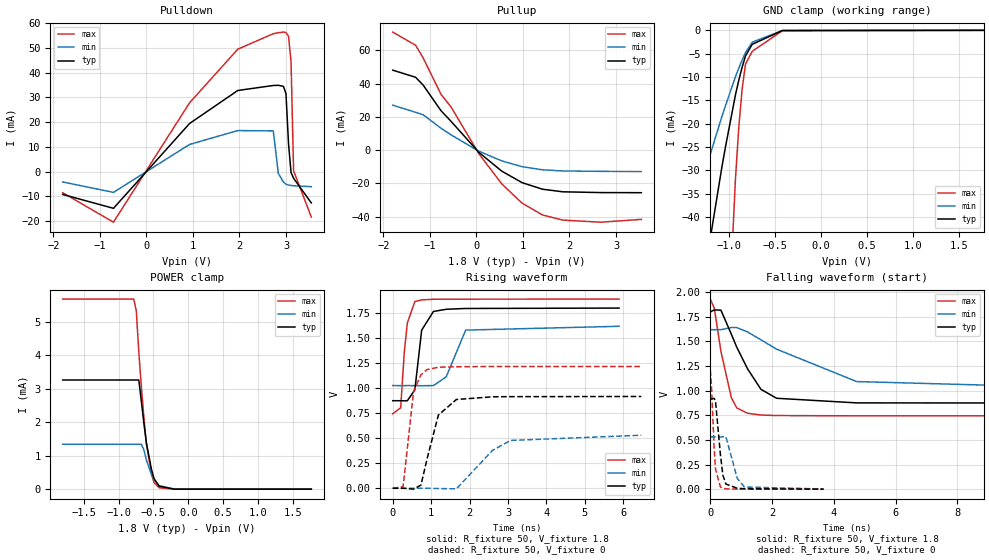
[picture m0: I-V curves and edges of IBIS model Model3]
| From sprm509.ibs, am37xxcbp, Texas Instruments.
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| Model based on original model for BQ18OMAPJTAGFBPBNOPM_SSBHV
|   Sub model FBPBNOPM_VJTAG_PUPD0_1P8
[model]   Model3
|[Input Load]   PI
|[Output Drive]
|Voltage   1.8V
|Mode   I/O
Model_type   I/O
Polarity   Non-Inverting
Enable   Active-Low
Vinl =  0.63
Vinh =  1.17
Cref =  15pF
Rref =  100.0000M
Vref =  0V
Vmeas =  0.9
C_comp   2.132351p   1.924211p   2.13513p
[Model Spec]
Vinl   0.63   0.567   0.6615
Vinh   1.17   1.053   1.2285
[Temperature Range]   25   125   -40
[Voltage Range]   1.8   1.62   1.89
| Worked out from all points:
|   slope of the pulldown table from 0 to 0.27 V, typ, clamps not added: 43.9 ohm
|   slope of the pullup table from 0 to 0.27 V, typ, clamps not added: 39.4 ohm
|   GND clamp passes 1 mA (typ) near -0.61 V on its own axis
|   POWER clamp passes 1 mA (typ) near -0.57 V on its own axis
|   rising waveform, R_fixture 50, V_fixture 1.8: 20-80 % time 174ps typ, 299ps min, 138ps max; typ from 0.875 V to 1.8 V
|   rising waveform, R_fixture 50, V_fixture 0: 20-80 % time 356ps typ, 727ps min, 202ps max; typ from 0 V to 0.917 V
|   falling waveform, R_fixture 50, V_fixture 1.8: 20-80 % time 893ps typ, 2.32ns min, 433ps max; typ from 1.8 V to 0.875 V
|   falling waveform, R_fixture 50, V_fixture 0: 20-80 % time 161ps typ, 254ps min, 107ps max; typ from 0.917 V to 0 V
[POWER_clamp]
-1.8V     3.257mA    1.34mA     5.672mA
-781.8mV  3.257mA    1.34mA     5.672mA
-745.5mV  3.257mA    1.34mA     5.328mA
-709.1mV  3.257mA    1.34mA     4.098mA
-672.7mV  2.624mA    1.34mA     3.055mA
-636.4mV  1.968mA    1.173mA    2.137mA
-600mV    1.377mA    868.1uA    1.344mA
-527.3mV  587.4uA    437.6uA    451.7uA
-490.9mV  316.3uA    276.5uA    197.1uA
-418.2mV  88.64uA    105.8uA    41.54uA
-200mV    475.8nA    2.17uA     80.97nA
1.764V    -1.497nA   -91.49nA   -1.523nA
[Pulldown]
-1.8V     -9.247mA   -4.208mA   -8.543mA
-709.1mV  -14.86mA   -8.413mA   -20.46mA
927.3mV   19.42mA    10.96mA    27.78mA
1.964V    32.76mA    16.57mA    49.44mA
2.727V    34.78mA    16.43mA    55.71mA
2.836V    34.85mA    -737.7uA   56.1mA
2.945V    34.44mA    -4.234mA   56.36mA
3V        31.5mA     -5.084mA   56.19mA
3.055V    11.24mA    -5.451mA   54.62mA
3.109V    -400.5uA   -5.627mA   44.41mA
3.164V    -2.725mA   -5.739mA   273.1uA
3.545V    -12.68mA   -6.104mA   -18.39mA
[Pullup]
-1.8V     48.03mA    26.96mA    70.92mA
-1.309V   43.76mA    22.71mA    63.01mA
-1.145V   39.05mA    21.21mA    55.39mA
-763.6mV  23.71mA    13.12mA    33.57mA
-545.5mV  17.24mA    9.103mA    25.87mA
54.55mV   -1.471mA   -757.8uA   -2.314mA
545.5mV   -12.73mA   -6.543mA   -20.39mA
981.8mV   -19.62mA   -10.01mA   -31.96mA
1.418V    -23.55mA   -11.89mA   -39.01mA
1.855V    -25.13mA   -12.59mA   -42.14mA
2.673V    -25.59mA   -12.83mA   -43.4mA
3.545V    -25.66mA   -12.97mA   -41.71mA
[GND_clamp]
-1.8V     -118.7mA   -65.68mA   -455.2mA
-1.509V   -82.25mA   -46.43mA   -309.2mA
-1.473V   -77.71mA   -44.04mA   -290.9mA
-1.073V   -29.16mA   -18.4mA    -94.41mA
-1.036V   -25.06mA   -16.19mA   -77.58mA
-927.3mV  -13.84mA   -9.958mA   -31.91mA
-890.9mV  -10.68mA   -8.097mA   -20.77mA
-854.5mV  -7.893mA   -6.365mA   -12.54mA
-818.2mV  -5.469mA   -4.76mA    -7.233mA
-745.5mV  -2.997mA   -2.543mA   -4.5mA
-418.2mV  -40.5uA    -36.87uA   -79.1uA
1.764V    1.429nA    674nA      9.916nA
[Ramp]
dV/dt_f  0.5758418/0.911812n   0.3703667/2.385807n   0.7118245/0.4335098n
dV/dt_r  0.5566153/0.3582418n  0.3226938/0.7356682n   0.737307/0.2022277n
R_load = 50
[Rising Waveform]
R_fixture = 50
V_fixture = 1.8
V_fixture_min = 1.62
V_fixture_max = 1.89
0s        874.6mV    1.026V     744.8mV
207ps     874.3mV    1.025V     803.4mV
303ps     873.3mV    1.025V     1.368V
381ps     874.5mV    1.026V     1.651V
576ps     982mV      1.025V     1.865V
753ps     1.579V     1.024V     1.882V
1.059ns   1.766V     1.026V     1.888V
1.392ns   1.788V     1.113V     1.889V
1.899ns   1.796V     1.58V      1.889V
5.889ns   1.8V       1.618V     1.89V
[Rising Waveform]
R_fixture = 50
V_fixture = 0
V_fixture_min = 0
V_fixture_max = 0
0s        -415.5uV   95.76uV    100.9uV
270ps     -15.58uV   -462.6uV   14.97mV
543ps     -9.198mV   102.6uV    967.3mV
735ps     31.95mV    84.12uV    1.133V
897ps     298.2mV    -138.1uV   1.186V
1.188ns   730.9mV    -2.996mV   1.209V
1.656ns   886.5mV    -6.236mV   1.214V
2.595ns   913.4mV    377.6mV    1.216V
3.06ns    915mV      477.4mV    1.216V
6.468ns   916.8mV    529.5mV    1.216V
[Falling Waveform]
R_fixture = 50
V_fixture = 1.8
V_fixture_min = 1.62
V_fixture_max = 1.89
0s        1.8V       1.62V      1.931V
132ps     1.821V     1.62V      1.837V
345ps     1.818V     1.62V      1.399V
681ps     1.575V     1.642V     930.9mV
855ps     1.444V     1.642V     825.8mV
1.206ns   1.223V     1.597V     771.1mV
1.641ns   1.014V     1.517V     753.1mV
2.148ns   923.3mV    1.422V     747.6mV
4.74ns    876.4mV    1.093V     745.1mV
12.37ns   875mV      1.027V     745.1mV
[Falling Waveform]
R_fixture = 50
V_fixture = 0
V_fixture_min = 0
V_fixture_max = 0
0s        917.4mV    531mV      1.208V
39ps      916.7mV    530.9mV    1.053V
123ps     922.1mV    531.4mV    430.4mV
168ps     899.4mV    531.5mV    206.8mV
327ps     354.6mV    530.6mV    23.66mV
408ps     141.6mV    531.2mV    8.146mV
507ps     51.78mV    533.1mV    3.467mV
873ps     9.006mV    109.3mV    866.7uV
1.107ns   4.717mV    22.08mV    439.3uV
3.669ns   273.6uV    1.624mV    2.674uV
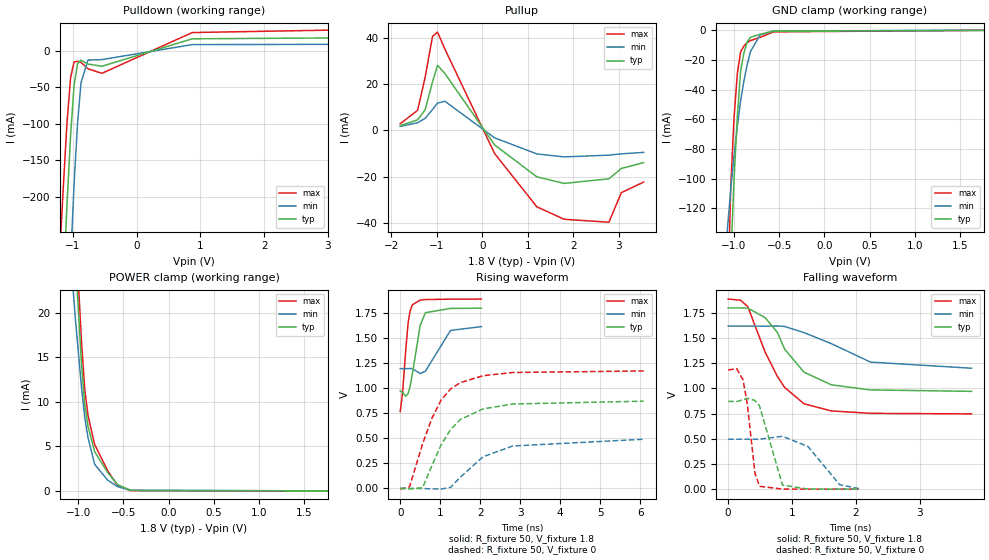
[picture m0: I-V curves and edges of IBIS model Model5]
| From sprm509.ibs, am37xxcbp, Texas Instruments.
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| Model based on original model for BQ1850OMAPSMART2HYFBPB_SSBHH
|   Sub model HYFBPB_H50_0_PUPD0_1P8
[model]   Model5
|[Input Load]   PI
|[Output Drive] LB0
|Voltage   1.8V
|Mode   I/O
Model_type   I/O
Polarity   Non-Inverting
Enable   Active-Low
Vinl =  0.63
Vinh =  1.17
Cref =  15pF
Rref =  100.0000M
Vref =  0V
Vmeas =  0.9
C_comp   1.383404p   1.221591p   1.559603p
[Model Spec]
Vinl   0.63   0.567   0.6615
Vinh   1.17   1.053   1.2285
[Temperature Range]   25   125   -40
[Voltage Range]   1.8   1.62   1.89
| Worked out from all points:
|   slope of the pulldown table from 0 to 0.27 V, typ, clamps not added: 35.5 ohm
|   slope of the pullup table from 0 to 0.27 V, typ, clamps not added: 42.9 ohm
|   GND clamp passes 1 mA (typ) near -0.61 V on its own axis
|   POWER clamp passes 1 mA (typ) near -0.60 V on its own axis
|   rising waveform, R_fixture 50, V_fixture 1.8: 20-80 % time 201ps typ, 347ps min, 136ps max; typ from 0.971 V to 1.8 V
|   rising waveform, R_fixture 50, V_fixture 0: 20-80 % time 792ps typ, 1.03ns min, 728ps max; typ from 0.001 V to 0.87 V
|   falling waveform, R_fixture 50, V_fixture 1.8: 20-80 % time 555ps typ, 808ps min, 522ps max; typ from 1.8 V to 0.971 V
|   falling waveform, R_fixture 50, V_fixture 0: 20-80 % time 186ps typ, 353ps min, 124ps max; typ from 0.872 V to 0 V
[POWER_clamp]
-1.8V     290.9mA    160.5mA    340.8mA
-1.109V   45.77mA    30.42mA    51.16mA
-1.073V   35.98mA    25mA       40.42mA
-1.036V   26.91mA    19.86mA    30.73mA
-963.6mV  14.2mA     11.6mA     16.73mA
-927.3mV  9.664mA    8.209mA    11.37mA
-890.9mV  7.224mA    5.944mA    8.437mA
-818.2mV  4.412mA    2.986mA    5.219mA
-672.7mV  2.045mA    1.194mA    2.238mA
-563.6mV  702.5uA    479.8uA    586.6uA
-418.2mV  58.7uA     73.5uA     24.66uA
1.764V    -856.1pA   -69.76nA   -985.3pA
[Pulldown]
-1.8V     -1.423A    -2.058A    -1.157A
-1.2V     -415.4mA   -653.2mA   -267mA
-1.145V   -309.6mA   -525.9mA   -177.9mA
-1.091V   -207.6mA   -402.8mA   -96.73mA
-1.036V   -115.8mA   -286.9mA   -37.04mA
-981.8mV  -48.02mA   -183.2mA   -15.64mA
-927.3mV  -18.04mA   -99.43mA   -14.72mA
-872.7mV  -13.22mA   -44mA      -16.16mA
-763.6mV  -18.5mA    -13.02mA   -24.96mA
-545.5mV  -21.5mA    -12.44mA   -31.16mA
872.7mV   16.04mA    8.112mA    24.59mA
3.545V    17.47mA    8.568mA    28.69mA
[Pullup]
-1.8V     2.003mA    1.674mA    2.831mA
-1.418V   4.544mA    3.255mA    8.658mA
-1.255V   8.731mA    5.125mA    22.8mA
-1.091V   20.98mA    8.984mA    40.62mA
-981.8mV  28.13mA    11.78mA    42.49mA
-818.2mV  24.52mA    12.54mA    35.08mA
272.7mV   -6.354mA   -3.271mA   -10.08mA
1.2V      -20.15mA   -10.23mA   -33.12mA
1.8V      -22.99mA   -11.52mA   -38.52mA
2.782V    -21mA      -10.76mA   -39.77mA
3.055V    -16.52mA   -10.21mA   -26.99mA
3.545V    -13.98mA   -9.552mA   -22.39mA
[GND_clamp]
-1.8V     -2.709A    -1.157A    -3.075A
-1.073V   -228.7mA   -133.6mA   -187.2mA
-1.036V   -154.6mA   -106.9mA   -104.7mA
-1V       -100.4mA   -84.69mA   -59.09mA
-963.6mV  -57.98mA   -64.82mA   -29.02mA
-927.3mV  -27.21mA   -47.25mA   -14.49mA
-890.9mV  -15.32mA   -34.13mA   -10.63mA
-854.5mV  -7.819mA   -23.14mA   -8.114mA
-818.2mV  -4.712mA   -14.27mA   -6.938mA
-709.1mV  -2.652mA   -2.932mA   -4.656mA
-563.6mV  -543.1uA   -385.8uA   -1.041mA
1.764V    64.75pA    408.4nA    3.013nA
[Ramp]
dV/dt_f  0.4979139/0.5554967n  0.2555007/0.8315997n  0.6868076/0.5222809n
dV/dt_r  0.5299615/0.7945006n  0.3005771/1.056231n   0.713833/0.7303357n
R_load = 50
[Rising Waveform]
R_fixture = 50
V_fixture = 1.8
V_fixture_min = 1.62
V_fixture_max = 1.89
0s        970.8mV    1.195V     767.2mV
58.4ps    958.6mV    1.195V     955.3mV
140.8ps   918.2mV    1.195V     1.396V
198.4ps   947.6mV    1.195V     1.655V
244ps     1.013V     1.196V     1.767V
304ps     1.144V     1.194V     1.832V
500ps     1.629V     1.146V     1.879V
629.6ps   1.753V     1.169V     1.884V
1.257ns   1.796V     1.576V     1.888V
2.031ns   1.798V     1.614V     1.889V
[Rising Waveform]
R_fixture = 50
V_fixture = 0
V_fixture_min = 0
V_fixture_max = 0
0s        1.189mV    179.9uV    -7.937mV
232.8ps   -5.717mV   -523.5uV   15.19mV
558.4ps   5.892mV    -1.39mV    443.4mV
791.2ps   226.1mV    -5.048mV   698.1mV
1.024ns   435.1mV    -6.39mV    882.6mV
1.259ns   586.7mV    10.04mV    991.5mV
1.503ns   687mV      111.1mV    1.055V
2.069ns   792.4mV    315.1mV    1.124V
2.813ns   841.8mV    422.9mV    1.156V
6.089ns   870.1mV    490.3mV    1.172V
[Falling Waveform]
R_fixture = 50
V_fixture = 1.8
V_fixture_min = 1.62
V_fixture_max = 1.89
0s        1.8V       1.62V      1.888V
192ps     1.8V       1.62V      1.877V
307.2ps   1.798V     1.62V      1.813V
576ps     1.705V     1.619V     1.364V
768ps     1.559V     1.621V     1.122V
883.2ps   1.391V     1.616V     1.011V
1.186ns   1.162V     1.555V     848.2mV
1.615ns   1.036V     1.445V     776.9mV
2.227ns   985.6mV    1.262V     753.1mV
3.808ns   971.5mV    1.201V     747.4mV
[Falling Waveform]
R_fixture = 50
V_fixture = 0
V_fixture_min = 0
V_fixture_max = 0
0s        871.7mV    495.8mV    1.184V
133.6ps   870.4mV    496.1mV    1.196V
233.6ps   888.2mV    496.5mV    1.085V
300.8ps   903.1mV    496.5mV    840.1mV
418.4ps   880.8mV    496.2mV    160.2mV
490.4ps   827.7mV    495.9mV    28.5mV
849.6ps   40.34mV    525mV      1.053mV
1.247ns   1.433mV    424.4mV    329.7uV
1.746ns   394.4uV    44.01mV    85.13uV
2.046ns   244.6uV    5.687mV    44.99uV
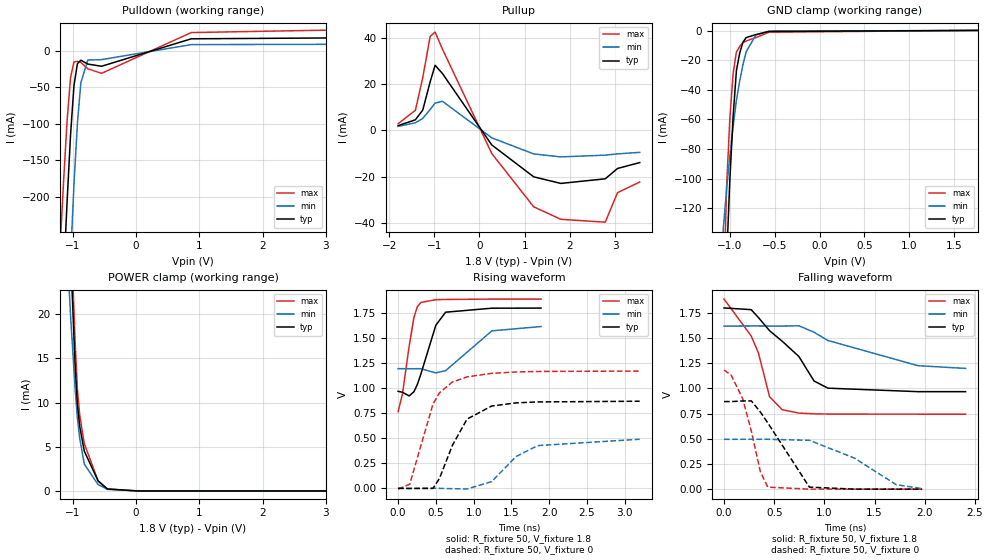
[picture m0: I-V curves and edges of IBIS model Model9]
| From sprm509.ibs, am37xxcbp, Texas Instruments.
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| Model based on original model for BQ1850OMAPSMART2HYFBPB_SSBHH
|   Sub model T2HYFBPB_H50_1_PD1_1P8
[model]   Model9
|[Input Load]   PD
|[Output Drive] LB1
|Voltage   1.8V
|Mode   I/O
Model_type   I/O
Polarity   Non-Inverting
Enable   Active-Low
Vinl =  0.63
Vinh =  1.17
Cref =  15pF
Rref =  100.0000M
Vref =  0V
Vmeas =  0.9
C_comp   1.383404p   1.221591p   1.559603p
[Model Spec]
Vinl   0.63   0.567   0.6615
Vinh   1.17   1.053   1.2285
[Temperature Range]   25   125   -40
[Voltage Range]   1.8   1.62   1.89
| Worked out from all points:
|   slope of the pulldown table from 0 to 0.27 V, typ, clamps not added: 35.5 ohm
|   slope of the pullup table from 0 to 0.27 V, typ, clamps not added: 42.9 ohm
|   GND clamp passes 1 mA (typ) near -0.60 V on its own axis
|   POWER clamp passes 1 mA (typ) near -0.59 V on its own axis
|   rising waveform, R_fixture 50, V_fixture 1.8: 20-80 % time 204ps typ, 356ps min, 131ps max; typ from 0.967 V to 1.8 V
|   rising waveform, R_fixture 50, V_fixture 0: 20-80 % time 331ps typ, 446ps min, 307ps max; typ from 0 V to 0.868 V
|   falling waveform, R_fixture 50, V_fixture 1.8: 20-80 % time 455ps typ, 839ps min, 249ps max; typ from 1.8 V to 0.967 V
|   falling waveform, R_fixture 50, V_fixture 0: 20-80 % time 311ps typ, 590ps min, 178ps max; typ from 0.869 V to 0 V
[POWER_clamp]
-1.8V     290.9mA    160.5mA    340.9mA
-1.109V   45.82mA    30.44mA    51.27mA
-1.073V   36.03mA    25.02mA    40.54mA
-1.036V   26.98mA    19.88mA    30.85mA
-963.6mV  14.28mA    11.63mA    16.86mA
-927.3mV  9.744mA    8.243mA    11.5mA
-890.9mV  7.306mA    5.982mA    8.573mA
-818.2mV  4.497mA    3.03mA     5.358mA
-600mV    1.141mA    717.7uA    1.118mA
-454.5mV  222.1uA    181.4uA    220.5uA
18.18mV   0A         0A         0A
3.6V      0A         0A         0A
[Pulldown]
-1.8V     -1.423A    -2.058A    -1.157A
-1.2V     -415.4mA   -653.2mA   -267mA
-1.145V   -309.6mA   -525.9mA   -177.9mA
-1.091V   -207.6mA   -402.8mA   -96.73mA
-1.036V   -115.8mA   -286.9mA   -37.04mA
-981.8mV  -48.02mA   -183.2mA   -15.64mA
-927.3mV  -18.04mA   -99.43mA   -14.72mA
-872.7mV  -13.22mA   -44mA      -16.16mA
-763.6mV  -18.5mA    -13.02mA   -24.96mA
-545.5mV  -21.5mA    -12.44mA   -31.16mA
872.7mV   16.04mA    8.112mA    24.59mA
3.545V    17.47mA    8.568mA    28.69mA
[Pullup]
-1.8V     2.003mA    1.674mA    2.831mA
-1.418V   4.544mA    3.255mA    8.658mA
-1.255V   8.732mA    5.125mA    22.8mA
-1.091V   20.98mA    8.984mA    40.62mA
-981.8mV  28.13mA    11.78mA    42.49mA
-818.2mV  24.52mA    12.54mA    35.08mA
272.7mV   -6.354mA   -3.271mA   -10.08mA
1.2V      -20.15mA   -10.23mA   -33.12mA
1.8V      -22.99mA   -11.52mA   -38.52mA
2.782V    -21mA      -10.76mA   -39.77mA
3.055V    -16.52mA   -10.21mA   -26.99mA
3.545V    -13.98mA   -9.552mA   -22.39mA
[GND_clamp]
-1.8V     -2.709A    -1.157A    -3.075A
-1.073V   -228.8mA   -133.6mA   -187.2mA
-1.036V   -154.6mA   -106.9mA   -104.7mA
-1V       -100.5mA   -84.7mA    -59.13mA
-963.6mV  -58.02mA   -64.83mA   -29.07mA
-927.3mV  -27.25mA   -47.26mA   -14.55mA
-890.9mV  -15.37mA   -34.15mA   -10.71mA
-854.5mV  -7.875mA   -23.16mA   -8.201mA
-818.2mV  -4.773mA   -14.29mA   -7.034mA
-709.1mV  -2.717mA   -2.962mA   -4.752mA
-563.6mV  -605.1uA   -417.8uA   -1.132mA
1.764V    97.78uA    54.84uA    156.4uA
[Ramp]
dV/dt_f  0.5001686/0.4553889n  0.2575128/0.8512445n  0.6868262/0.249453n
dV/dt_r  0.5276225/0.3319691n  0.3009445/0.4597019n  0.7092906/0.3073289n
R_load = 50
[Rising Waveform]
R_fixture = 50
V_fixture = 1.8
V_fixture_min = 1.62
V_fixture_max = 1.89
0s        967.1mV    1.193V     763.6mV
56.8ps    957.6mV    1.193V     940.2mV
145.6ps   921.2mV    1.192V     1.414V
209.6ps   963mV      1.192V     1.706V
255.2ps   1.037V     1.193V     1.811V
300.8ps   1.138V     1.192V     1.853V
499.2ps   1.626V     1.151V     1.881V
628.8ps   1.756V     1.173V     1.883V
1.241ns   1.796V     1.57V      1.887V
1.892ns   1.797V     1.613V     1.887V
[Rising Waveform]
R_fixture = 50
V_fixture = 0
V_fixture_min = 0
V_fixture_max = 0
0s        -353.2uV   195.7uV    -8.796mV
153.6ps   -2.176mV   -469.3uV   41mV
460.8ps   -1.188mV   920.1uV    838.5mV
545.6ps   95.64mV    -693.4uV   950.8mV
719.2ps   429.7mV    -4.108mV   1.06V
912.8ps   690.3mV    -6.914mV   1.111V
1.238ns   820.2mV    66.63mV    1.146V
1.562ns   851.7mV    317mV      1.16V
1.847ns   861.2mV    425.7mV    1.165V
3.198ns   868.2mV    489mV      1.169V
[Falling Waveform]
R_fixture = 50
V_fixture = 1.8
V_fixture_min = 1.62
V_fixture_max = 1.89
0s        1.798V     1.618V     1.886V
270.4ps   1.781V     1.619V     1.52V
342.4ps   1.703V     1.619V     1.352V
453.6ps   1.572V     1.618V     917.3mV
579.2ps   1.468V     1.618V     788.5mV
745.6ps   1.316V     1.621V     754.9mV
896.8ps   1.073V     1.557V     747.5mV
1.035ns   1.002V     1.475V     745.3mV
1.932ns   967.4mV    1.225V     744mV
2.406ns   967.3mV    1.198V     744mV
[Falling Waveform]
R_fixture = 50
V_fixture = 0
V_fixture_min = 0
V_fixture_max = 0
0s        869.2mV    494.6mV    1.182V
71.2ps    868.7mV    494.3mV    1.131V
185.6ps   875.3mV    495.1mV    898.6mV
272ps     875.6mV    495.2mV    576.5mV
361.6ps   766.2mV    495.1mV    173.7mV
436ps     657.2mV    494.9mV    20.33mV
850.4ps   20.14mV    484.9mV    68.71uV
1.298ns   353.1uV    308.4mV    3.302uV
1.716ns   142.3uV    44.04mV    927.7nV
1.974ns   110.2uV    5.708mV    756.2nV
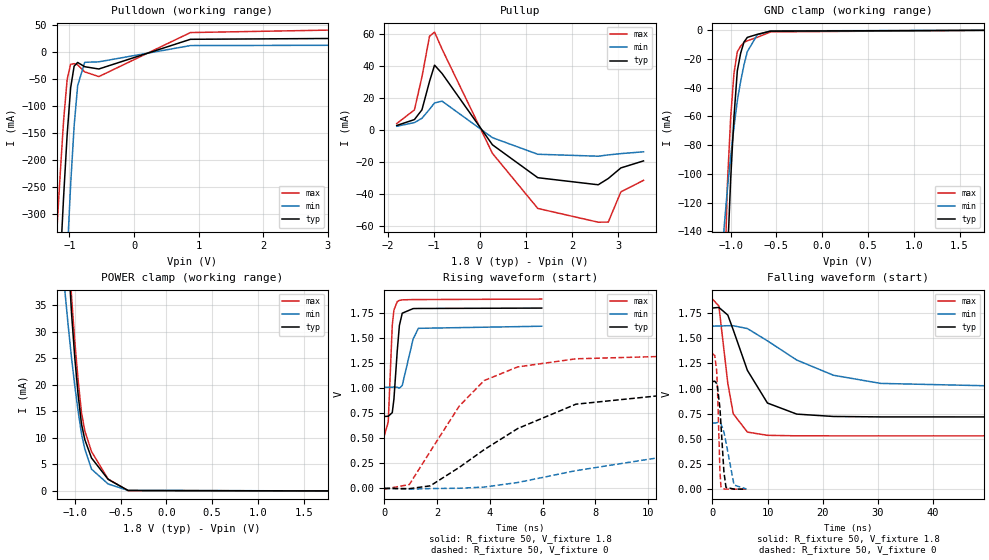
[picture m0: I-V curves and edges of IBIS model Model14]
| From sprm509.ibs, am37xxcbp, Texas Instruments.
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| Model based on original model for BQ18OMAPSMART1HYFBPBNOPM_SSBHH
|   Sub model PM_HS00L00_PUPD0_1P8
[model]   Model14
|[Input Load]   PI
|[Output Drive] SC00LB00
|Voltage   1.8V
|Mode   I/O
Model_type   I/O
Polarity   Non-Inverting
Enable   Active-Low
Vinl =  0.63
Vinh =  1.17
Cref =  15pF
Rref =  100.0000M
Vref =  0V
Vmeas =  0.9
C_comp   1.410688p   1.256095p   1.577871p
[Model Spec]
Vinl   0.63   0.567   0.6615
Vinh   1.17   1.053   1.2285
[Temperature Range]   25   125   -40
[Voltage Range]   1.8   1.62   1.89
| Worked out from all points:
|   slope of the pulldown table from 0 to 0.27 V, typ, clamps not added: 24.3 ohm
|   slope of the pullup table from 0 to 0.27 V, typ, clamps not added: 29.7 ohm
|   GND clamp passes 1 mA (typ) near -0.60 V on its own axis
|   POWER clamp passes 1 mA (typ) near -0.56 V on its own axis
|   rising waveform, R_fixture 50, V_fixture 1.8: 20-80 % time 177ps typ, 306ps min, 123ps max; typ from 0.718 V to 1.8 V
|   rising waveform, R_fixture 50, V_fixture 0: 20-80 % time 4.61ns typ, 10.6ns min, 2.29ns max; typ from 0.001 V to 1.07 V
|   falling waveform, R_fixture 50, V_fixture 1.8: 20-80 % time 4.9ns typ, 12.6ns min, 1.98ns max; typ from 1.8 V to 0.718 V
|   falling waveform, R_fixture 50, V_fixture 0: 20-80 % time 732ps typ, 1.23ns min, 444ps max; typ from 1.07 V to 0 V
[POWER_clamp]
-1.8V     362.5mA    191.4mA    412.8mA
-1.109V   56.69mA    37.71mA    60.38mA
-1.073V   44.6mA     31.22mA    47.8mA
-1.036V   33.44mA    25.04mA    36.59mA
-1V       24.98mA    19.72mA    28.06mA
-963.6mV  18.03mA    14.96mA    20.78mA
-927.3mV  12.59mA    10.77mA    14.74mA
-890.9mV  9.653mA    7.899mA    11.31mA
-818.2mV  6.214mA    4.114mA    7.414mA
-636.4mV  2.183mA    1.307mA    2.238mA
-418.2mV  83.85uA    105.2uA    35.14uA
1.764V    -1.228nA   -79.12nA   -1.453nA
[Pulldown]
-1.8V     -1.718A    -2.61A     -1.406A
-1.2V     -527.4mA   -844.5mA   -339.9mA
-1.145V   -396mA     -683.1mA   -229.1mA
-1.091V   -269mA     -526.7mA   -127.5mA
-1.036V   -153.6mA   -378.9mA   -51.17mA
-981.8mV  -66.34mA   -245.6mA   -22.67mA
-927.3mV  -26mA      -136.2mA   -21.54mA
-872.7mV  -19.34mA   -61.98mA   -23.69mA
-763.6mV  -27.2mA    -19.05mA   -36.72mA
-545.5mV  -31.39mA   -18.17mA   -45.46mA
872.7mV   23.46mA    11.88mA    35.92mA
3.545V    25.34mA    12.51mA    41.58mA
[Pullup]
-1.8V     2.903mA    2.423mA    4.112mA
-1.418V   6.595mA    4.711mA    12.64mA
-1.255V   12.69mA    7.42mA     33.23mA
-1.091V   30.4mA     13mA       58.69mA
-981.8mV  40.63mA    17.02mA    61.3mA
-818.2mV  35.38mA    18.12mA    50.59mA
272.7mV   -9.18mA    -4.728mA   -14.55mA
1.255V    -29.75mA   -15.09mA   -48.97mA
2.564V    -34.17mA   -16.31mA   -57.57mA
2.782V    -30.25mA   -15.5mA    -57.48mA
3.055V    -23.63mA   -14.68mA   -38.61mA
3.545V    -19.25mA   -13.56mA   -31.41mA
[GND_clamp]
-1.8V     -2.82A     -1.192A    -3.165A
-1.073V   -235.7mA   -138.4mA   -192.1mA
-1.036V   -159.5mA   -110.8mA   -107.5mA
-1V       -103.8mA   -87.85mA   -60.67mA
-963.6mV  -60mA      -67.28mA   -29.8mA
-927.3mV  -28.21mA   -49.08mA   -14.9mA
-890.9mV  -15.9mA    -35.48mA   -10.99mA
-854.5mV  -8.138mA   -24.07mA   -8.449mA
-818.2mV  -4.924mA   -14.85mA   -7.266mA
-709.1mV  -2.784mA   -3.064mA   -4.883mA
-563.6mV  -570.2uA   -404.5uA   -1.092mA
1.764V    -11.02pA   583.5nA    3.035nA
[Ramp]
dV/dt_f  0.6529254/4.909012n   0.369178/12.66382n   0.8193473/1.982531n
dV/dt_r  0.6500695/4.62838n   0.3999016/10.70502n   0.8221439/2.293936n
R_load = 50
[Rising Waveform]
R_fixture = 50
V_fixture = 1.8
V_fixture_min = 1.62
V_fixture_max = 1.89
0s        717.7mV    1.009V     531.6mV
144ps     719.8mV    1.009V     662.3mV
297ps     755.8mV    1.01V      1.626V
360ps     891.1mV    1.011V     1.78V
486ps     1.373V     1.009V     1.864V
567ps     1.625V     1V         1.876V
675ps     1.748V     1.027V     1.881V
1.089ns   1.794V     1.491V     1.884V
1.287ns   1.795V     1.597V     1.884V
5.967ns   1.799V     1.618V     1.889V
[Rising Waveform]
R_fixture = 50
V_fixture = 0
V_fixture_min = 0
V_fixture_max = 0
0s        606.6uV    68.88uV    -7.786mV
945ps     -2.577mV   -7.735mV   38.64mV
1.737ns   25.25mV    -1.769mV   368.8mV
2.835ns   208.8mV    1.328mV    819.8mV
3.78ns    386mV      13.14mV    1.076V
5.058ns   597.5mV    58.59mV    1.212V
7.263ns   840mV      176.9mV    1.293V
14.18ns   1.025V     462.1mV    1.343V
23.36ns   1.06V      595.3mV    1.348V
67.52ns   1.067V     655.8mV    1.349V
[Falling Waveform]
R_fixture = 50
V_fixture = 1.8
V_fixture_min = 1.62
V_fixture_max = 1.89
0s        1.8V       1.62V      1.889V
1.179ns   1.806V     1.621V     1.821V
2.799ns   1.73V      1.624V     1.052V
3.789ns   1.582V     1.624V     748.8mV
6.345ns   1.181V     1.596V     567.3mV
9.981ns   855.9mV    1.474V     535.1mV
15.29ns   745.9mV    1.283V     530.1mV
21.94ns   722.4mV    1.132V     529.8mV
30.49ns   718.1mV    1.051V     529.8mV
62.99ns   717.6mV    1.011V     529.8mV
[Falling Waveform]
R_fixture = 50
V_fixture = 0
V_fixture_min = 0
V_fixture_max = 0
0s        1.068V     657.3mV    1.348V
432ps     1.073V     657.1mV    1.328V
765ps     1.051V     659mV      1.186V
927ps     1.018V     662.6mV    999mV
1.377ns   802.6mV    661mV      173.7mV
1.557ns   642.4mV    649.1mV    24.2mV
2.097ns   170.7mV    567.1mV    1.354mV
2.466ns   18.57mV    467.6mV    544.8uV
3.933ns   752.5uV    40.91mV    171.8uV
6.147ns   247.4uV    1.631mV    64.87uV
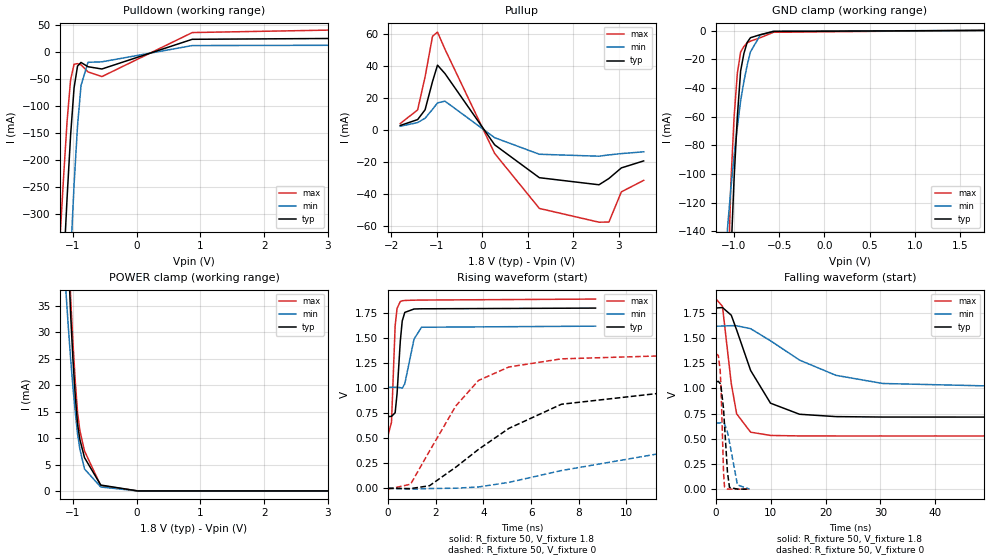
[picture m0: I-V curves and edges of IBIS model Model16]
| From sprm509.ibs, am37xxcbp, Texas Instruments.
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| Model based on original model for BQ18OMAPSMART1HYFBPBNOPM_SSBHH
|   Sub model NOPM_HS00L00_PD1_1P8
[model]   Model16
|[Input Load]   PD
|[Output Drive] SC00LB00
|Voltage   1.8V
|Mode   I/O
Model_type   I/O
Polarity   Non-Inverting
Enable   Active-Low
Vinl =  0.63
Vinh =  1.17
Cref =  15pF
Rref =  100.0000M
Vref =  0V
Vmeas =  0.9
C_comp   1.410688p   1.256095p   1.577871p
[Model Spec]
Vinl   0.63   0.567   0.6615
Vinh   1.17   1.053   1.2285
[Temperature Range]   25   125   -40
[Voltage Range]   1.8   1.62   1.89
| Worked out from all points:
|   slope of the pulldown table from 0 to 0.27 V, typ, clamps not added: 24.3 ohm
|   slope of the pullup table from 0 to 0.27 V, typ, clamps not added: 29.7 ohm
|   GND clamp passes 1 mA (typ) near -0.60 V on its own axis
|   POWER clamp passes 1 mA (typ) near -0.55 V on its own axis
|   rising waveform, R_fixture 50, V_fixture 1.8: 20-80 % time 178ps typ, 314ps min, 124ps max; typ from 0.715 V to 1.8 V
|   rising waveform, R_fixture 50, V_fixture 0: 20-80 % time 4.62ns typ, 10.6ns min, 2.3ns max; typ from 0.001 V to 1.06 V
|   falling waveform, R_fixture 50, V_fixture 1.8: 20-80 % time 4.89ns typ, 12.6ns min, 1.98ns max; typ from 1.8 V to 0.715 V
|   falling waveform, R_fixture 50, V_fixture 0: 20-80 % time 731ps typ, 1.23ns min, 444ps max; typ from 1.06 V to 0 V
[POWER_clamp]
-1.8V     362.5mA    191.4mA    412.8mA
-1.109V   56.75mA    37.73mA    60.5mA
-1.073V   44.66mA    31.25mA    47.93mA
-1.036V   33.51mA    25.07mA    36.73mA
-1V       25.06mA    19.75mA    28.2mA
-963.6mV  18.11mA    14.99mA    20.92mA
-927.3mV  12.68mA    10.81mA    14.88mA
-890.9mV  9.743mA    7.94mA     11.46mA
-818.2mV  6.308mA    4.161mA    7.567mA
-563.6mV  1.112mA    743.5uA    1.008mA
18.18mV   0A         0A         0A
3.6V      0A         0A         0A
[Pulldown]
-1.8V     -1.718A    -2.61A     -1.406A
-1.2V     -527.4mA   -844.5mA   -339.9mA
-1.145V   -396mA     -683.1mA   -229.1mA
-1.091V   -269mA     -526.7mA   -127.5mA
-1.036V   -153.6mA   -378.9mA   -51.17mA
-981.8mV  -66.33mA   -245.6mA   -22.67mA
-927.3mV  -26mA      -136.2mA   -21.54mA
-872.7mV  -19.34mA   -61.98mA   -23.69mA
-763.6mV  -27.2mA    -19.05mA   -36.72mA
-545.5mV  -31.39mA   -18.17mA   -45.46mA
872.7mV   23.46mA    11.88mA    35.92mA
3.545V    25.34mA    12.51mA    41.58mA
[Pullup]
-1.8V     2.903mA    2.423mA    4.112mA
-1.418V   6.595mA    4.711mA    12.64mA
-1.255V   12.69mA    7.42mA     33.24mA
-1.091V   30.4mA     13mA       58.69mA
-981.8mV  40.63mA    17.02mA    61.3mA
-818.2mV  35.38mA    18.12mA    50.59mA
272.7mV   -9.18mA    -4.728mA   -14.55mA
1.255V    -29.75mA   -15.09mA   -48.97mA
2.564V    -34.17mA   -16.31mA   -57.57mA
2.782V    -30.25mA   -15.5mA    -57.48mA
3.055V    -23.63mA   -14.68mA   -38.61mA
3.545V    -19.25mA   -13.56mA   -31.41mA
[GND_clamp]
-1.8V     -2.82A     -1.192A    -3.165A
-1.073V   -235.8mA   -138.4mA   -192.1mA
-1.036V   -159.6mA   -110.8mA   -107.6mA
-1V       -103.8mA   -87.86mA   -60.72mA
-963.6mV  -60.04mA   -67.29mA   -29.85mA
-927.3mV  -28.26mA   -49.1mA    -14.96mA
-890.9mV  -15.95mA   -35.5mA    -11.07mA
-854.5mV  -8.196mA   -24.09mA   -8.539mA
-818.2mV  -4.988mA   -14.87mA   -7.364mA
-709.1mV  -2.851mA   -3.095mA   -4.982mA
-563.6mV  -633.9uA   -437.8uA   -1.185mA
1.764V    107.4uA    58.81uA    171.2uA
[Ramp]
dV/dt_f  0.6528464/4.899765n   0.3694175/12.65921n   0.8188804/1.978997n
dV/dt_r  0.6486425/4.639533n   0.3990339/10.71497n   0.8205116/2.303422n
R_load = 50
[Rising Waveform]
R_fixture = 50
V_fixture = 1.8
V_fixture_min = 1.62
V_fixture_max = 1.89
0s        715.5mV    1.007V     529.9mV
144ps     717.6mV    1.007V     659.9mV
297ps     753.4mV    1.007V     1.621V
378ps     946.5mV    1.009V     1.795V
513ps     1.468V     1.004V     1.862V
594ps     1.669V     998.2mV    1.87V
702ps     1.754V     1.043V     1.873V
1.089ns   1.788V     1.488V     1.876V
1.404ns   1.79V      1.606V     1.877V
8.703ns   1.797V     1.617V     1.887V
[Rising Waveform]
R_fixture = 50
V_fixture = 0
V_fixture_min = 0
V_fixture_max = 0
0s        792uV      63.68uV    -8.213mV
945ps     -2.47mV    -7.902mV   41.09mV
1.737ns   26.06mV    -1.726mV   371.1mV
2.844ns   211.5mV    1.431mV    822.2mV
3.789ns   387.7mV    13.53mV    1.075V
5.067ns   597.8mV    59.32mV    1.21V
7.272ns   838.5mV    177.5mV    1.291V
14.18ns   1.022V     461.1mV    1.34V
23.36ns   1.058V     593.9mV    1.346V
67.51ns   1.065V     654.3mV    1.346V
[Falling Waveform]
R_fixture = 50
V_fixture = 1.8
V_fixture_min = 1.62
V_fixture_max = 1.89
0s        1.798V     1.618V     1.887V
1.179ns   1.803V     1.619V     1.816V
2.79ns    1.727V     1.623V     1.049V
3.771ns   1.58V      1.622V     747.8mV
6.327ns   1.178V     1.593V     565.6mV
9.954ns   853.5mV    1.473V     533.4mV
15.26ns   743.6mV    1.281V     528.5mV
21.91ns   720.2mV    1.13V      528.1mV
30.45ns   715.9mV    1.049V     528.1mV
62.92ns   715.4mV    1.008V     528.1mV
[Falling Waveform]
R_fixture = 50
V_fixture = 0
V_fixture_min = 0
V_fixture_max = 0
0s        1.065V     655.9mV    1.346V
432ps     1.07V      655.7mV    1.326V
765ps     1.048V     657.5mV    1.182V
927ps     1.015V     661.1mV    993.3mV
1.377ns   798.7mV    659.6mV    168.7mV
1.557ns   638.2mV    647.7mV    21.79mV
2.097ns   167.7mV    565.5mV    1.29mV
2.466ns   17.3mV     465.8mV    536.4uV
3.924ns   742.5uV    41.52mV    172.1uV
6.111ns   249.4uV    1.634mV    65.93uV
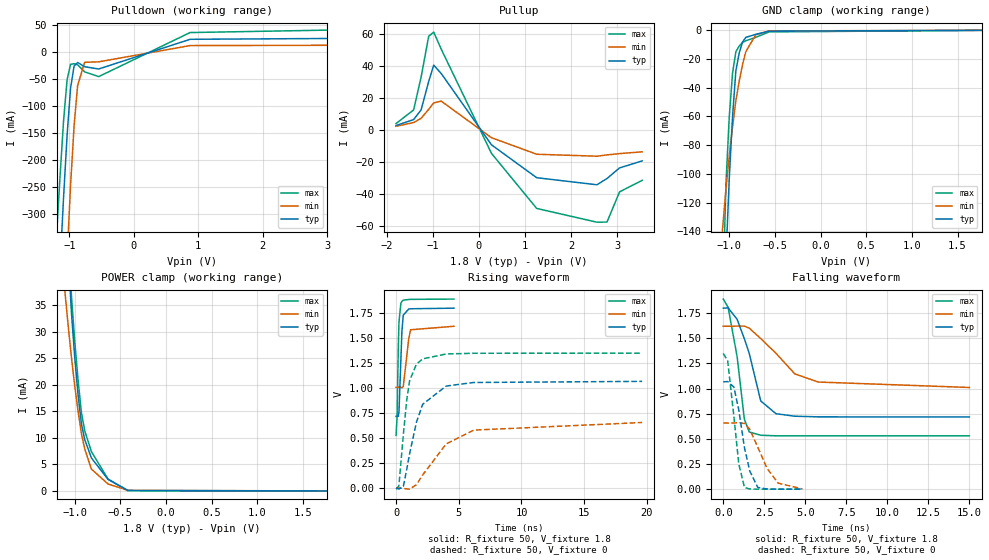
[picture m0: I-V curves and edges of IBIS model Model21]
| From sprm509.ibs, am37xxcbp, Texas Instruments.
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| Model based on original model for BQ18OMAPSMART1HYFBPBNOPM_SSBHH
|   Sub model PM_HS01L10_PUPD0_1P8
[model]   Model21
|[Input Load]   PI
|[Output Drive] SC01LB10
|Voltage   1.8V
|Mode   I/O
Model_type   I/O
Polarity   Non-Inverting
Enable   Active-Low
Vinl =  0.63
Vinh =  1.17
Cref =  15pF
Rref =  100.0000M
Vref =  0V
Vmeas =  0.9
C_comp   1.410688p   1.256095p   1.577871p
[Model Spec]
Vinl   0.63   0.567   0.6615
Vinh   1.17   1.053   1.2285
[Temperature Range]   25   125   -40
[Voltage Range]   1.8   1.62   1.89
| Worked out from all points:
|   slope of the pulldown table from 0 to 0.27 V, typ, clamps not added: 24.3 ohm
|   slope of the pullup table from 0 to 0.27 V, typ, clamps not added: 29.7 ohm
|   GND clamp passes 1 mA (typ) near -0.60 V on its own axis
|   POWER clamp passes 1 mA (typ) near -0.56 V on its own axis
|   rising waveform, R_fixture 50, V_fixture 1.8: 20-80 % time 175ps typ, 300ps min, 124ps max; typ from 0.718 V to 1.8 V
|   rising waveform, R_fixture 50, V_fixture 0: 20-80 % time 1.3ns typ, 2.86ns min, 688ps max; typ from 0 V to 1.07 V
|   falling waveform, R_fixture 50, V_fixture 1.8: 20-80 % time 1.1ns typ, 2.21ns min, 682ps max; typ from 1.8 V to 0.718 V
|   falling waveform, R_fixture 50, V_fixture 0: 20-80 % time 683ps typ, 1.12ns min, 501ps max; typ from 1.07 V to 0 V
[POWER_clamp]
-1.8V     362.5mA    191.4mA    412.8mA
-1.109V   56.69mA    37.71mA    60.38mA
-1.073V   44.6mA     31.22mA    47.8mA
-1.036V   33.44mA    25.04mA    36.59mA
-1V       24.98mA    19.72mA    28.06mA
-963.6mV  18.03mA    14.96mA    20.78mA
-927.3mV  12.59mA    10.77mA    14.74mA
-890.9mV  9.653mA    7.899mA    11.31mA
-818.2mV  6.214mA    4.114mA    7.414mA
-636.4mV  2.183mA    1.307mA    2.238mA
-418.2mV  83.85uA    105.2uA    35.14uA
1.764V    -1.228nA   -79.12nA   -1.453nA
[Pulldown]
-1.8V     -1.718A    -2.61A     -1.406A
-1.2V     -527.4mA   -844.5mA   -339.9mA
-1.145V   -396mA     -683.1mA   -229.1mA
-1.091V   -269mA     -526.7mA   -127.5mA
-1.036V   -153.6mA   -378.9mA   -51.17mA
-981.8mV  -66.34mA   -245.6mA   -22.67mA
-927.3mV  -26mA      -136.2mA   -21.54mA
-872.7mV  -19.34mA   -61.98mA   -23.69mA
-763.6mV  -27.2mA    -19.05mA   -36.72mA
-545.5mV  -31.39mA   -18.17mA   -45.46mA
872.7mV   23.46mA    11.88mA    35.92mA
3.545V    25.34mA    12.51mA    41.58mA
[Pullup]
-1.8V     2.903mA    2.423mA    4.112mA
-1.418V   6.595mA    4.711mA    12.64mA
-1.255V   12.69mA    7.42mA     33.23mA
-1.091V   30.4mA     13mA       58.69mA
-981.8mV  40.63mA    17.02mA    61.3mA
-818.2mV  35.38mA    18.12mA    50.59mA
272.7mV   -9.18mA    -4.728mA   -14.55mA
1.255V    -29.75mA   -15.09mA   -48.97mA
2.564V    -34.17mA   -16.31mA   -57.57mA
2.782V    -30.25mA   -15.5mA    -57.48mA
3.055V    -23.63mA   -14.68mA   -38.61mA
3.545V    -19.25mA   -13.56mA   -31.41mA
[GND_clamp]
-1.8V     -2.82A     -1.192A    -3.165A
-1.073V   -235.7mA   -138.4mA   -192.1mA
-1.036V   -159.5mA   -110.8mA   -107.5mA
-1V       -103.8mA   -87.85mA   -60.67mA
-963.6mV  -60mA      -67.28mA   -29.8mA
-927.3mV  -28.21mA   -49.08mA   -14.9mA
-890.9mV  -15.9mA    -35.48mA   -10.99mA
-854.5mV  -8.138mA   -24.07mA   -8.449mA
-818.2mV  -4.924mA   -14.85mA   -7.266mA
-709.1mV  -2.784mA   -3.064mA   -4.883mA
-563.6mV  -570.2uA   -404.5uA   -1.092mA
1.764V    -11.02pA   583.5nA    3.035nA
[Ramp]
dV/dt_f   0.651366/1.099169n   0.3677643/2.23078n   0.8183882/0.6842208n
dV/dt_r  0.6507417/1.305905n   0.4006479/2.885083n   0.8222208/0.689497n
R_load = 50
[Rising Waveform]
R_fixture = 50
V_fixture = 1.8
V_fixture_min = 1.62
V_fixture_max = 1.89
0s        717.6mV    1.009V     526.5mV
81ps      719.3mV    1.009V     708mV
180ps     716.5mV    1.009V     1.411V
234ps     766.6mV    1.01V      1.663V
387ps     1.286V     1.01V      1.848V
468ps     1.57V      1.003V     1.867V
576ps     1.729V     1.015V     1.879V
1.008ns   1.79V      1.49V      1.886V
1.161ns   1.793V     1.583V     1.887V
4.617ns   1.799V     1.618V     1.89V
[Rising Waveform]
R_fixture = 50
V_fixture = 0
V_fixture_min = 0
V_fixture_max = 0
0s        179.1uV    76.43uV    -10.76mV
225ps     -9.797mV   -58.7uV    21.02mV
585ps     19.18mV    -4.127mV   539.2mV
855ps     188.8mV    -8.257mV   884.1mV
1.08ns    343.5mV    -9.981mV   1.074V
1.629ns   659.9mV    34.51mV    1.24V
2.124ns   837.9mV    131.8mV    1.292V
3.996ns   1.02V      441.7mV    1.341V
6.192ns   1.056V     579.7mV    1.348V
19.62ns   1.067V     655.8mV    1.349V
[Falling Waveform]
R_fixture = 50
V_fixture = 1.8
V_fixture_min = 1.62
V_fixture_max = 1.89
0s        1.8V       1.62V      1.89V
297ps     1.802V     1.62V      1.808V
846ps     1.689V     1.621V     1.317V
1.287ns   1.495V     1.621V     695.3mV
1.584ns   1.35V      1.601V     568.8mV
2.286ns   876.9mV    1.497V     536.1mV
3.213ns   750.4mV    1.351V     530.5mV
4.365ns   725.4mV    1.146V     529.8mV
5.796ns   718.8mV    1.065V     529.8mV
15.01ns   717.6mV    1.011V     529.8mV
[Falling Waveform]
R_fixture = 50
V_fixture = 0
V_fixture_min = 0
V_fixture_max = 0
0s        1.067V     657.3mV    1.349V
270ps     1.07V      657.4mV    1.276V
648ps     1.015V     657.7mV    723.2mV
945ps     788.5mV    661.1mV    252.8mV
1.296ns   410.1mV    652.7mV    16.36mV
1.62ns    178.8mV    595.3mV    1.773mV
2.106ns   17.31mV    417.3mV    220.8uV
2.673ns   1.51mV     205.7mV    24.23uV
3.339ns   337.7uV    60.82mV    3.179uV
4.824ns   49.27uV    1.645mV    498.4nV
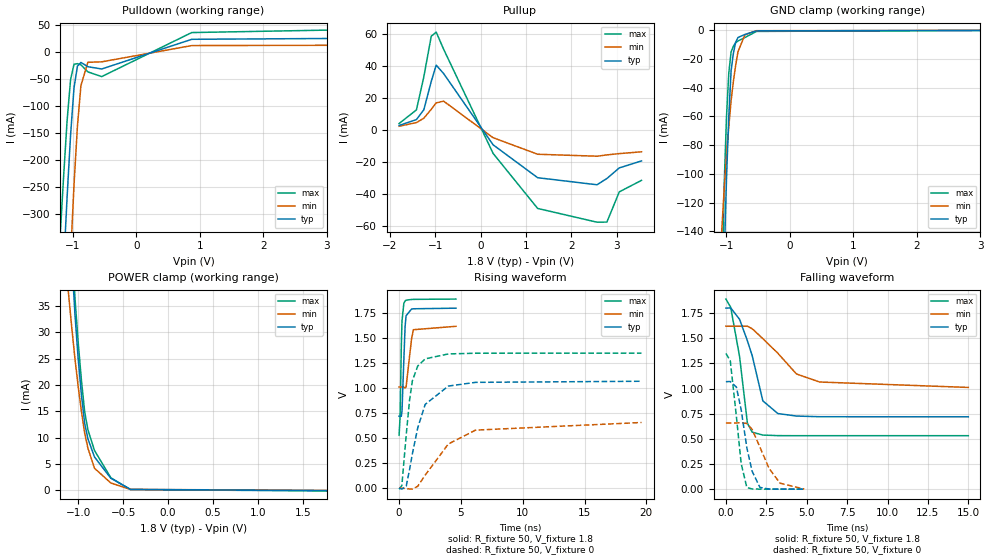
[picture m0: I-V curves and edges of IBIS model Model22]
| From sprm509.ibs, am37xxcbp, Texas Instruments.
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| Model based on original model for BQ18OMAPSMART1HYFBPBNOPM_SSBHH
|   Sub model NOPM_HS01L10_PU1_1P8
[model]   Model22
|[Input Load]   PU
|[Output Drive] SC01LB10
|Voltage   1.8V
|Mode   I/O
Model_type   I/O
Polarity   Non-Inverting
Enable   Active-Low
Vinl =  0.63
Vinh =  1.17
Cref =  15pF
Rref =  100.0000M
Vref =  0V
Vmeas =  0.9
C_comp   1.410688p   1.256095p   1.577871p
[Model Spec]
Vinl   0.63   0.567   0.6615
Vinh   1.17   1.053   1.2285
[Temperature Range]   25   125   -40
[Voltage Range]   1.8   1.62   1.89
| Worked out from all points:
|   slope of the pulldown table from 0 to 0.27 V, typ, clamps not added: 24.3 ohm
|   slope of the pullup table from 0 to 0.27 V, typ, clamps not added: 29.7 ohm
|   GND clamp passes 1 mA (typ) near -0.60 V on its own axis
|   POWER clamp passes 1 mA (typ) near -0.56 V on its own axis
|   rising waveform, R_fixture 50, V_fixture 1.8: 20-80 % time 175ps typ, 300ps min, 123ps max; typ from 0.72 V to 1.8 V
|   rising waveform, R_fixture 50, V_fixture 0: 20-80 % time 1.3ns typ, 2.86ns min, 687ps max; typ from 0.002 V to 1.07 V
|   falling waveform, R_fixture 50, V_fixture 1.8: 20-80 % time 1.1ns typ, 2.22ns min, 682ps max; typ from 1.8 V to 0.72 V
|   falling waveform, R_fixture 50, V_fixture 0: 20-80 % time 684ps typ, 1.12ns min, 502ps max; typ from 1.07 V to 0.001 V
[POWER_clamp]
-1.8V     362.5mA    191.4mA    412.8mA
-1.109V   56.76mA    37.74mA    60.51mA
-1.073V   44.67mA    31.25mA    47.93mA
-1.036V   33.52mA    25.07mA    36.72mA
-1V       25.06mA    19.75mA    28.2mA
-963.6mV  18.11mA    14.99mA    20.91mA
-927.3mV  12.67mA    10.8mA     14.87mA
-890.9mV  9.734mA    7.935mA    11.44mA
-818.2mV  6.293mA    4.153mA    7.536mA
-636.4mV  2.249mA    1.342mA    2.34mA
-418.2mV  128.7uA    129.3uA    104.4uA
1.764V    -96.73uA   -46.48uA   -163.5uA
[Pulldown]
-1.8V     -1.718A    -2.61A     -1.406A
-1.2V     -527.4mA   -844.5mA   -339.9mA
-1.145V   -396mA     -683.1mA   -229.1mA
-1.091V   -269mA     -526.7mA   -127.5mA
-1.036V   -153.6mA   -378.9mA   -51.17mA
-981.8mV  -66.33mA   -245.6mA   -22.67mA
-927.3mV  -26mA      -136.2mA   -21.54mA
-872.7mV  -19.34mA   -61.98mA   -23.69mA
-763.6mV  -27.2mA    -19.05mA   -36.72mA
-545.5mV  -31.39mA   -18.17mA   -45.46mA
872.7mV   23.46mA    11.88mA    35.92mA
3.545V    25.34mA    12.51mA    41.58mA
[Pullup]
-1.8V     2.903mA    2.423mA    4.112mA
-1.418V   6.595mA    4.711mA    12.64mA
-1.255V   12.69mA    7.42mA     33.24mA
-1.091V   30.4mA     13mA       58.69mA
-981.8mV  40.63mA    17.02mA    61.3mA
-818.2mV  35.38mA    18.12mA    50.59mA
272.7mV   -9.179mA   -4.728mA   -14.55mA
1.255V    -29.75mA   -15.09mA   -48.97mA
2.564V    -34.17mA   -16.31mA   -57.57mA
2.782V    -30.25mA   -15.5mA    -57.49mA
3.055V    -23.63mA   -14.68mA   -38.61mA
3.545V    -19.25mA   -13.56mA   -31.41mA
[GND_clamp]
-1.8V     -2.82A     -1.192A    -3.165A
-1.073V   -235.8mA   -138.4mA   -192.1mA
-1.036V   -159.6mA   -110.8mA   -107.6mA
-1V       -103.8mA   -87.86mA   -60.73mA
-963.6mV  -60.04mA   -67.29mA   -29.86mA
-927.3mV  -28.26mA   -49.09mA   -14.98mA
-890.9mV  -15.95mA   -35.49mA   -11.09mA
-854.5mV  -8.198mA   -24.09mA   -8.559mA
-818.2mV  -4.99mA    -14.87mA   -7.387mA
-709.1mV  -2.858mA   -3.093mA   -5.012mA
-527.3mV  -395.6uA   -260.4uA   -751.2uA
3.6V      0A         0A         0A
[Ramp]
dV/dt_f  0.6499471/1.099589n   0.3670067/2.231354n   0.8167022/0.6845432n
dV/dt_r  0.6495681/1.303407n   0.4003134/2.88201n   0.8199415/0.6878094n
R_load = 50
[Rising Waveform]
R_fixture = 50
V_fixture = 1.8
V_fixture_min = 1.62
V_fixture_max = 1.89
0s        720mV      1.011V     529.3mV
81ps      721.7mV    1.011V     712.3mV
180ps     718.9mV    1.011V     1.416V
234ps     769.3mV    1.011V     1.668V
387ps     1.289V     1.011V     1.849V
486ps     1.617V     1.003V     1.87V
567ps     1.724V     1.013V     1.879V
1.008ns   1.79V      1.491V     1.886V
1.161ns   1.793V     1.584V     1.887V
4.599ns   1.799V     1.618V     1.89V
[Rising Waveform]
R_fixture = 50
V_fixture = 0
V_fixture_min = 0
V_fixture_max = 0
0s        1.567mV    1.042mV    -8.839mV
225ps     -8.268mV   906.9uV    27.79mV
576ps     19.84mV    -2.854mV   532.8mV
846ps     186.7mV    -6.935mV   879.7mV
1.071ns   341.7mV    -8.095mV   1.072V
1.512ns   605.3mV    20.57mV    1.222V
2.115ns   838.6mV    132.1mV    1.293V
3.987ns   1.021V     442.6mV    1.342V
6.183ns   1.058V     580.9mV    1.349V
19.61ns   1.069V     657.1mV    1.35V
[Falling Waveform]
R_fixture = 50
V_fixture = 1.8
V_fixture_min = 1.62
V_fixture_max = 1.89
0s        1.8V       1.62V      1.89V
297ps     1.802V     1.62V      1.808V
846ps     1.689V     1.621V     1.319V
1.332ns   1.475V     1.62V      655.4mV
1.629ns   1.327V     1.595V     567.7mV
2.286ns   879mV      1.497V     538.9mV
3.213ns   752.8mV    1.352V     533.3mV
4.365ns   727.7mV    1.146V     532.6mV
5.796ns   721.2mV    1.066V     532.6mV
15ns      720mV      1.012V     532.6mV
[Falling Waveform]
R_fixture = 50
V_fixture = 0
V_fixture_min = 0
V_fixture_max = 0
0s        1.069V     658.6mV    1.35V
270ps     1.071V     658.7mV    1.278V
648ps     1.016V     659.1mV    726mV
945ps     790.6mV    662.4mV    255.3mV
1.296ns   412.6mV    654.1mV    18.24mV
1.62ns    180.8mV    596.7mV    3.59mV
2.106ns   18.87mV    419.1mV    2.005mV
2.673ns   2.941mV    207.1mV    1.799mV
3.348ns   1.734mV    60.76mV    1.776mV
4.851ns   1.437mV    2.599mV    1.773mV
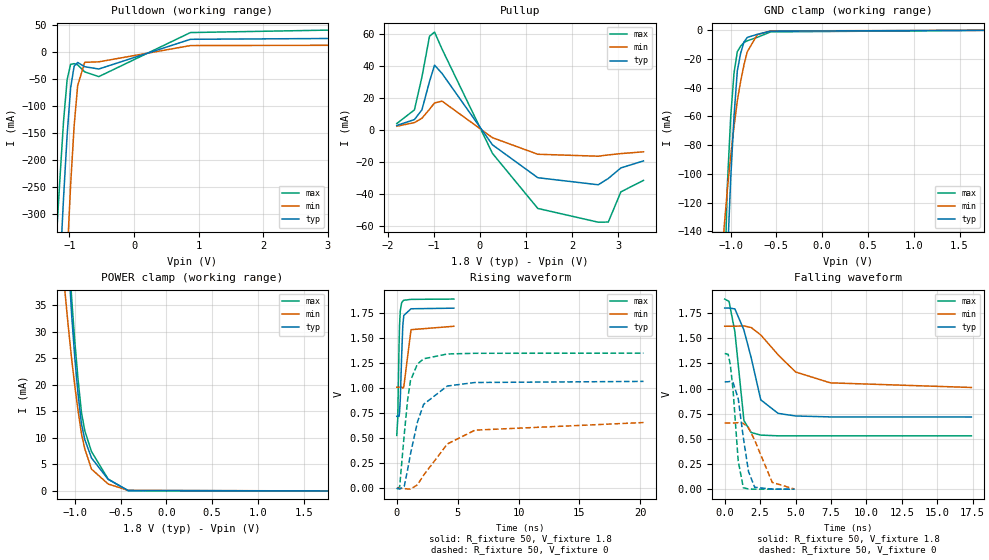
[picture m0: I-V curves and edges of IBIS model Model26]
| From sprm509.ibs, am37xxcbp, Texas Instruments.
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| Model based on original model for BQ18OMAPSMART1HYFBPBNOPM_SSBHH
|   Sub model PM_HS10L10_PUPD0_1P8
[model]   Model26
|[Input Load]   PI
|[Output Drive] SC10LB10
|Voltage   1.8V
|Mode   I/O
Model_type   I/O
Polarity   Non-Inverting
Enable   Active-Low
Vinl =  0.63
Vinh =  1.17
Cref =  15pF
Rref =  100.0000M
Vref =  0V
Vmeas =  0.9
C_comp   1.410688p   1.256095p   1.577871p
[Model Spec]
Vinl   0.63   0.567   0.6615
Vinh   1.17   1.053   1.2285
[Temperature Range]   25   125   -40
[Voltage Range]   1.8   1.62   1.89
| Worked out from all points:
|   slope of the pulldown table from 0 to 0.27 V, typ, clamps not added: 24.3 ohm
|   slope of the pullup table from 0 to 0.27 V, typ, clamps not added: 29.7 ohm
|   GND clamp passes 1 mA (typ) near -0.60 V on its own axis
|   POWER clamp passes 1 mA (typ) near -0.56 V on its own axis
|   rising waveform, R_fixture 50, V_fixture 1.8: 20-80 % time 177ps typ, 303ps min, 124ps max; typ from 0.718 V to 1.8 V
|   rising waveform, R_fixture 50, V_fixture 0: 20-80 % time 1.34ns typ, 2.96ns min, 708ps max; typ from 0 V to 1.07 V
|   falling waveform, R_fixture 50, V_fixture 1.8: 20-80 % time 1.05ns typ, 2.68ns min, 600ps max; typ from 1.8 V to 0.718 V
|   falling waveform, R_fixture 50, V_fixture 0: 20-80 % time 610ps typ, 1.04ns min, 434ps max; typ from 1.07 V to 0 V
[POWER_clamp]
-1.8V     362.5mA    191.4mA    412.8mA
-1.109V   56.69mA    37.71mA    60.38mA
-1.073V   44.6mA     31.22mA    47.8mA
-1.036V   33.44mA    25.04mA    36.59mA
-1V       24.98mA    19.72mA    28.06mA
-963.6mV  18.03mA    14.96mA    20.78mA
-927.3mV  12.59mA    10.77mA    14.74mA
-890.9mV  9.653mA    7.899mA    11.31mA
-818.2mV  6.214mA    4.114mA    7.414mA
-636.4mV  2.183mA    1.307mA    2.238mA
-418.2mV  83.85uA    105.2uA    35.14uA
1.764V    -1.228nA   -79.12nA   -1.453nA
[Pulldown]
-1.8V     -1.718A    -2.61A     -1.406A
-1.2V     -527.4mA   -844.5mA   -339.9mA
-1.145V   -396mA     -683.1mA   -229.1mA
-1.091V   -269mA     -526.7mA   -127.5mA
-1.036V   -153.6mA   -378.9mA   -51.17mA
-981.8mV  -66.34mA   -245.6mA   -22.67mA
-927.3mV  -26mA      -136.2mA   -21.54mA
-872.7mV  -19.34mA   -61.98mA   -23.69mA
-763.6mV  -27.2mA    -19.05mA   -36.72mA
-545.5mV  -31.39mA   -18.17mA   -45.46mA
872.7mV   23.46mA    11.88mA    35.92mA
3.545V    25.34mA    12.51mA    41.58mA
[Pullup]
-1.8V     2.903mA    2.423mA    4.112mA
-1.418V   6.595mA    4.711mA    12.64mA
-1.255V   12.69mA    7.42mA     33.23mA
-1.091V   30.4mA     13mA       58.69mA
-981.8mV  40.63mA    17.02mA    61.3mA
-818.2mV  35.38mA    18.12mA    50.59mA
272.7mV   -9.18mA    -4.728mA   -14.55mA
1.255V    -29.75mA   -15.09mA   -48.97mA
2.564V    -34.17mA   -16.31mA   -57.57mA
2.782V    -30.25mA   -15.5mA    -57.48mA
3.055V    -23.63mA   -14.68mA   -38.61mA
3.545V    -19.25mA   -13.56mA   -31.41mA
[GND_clamp]
-1.8V     -2.82A     -1.192A    -3.165A
-1.073V   -235.7mA   -138.4mA   -192.1mA
-1.036V   -159.5mA   -110.8mA   -107.5mA
-1V       -103.8mA   -87.85mA   -60.67mA
-963.6mV  -60mA      -67.28mA   -29.8mA
-927.3mV  -28.21mA   -49.08mA   -14.9mA
-890.9mV  -15.9mA    -35.48mA   -10.99mA
-854.5mV  -8.138mA   -24.07mA   -8.449mA
-818.2mV  -4.924mA   -14.85mA   -7.266mA
-709.1mV  -2.784mA   -3.064mA   -4.883mA
-563.6mV  -570.2uA   -404.5uA   -1.092mA
1.764V    -11.02pA   583.5nA    3.035nA
[Ramp]
dV/dt_f  0.6514786/1.05468n   0.3679896/2.701283n   0.8183944/0.6013967n
dV/dt_r  0.6510693/1.34661n   0.4007412/2.982092n   0.8228757/0.7095584n
R_load = 50
[Rising Waveform]
R_fixture = 50
V_fixture = 1.8
V_fixture_min = 1.62
V_fixture_max = 1.89
0s        717.6mV    1.009V     527mV
81ps      719.6mV    1.009V     698.9mV
180ps     716.1mV    1.009V     1.393V
225ps     752.2mV    1.01V      1.624V
288ps     888.9mV    1.011V     1.772V
396ps     1.306V     1.01V      1.85V
495ps     1.624V     1V         1.87V
576ps     1.726V     1.013V     1.878V
1.17ns    1.793V     1.584V     1.887V
4.689ns   1.799V     1.618V     1.89V
[Rising Waveform]
R_fixture = 50
V_fixture = 0
V_fixture_min = 0
V_fixture_max = 0
0s        160uV      77.42uV    -10.15mV
234ps     -9.537mV   -50.78uV   13.57mV
612ps     18.09mV    -4.465mV   535.2mV
891ps     184.9mV    -8.483mV   882.4mV
1.125ns   340.9mV    -9.513mV   1.074V
1.692ns   658.3mV    33.06mV    1.24V
2.205ns   837.9mV    129.4mV    1.293V
4.149ns   1.021V     441.3mV    1.341V
6.426ns   1.056V     579.9mV    1.348V
20.26ns   1.067V     655.8mV    1.349V
[Falling Waveform]
R_fixture = 50
V_fixture = 1.8
V_fixture_min = 1.62
V_fixture_max = 1.89
0s        1.8V       1.62V      1.89V
306ps     1.801V     1.62V      1.867V
720ps     1.792V     1.62V      1.564V
1.359ns   1.581V     1.623V     681mV
1.872ns   1.306V     1.607V     563.1mV
2.547ns   887.9mV    1.533V     537.4mV
3.771ns   753.6mV    1.336V     530.4mV
5.004ns   727.6mV    1.165V     529.9mV
7.461ns   718.4mV    1.057V     529.8mV
17.42ns   717.6mV    1.011V     529.8mV
[Falling Waveform]
R_fixture = 50
V_fixture = 0
V_fixture_min = 0
V_fixture_max = 0
0s        1.067V     657.3mV    1.349V
243ps     1.068V     657.4mV    1.341V
396ps     1.071V     657.3mV    1.239V
594ps     1.059V     657.5mV    979.8mV
954ps     900.3mV    660.9mV    279.9mV
1.314ns   514mV      654.1mV    14.52mV
1.683ns   174.6mV    610.8mV    1.512mV
2.115ns   19.17mV    487.3mV    262.1uV
3.357ns   399uV      67.02mV    7.201uV
4.923ns   62.17uV    1.632mV    757.7nV
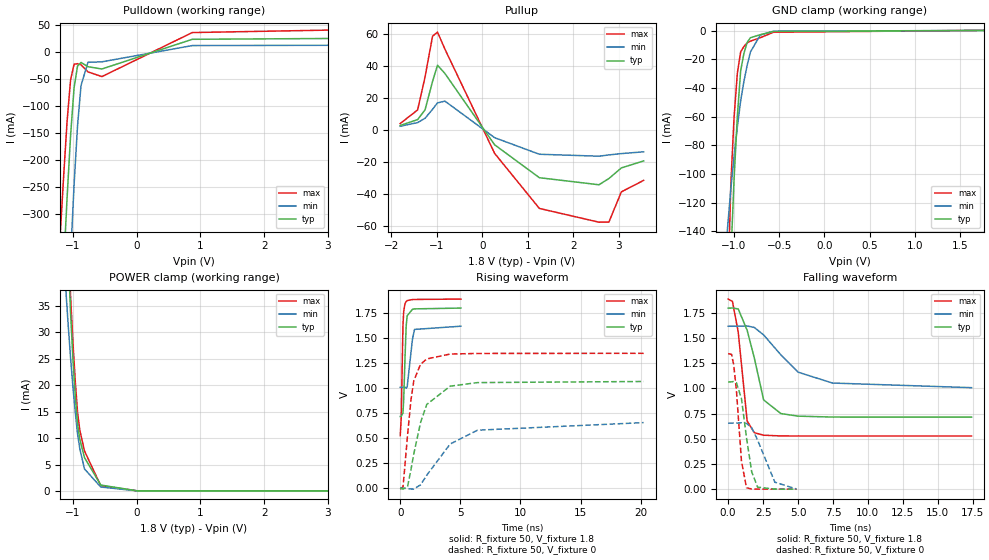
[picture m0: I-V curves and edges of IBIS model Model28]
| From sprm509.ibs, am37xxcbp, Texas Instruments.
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| Model based on original model for BQ18OMAPSMART1HYFBPBNOPM_SSBHH
|   Sub model NOPM_HS10L10_PD1_1P8
[model]   Model28
|[Input Load]   PD
|[Output Drive] SC10LB10
|Voltage   1.8V
|Mode   I/O
Model_type   I/O
Polarity   Non-Inverting
Enable   Active-Low
Vinl =  0.63
Vinh =  1.17
Cref =  15pF
Rref =  100.0000M
Vref =  0V
Vmeas =  0.9
C_comp   1.410688p   1.256095p   1.577871p
[Model Spec]
Vinl   0.63   0.567   0.6615
Vinh   1.17   1.053   1.2285
[Temperature Range]   25   125   -40
[Voltage Range]   1.8   1.62   1.89
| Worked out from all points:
|   slope of the pulldown table from 0 to 0.27 V, typ, clamps not added: 24.3 ohm
|   slope of the pullup table from 0 to 0.27 V, typ, clamps not added: 29.7 ohm
|   GND clamp passes 1 mA (typ) near -0.60 V on its own axis
|   POWER clamp passes 1 mA (typ) near -0.55 V on its own axis
|   rising waveform, R_fixture 50, V_fixture 1.8: 20-80 % time 178ps typ, 306ps min, 125ps max; typ from 0.715 V to 1.8 V
|   rising waveform, R_fixture 50, V_fixture 0: 20-80 % time 1.35ns typ, 2.96ns min, 710ps max; typ from 0 V to 1.06 V
|   falling waveform, R_fixture 50, V_fixture 1.8: 20-80 % time 1.05ns typ, 2.67ns min, 598ps max; typ from 1.8 V to 0.715 V
|   falling waveform, R_fixture 50, V_fixture 0: 20-80 % time 609ps typ, 1.04ns min, 433ps max; typ from 1.06 V to 0 V
[POWER_clamp]
-1.8V     362.5mA    191.4mA    412.8mA
-1.109V   56.75mA    37.73mA    60.5mA
-1.073V   44.66mA    31.25mA    47.93mA
-1.036V   33.51mA    25.07mA    36.73mA
-1V       25.06mA    19.75mA    28.2mA
-963.6mV  18.11mA    14.99mA    20.92mA
-927.3mV  12.68mA    10.81mA    14.88mA
-890.9mV  9.743mA    7.94mA     11.46mA
-818.2mV  6.308mA    4.161mA    7.567mA
-563.6mV  1.112mA    743.5uA    1.008mA
18.18mV   0A         0A         0A
3.6V      0A         0A         0A
[Pulldown]
-1.8V     -1.718A    -2.61A     -1.406A
-1.2V     -527.4mA   -844.5mA   -339.9mA
-1.145V   -396mA     -683.1mA   -229.1mA
-1.091V   -269mA     -526.7mA   -127.5mA
-1.036V   -153.6mA   -378.9mA   -51.17mA
-981.8mV  -66.33mA   -245.6mA   -22.67mA
-927.3mV  -26mA      -136.2mA   -21.54mA
-872.7mV  -19.34mA   -61.98mA   -23.69mA
-763.6mV  -27.2mA    -19.05mA   -36.72mA
-545.5mV  -31.39mA   -18.17mA   -45.46mA
872.7mV   23.46mA    11.88mA    35.92mA
3.545V    25.34mA    12.51mA    41.58mA
[Pullup]
-1.8V     2.903mA    2.423mA    4.112mA
-1.418V   6.595mA    4.711mA    12.64mA
-1.255V   12.69mA    7.42mA     33.24mA
-1.091V   30.4mA     13mA       58.69mA
-981.8mV  40.63mA    17.02mA    61.3mA
-818.2mV  35.38mA    18.12mA    50.59mA
272.7mV   -9.18mA    -4.728mA   -14.55mA
1.255V    -29.75mA   -15.09mA   -48.97mA
2.564V    -34.17mA   -16.31mA   -57.57mA
2.782V    -30.25mA   -15.5mA    -57.49mA
3.055V    -23.63mA   -14.68mA   -38.61mA
3.545V    -19.25mA   -13.56mA   -31.41mA
[GND_clamp]
-1.8V     -2.82A     -1.192A    -3.165A
-1.073V   -235.8mA   -138.4mA   -192.1mA
-1.036V   -159.6mA   -110.8mA   -107.6mA
-1V       -103.8mA   -87.86mA   -60.72mA
-963.6mV  -60.04mA   -67.29mA   -29.85mA
-927.3mV  -28.26mA   -49.1mA    -14.96mA
-890.9mV  -15.95mA   -35.5mA    -11.07mA
-854.5mV  -8.196mA   -24.09mA   -8.539mA
-818.2mV  -4.988mA   -14.87mA   -7.364mA
-709.1mV  -2.851mA   -3.095mA   -4.982mA
-563.6mV  -633.9uA   -437.8uA   -1.185mA
1.764V    107.4uA    58.81uA    171.2uA
[Ramp]
dV/dt_f   0.651658/1.050996n   0.3685472/2.695566n   0.8180584/0.6001022n
dV/dt_r  0.6496394/1.349366n   0.3998717/2.983634n   0.8212412/0.711847n
R_load = 50
[Rising Waveform]
R_fixture = 50
V_fixture = 1.8
V_fixture_min = 1.62
V_fixture_max = 1.89
0s        715.4mV    1.007V     525.3mV
81ps      717.4mV    1.007V     696.4mV
225ps     749.8mV    1.007V     1.618V
288ps     885.9mV    1.008V     1.765V
396ps     1.302V     1.008V     1.843V
495ps     1.619V     998mV      1.863V
576ps     1.721V     1.011V     1.873V
1.017ns   1.786V     1.488V     1.883V
1.188ns   1.79V      1.585V     1.884V
5.049ns   1.798V     1.617V     1.888V
[Rising Waveform]
R_fixture = 50
V_fixture = 0
V_fixture_min = 0
V_fixture_max = 0
0s        160uV      77.38uV    -10.15mV
234ps     -9.535mV   -50.81uV   13.66mV
612ps     18.14mV    -4.465mV   533.6mV
891ps     184.7mV    -8.477mV   879.3mV
1.125ns   340.1mV    -9.495mV   1.071V
1.692ns   656.3mV    33.06mV    1.237V
2.205ns   835.5mV    129.3mV    1.29V
4.149ns   1.018V     440.3mV    1.339V
6.426ns   1.054V     578.6mV    1.345V
20.25ns   1.065V     654.3mV    1.346V
[Falling Waveform]
R_fixture = 50
V_fixture = 1.8
V_fixture_min = 1.62
V_fixture_max = 1.89
0s        1.798V     1.618V     1.888V
306ps     1.799V     1.618V     1.865V
720ps     1.79V      1.619V     1.561V
1.359ns   1.578V     1.621V     676.9mV
1.872ns   1.303V     1.606V     560.9mV
2.538ns   886.4mV    1.532V     535.8mV
3.771ns   750.9mV    1.334V     528.7mV
5.004ns   725.2mV    1.162V     528.2mV
7.461ns   716.1mV    1.054V     528.1mV
17.42ns   715.4mV    1.008V     528.1mV
[Falling Waveform]
R_fixture = 50
V_fixture = 0
V_fixture_min = 0
V_fixture_max = 0
0s        1.065V     655.8mV    1.346V
243ps     1.066V     655.9mV    1.338V
396ps     1.069V     655.8mV    1.236V
594ps     1.056V     656.1mV    976mV
954ps     897.4mV    659.4mV    277.2mV
1.314ns   510.4mV    652.7mV    13.99mV
1.683ns   173mV      609.3mV    1.46mV
2.106ns   20.11mV    489mV      265.2uV
3.339ns   402.2uV    69.39mV    7.478uV
4.887ns   63.49uV    1.638mV    766.2nV
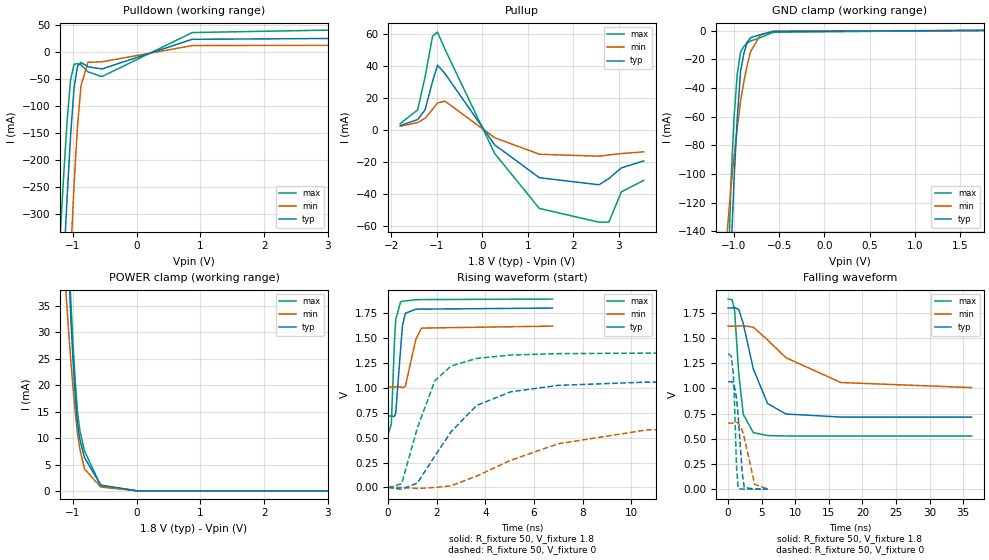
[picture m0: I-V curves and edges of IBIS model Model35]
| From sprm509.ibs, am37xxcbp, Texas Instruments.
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| Model based on original model for BQ18OMAPSMART1HYFBPB_SSBHH
|   Sub model FBPB_HS00L10_PD1_1P8
[model]   Model35
|[Input Load]   PD
|[Output Drive] SC00LB10
|Voltage   1.8V
|Mode   I/O
Model_type   I/O
Polarity   Non-Inverting
Enable   Active-Low
Vinl =  0.63
Vinh =  1.17
Cref =  15pF
Rref =  100.0000M
Vref =  0V
Vmeas =  0.9
C_comp   1.429432p   1.270657p   1.602015p
[Model Spec]
Vinl   0.63   0.567   0.6615
Vinh   1.17   1.053   1.2285
[Temperature Range]   25   125   -40
[Voltage Range]   1.8   1.62   1.89
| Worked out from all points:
|   slope of the pulldown table from 0 to 0.27 V, typ, clamps not added: 24.3 ohm
|   slope of the pullup table from 0 to 0.27 V, typ, clamps not added: 29.7 ohm
|   GND clamp passes 1 mA (typ) near -0.60 V on its own axis
|   POWER clamp passes 1 mA (typ) near -0.55 V on its own axis
|   rising waveform, R_fixture 50, V_fixture 1.8: 20-80 % time 178ps typ, 313ps min, 125ps max; typ from 0.716 V to 1.8 V
|   rising waveform, R_fixture 50, V_fixture 0: 20-80 % time 2.17ns typ, 4.92ns min, 1.1ns max; typ from 0 V to 1.06 V
|   falling waveform, R_fixture 50, V_fixture 1.8: 20-80 % time 2.7ns typ, 7.23ns min, 932ps max; typ from 1.8 V to 0.716 V
|   falling waveform, R_fixture 50, V_fixture 0: 20-80 % time 700ps typ, 1.22ns min, 396ps max; typ from 1.06 V to 0 V
[POWER_clamp]
-1.8V     362.5mA    191.4mA    412.8mA
-1.109V   56.74mA    37.73mA    60.49mA
-1.073V   44.66mA    31.25mA    47.92mA
-1.036V   33.51mA    25.07mA    36.71mA
-1V       25.05mA    19.75mA    28.19mA
-963.6mV  18.1mA     14.99mA    20.91mA
-927.3mV  12.67mA    10.8mA     14.87mA
-890.9mV  9.735mA    7.937mA    11.45mA
-818.2mV  6.3mA      4.158mA    7.553mA
-563.6mV  1.102mA    739.7uA    992.8uA
18.18mV   0A         0A         0A
3.6V      0A         0A         0A
[Pulldown]
-1.8V     -1.718A    -2.61A     -1.406A
-1.2V     -527.4mA   -844.5mA   -339.9mA
-1.145V   -396mA     -683.1mA   -229.1mA
-1.091V   -269mA     -526.7mA   -127.5mA
-1.036V   -153.6mA   -378.9mA   -51.17mA
-981.8mV  -66.33mA   -245.6mA   -22.67mA
-927.3mV  -26mA      -136.2mA   -21.54mA
-872.7mV  -19.34mA   -61.98mA   -23.69mA
-763.6mV  -27.2mA    -19.05mA   -36.72mA
-545.5mV  -31.39mA   -18.17mA   -45.46mA
872.7mV   23.46mA    11.88mA    35.92mA
3.545V    25.34mA    12.51mA    41.58mA
[Pullup]
-1.8V     2.903mA    2.423mA    4.112mA
-1.418V   6.595mA    4.711mA    12.64mA
-1.255V   12.69mA    7.42mA     33.24mA
-1.091V   30.4mA     13mA       58.69mA
-981.8mV  40.63mA    17.02mA    61.3mA
-818.2mV  35.38mA    18.12mA    50.59mA
272.7mV   -9.18mA    -4.728mA   -14.55mA
1.255V    -29.75mA   -15.09mA   -48.97mA
2.564V    -34.17mA   -16.31mA   -57.57mA
2.782V    -30.25mA   -15.5mA    -57.48mA
3.055V    -23.63mA   -14.68mA   -38.61mA
3.545V    -19.25mA   -13.56mA   -31.41mA
[GND_clamp]
-1.8V     -2.82A     -1.192A    -3.165A
-1.073V   -235.8mA   -138.4mA   -192.1mA
-1.036V   -159.6mA   -110.8mA   -107.6mA
-1V       -103.8mA   -87.86mA   -60.71mA
-963.6mV  -60.04mA   -67.29mA   -29.85mA
-927.3mV  -28.26mA   -49.1mA    -14.96mA
-890.9mV  -15.95mA   -35.5mA    -11.07mA
-854.5mV  -8.194mA   -24.09mA   -8.535mA
-818.2mV  -4.986mA   -14.87mA   -7.361mA
-709.1mV  -2.849mA   -3.094mA   -4.979mA
-563.6mV  -632.2uA   -437.1uA   -1.183mA
1.764V    97.78uA    55.01uA    156.3uA
[Ramp]
dV/dt_f  0.6524875/2.69764n   0.3692737/7.288452n   0.8186031/0.9275341n
dV/dt_r  0.6502221/2.182408n   0.3998246/4.965004n   0.8226605/1.108899n
R_load = 50
[Rising Waveform]
R_fixture = 50
V_fixture = 1.8
V_fixture_min = 1.62
V_fixture_max = 1.89
0s        715.6mV    1.007V     530mV
135ps     716.3mV    1.007V     635.3mV
261ps     711.2mV    1.007V     1.456V
315ps     745.1mV    1.007V     1.683V
513ps     1.38V      1.008V     1.858V
594ps     1.624V     1V         1.867V
711ps     1.746V     1.014V     1.869V
1.143ns   1.786V     1.485V     1.881V
1.377ns   1.787V     1.597V     1.883V
6.768ns   1.798V     1.617V     1.888V
[Rising Waveform]
R_fixture = 50
V_fixture = 0
V_fixture_min = 0
V_fixture_max = 0
0s        -214.9uV   58.59uV    -3.662mV
558ps     -17.05mV   301.1uV    37.46mV
1.206ns   44.07mV    -10.2mV    597.8mV
1.926ns   315.4mV    -415.9uV   1.071V
2.592ns   557.4mV    16.79mV    1.217V
3.636ns   821.3mV    113.4mV    1.293V
5.04ns    958.4mV    272mV      1.327V
6.993ns   1.023V     437.2mV    1.341V
10.65ns   1.056V     577.2mV    1.346V
32.04ns   1.065V     654.4mV    1.346V
[Falling Waveform]
R_fixture = 50
V_fixture = 1.8
V_fixture_min = 1.62
V_fixture_max = 1.89
0s        1.798V     1.619V     1.888V
612ps     1.801V     1.618V     1.881V
963ps     1.803V     1.618V     1.77V
1.575ns   1.785V     1.621V     1.148V
2.25ns    1.644V     1.622V     743.7mV
3.744ns   1.195V     1.609V     561.7mV
5.868ns   850.5mV    1.482V     532.4mV
8.595ns   746.5mV    1.306V     528.5mV
16.79ns   716.1mV    1.059V     528.2mV
36.24ns   715.5mV    1.009V     528.2mV
[Falling Waveform]
R_fixture = 50
V_fixture = 0
V_fixture_min = 0
V_fixture_max = 0
0s        1.065V     656mV      1.346V
450ps     1.069V     656mV      1.323V
756ps     1.056V     656.2mV    1.159V
900ps     1.031V     657.8mV    957.9mV
1.251ns   903.1mV    663.3mV    212.8mV
1.494ns   721.3mV    657.9mV    9.018mV
2.097ns   161mV      584.2mV    776.2uV
2.403ns   16.76mV    510.8mV    377uV
3.942ns   467.4uV    48.01mV    63.9uV
5.886ns   156.3uV    1.631mV    13.96uV
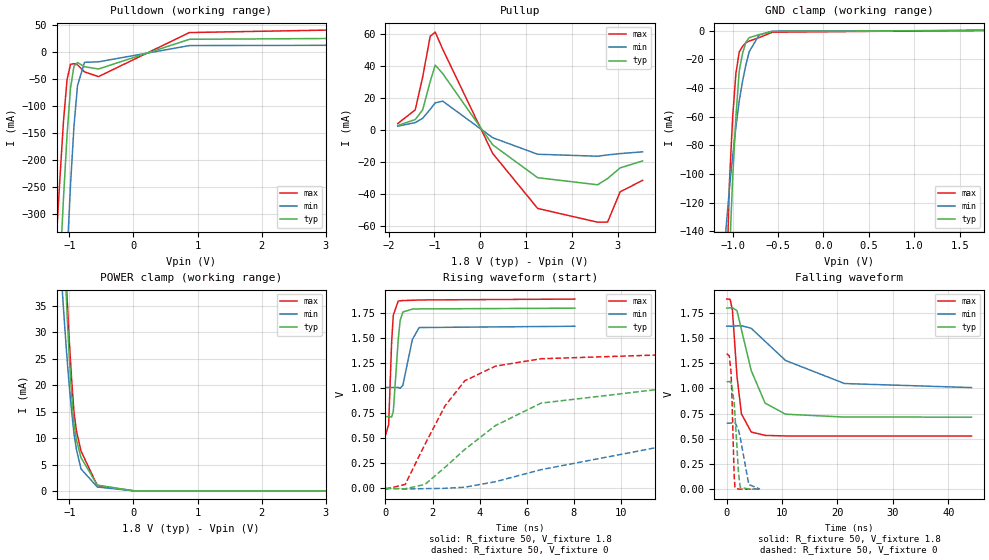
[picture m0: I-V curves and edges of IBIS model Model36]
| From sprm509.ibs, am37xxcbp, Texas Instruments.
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| Model based on original model for BQ18OMAPSMART1HYFBPB_SSBHH
|   Sub model FBPB_HS00L01_PD1_1P8
[model]   Model36
|[Input Load]   PD
|[Output Drive] SC00LB01
|Voltage   1.8V
|Mode   I/O
Model_type   I/O
Polarity   Non-Inverting
Enable   Active-Low
Vinl =  0.63
Vinh =  1.17
Cref =  15pF
Rref =  100.0000M
Vref =  0V
Vmeas =  0.9
C_comp   1.429432p   1.270657p   1.602015p
[Model Spec]
Vinl   0.63   0.567   0.6615
Vinh   1.17   1.053   1.2285
[Temperature Range]   25   125   -40
[Voltage Range]   1.8   1.62   1.89
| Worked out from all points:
|   slope of the pulldown table from 0 to 0.27 V, typ, clamps not added: 24.3 ohm
|   slope of the pullup table from 0 to 0.27 V, typ, clamps not added: 29.7 ohm
|   GND clamp passes 1 mA (typ) near -0.60 V on its own axis
|   POWER clamp passes 1 mA (typ) near -0.55 V on its own axis
|   rising waveform, R_fixture 50, V_fixture 1.8: 20-80 % time 177ps typ, 316ps min, 125ps max; typ from 0.716 V to 1.8 V
|   rising waveform, R_fixture 50, V_fixture 0: 20-80 % time 4.1ns typ, 9.4ns min, 2.06ns max; typ from 0 V to 1.06 V
|   falling waveform, R_fixture 50, V_fixture 1.8: 20-80 % time 3.37ns typ, 8.8ns min, 1.24ns max; typ from 1.8 V to 0.716 V
|   falling waveform, R_fixture 50, V_fixture 0: 20-80 % time 711ps typ, 1.2ns min, 410ps max; typ from 1.06 V to 0 V
[POWER_clamp]
-1.8V     362.5mA    191.4mA    412.8mA
-1.109V   56.74mA    37.73mA    60.49mA
-1.073V   44.66mA    31.25mA    47.92mA
-1.036V   33.51mA    25.07mA    36.71mA
-1V       25.05mA    19.75mA    28.19mA
-963.6mV  18.1mA     14.99mA    20.91mA
-927.3mV  12.67mA    10.8mA     14.87mA
-890.9mV  9.735mA    7.937mA    11.45mA
-818.2mV  6.3mA      4.158mA    7.553mA
-563.6mV  1.102mA    739.7uA    992.8uA
18.18mV   0A         0A         0A
3.6V      0A         0A         0A
[Pulldown]
-1.8V     -1.718A    -2.61A     -1.406A
-1.2V     -527.4mA   -844.5mA   -339.9mA
-1.145V   -396mA     -683.1mA   -229.1mA
-1.091V   -269mA     -526.7mA   -127.5mA
-1.036V   -153.6mA   -378.9mA   -51.17mA
-981.8mV  -66.33mA   -245.6mA   -22.67mA
-927.3mV  -26mA      -136.2mA   -21.54mA
-872.7mV  -19.34mA   -61.98mA   -23.69mA
-763.6mV  -27.2mA    -19.05mA   -36.72mA
-545.5mV  -31.39mA   -18.17mA   -45.46mA
872.7mV   23.46mA    11.88mA    35.92mA
3.545V    25.34mA    12.51mA    41.58mA
[Pullup]
-1.8V     2.903mA    2.423mA    4.112mA
-1.418V   6.595mA    4.711mA    12.64mA
-1.255V   12.69mA    7.42mA     33.24mA
-1.091V   30.4mA     13mA       58.69mA
-981.8mV  40.63mA    17.02mA    61.3mA
-818.2mV  35.38mA    18.12mA    50.59mA
272.7mV   -9.18mA    -4.728mA   -14.55mA
1.255V    -29.75mA   -15.09mA   -48.97mA
2.564V    -34.17mA   -16.31mA   -57.57mA
2.782V    -30.25mA   -15.5mA    -57.48mA
3.055V    -23.63mA   -14.68mA   -38.61mA
3.545V    -19.25mA   -13.56mA   -31.41mA
[GND_clamp]
-1.8V     -2.82A     -1.192A    -3.165A
-1.073V   -235.8mA   -138.4mA   -192.1mA
-1.036V   -159.6mA   -110.8mA   -107.6mA
-1V       -103.8mA   -87.86mA   -60.71mA
-963.6mV  -60.04mA   -67.29mA   -29.85mA
-927.3mV  -28.26mA   -49.1mA    -14.96mA
-890.9mV  -15.95mA   -35.5mA    -11.07mA
-854.5mV  -8.194mA   -24.09mA   -8.535mA
-818.2mV  -4.986mA   -14.87mA   -7.361mA
-709.1mV  -2.849mA   -3.094mA   -4.979mA
-563.6mV  -632.2uA   -437.1uA   -1.183mA
1.764V    97.78uA    55.01uA    156.3uA
[Ramp]
dV/dt_f  0.6526659/3.372473n   0.3693672/8.87002n   0.8186443/1.241168n
dV/dt_r  0.6490686/4.112775n   0.3992653/9.487834n   0.821131/2.063367n
R_load = 50
[Rising Waveform]
R_fixture = 50
V_fixture = 1.8
V_fixture_min = 1.62
V_fixture_max = 1.89
0s        715.6mV    1.007V     530mV
135ps     716.4mV    1.007V     635.9mV
261ps     711.2mV    1.007V     1.457V
333ps     769.6mV    1.007V     1.729V
540ps     1.477V     1.007V     1.867V
621ps     1.672V     997.6mV    1.871V
738ps     1.759V     1.028V     1.873V
1.143ns   1.788V     1.485V     1.876V
1.431ns   1.79V      1.604V     1.879V
8.046ns   1.797V     1.617V     1.888V
[Rising Waveform]
R_fixture = 50
V_fixture = 0
V_fixture_min = 0
V_fixture_max = 0
0s        -64.05uV   106.5uV    -7.603mV
837ps     -3.787mV   -5.306mV   39.76mV
1.683ns   40.29mV    -2.307mV   441.8mV
2.529ns   209.8mV    753uV      821.8mV
3.375ns   389.3mV    12.06mV    1.074V
4.671ns   626.1mV    66.65mV    1.219V
6.615ns   850.4mV    186.9mV    1.293V
13.01ns   1.026V     474mV      1.341V
20.79ns   1.058V     594.2mV    1.346V
60.34ns   1.065V     654.4mV    1.346V
[Falling Waveform]
R_fixture = 50
V_fixture = 1.8
V_fixture_min = 1.62
V_fixture_max = 1.89
0s        1.798V     1.619V     1.888V
621ps     1.801V     1.618V     1.886V
1.035ns   1.803V     1.618V     1.777V
1.863ns   1.772V     1.622V     1.119V
2.664ns   1.584V     1.623V     748.1mV
4.428ns   1.178V     1.598V     567.4mV
6.939ns   854.5mV    1.468V     534.1mV
10.63ns   744.6mV    1.278V     528.6mV
21.27ns   716.1mV    1.049V     528.2mV
44.19ns   715.5mV    1.009V     528.2mV
[Falling Waveform]
R_fixture = 50
V_fixture = 0
V_fixture_min = 0
V_fixture_max = 0
0s        1.065V     656mV      1.346V
468ps     1.07V      655.9mV    1.324V
783ps     1.056V     656.4mV    1.162V
945ps     1.028V     658.7mV    933.3mV
1.341ns   863mV      665.1mV    140.8mV
1.503ns   733.7mV    661.1mV    13.4mV
2.133ns   162.5mV    587.6mV    797.7uV
2.439ns   18.86mV    513.2mV    406.1uV
3.996ns   492.4uV    45.54mV    94.32uV
6.003ns   176.9uV    1.636mV    28.02uV
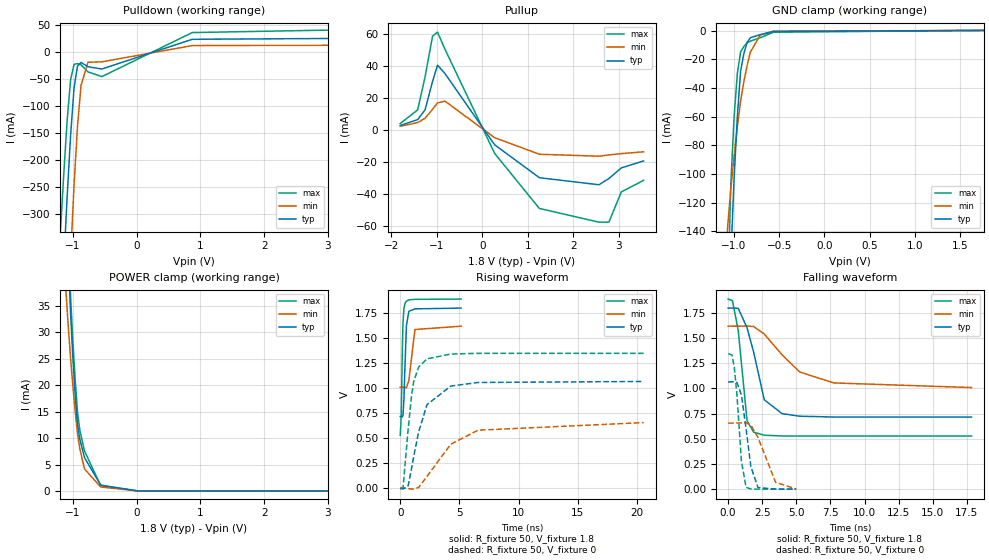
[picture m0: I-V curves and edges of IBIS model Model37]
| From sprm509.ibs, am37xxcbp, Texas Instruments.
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| Model based on original model for BQ18OMAPSMART1HYFBPB_SSBHH
|   Sub model FBPB_HS10L01_PD1_1P8
[model]   Model37
|[Input Load]   PD
|[Output Drive] SC10LB01
|Voltage   1.8V
|Mode   I/O
Model_type   I/O
Polarity   Non-Inverting
Enable   Active-Low
Vinl =  0.63
Vinh =  1.17
Cref =  15pF
Rref =  100.0000M
Vref =  0V
Vmeas =  0.9
C_comp   1.429432p   1.270657p   1.602015p
[Model Spec]
Vinl   0.63   0.567   0.6615
Vinh   1.17   1.053   1.2285
[Temperature Range]   25   125   -40
[Voltage Range]   1.8   1.62   1.89
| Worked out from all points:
|   slope of the pulldown table from 0 to 0.27 V, typ, clamps not added: 24.3 ohm
|   slope of the pullup table from 0 to 0.27 V, typ, clamps not added: 29.7 ohm
|   GND clamp passes 1 mA (typ) near -0.60 V on its own axis
|   POWER clamp passes 1 mA (typ) near -0.55 V on its own axis
|   rising waveform, R_fixture 50, V_fixture 1.8: 20-80 % time 178ps typ, 309ps min, 126ps max; typ from 0.715 V to 1.8 V
|   rising waveform, R_fixture 50, V_fixture 0: 20-80 % time 1.36ns typ, 2.99ns min, 719ps max; typ from 0 V to 1.06 V
|   falling waveform, R_fixture 50, V_fixture 1.8: 20-80 % time 1.06ns typ, 2.76ns min, 587ps max; typ from 1.8 V to 0.716 V
|   falling waveform, R_fixture 50, V_fixture 0: 20-80 % time 599ps typ, 1.03ns min, 422ps max; typ from 1.06 V to 0 V
[POWER_clamp]
-1.8V     362.5mA    191.4mA    412.8mA
-1.109V   56.74mA    37.73mA    60.49mA
-1.073V   44.66mA    31.25mA    47.92mA
-1.036V   33.51mA    25.07mA    36.71mA
-1V       25.05mA    19.75mA    28.19mA
-963.6mV  18.1mA     14.99mA    20.91mA
-927.3mV  12.67mA    10.8mA     14.87mA
-890.9mV  9.735mA    7.937mA    11.45mA
-818.2mV  6.3mA      4.158mA    7.553mA
-563.6mV  1.102mA    739.7uA    992.8uA
18.18mV   0A         0A         0A
3.6V      0A         0A         0A
[Pulldown]
-1.8V     -1.718A    -2.61A     -1.406A
-1.2V     -527.4mA   -844.5mA   -339.9mA
-1.145V   -396mA     -683.1mA   -229.1mA
-1.091V   -269mA     -526.7mA   -127.5mA
-1.036V   -153.6mA   -378.9mA   -51.17mA
-981.8mV  -66.33mA   -245.6mA   -22.67mA
-927.3mV  -26mA      -136.2mA   -21.54mA
-872.7mV  -19.34mA   -61.98mA   -23.69mA
-763.6mV  -27.2mA    -19.05mA   -36.72mA
-545.5mV  -31.39mA   -18.17mA   -45.46mA
872.7mV   23.46mA    11.88mA    35.92mA
3.545V    25.34mA    12.51mA    41.58mA
[Pullup]
-1.8V     2.903mA    2.423mA    4.112mA
-1.418V   6.595mA    4.711mA    12.64mA
-1.255V   12.69mA    7.42mA     33.24mA
-1.091V   30.4mA     13mA       58.69mA
-981.8mV  40.63mA    17.02mA    61.3mA
-818.2mV  35.38mA    18.12mA    50.59mA
272.7mV   -9.18mA    -4.728mA   -14.55mA
1.255V    -29.75mA   -15.09mA   -48.97mA
2.564V    -34.17mA   -16.31mA   -57.57mA
2.782V    -30.25mA   -15.5mA    -57.49mA
3.055V    -23.63mA   -14.68mA   -38.61mA
3.545V    -19.25mA   -13.56mA   -31.41mA
[GND_clamp]
-1.8V     -2.82A     -1.192A    -3.165A
-1.073V   -235.8mA   -138.4mA   -192.1mA
-1.036V   -159.6mA   -110.8mA   -107.6mA
-1V       -103.8mA   -87.86mA   -60.71mA
-963.6mV  -60.04mA   -67.29mA   -29.85mA
-927.3mV  -28.26mA   -49.1mA    -14.96mA
-890.9mV  -15.95mA   -35.5mA    -11.07mA
-854.5mV  -8.194mA   -24.09mA   -8.535mA
-818.2mV  -4.986mA   -14.87mA   -7.361mA
-709.1mV  -2.849mA   -3.094mA   -4.979mA
-563.6mV  -632.2uA   -437.1uA   -1.183mA
1.764V    97.78uA    55.01uA    156.3uA
[Ramp]
dV/dt_f  0.6515923/1.065032n   0.3684482/2.782582n   0.8180352/0.5890294n
dV/dt_r  0.6500947/1.363032n   0.4000917/3.017307n   0.8220579/0.720163n
R_load = 50
[Rising Waveform]
R_fixture = 50
V_fixture = 1.8
V_fixture_min = 1.62
V_fixture_max = 1.89
0s        715.2mV    1.007V     527.3mV
81ps      716.9mV    1.007V     708mV
180ps     709.8mV    1.007V     1.402V
234ps     733.8mV    1.007V     1.654V
315ps     894.7mV    1.008V     1.799V
396ps     1.203V     1.009V     1.843V
522ps     1.623V     1V         1.867V
729ps     1.766V     1.077V     1.88V
1.242ns   1.79V      1.584V     1.885V
5.139ns   1.798V     1.617V     1.888V
[Rising Waveform]
R_fixture = 50
V_fixture = 0
V_fixture_min = 0
V_fixture_max = 0
0s        -198.8uV   102.2uV    -10.05mV
243ps     -8.624mV   -229.4uV   12.07mV
666ps     21.83mV    -3.97mV    584.3mV
954ps     194.1mV    -8.718mV   923.4mV
1.143ns   319mV      -10.61mV   1.068V
1.557ns   561.9mV    6.73mV     1.209V
2.259ns   833.6mV    117.2mV    1.291V
4.266ns   1.019V     438.4mV    1.339V
6.579ns   1.055V     578.3mV    1.346V
20.56ns   1.065V     654.4mV    1.346V
[Falling Waveform]
R_fixture = 50
V_fixture = 1.8
V_fixture_min = 1.62
V_fixture_max = 1.89
0s        1.798V     1.619V     1.888V
315ps     1.799V     1.619V     1.872V
738ps     1.796V     1.618V     1.577V
1.386ns   1.603V     1.621V     678.2mV
1.872ns   1.359V     1.615V     565.9mV
2.646ns   888.3mV    1.541V     535.7mV
3.942ns   750.6mV    1.335V     528.8mV
5.238ns   724.6mV    1.164V     528.2mV
7.74ns    716.3mV    1.055V     528.2mV
17.84ns   715.5mV    1.009V     528.2mV
[Falling Waveform]
R_fixture = 50
V_fixture = 0
V_fixture_min = 0
V_fixture_max = 0
0s        1.065V     656mV      1.346V
288ps     1.066V     656.1mV    1.332V
450ps     1.069V     656mV      1.21V
648ps     1.058V     656.1mV    931.7mV
972ps     935.8mV    658.5mV    278.1mV
1.314ns   598.6mV    658.7mV    17.56mV
1.665ns   223.4mV    635.6mV    1.687mV
2.187ns   15.96mV    513.4mV    214.1uV
3.474ns   353uV      68.11mV    6.769uV
4.977ns   61.31uV    1.646mV    755.4nV
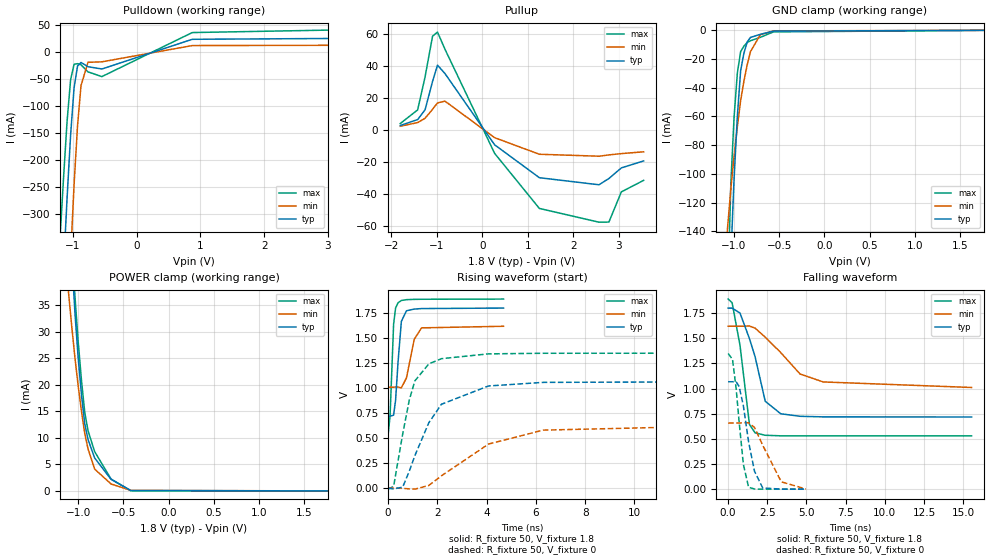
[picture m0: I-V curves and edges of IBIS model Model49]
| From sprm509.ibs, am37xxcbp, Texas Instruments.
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| Model based on original model for BQ18OMAPSMART1HYFBPB_SSBHH
|   Sub model PB_HS01L00_PUPD0_1P8
[model]   Model49
|[Input Load]   PI
|[Output Drive] SC01LB00
|Voltage   1.8V
|Mode   I/O
Model_type   I/O
Polarity   Non-Inverting
Enable   Active-Low
Vinl =  0.63
Vinh =  1.17
Cref =  15pF
Rref =  100.0000M
Vref =  0V
Vmeas =  0.9
C_comp   1.429432p   1.270657p   1.602015p
[Model Spec]
Vinl   0.63   0.567   0.6615
Vinh   1.17   1.053   1.2285
[Temperature Range]   25   125   -40
[Voltage Range]   1.8   1.62   1.89
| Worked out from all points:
|   slope of the pulldown table from 0 to 0.27 V, typ, clamps not added: 24.3 ohm
|   slope of the pullup table from 0 to 0.27 V, typ, clamps not added: 29.7 ohm
|   GND clamp passes 1 mA (typ) near -0.60 V on its own axis
|   POWER clamp passes 1 mA (typ) near -0.56 V on its own axis
|   rising waveform, R_fixture 50, V_fixture 1.8: 20-80 % time 177ps typ, 304ps min, 125ps max; typ from 0.717 V to 1.8 V
|   rising waveform, R_fixture 50, V_fixture 0: 20-80 % time 1.31ns typ, 2.88ns min, 693ps max; typ from 0 V to 1.07 V
|   falling waveform, R_fixture 50, V_fixture 1.8: 20-80 % time 1.09ns typ, 2.28ns min, 675ps max; typ from 1.8 V to 0.718 V
|   falling waveform, R_fixture 50, V_fixture 0: 20-80 % time 677ps typ, 1.11ns min, 495ps max; typ from 1.07 V to 0 V
[POWER_clamp]
-1.8V     362.5mA    191.4mA    412.8mA
-1.109V   56.69mA    37.71mA    60.38mA
-1.073V   44.6mA     31.22mA    47.8mA
-1.036V   33.44mA    25.04mA    36.59mA
-1V       24.98mA    19.72mA    28.06mA
-963.6mV  18.03mA    14.96mA    20.78mA
-927.3mV  12.59mA    10.77mA    14.74mA
-890.9mV  9.653mA    7.899mA    11.31mA
-818.2mV  6.214mA    4.114mA    7.414mA
-636.4mV  2.183mA    1.307mA    2.238mA
-418.2mV  83.85uA    105.2uA    35.14uA
1.764V    -1.228nA   -79.12nA   -1.453nA
[Pulldown]
-1.8V     -1.718A    -2.61A     -1.406A
-1.2V     -527.4mA   -844.5mA   -339.9mA
-1.145V   -396mA     -683.1mA   -229.1mA
-1.091V   -269mA     -526.7mA   -127.5mA
-1.036V   -153.6mA   -378.9mA   -51.17mA
-981.8mV  -66.34mA   -245.6mA   -22.67mA
-927.3mV  -26mA      -136.2mA   -21.54mA
-872.7mV  -19.34mA   -61.98mA   -23.69mA
-763.6mV  -27.2mA    -19.05mA   -36.72mA
-545.5mV  -31.39mA   -18.17mA   -45.46mA
872.7mV   23.46mA    11.88mA    35.92mA
3.545V    25.34mA    12.51mA    41.58mA
[Pullup]
-1.8V     2.903mA    2.423mA    4.112mA
-1.418V   6.595mA    4.711mA    12.64mA
-1.255V   12.69mA    7.42mA     33.23mA
-1.091V   30.4mA     13mA       58.69mA
-981.8mV  40.63mA    17.02mA    61.3mA
-818.2mV  35.38mA    18.12mA    50.59mA
272.7mV   -9.18mA    -4.728mA   -14.55mA
1.255V    -29.75mA   -15.09mA   -48.97mA
2.564V    -34.17mA   -16.31mA   -57.57mA
2.782V    -30.25mA   -15.5mA    -57.48mA
3.055V    -23.63mA   -14.68mA   -38.61mA
3.545V    -19.25mA   -13.56mA   -31.41mA
[GND_clamp]
-1.8V     -2.82A     -1.192A    -3.165A
-1.073V   -235.7mA   -138.4mA   -192.1mA
-1.036V   -159.5mA   -110.8mA   -107.5mA
-1V       -103.8mA   -87.85mA   -60.67mA
-963.6mV  -60mA      -67.28mA   -29.8mA
-927.3mV  -28.21mA   -49.08mA   -14.9mA
-890.9mV  -15.9mA    -35.48mA   -10.99mA
-854.5mV  -8.138mA   -24.07mA   -8.449mA
-818.2mV  -4.924mA   -14.85mA   -7.266mA
-709.1mV  -2.784mA   -3.064mA   -4.883mA
-563.6mV  -570.2uA   -404.5uA   -1.092mA
1.764V    -11.02pA   583.5nA    3.035nA
[Ramp]
dV/dt_f  0.6512866/1.093352n   0.3677056/2.294865n   0.8183203/0.677048n
dV/dt_r  0.6509084/1.312499n   0.4007424/2.902291n   0.8226274/0.6939892n
R_load = 50
[Rising Waveform]
R_fixture = 50
V_fixture = 1.8
V_fixture_min = 1.62
V_fixture_max = 1.89
0s        717.4mV    1.009V     528.4mV
81ps      718.8mV    1.009V     722.1mV
225ps     729.5mV    1.009V     1.639V
306ps     880.3mV    1.01V      1.801V
405ps     1.26V      1.011V     1.853V
540ps     1.667V     1.002V     1.876V
747ps     1.773V     1.102V     1.884V
1.062ns   1.79V      1.487V     1.887V
1.359ns   1.795V     1.602V     1.888V
4.689ns   1.8V       1.618V     1.89V
[Rising Waveform]
R_fixture = 50
V_fixture = 0
V_fixture_min = 0
V_fixture_max = 0
0s        -186.4uV   102.4uV    -10.8mV
225ps     -8.625mV   -219.2uV   16.75mV
594ps     9.694mV    -2.433mV   540.7mV
864ps     169.8mV    -7.985mV   883.5mV
1.089ns   324.8mV    -10.48mV   1.072V
1.656ns   653.7mV    26.55mV    1.242V
2.169ns   838.6mV    123.2mV    1.294V
4.077ns   1.021V     440mV      1.342V
6.3ns     1.057V     579.6mV    1.348V
19.8ns    1.067V     655.8mV    1.349V
[Falling Waveform]
R_fixture = 50
V_fixture = 1.8
V_fixture_min = 1.62
V_fixture_max = 1.89
0s        1.8V       1.62V      1.89V
252ps     1.8V       1.62V      1.854V
756ps     1.751V     1.62V      1.43V
1.359ns   1.497V     1.622V     643.6mV
1.719ns   1.317V     1.601V     560.1mV
2.367ns   873.6mV    1.511V     535.8mV
3.357ns   749.7mV    1.358V     530.4mV
4.59ns    724.5mV    1.145V     529.8mV
6.066ns   718.8mV    1.066V     529.8mV
15.54ns   717.6mV    1.011V     529.8mV
[Falling Waveform]
R_fixture = 50
V_fixture = 0
V_fixture_min = 0
V_fixture_max = 0
0s        1.068V     657.4mV    1.349V
279ps     1.068V     657.5mV    1.29V
504ps     1.07V      657.4mV    1.01V
702ps     1.02V      657.6mV    666.3mV
972ps     828mV      660.3mV    246.1mV
1.305ns   469.7mV    659.2mV    19.1mV
1.683ns   178mV      613.6mV    1.486mV
2.205ns   12.23mV    437mV      162.3uV
3.393ns   346.2uV    72.89mV    3.391uV
4.959ns   46.35uV    1.639mV    485.9nV
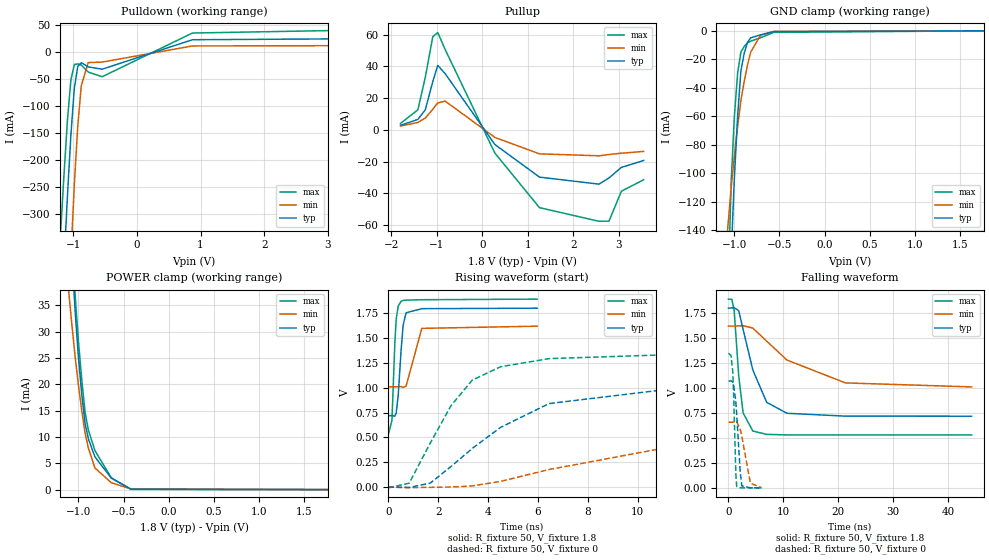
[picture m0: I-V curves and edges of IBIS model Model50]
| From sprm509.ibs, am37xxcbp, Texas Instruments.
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| Model based on original model for BQ18OMAPSMART1HYFBPB_SSBHH
|   Sub model PB_HS00L01_PUPD0_1P8
[model]   Model50
|[Input Load]   PI
|[Output Drive] SC00LB01
|Voltage   1.8V
|Mode   I/O
Model_type   I/O
Polarity   Non-Inverting
Enable   Active-Low
Vinl =  0.63
Vinh =  1.17
Cref =  15pF
Rref =  100.0000M
Vref =  0V
Vmeas =  0.9
C_comp   1.429432p   1.270657p   1.602015p
[Model Spec]
Vinl   0.63   0.567   0.6615
Vinh   1.17   1.053   1.2285
[Temperature Range]   25   125   -40
[Voltage Range]   1.8   1.62   1.89
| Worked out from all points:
|   slope of the pulldown table from 0 to 0.27 V, typ, clamps not added: 24.3 ohm
|   slope of the pullup table from 0 to 0.27 V, typ, clamps not added: 29.7 ohm
|   GND clamp passes 1 mA (typ) near -0.60 V on its own axis
|   POWER clamp passes 1 mA (typ) near -0.56 V on its own axis
|   rising waveform, R_fixture 50, V_fixture 1.8: 20-80 % time 177ps typ, 308ps min, 124ps max; typ from 0.718 V to 1.8 V
|   rising waveform, R_fixture 50, V_fixture 0: 20-80 % time 4.09ns typ, 9.4ns min, 2.05ns max; typ from 0 V to 1.07 V
|   falling waveform, R_fixture 50, V_fixture 1.8: 20-80 % time 3.37ns typ, 8.8ns min, 1.25ns max; typ from 1.8 V to 0.718 V
|   falling waveform, R_fixture 50, V_fixture 0: 20-80 % time 713ps typ, 1.21ns min, 411ps max; typ from 1.07 V to 0 V
[POWER_clamp]
-1.8V     362.5mA    191.4mA    412.8mA
-1.109V   56.69mA    37.71mA    60.38mA
-1.073V   44.6mA     31.22mA    47.8mA
-1.036V   33.44mA    25.04mA    36.59mA
-1V       24.98mA    19.72mA    28.06mA
-963.6mV  18.03mA    14.96mA    20.78mA
-927.3mV  12.59mA    10.77mA    14.74mA
-890.9mV  9.653mA    7.899mA    11.31mA
-818.2mV  6.214mA    4.114mA    7.414mA
-636.4mV  2.183mA    1.307mA    2.238mA
-418.2mV  83.85uA    105.2uA    35.14uA
1.764V    -1.228nA   -79.12nA   -1.453nA
[Pulldown]
-1.8V     -1.718A    -2.61A     -1.406A
-1.2V     -527.4mA   -844.5mA   -339.9mA
-1.145V   -396mA     -683.1mA   -229.1mA
-1.091V   -269mA     -526.7mA   -127.5mA
-1.036V   -153.6mA   -378.9mA   -51.17mA
-981.8mV  -66.34mA   -245.6mA   -22.67mA
-927.3mV  -26mA      -136.2mA   -21.54mA
-872.7mV  -19.34mA   -61.98mA   -23.69mA
-763.6mV  -27.2mA    -19.05mA   -36.72mA
-545.5mV  -31.39mA   -18.17mA   -45.46mA
872.7mV   23.46mA    11.88mA    35.92mA
3.545V    25.34mA    12.51mA    41.58mA
[Pullup]
-1.8V     2.903mA    2.423mA    4.112mA
-1.418V   6.595mA    4.711mA    12.64mA
-1.255V   12.69mA    7.42mA     33.23mA
-1.091V   30.4mA     13mA       58.69mA
-981.8mV  40.63mA    17.02mA    61.3mA
-818.2mV  35.38mA    18.12mA    50.59mA
272.7mV   -9.18mA    -4.728mA   -14.55mA
1.255V    -29.75mA   -15.09mA   -48.97mA
2.564V    -34.17mA   -16.31mA   -57.57mA
2.782V    -30.25mA   -15.5mA    -57.48mA
3.055V    -23.63mA   -14.68mA   -38.61mA
3.545V    -19.25mA   -13.56mA   -31.41mA
[GND_clamp]
-1.8V     -2.82A     -1.192A    -3.165A
-1.073V   -235.7mA   -138.4mA   -192.1mA
-1.036V   -159.5mA   -110.8mA   -107.5mA
-1V       -103.8mA   -87.85mA   -60.67mA
-963.6mV  -60mA      -67.28mA   -29.8mA
-927.3mV  -28.21mA   -49.08mA   -14.9mA
-890.9mV  -15.9mA    -35.48mA   -10.99mA
-854.5mV  -8.138mA   -24.07mA   -8.449mA
-818.2mV  -4.924mA   -14.85mA   -7.266mA
-709.1mV  -2.784mA   -3.064mA   -4.883mA
-563.6mV  -570.2uA   -404.5uA   -1.092mA
1.764V    -11.02pA   583.5nA    3.035nA
[Ramp]
dV/dt_f  0.6525411/3.379677n   0.3689267/8.872199n   0.8189435/1.247695n
dV/dt_r  0.6503958/4.103191n   0.4001003/9.478952n   0.8226372/2.055211n
R_load = 50
[Rising Waveform]
R_fixture = 50
V_fixture = 1.8
V_fixture_min = 1.62
V_fixture_max = 1.89
0s        717.7mV    1.009V     531.7mV
144ps     718.8mV    1.009V     671mV
261ps     713.3mV    1.009V     1.461V
315ps     747.2mV    1.009V     1.691V
396ps     926.8mV    1.01V      1.821V
513ps     1.383V     1.011V     1.869V
594ps     1.63V      1.002V     1.877V
711ps     1.753V     1.016V     1.88V
1.341ns   1.794V     1.596V     1.884V
5.967ns   1.799V     1.618V     1.89V
[Rising Waveform]
R_fixture = 50
V_fixture = 0
V_fixture_min = 0
V_fixture_max = 0
0s        -64.08uV   106.5uV    -7.606mV
837ps     -3.838mV   -5.308mV   39.8mV
1.683ns   40.36mV    -2.325mV   443.8mV
2.52ns    208.6mV    700.3uV    821.9mV
3.366ns   388.9mV    11.86mV    1.076V
4.5ns     600.4mV    57.35mV    1.21V
6.444ns   839.9mV    176.7mV    1.292V
12.57ns   1.024V     462.7mV    1.342V
20.79ns   1.06V      595.5mV    1.348V
60.41ns   1.067V     655.8mV    1.349V
[Falling Waveform]
R_fixture = 50
V_fixture = 1.8
V_fixture_min = 1.62
V_fixture_max = 1.89
0s        1.8V       1.62V      1.89V
621ps     1.802V     1.62V      1.888V
1.035ns   1.805V     1.62V      1.781V
1.872ns   1.774V     1.623V     1.12V
2.673ns   1.586V     1.624V     749.9mV
4.446ns   1.179V     1.6V       568.8mV
6.957ns   856.8mV    1.469V     535.7mV
10.65ns   746.8mV    1.28V      530.2mV
21.3ns    718.2mV    1.051V     529.8mV
44.26ns   717.6mV    1.011V     529.8mV
[Falling Waveform]
R_fixture = 50
V_fixture = 0
V_fixture_min = 0
V_fixture_max = 0
0s        1.068V     657.4mV    1.349V
468ps     1.072V     657.3mV    1.326V
783ps     1.059V     657.8mV    1.165V
945ps     1.03V      660.1mV    938.5mV
1.341ns   866.3mV    666.4mV    144.6mV
1.503ns   737.5mV    662.4mV    14.68mV
2.133ns   165.4mV    589.1mV    822.6uV
2.439ns   19.94mV    514.9mV    411.4uV
3.996ns   501.4uV    46.32mV    94.67uV
6.03ns    175.8uV    1.641mV    27.54uV
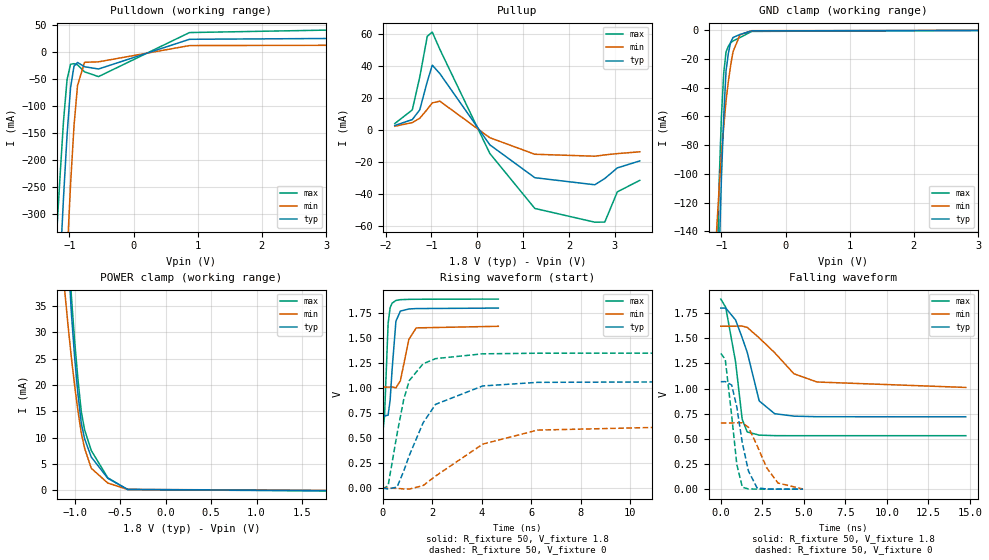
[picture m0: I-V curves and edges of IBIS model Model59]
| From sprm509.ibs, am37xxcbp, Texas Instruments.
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| Model based on original model for BQ18OMAPSMART1HYFBPB_SSBHH
|   Sub model FBPB_HS01L11_PU1_1P8
[model]   Model59
|[Input Load]   PU
|[Output Drive] SC01LB11
|Voltage   1.8V
|Mode   I/O
Model_type   I/O
Polarity   Non-Inverting
Enable   Active-Low
Vinl =  0.63
Vinh =  1.17
Cref =  15pF
Rref =  100.0000M
Vref =  0V
Vmeas =  0.9
C_comp   1.429432p   1.270657p   1.602015p
[Model Spec]
Vinl   0.63   0.567   0.6615
Vinh   1.17   1.053   1.2285
[Temperature Range]   25   125   -40
[Voltage Range]   1.8   1.62   1.89
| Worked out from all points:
|   slope of the pulldown table from 0 to 0.27 V, typ, clamps not added: 24.3 ohm
|   slope of the pullup table from 0 to 0.27 V, typ, clamps not added: 29.7 ohm
|   GND clamp passes 1 mA (typ) near -0.60 V on its own axis
|   POWER clamp passes 1 mA (typ) near -0.56 V on its own axis
|   rising waveform, R_fixture 50, V_fixture 1.8: 20-80 % time 175ps typ, 301ps min, 124ps max; typ from 0.72 V to 1.8 V
|   rising waveform, R_fixture 50, V_fixture 0: 20-80 % time 1.3ns typ, 2.85ns min, 686ps max; typ from 0.001 V to 1.07 V
|   falling waveform, R_fixture 50, V_fixture 1.8: 20-80 % time 1.1ns typ, 2.18ns min, 683ps max; typ from 1.8 V to 0.72 V
|   falling waveform, R_fixture 50, V_fixture 0: 20-80 % time 685ps typ, 1.12ns min, 501ps max; typ from 1.07 V to 0.001 V
[POWER_clamp]
-1.8V     362.5mA    191.4mA    412.8mA
-1.109V   56.76mA    37.74mA    60.51mA
-1.073V   44.67mA    31.25mA    47.93mA
-1.036V   33.52mA    25.07mA    36.72mA
-1V       25.06mA    19.75mA    28.2mA
-963.6mV  18.11mA    14.99mA    20.91mA
-927.3mV  12.67mA    10.8mA     14.87mA
-890.9mV  9.734mA    7.935mA    11.44mA
-818.2mV  6.293mA    4.153mA    7.536mA
-636.4mV  2.249mA    1.342mA    2.34mA
-418.2mV  128.7uA    129.3uA    104.4uA
1.764V    -96.73uA   -46.48uA   -163.5uA
[Pulldown]
-1.8V     -1.718A    -2.61A     -1.406A
-1.2V     -527.4mA   -844.5mA   -339.9mA
-1.145V   -396mA     -683.1mA   -229.1mA
-1.091V   -269mA     -526.7mA   -127.5mA
-1.036V   -153.6mA   -378.9mA   -51.17mA
-981.8mV  -66.33mA   -245.6mA   -22.67mA
-927.3mV  -26mA      -136.2mA   -21.54mA
-872.7mV  -19.34mA   -61.98mA   -23.69mA
-763.6mV  -27.2mA    -19.05mA   -36.72mA
-545.5mV  -31.39mA   -18.17mA   -45.46mA
872.7mV   23.46mA    11.88mA    35.92mA
3.545V    25.34mA    12.51mA    41.58mA
[Pullup]
-1.8V     2.903mA    2.423mA    4.112mA
-1.418V   6.595mA    4.711mA    12.64mA
-1.255V   12.69mA    7.42mA     33.24mA
-1.091V   30.4mA     13mA       58.69mA
-981.8mV  40.63mA    17.02mA    61.3mA
-818.2mV  35.38mA    18.12mA    50.59mA
272.7mV   -9.179mA   -4.728mA   -14.55mA
1.255V    -29.75mA   -15.09mA   -48.97mA
2.564V    -34.17mA   -16.31mA   -57.57mA
2.782V    -30.25mA   -15.5mA    -57.49mA
3.055V    -23.63mA   -14.68mA   -38.61mA
3.545V    -19.25mA   -13.56mA   -31.41mA
[GND_clamp]
-1.8V     -2.82A     -1.192A    -3.165A
-1.073V   -235.8mA   -138.4mA   -192.1mA
-1.036V   -159.6mA   -110.8mA   -107.6mA
-1V       -103.8mA   -87.86mA   -60.73mA
-963.6mV  -60.04mA   -67.29mA   -29.86mA
-927.3mV  -28.26mA   -49.09mA   -14.98mA
-890.9mV  -15.95mA   -35.49mA   -11.09mA
-854.5mV  -8.198mA   -24.09mA   -8.559mA
-818.2mV  -4.99mA    -14.87mA   -7.387mA
-709.1mV  -2.858mA   -3.093mA   -5.012mA
-527.3mV  -395.6uA   -260.4uA   -751.2uA
3.6V      0A         0A         0A
[Ramp]
dV/dt_f  0.6498805/1.10181n   0.3669482/2.198485n   0.8166674/0.6855857n
dV/dt_r  0.6498137/1.299885n   0.4004647/2.874548n   0.8204053/0.6872132n
R_load = 50
[Rising Waveform]
R_fixture = 50
V_fixture = 1.8
V_fixture_min = 1.62
V_fixture_max = 1.89
0s        719.7mV    1.011V     531mV
81ps      721.1mV    1.011V     724.3mV
225ps     730.9mV    1.01V      1.646V
306ps     879.3mV    1.011V     1.804V
387ps     1.189V     1.012V     1.849V
540ps     1.669V     1.003V     1.876V
720ps     1.77V      1.074V     1.884V
1.062ns   1.791V     1.487V     1.887V
1.359ns   1.795V     1.602V     1.888V
4.671ns   1.8V       1.618V     1.89V
[Rising Waveform]
R_fixture = 50
V_fixture = 0
V_fixture_min = 0
V_fixture_max = 0
0s        1.207mV    1.067mV    -8.987mV
225ps     -7.132mV   749.9uV    25.29mV
585ps     11.74mV    -1.021mV   541.9mV
855ps     171.6mV    -6.86mV    887.1mV
1.08ns    328mV      -8.68mV    1.076V
1.638ns   654.7mV    27.16mV    1.244V
2.142ns   838.7mV    122.2mV    1.295V
4.041ns   1.022V     441mV      1.343V
6.246ns   1.058V     580.9mV    1.349V
19.66ns   1.069V     657.1mV    1.35V
[Falling Waveform]
R_fixture = 50
V_fixture = 1.8
V_fixture_min = 1.62
V_fixture_max = 1.89
0s        1.8V       1.62V      1.89V
297ps     1.801V     1.62V      1.808V
891ps     1.682V     1.621V     1.265V
1.287ns   1.506V     1.622V     696.5mV
1.593ns   1.36V      1.608V     569.8mV
2.313ns   878mV      1.504V     538.3mV
3.24ns    751.4mV    1.358V     533.2mV
4.401ns   726.8mV    1.148V     532.6mV
5.796ns   721.2mV    1.066V     532.6mV
14.75ns   720mV      1.012V     532.6mV
[Falling Waveform]
R_fixture = 50
V_fixture = 0
V_fixture_min = 0
V_fixture_max = 0
0s        1.069V     658.7mV    1.35V
270ps     1.07V      658.9mV    1.29V
657ps     1.036V     658.8mV    730.2mV
963ps     818.1mV    661.4mV    247.9mV
1.296ns   460.2mV    661mV      21.11mV
1.665ns   181.9mV    615.6mV    3.34mV
2.178ns   15.49mV    437.1mV    1.949mV
2.763ns   2.807mV    213.9mV    1.792mV
3.447ns   1.692mV    62.45mV    1.775mV
4.95ns    1.432mV    2.607mV    1.773mV
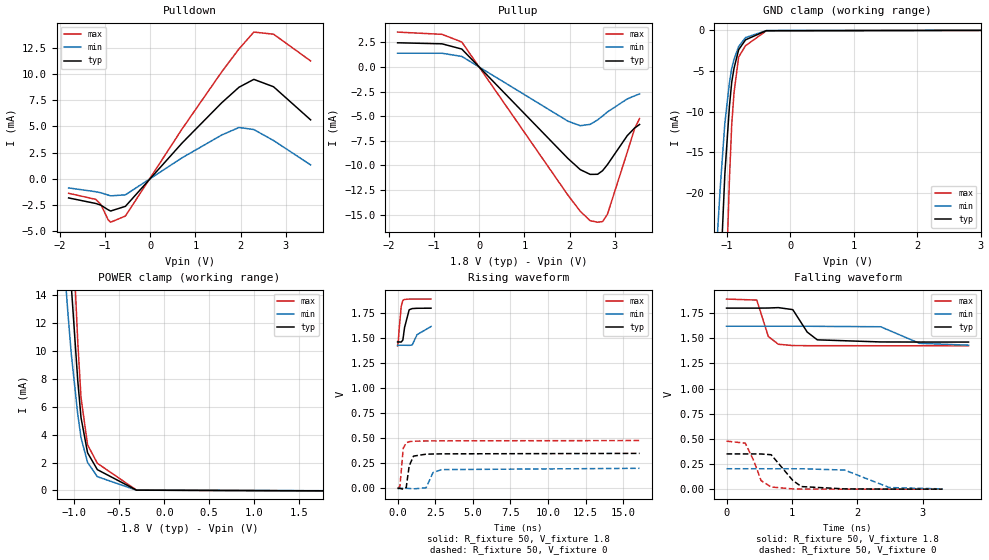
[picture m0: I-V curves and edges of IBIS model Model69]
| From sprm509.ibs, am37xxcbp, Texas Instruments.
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| Model based on original model for BQUSIM1833DVHYPBFZLP18NOPM_SSCHH
|   Sub model 18NOPM_SSCHH_PU1_1P8
[model]   Model69
|[Input Load]   PU
|[Output Drive]
|Voltage   1.8V
|Mode   I/O
Model_type   I/O
Polarity   Non-Inverting
Enable   Active-Low
Vinl =  0.54
Vinh =  1.26
Cref =  15pF
Rref =  100.0000M
Vref =  0V
Vmeas =  0.9
C_comp   1.861602p   1.830694p   1.903969p
[Model Spec]
Vinl   0.54   0.486   0.567
Vinh   1.26   1.134   1.323
[Temperature Range]   25   125   -40
[Voltage Range]   1.8   1.62   1.89
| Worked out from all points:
|   slope of the pulldown table from 0 to 0.27 V, typ, clamps not added: 203 ohm
|   slope of the pullup table from 0 to 0.27 V, typ, clamps not added: 200 ohm
|   GND clamp passes 1 mA (typ) near -0.68 V on its own axis
|   POWER clamp passes 1 mA (typ) near -0.64 V on its own axis
|   rising waveform, R_fixture 50, V_fixture 1.8: 20-80 % time 262ps typ, 623ps min, 160ps max; typ from 1.46 V to 1.8 V
|   rising waveform, R_fixture 50, V_fixture 0: 20-80 % time 209ps typ, 404ps min, 153ps max; typ from 0.001 V to 0.35 V
|   falling waveform, R_fixture 50, V_fixture 1.8: 20-80 % time 196ps typ, 345ps min, 120ps max; typ from 1.8 V to 1.46 V
|   falling waveform, R_fixture 50, V_fixture 0: 20-80 % time 257ps typ, 410ps min, 175ps max; typ from 0.352 V to 0.002 V
[POWER_clamp]
-1.8V     131.5mA    94.49mA    182.1mA
-1.182V   33.74mA    22.71mA    48.21mA
-1.145V   28.59mA    19.11mA    40.96mA
-1.109V   23.74mA    15.81mA    34.03mA
-1.073V   19.11mA    12.71mA    27.35mA
-1.036V   14.72mA    9.81mA     20.94mA
-963.6mV  7.873mA    5.456mA    10.66mA
-927.3mV  5.231mA    3.787mA    6.668mA
-854.5mV  2.706mA    2.016mA    3.279mA
-745.5mV  1.494mA    989.9uA    1.95mA
-309.1mV  22.26uA    18.86uA    24.06uA
1.764V    -25.13uA   -15.15uA   -34.06uA
[Pulldown]
-1.8V     -1.828mA   -873.3uA   -1.385mA
-1.2V     -2.358mA   -1.237mA   -1.965mA
-1.091V   -2.51mA    -1.332mA   -2.432mA
-927.3mV  -2.959mA   -1.552mA   -3.908mA
-872.7mV  -3.077mA   -1.631mA   -4.142mA
-545.5mV  -2.629mA   -1.532mA   -3.555mA
709.1mV   3.423mA    2.009mA    4.77mA
1.582V    7.249mA    4.174mA    10.2mA
1.964V    8.732mA    4.891mA    12.39mA
2.291V    9.481mA    4.693mA    13.99mA
2.727V    8.774mA    3.647mA    13.79mA
3.545V    5.619mA    1.322mA    11.24mA
[Pullup]
-1.8V     2.468mA    1.407mA    3.554mA
-818.2mV  2.361mA    1.402mA    3.325mA
-381.8mV  1.828mA    1.082mA    2.546mA
1.964V    -9.297mA   -5.505mA   -13.03mA
2.236V    -10.43mA   -5.962mA   -14.67mA
2.455V    -10.91mA   -5.824mA   -15.62mA
2.618V    -10.9mA    -5.37mA    -15.77mA
2.727V    -10.54mA   -4.977mA   -15.71mA
2.836V    -9.913mA   -4.562mA   -14.96mA
3.273V    -6.975mA   -3.239mA   -8.659mA
3.436V    -6.195mA   -2.926mA   -6.256mA
3.545V    -5.839mA   -2.725mA   -5.231mA
[GND_clamp]
-1.8V     -212.9mA   -139.2mA   -381.7mA
-1.218V   -55.61mA   -34.83mA   -107mA
-1.145V   -38.5mA    -24.06mA   -75.74mA
-1.109V   -30.91mA   -19.42mA   -61.46mA
-1.036V   -17.71mA   -11.45mA   -36.01mA
-963.6mV  -9.345mA   -6.451mA   -18.33mA
-927.3mV  -6.377mA   -4.667mA   -11.57mA
-890.9mV  -4.67mA    -3.57mA    -7.663mA
-818.2mV  -2.391mA   -1.988mA   -3.281mA
-709.1mV  -1.167mA   -888.8uA   -1.888mA
-381.8mV  -41.12uA   -30.52uA   -62.94uA
3.6V      0A         0A         0A
[Ramp]
dV/dt_f  0.2058747/0.1864568n  0.1163976/0.35641n   0.2827315/0.1205703n
dV/dt_r  0.2155523/0.2092291n  0.1251918/0.3879291n  0.2934527/0.1552119n
R_load = 50
[Rising Waveform]
R_fixture = 50
V_fixture = 1.8
V_fixture_min = 1.62
V_fixture_max = 1.89
0s        1.462V     1.428V     1.422V
44ps      1.462V     1.429V     1.461V
110ps     1.462V     1.429V     1.602V
242ps     1.461V     1.429V     1.818V
352ps     1.482V     1.429V     1.876V
462ps     1.605V     1.429V     1.886V
770ps     1.783V     1.428V     1.89V
968ps     1.795V     1.432V     1.89V
1.298ns   1.798V     1.535V     1.89V
2.222ns   1.799V     1.616V     1.89V
[Rising Waveform]
R_fixture = 50
V_fixture = 0
V_fixture_min = 0
V_fixture_max = 0
0s        1.01mV     494.6uV    -2.589mV
154ps     1.671mV    660.3uV    20.79mV
374ps     -7.179mV   584.4uV    399.9mV
572ps     8.643mV    884.5uV    455.2mV
770ps     224.2mV    178uV      467mV
1.056ns   322.5mV    -4.343mV   471.5mV
1.892ns   341.9mV    6.659mV    474mV
2.354ns   343.8mV    158.1mV    474.6mV
2.926ns   345.2mV    188mV      475.2mV
16.08ns   349.8mV    201mV      477.8mV
[Falling Waveform]
R_fixture = 50
V_fixture = 1.8
V_fixture_min = 1.62
V_fixture_max = 1.89
0s        1.8V       1.62V      1.89V
462ps     1.8V       1.62V      1.88V
638ps     1.801V     1.62V      1.518V
792ps     1.805V     1.62V      1.441V
1.012ns   1.785V     1.62V      1.428V
1.232ns   1.562V     1.62V      1.427V
1.386ns   1.485V     1.619V     1.427V
2.354ns   1.464V     1.615V     1.426V
2.948ns   1.463V     1.45V      1.426V
3.696ns   1.463V     1.432V     1.426V
[Falling Waveform]
R_fixture = 50
V_fixture = 0
V_fixture_min = 0
V_fixture_max = 0
0s        351.6mV    204.2mV    478.5mV
286ps     351.5mV    204.3mV    458.4mV
418ps     351.3mV    204.3mV    281.1mV
528ps     350.9mV    204.2mV    86.31mV
682ps     343.5mV    204.2mV    22.81mV
1.012ns   87.9mV     204.1mV    3.81mV
1.144ns   27.11mV    204.1mV    2.522mV
1.804ns   4.082mV    191.2mV    1.517mV
2.486ns   2.277mV    17.63mV    1.437mV
3.3ns     1.723mV    3.913mV    1.409mV
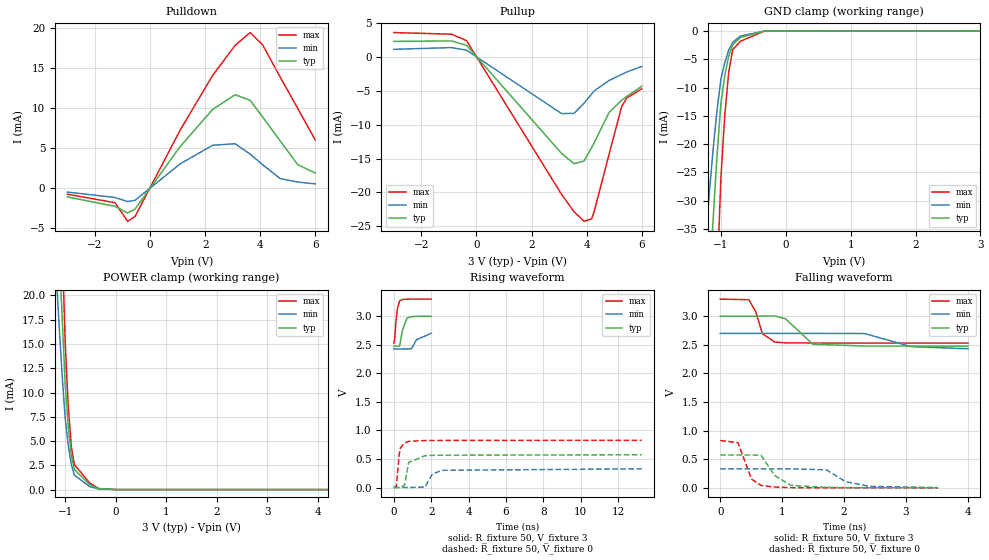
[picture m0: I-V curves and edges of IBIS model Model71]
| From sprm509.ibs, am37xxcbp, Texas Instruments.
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| Model based on original model for BQUSIM1833DVHYPBFZLP18NOPM_SSCHH
|   Sub model LP18NOPM_SSCHH_PD1_3
[model]   Model71
|[Input Load]   PD
|[Output Drive]
|Voltage   3V
|Mode   I/O
Model_type   I/O
Polarity   Non-Inverting
Enable   Active-Low
Vinl =  0.9
Vinh =  2.1
Cref =  15pF
Rref =  100.0000M
Vref =  0V
Vmeas =  1.5
C_comp   1.710183p   1.606508p   1.731375p
[Model Spec]
Vinl   0.9   0.81   0.99
Vinh   2.1   1.89   2.31
[Temperature Range]   25   125   -40
[Voltage Range]   3   2.7   3.3
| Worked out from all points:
|   slope of the pulldown table from 0 to 0.45 V, typ, clamps not added: 205 ohm
|   slope of the pullup table from 0 to 0.45 V, typ, clamps not added: 200 ohm
|   GND clamp passes 1 mA (typ) near -0.68 V on its own axis
|   POWER clamp passes 1 mA (typ) near -0.64 V on its own axis
|   rising waveform, R_fixture 50, V_fixture 3: 20-80 % time 226ps typ, 531ps min, 139ps max; typ from 2.48 V to 3 V
|   rising waveform, R_fixture 50, V_fixture 0: 20-80 % time 195ps typ, 352ps min, 138ps max; typ from 0 V to 0.573 V
|   falling waveform, R_fixture 50, V_fixture 3: 20-80 % time 237ps typ, 451ps min, 141ps max; typ from 3 V to 2.48 V
|   falling waveform, R_fixture 50, V_fixture 0: 20-80 % time 240ps typ, 350ps min, 165ps max; typ from 0.575 V to 0.001 V
[POWER_clamp]
-3V       333.5mA    280.6mA    454.3mA
-1.182V   33.69mA    22.66mA    48.16mA
-1.121V   25.44mA    16.99mA    36.43mA
-1.061V   17.84mA    11.89mA    25.45mA
-1V       10.89mA    7.36mA     15.23mA
-939.4mV  6.517mA    4.58mA     8.652mA
-878.8mV  3.577mA    2.626mA    4.436mA
-818.2mV  2.074mA    1.496mA    2.581mA
-515.2mV  519.6uA    314.1uA    689.4uA
-333.3mV  82.5uA     53.66uA    108.6uA
30.3mV    0A         0A         0A
6V        0A         0A         0A
[Pulldown]
-3V       -1.107mA   -507.6uA   -770.6uA
-1.273V   -2.288mA   -1.185mA   -1.831mA
-818.2mV  -3.117mA   -1.689mA   -4.154mA
-545.5mV  -2.629mA   -1.532mA   -3.555mA
1.091V    5.159mA    3.011mA    7.214mA
2.273V    9.809mA    5.337mA    14.05mA
3.091V    11.64mA    5.526mA    17.81mA
3.636V    10.95mA    4.227mA    19.4mA
4.091V    8.846mA    2.905mA    17.85mA
4.727V    5.879mA    1.177mA    13.84mA
5.364V    2.909mA    743.5uA    9.93mA
6V        1.868mA    517.6uA    6.001mA
[Pullup]
-3V       2.34mA     1.168mA    3.647mA
-909.1mV  2.41mA     1.426mA    3.408mA
-363.6mV  1.769mA    1.046mA    2.465mA
3.091V    -14.22mA   -8.331mA   -20.28mA
3.545V    -15.74mA   -8.296mA   -22.85mA
3.909V    -15.34mA   -6.8mA     -24.26mA
4.182V    -13.37mA   -5.445mA   -23.9mA
4.273V    -12.67mA   -4.985mA   -22.85mA
4.818V    -8.149mA   -3.439mA   -14.34mA
5.273V    -6.367mA   -2.536mA   -7.301mA
5.455V    -5.802mA   -2.193mA   -6.042mA
6V        -4.302mA   -1.361mA   -4.674mA
[GND_clamp]
-3V       -555.8mA   -408.9mA   -966.1mA
-1.242V   -61.72mA   -38.75mA   -117.9mA
-1.182V   -46.84mA   -29.26mA   -91.09mA
-1.121V   -33.7mA    -21.16mA   -66.62mA
-1.061V   -22.38mA   -14.25mA   -44.97mA
-1V       -12.87mA   -8.546mA   -26.12mA
-939.4mV  -7.879mA   -5.541mA   -14.87mA
-878.8mV  -4.395mA   -3.36mA    -7.262mA
-818.2mV  -2.418mA   -2.002mA   -3.304mA
-697mV    -1.118mA   -863.5uA   -1.784mA
-333.3mV  -9.981uA   -12.12uA   -15.46uA
3V        36.96uA    33.14uA    51.69uA
[Ramp]
dV/dt_f  0.3167341/0.231645n   0.1656139/0.464672n   0.4657876/0.1418459n
dV/dt_r  0.3511422/0.1929184n  0.2028061/0.3520992n  0.5044498/0.1385829n
R_load = 50
[Rising Waveform]
R_fixture = 50
V_fixture = 3
V_fixture_min = 2.7
V_fixture_max = 3.3
0s        2.477V     2.426V     2.526V
44ps      2.476V     2.426V     2.607V
110ps     2.477V     2.426V     2.903V
198ps     2.477V     2.426V     3.144V
308ps     2.475V     2.426V     3.266V
462ps     2.758V     2.426V     3.292V
704ps     2.966V     2.427V     3.297V
946ps     2.992V     2.43V      3.298V
1.21ns    2.996V     2.587V     3.298V
2.002ns   2.997V     2.7V       3.298V
[Rising Waveform]
R_fixture = 50
V_fixture = 0
V_fixture_min = 0
V_fixture_max = 0
0s        -16.55uV   -107.9uV   -3.86mV
132ps     404.3uV    69.47uV    20.88mV
286ps     -2.226mV   -12.79uV   578.2mV
352ps     -6.189mV   -19.26uV   691.7mV
572ps     41.42mV    282.5uV    780.2mV
792ps     438.4mV    -611.1uV   808.6mV
1.672ns   556.7mV    8.246mV    822.2mV
2.068ns   562.2mV    240.2mV    823mV
2.596ns   565.6mV    300.6mV    823.7mV
13.27ns   572.9mV    327.4mV    826.7mV
[Falling Waveform]
R_fixture = 50
V_fixture = 3
V_fixture_min = 2.7
V_fixture_max = 3.3
0s        2.999V     2.699V     3.298V
462ps     2.999V     2.699V     3.288V
572ps     2.998V     2.699V     3.081V
682ps     3.002V     2.699V     2.694V
880ps     3.004V     2.699V     2.548V
1.056ns   2.954V     2.699V     2.534V
1.496ns   2.509V     2.699V     2.531V
2.332ns   2.479V     2.697V     2.53V
3.08ns    2.478V     2.469V     2.53V
4.004ns   2.477V     2.43V      2.53V
[Falling Waveform]
R_fixture = 50
V_fixture = 0
V_fixture_min = 0
V_fixture_max = 0
0s        575.4mV    332.8mV    827.3mV
286ps     575.3mV    332.9mV    790.4mV
506ps     575.2mV    332.8mV    152.4mV
660ps     568.6mV    332.8mV    41.92mV
880ps     215.2mV    332.7mV    13.96mV
1.144ns   42.7mV     332.7mV    4.032mV
1.716ns   8.95mV     314.5mV    469.5uV
2.024ns   4.682mV    108.7mV    247.4uV
2.42ns    2.452mV    25.4mV     157uV
3.52ns    996.2uV    5.552mV    85.09uV
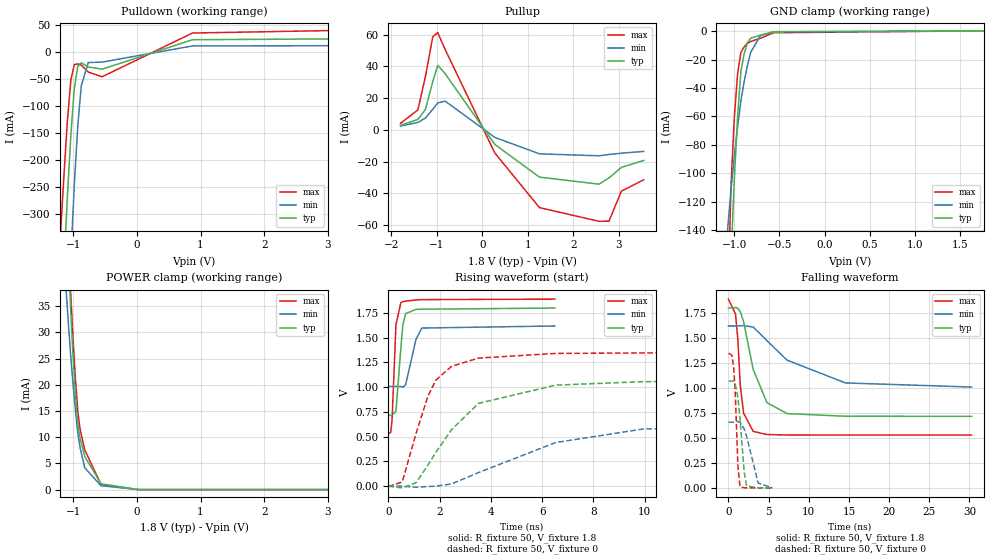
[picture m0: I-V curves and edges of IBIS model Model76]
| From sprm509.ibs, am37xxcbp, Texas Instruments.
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| Model based on original model for BQ18OMAPSMART1HYFBPBNOPM_SSBHV
|   Sub model NOPM_VS00L11_PD1_1P8
[model]   Model76
|[Input Load]   PD
|[Output Drive] SC00LB11
|Voltage   1.8V
|Mode   I/O
Model_type   I/O
Polarity   Non-Inverting
Enable   Active-Low
Vinl =  0.63
Vinh =  1.17
Cref =  15pF
Rref =  100.0000M
Vref =  0V
Vmeas =  0.9
C_comp   1.410688p   1.256095p   1.577871p
[Model Spec]
Vinl   0.63   0.567   0.6615
Vinh   1.17   1.053   1.2285
[Temperature Range]   25   125   -40
[Voltage Range]   1.8   1.62   1.89
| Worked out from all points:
|   slope of the pulldown table from 0 to 0.27 V, typ, clamps not added: 24.3 ohm
|   slope of the pullup table from 0 to 0.27 V, typ, clamps not added: 29.7 ohm
|   GND clamp passes 1 mA (typ) near -0.60 V on its own axis
|   POWER clamp passes 1 mA (typ) near -0.55 V on its own axis
|   rising waveform, R_fixture 50, V_fixture 1.8: 20-80 % time 176ps typ, 311ps min, 124ps max; typ from 0.715 V to 1.8 V
|   rising waveform, R_fixture 50, V_fixture 0: 20-80 % time 2.08ns typ, 4.63ns min, 1.07ns max; typ from 0 V to 1.06 V
|   falling waveform, R_fixture 50, V_fixture 1.8: 20-80 % time 2.09ns typ, 5.91ns min, 725ps max; typ from 1.8 V to 0.715 V
|   falling waveform, R_fixture 50, V_fixture 0: 20-80 % time 636ps typ, 1.14ns min, 381ps max; typ from 1.06 V to 0 V
[POWER_clamp]
-1.8V     362.5mA    191.4mA    412.8mA
-1.109V   56.75mA    37.73mA    60.5mA
-1.073V   44.66mA    31.25mA    47.93mA
-1.036V   33.51mA    25.07mA    36.73mA
-1V       25.06mA    19.75mA    28.2mA
-963.6mV  18.11mA    14.99mA    20.92mA
-927.3mV  12.68mA    10.81mA    14.88mA
-890.9mV  9.743mA    7.94mA     11.46mA
-818.2mV  6.308mA    4.161mA    7.567mA
-563.6mV  1.112mA    743.5uA    1.008mA
18.18mV   0A         0A         0A
3.6V      0A         0A         0A
[Pulldown]
-1.8V     -1.718A    -2.61A     -1.406A
-1.2V     -527.4mA   -844.5mA   -339.9mA
-1.145V   -396mA     -683.1mA   -229.1mA
-1.091V   -269mA     -526.7mA   -127.5mA
-1.036V   -153.6mA   -378.9mA   -51.17mA
-981.8mV  -66.33mA   -245.6mA   -22.67mA
-927.3mV  -26mA      -136.2mA   -21.54mA
-872.7mV  -19.34mA   -61.98mA   -23.69mA
-763.6mV  -27.2mA    -19.05mA   -36.72mA
-545.5mV  -31.39mA   -18.17mA   -45.46mA
872.7mV   23.46mA    11.88mA    35.92mA
3.545V    25.34mA    12.51mA    41.58mA
[Pullup]
-1.8V     2.903mA    2.423mA    4.112mA
-1.418V   6.595mA    4.711mA    12.64mA
-1.255V   12.69mA    7.42mA     33.24mA
-1.091V   30.4mA     13mA       58.69mA
-981.8mV  40.63mA    17.02mA    61.3mA
-818.2mV  35.38mA    18.12mA    50.59mA
272.7mV   -9.18mA    -4.728mA   -14.55mA
1.255V    -29.75mA   -15.09mA   -48.97mA
2.564V    -34.17mA   -16.31mA   -57.57mA
2.782V    -30.25mA   -15.5mA    -57.49mA
3.055V    -23.63mA   -14.68mA   -38.61mA
3.545V    -19.25mA   -13.56mA   -31.41mA
[GND_clamp]
-1.8V     -2.82A     -1.192A    -3.165A
-1.073V   -235.8mA   -138.4mA   -192.1mA
-1.036V   -159.6mA   -110.8mA   -107.6mA
-1V       -103.8mA   -87.86mA   -60.72mA
-963.6mV  -60.04mA   -67.29mA   -29.85mA
-927.3mV  -28.26mA   -49.1mA    -14.96mA
-890.9mV  -15.95mA   -35.5mA    -11.07mA
-854.5mV  -8.196mA   -24.09mA   -8.539mA
-818.2mV  -4.988mA   -14.87mA   -7.364mA
-709.1mV  -2.851mA   -3.095mA   -4.982mA
-563.6mV  -633.9uA   -437.8uA   -1.185mA
1.764V    107.4uA    58.81uA    171.2uA
[Ramp]
dV/dt_f  0.6523211/2.090411n   0.3692389/5.95123n   0.8182371/0.7235562n
dV/dt_r  0.6504498/2.087337n   0.4000054/4.672076n   0.8229039/1.076424n
R_load = 50
[Rising Waveform]
R_fixture = 50
V_fixture = 1.8
V_fixture_min = 1.62
V_fixture_max = 1.89
0s        715.4mV    1.007V     530.1mV
90ps      715.5mV    1.007V     542.7mV
144ps     717.6mV    1.007V     666.3mV
297ps     756.8mV    1.007V     1.631V
486ps     1.388V     1.007V     1.851V
567ps     1.63V      997.9mV    1.863V
675ps     1.742V     1.026V     1.868V
1.08ns    1.785V     1.484V     1.88V
1.305ns   1.786V     1.596V     1.883V
6.498ns   1.798V     1.617V     1.888V
[Rising Waveform]
R_fixture = 50
V_fixture = 0
V_fixture_min = 0
V_fixture_max = 0
0s        -327.4uV   112.5uV    -3.551mV
540ps     -16.73mV   -593.6uV   42.44mV
1.08ns    35.02mV    -10.47mV   531.7mV
1.548ns   213.6mV    -2.971mV   910.6mV
1.854ns   341mV      376.3uV    1.071V
2.466ns   570.7mV    23.01mV    1.21V
3.519ns   836.2mV    137.6mV    1.293V
6.525ns   1.02V      440.4mV    1.34V
9.945ns   1.055V     577.3mV    1.345V
30.33ns   1.065V     654.3mV    1.346V
[Falling Waveform]
R_fixture = 50
V_fixture = 1.8
V_fixture_min = 1.62
V_fixture_max = 1.89
0s        1.798V     1.618V     1.887V
882ps     1.803V     1.618V     1.737V
1.179ns   1.795V     1.619V     1.477V
1.467ns   1.762V     1.621V     1.031V
1.881ns   1.662V     1.622V     748.2mV
3.078ns   1.185V     1.608V     565mV
4.788ns   852mV      1.472V     533.2mV
7.299ns   742.9mV    1.277V     528.5mV
14.57ns   715.8mV    1.049V     528.1mV
30.27ns   715.4mV    1.008V     528.1mV
[Falling Waveform]
R_fixture = 50
V_fixture = 0
V_fixture_min = 0
V_fixture_max = 0
0s        1.065V     655.9mV    1.346V
432ps     1.069V     655.8mV    1.326V
666ps     1.062V     656.2mV    1.196V
855ps     1.032V     658.7mV    932.4mV
1.179ns   907.9mV    663.5mV    220.6mV
1.44ns    692mV      655.7mV    10.61mV
1.962ns   157.7mV    588.7mV    943.7uV
2.259ns   18.86mV    514.7mV    393.4uV
3.708ns   448.1uV    47.96mV    48.08uV
5.472ns   135.4uV    1.627mV    9.49uV
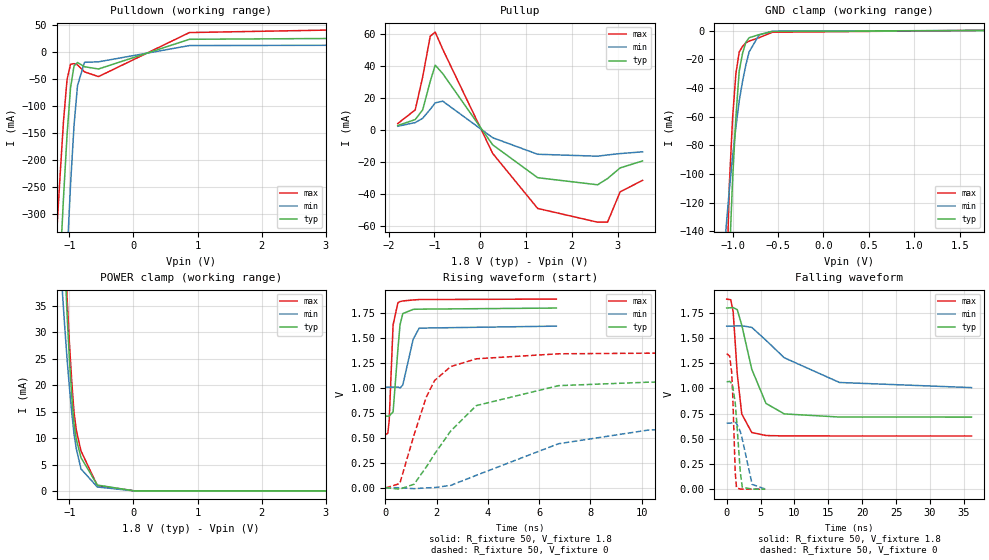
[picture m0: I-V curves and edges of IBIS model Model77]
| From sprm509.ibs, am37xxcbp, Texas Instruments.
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| Model based on original model for BQ18OMAPSMART1HYFBPBNOPM_SSBHV
|   Sub model NOPM_VS00L10_PD1_1P8
[model]   Model77
|[Input Load]   PD
|[Output Drive] SC00LB10
|Voltage   1.8V
|Mode   I/O
Model_type   I/O
Polarity   Non-Inverting
Enable   Active-Low
Vinl =  0.63
Vinh =  1.17
Cref =  15pF
Rref =  100.0000M
Vref =  0V
Vmeas =  0.9
C_comp   1.410688p   1.256095p   1.577871p
[Model Spec]
Vinl   0.63   0.567   0.6615
Vinh   1.17   1.053   1.2285
[Temperature Range]   25   125   -40
[Voltage Range]   1.8   1.62   1.89
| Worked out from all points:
|   slope of the pulldown table from 0 to 0.27 V, typ, clamps not added: 24.3 ohm
|   slope of the pullup table from 0 to 0.27 V, typ, clamps not added: 29.7 ohm
|   GND clamp passes 1 mA (typ) near -0.60 V on its own axis
|   POWER clamp passes 1 mA (typ) near -0.55 V on its own axis
|   rising waveform, R_fixture 50, V_fixture 1.8: 20-80 % time 177ps typ, 312ps min, 124ps max; typ from 0.715 V to 1.8 V
|   rising waveform, R_fixture 50, V_fixture 0: 20-80 % time 2.14ns typ, 4.77ns min, 1.1ns max; typ from 0 V to 1.06 V
|   falling waveform, R_fixture 50, V_fixture 1.8: 20-80 % time 2.7ns typ, 7.22ns min, 932ps max; typ from 1.8 V to 0.715 V
|   falling waveform, R_fixture 50, V_fixture 0: 20-80 % time 691ps typ, 1.18ns min, 393ps max; typ from 1.06 V to 0 V
[POWER_clamp]
-1.8V     362.5mA    191.4mA    412.8mA
-1.109V   56.75mA    37.73mA    60.5mA
-1.073V   44.66mA    31.25mA    47.93mA
-1.036V   33.51mA    25.07mA    36.73mA
-1V       25.06mA    19.75mA    28.2mA
-963.6mV  18.11mA    14.99mA    20.92mA
-927.3mV  12.68mA    10.81mA    14.88mA
-890.9mV  9.743mA    7.94mA     11.46mA
-818.2mV  6.308mA    4.161mA    7.567mA
-563.6mV  1.112mA    743.5uA    1.008mA
18.18mV   0A         0A         0A
3.6V      0A         0A         0A
[Pulldown]
-1.8V     -1.718A    -2.61A     -1.406A
-1.2V     -527.4mA   -844.5mA   -339.9mA
-1.145V   -396mA     -683.1mA   -229.1mA
-1.091V   -269mA     -526.7mA   -127.5mA
-1.036V   -153.6mA   -378.9mA   -51.17mA
-981.8mV  -66.33mA   -245.6mA   -22.67mA
-927.3mV  -26mA      -136.2mA   -21.54mA
-872.7mV  -19.34mA   -61.98mA   -23.69mA
-763.6mV  -27.2mA    -19.05mA   -36.72mA
-545.5mV  -31.39mA   -18.17mA   -45.46mA
872.7mV   23.46mA    11.88mA    35.92mA
3.545V    25.34mA    12.51mA    41.58mA
[Pullup]
-1.8V     2.903mA    2.423mA    4.112mA
-1.418V   6.595mA    4.711mA    12.64mA
-1.255V   12.69mA    7.42mA     33.24mA
-1.091V   30.4mA     13mA       58.69mA
-981.8mV  40.63mA    17.02mA    61.3mA
-818.2mV  35.38mA    18.12mA    50.59mA
272.7mV   -9.18mA    -4.728mA   -14.55mA
1.255V    -29.75mA   -15.09mA   -48.97mA
2.564V    -34.17mA   -16.31mA   -57.57mA
2.782V    -30.25mA   -15.5mA    -57.49mA
3.055V    -23.63mA   -14.68mA   -38.61mA
3.545V    -19.25mA   -13.56mA   -31.41mA
[GND_clamp]
-1.8V     -2.82A     -1.192A    -3.165A
-1.073V   -235.8mA   -138.4mA   -192.1mA
-1.036V   -159.6mA   -110.8mA   -107.6mA
-1V       -103.8mA   -87.86mA   -60.72mA
-963.6mV  -60.04mA   -67.29mA   -29.85mA
-927.3mV  -28.26mA   -49.1mA    -14.96mA
-890.9mV  -15.95mA   -35.5mA    -11.07mA
-854.5mV  -8.196mA   -24.09mA   -8.539mA
-818.2mV  -4.988mA   -14.87mA   -7.364mA
-709.1mV  -2.851mA   -3.095mA   -4.982mA
-563.6mV  -633.9uA   -437.8uA   -1.185mA
1.764V    107.4uA    58.81uA    171.2uA
[Ramp]
dV/dt_f  0.6524989/2.701306n   0.3693483/7.280815n   0.8185255/0.9282894n
dV/dt_r  0.6502591/2.147465n   0.3998879/4.819341n   0.8226611/1.10275n
R_load = 50
[Rising Waveform]
R_fixture = 50
V_fixture = 1.8
V_fixture_min = 1.62
V_fixture_max = 1.89
0s        715.4mV    1.007V     530.2mV
90ps      715.5mV    1.007V     543.4mV
144ps     717.7mV    1.007V     667.7mV
297ps     758.2mV    1.007V     1.63V
486ps     1.388V     1.007V     1.852V
567ps     1.63V      998mV      1.863V
675ps     1.742V     1.027V     1.869V
1.08ns    1.785V     1.485V     1.879V
1.314ns   1.787V     1.597V     1.883V
6.669ns   1.798V     1.617V     1.888V
[Rising Waveform]
R_fixture = 50
V_fixture = 0
V_fixture_min = 0
V_fixture_max = 0
0s        -329.9uV   112.8uV    -3.664mV
558ps     -15.37mV   -1.108mV   41.18mV
1.116ns   34.49mV    -10.52mV   528.9mV
1.593ns   207.1mV    -2.533mV   907.2mV
1.917ns   337.4mV    649.4uV    1.073V
2.547ns   567.5mV    22.36mV    1.212V
3.546ns   821.5mV    123.3mV    1.29V
6.75ns    1.021V     439.2mV    1.34V
10.28ns   1.056V     577.3mV    1.346V
31.13ns   1.065V     654.3mV    1.346V
[Falling Waveform]
R_fixture = 50
V_fixture = 1.8
V_fixture_min = 1.62
V_fixture_max = 1.89
0s        1.798V     1.618V     1.887V
603ps     1.801V     1.618V     1.88V
954ps     1.803V     1.618V     1.765V
1.557ns   1.782V     1.621V     1.147V
2.223ns   1.629V     1.622V     746.5mV
3.699ns   1.191V     1.606V     562.6mV
5.796ns   851.3mV    1.478V     532.5mV
8.505ns   747mV      1.304V     528.5mV
16.65ns   716mV      1.059V     528.1mV
36.13ns   715.4mV    1.008V     528.1mV
[Falling Waveform]
R_fixture = 50
V_fixture = 0
V_fixture_min = 0
V_fixture_max = 0
0s        1.065V     655.9mV    1.346V
441ps     1.07V      655.8mV    1.321V
738ps     1.049V     657mV      1.159V
891ps     1.018V     659.8mV    938.3mV
1.26ns    856.4mV    661.8mV    165.7mV
1.449ns   698.1mV    652.8mV    12.95mV
2.016ns   164mV      571.5mV    917uV
2.304ns   19.95mV    496.2mV    435.3uV
3.762ns   512.4uV    46.83mV    75.01uV
5.688ns   168.4uV    1.639mV    16.61uV
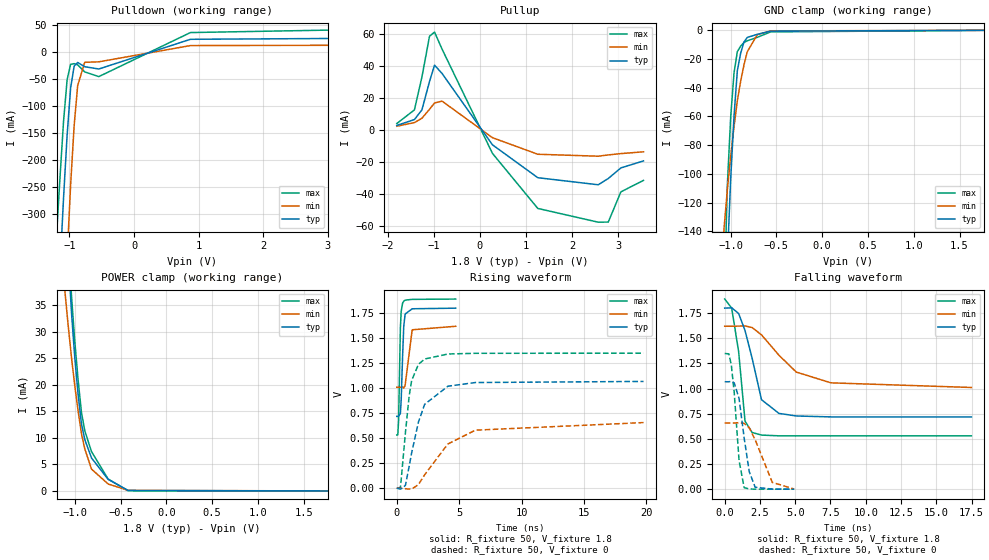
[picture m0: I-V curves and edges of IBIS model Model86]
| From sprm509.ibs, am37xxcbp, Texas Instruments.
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| Model based on original model for BQ18OMAPSMART1HYFBPBNOPM_SSBHV
|   Sub model PM_VS10L10_PUPD0_1P8
[model]   Model86
|[Input Load]   PI
|[Output Drive] SC10LB10
|Voltage   1.8V
|Mode   I/O
Model_type   I/O
Polarity   Non-Inverting
Enable   Active-Low
Vinl =  0.63
Vinh =  1.17
Cref =  15pF
Rref =  100.0000M
Vref =  0V
Vmeas =  0.9
C_comp   1.410688p   1.256095p   1.577871p
[Model Spec]
Vinl   0.63   0.567   0.6615
Vinh   1.17   1.053   1.2285
[Temperature Range]   25   125   -40
[Voltage Range]   1.8   1.62   1.89
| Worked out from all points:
|   slope of the pulldown table from 0 to 0.27 V, typ, clamps not added: 24.3 ohm
|   slope of the pullup table from 0 to 0.27 V, typ, clamps not added: 29.7 ohm
|   GND clamp passes 1 mA (typ) near -0.60 V on its own axis
|   POWER clamp passes 1 mA (typ) near -0.56 V on its own axis
|   rising waveform, R_fixture 50, V_fixture 1.8: 20-80 % time 176ps typ, 305ps min, 124ps max; typ from 0.718 V to 1.8 V
|   rising waveform, R_fixture 50, V_fixture 0: 20-80 % time 1.32ns typ, 2.86ns min, 702ps max; typ from 0 V to 1.07 V
|   falling waveform, R_fixture 50, V_fixture 1.8: 20-80 % time 1.04ns typ, 2.67ns min, 597ps max; typ from 1.8 V to 0.718 V
|   falling waveform, R_fixture 50, V_fixture 0: 20-80 % time 601ps typ, 1.02ns min, 432ps max; typ from 1.07 V to 0 V
[POWER_clamp]
-1.8V     362.5mA    191.4mA    412.8mA
-1.109V   56.69mA    37.71mA    60.38mA
-1.073V   44.6mA     31.22mA    47.8mA
-1.036V   33.44mA    25.04mA    36.59mA
-1V       24.98mA    19.72mA    28.06mA
-963.6mV  18.03mA    14.96mA    20.78mA
-927.3mV  12.59mA    10.77mA    14.74mA
-890.9mV  9.653mA    7.899mA    11.31mA
-818.2mV  6.214mA    4.114mA    7.414mA
-636.4mV  2.183mA    1.307mA    2.238mA
-418.2mV  83.85uA    105.2uA    35.14uA
1.764V    -1.228nA   -79.11nA   -1.453nA
[Pulldown]
-1.8V     -1.718A    -2.61A     -1.406A
-1.2V     -527.4mA   -844.5mA   -339.9mA
-1.145V   -396mA     -683.1mA   -229.1mA
-1.091V   -269mA     -526.7mA   -127.5mA
-1.036V   -153.6mA   -378.9mA   -51.17mA
-981.8mV  -66.34mA   -245.6mA   -22.67mA
-927.3mV  -26mA      -136.2mA   -21.54mA
-872.7mV  -19.34mA   -61.98mA   -23.69mA
-763.6mV  -27.2mA    -19.05mA   -36.72mA
-545.5mV  -31.39mA   -18.17mA   -45.46mA
872.7mV   23.46mA    11.88mA    35.92mA
3.545V    25.34mA    12.51mA    41.58mA
[Pullup]
-1.8V     2.903mA    2.423mA    4.112mA
-1.418V   6.595mA    4.711mA    12.64mA
-1.255V   12.69mA    7.42mA     33.23mA
-1.091V   30.4mA     13mA       58.69mA
-981.8mV  40.63mA    17.02mA    61.3mA
-818.2mV  35.38mA    18.12mA    50.59mA
272.7mV   -9.18mA    -4.728mA   -14.55mA
1.255V    -29.75mA   -15.09mA   -48.97mA
2.564V    -34.17mA   -16.31mA   -57.57mA
2.782V    -30.25mA   -15.5mA    -57.48mA
3.055V    -23.63mA   -14.68mA   -38.61mA
3.545V    -19.25mA   -13.56mA   -31.41mA
[GND_clamp]
-1.8V     -2.82A     -1.192A    -3.165A
-1.073V   -235.7mA   -138.4mA   -192.1mA
-1.036V   -159.5mA   -110.8mA   -107.5mA
-1V       -103.8mA   -87.85mA   -60.67mA
-963.6mV  -60mA      -67.28mA   -29.8mA
-927.3mV  -28.21mA   -49.08mA   -14.9mA
-890.9mV  -15.9mA    -35.48mA   -10.99mA
-854.5mV  -8.138mA   -24.07mA   -8.449mA
-818.2mV  -4.924mA   -14.85mA   -7.266mA
-709.1mV  -2.784mA   -3.064mA   -4.883mA
-563.6mV  -570.2uA   -404.5uA   -1.092mA
1.764V    -11.02pA   583.5nA    3.035nA
[Ramp]
dV/dt_f  0.6514567/1.046252n   0.3679937/2.69753n   0.8183404/0.5994797n
dV/dt_r  0.6510127/1.321738n   0.400717/2.883452n   0.8229324/0.7048318n
R_load = 50
[Rising Waveform]
R_fixture = 50
V_fixture = 1.8
V_fixture_min = 1.62
V_fixture_max = 1.89
0s        717.6mV    1.009V     531.7mV
81ps      717.5mV    1.009V     533.2mV
144ps     719.7mV    1.009V     669.7mV
288ps     746.8mV    1.009V     1.6V
351ps     875.5mV    1.01V      1.764V
468ps     1.325V     1.01V      1.85V
558ps     1.615V     1.001V     1.868V
666ps     1.74V      1.025V     1.879V
1.233ns   1.793V     1.583V     1.887V
4.716ns   1.799V     1.618V     1.89V
[Rising Waveform]
R_fixture = 50
V_fixture = 0
V_fixture_min = 0
V_fixture_max = 0
0s        -263.3uV   100.1uV    -1.17mV
297ps     -9.545mV   -211.1uV   9.147mV
693ps     28.13mV    -4.915mV   556.3mV
990ps     218mV      -8.897mV   919.1mV
1.188ns   351.3mV    -9.431mV   1.075V
1.737ns   662.3mV    36.57mV    1.238V
2.232ns   837.9mV    134.5mV    1.291V
4.095ns   1.019V     442.2mV    1.341V
6.291ns   1.056V     579.9mV    1.348V
19.76ns   1.067V     655.8mV    1.349V
[Falling Waveform]
R_fixture = 50
V_fixture = 1.8
V_fixture_min = 1.62
V_fixture_max = 1.89
0s        1.8V       1.62V      1.89V
495ps     1.803V     1.62V      1.801V
990ps     1.746V     1.621V     1.365V
1.44ns    1.578V     1.623V     676.5mV
1.944ns   1.302V     1.607V     563.5mV
2.61ns    889.4mV    1.534V     537.6mV
3.843ns   753.5mV    1.332V     530.4mV
5.076ns   727.6mV    1.164V     529.8mV
7.533ns   718.4mV    1.057V     529.8mV
17.49ns   717.6mV    1.011V     529.8mV
[Falling Waveform]
R_fixture = 50
V_fixture = 0
V_fixture_min = 0
V_fixture_max = 0
0s        1.068V     657.3mV    1.349V
297ps     1.068V     657.5mV    1.345V
468ps     1.071V     657.3mV    1.236V
675ps     1.057V     657.6mV    960.5mV
1.017ns   902.4mV    660.9mV    287mV
1.377ns   512.5mV    654.2mV    15.21mV
1.737ns   175.3mV    612mV      1.59mV
2.16ns    19.01mV    491.1mV    278.8uV
3.375ns   407.6uV    67.13mV    8.013uV
4.923ns   65.18uV    1.641mV    825.4nV
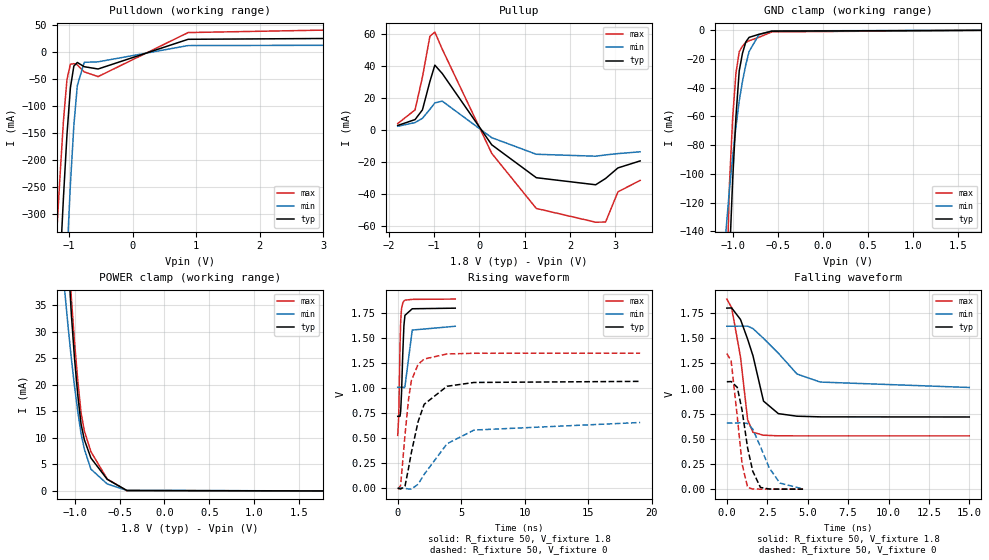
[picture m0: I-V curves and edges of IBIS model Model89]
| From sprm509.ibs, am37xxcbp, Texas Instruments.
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| Model based on original model for BQ18OMAPSMART1HYFBPBNOPM_SSBHV
|   Sub model PM_VS01L10_PUPD0_1P8
[model]   Model89
|[Input Load]   PI
|[Output Drive] SC01LB10
|Voltage   1.8V
|Mode   I/O
Model_type   I/O
Polarity   Non-Inverting
Enable   Active-Low
Vinl =  0.63
Vinh =  1.17
Cref =  15pF
Rref =  100.0000M
Vref =  0V
Vmeas =  0.9
C_comp   1.410688p   1.256095p   1.577871p
[Model Spec]
Vinl   0.63   0.567   0.6615
Vinh   1.17   1.053   1.2285
[Temperature Range]   25   125   -40
[Voltage Range]   1.8   1.62   1.89
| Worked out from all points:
|   slope of the pulldown table from 0 to 0.27 V, typ, clamps not added: 24.3 ohm
|   slope of the pullup table from 0 to 0.27 V, typ, clamps not added: 29.7 ohm
|   GND clamp passes 1 mA (typ) near -0.60 V on its own axis
|   POWER clamp passes 1 mA (typ) near -0.56 V on its own axis
|   rising waveform, R_fixture 50, V_fixture 1.8: 20-80 % time 175ps typ, 301ps min, 124ps max; typ from 0.717 V to 1.8 V
|   rising waveform, R_fixture 50, V_fixture 0: 20-80 % time 1.28ns typ, 2.77ns min, 683ps max; typ from 0 V to 1.07 V
|   falling waveform, R_fixture 50, V_fixture 1.8: 20-80 % time 1.08ns typ, 2.19ns min, 680ps max; typ from 1.8 V to 0.718 V
|   falling waveform, R_fixture 50, V_fixture 0: 20-80 % time 674ps typ, 1.09ns min, 500ps max; typ from 1.07 V to 0 V
[POWER_clamp]
-1.8V     362.5mA    191.4mA    412.8mA
-1.109V   56.69mA    37.71mA    60.38mA
-1.073V   44.6mA     31.22mA    47.8mA
-1.036V   33.44mA    25.04mA    36.59mA
-1V       24.98mA    19.72mA    28.06mA
-963.6mV  18.03mA    14.96mA    20.78mA
-927.3mV  12.59mA    10.77mA    14.74mA
-890.9mV  9.653mA    7.899mA    11.31mA
-818.2mV  6.214mA    4.114mA    7.414mA
-636.4mV  2.183mA    1.307mA    2.238mA
-418.2mV  83.85uA    105.2uA    35.14uA
1.764V    -1.228nA   -79.11nA   -1.453nA
[Pulldown]
-1.8V     -1.718A    -2.61A     -1.406A
-1.2V     -527.4mA   -844.5mA   -339.9mA
-1.145V   -396mA     -683.1mA   -229.1mA
-1.091V   -269mA     -526.7mA   -127.5mA
-1.036V   -153.6mA   -378.9mA   -51.17mA
-981.8mV  -66.34mA   -245.6mA   -22.67mA
-927.3mV  -26mA      -136.2mA   -21.54mA
-872.7mV  -19.34mA   -61.98mA   -23.69mA
-763.6mV  -27.2mA    -19.05mA   -36.72mA
-545.5mV  -31.39mA   -18.17mA   -45.46mA
872.7mV   23.46mA    11.88mA    35.92mA
3.545V    25.34mA    12.51mA    41.58mA
[Pullup]
-1.8V     2.903mA    2.423mA    4.112mA
-1.418V   6.595mA    4.711mA    12.64mA
-1.255V   12.69mA    7.42mA     33.23mA
-1.091V   30.4mA     13mA       58.69mA
-981.8mV  40.63mA    17.02mA    61.3mA
-818.2mV  35.38mA    18.12mA    50.59mA
272.7mV   -9.18mA    -4.728mA   -14.55mA
1.255V    -29.75mA   -15.09mA   -48.97mA
2.564V    -34.17mA   -16.31mA   -57.57mA
2.782V    -30.25mA   -15.5mA    -57.48mA
3.055V    -23.63mA   -14.68mA   -38.61mA
3.545V    -19.25mA   -13.56mA   -31.41mA
[GND_clamp]
-1.8V     -2.82A     -1.192A    -3.165A
-1.073V   -235.7mA   -138.4mA   -192.1mA
-1.036V   -159.5mA   -110.8mA   -107.5mA
-1V       -103.8mA   -87.85mA   -60.67mA
-963.6mV  -60mA      -67.28mA   -29.8mA
-927.3mV  -28.21mA   -49.08mA   -14.9mA
-890.9mV  -15.9mA    -35.48mA   -10.99mA
-854.5mV  -8.138mA   -24.07mA   -8.449mA
-818.2mV  -4.924mA   -14.85mA   -7.266mA
-709.1mV  -2.784mA   -3.064mA   -4.883mA
-563.6mV  -570.2uA   -404.5uA   -1.092mA
1.764V    -11.02pA   583.5nA    3.035nA
[Ramp]
dV/dt_f  0.6513326/1.084044n   0.3677491/2.209008n   0.8183247/0.6823868n
dV/dt_r  0.6506389/1.281571n   0.4005908/2.788851n   0.8222652/0.6848059n
R_load = 50
[Rising Waveform]
R_fixture = 50
V_fixture = 1.8
V_fixture_min = 1.62
V_fixture_max = 1.89
0s        717.3mV    1.009V     527.4mV
81ps      719.4mV    1.009V     721.2mV
180ps     718.5mV    1.009V     1.428V
234ps     774.1mV    1.009V     1.672V
297ps     943.6mV    1.01V      1.792V
396ps     1.341V     1.01V      1.851V
486ps     1.625V     1.002V     1.87V
567ps     1.727V     1.014V     1.879V
1.143ns   1.793V     1.58V      1.887V
4.527ns   1.799V     1.618V     1.89V
[Rising Waveform]
R_fixture = 50
V_fixture = 0
V_fixture_min = 0
V_fixture_max = 0
0s        162.8uV    101.9uV    -10.97mV
225ps     -10.1mV    -201.2uV   24.3mV
576ps     21.24mV    -4.057mV   535mV
846ps     196.6mV    -8.282mV   882.9mV
1.071ns   353.7mV    -9.87mV    1.074V
1.602ns   663.5mV    38mV       1.237V
2.079ns   837.6mV    136.6mV    1.29V
3.879ns   1.018V     443.1mV    1.341V
6.003ns   1.056V     580.1mV    1.348V
19.08ns   1.067V     655.8mV    1.349V
[Falling Waveform]
R_fixture = 50
V_fixture = 1.8
V_fixture_min = 1.62
V_fixture_max = 1.89
0s        1.8V       1.62V      1.89V
297ps     1.802V     1.62V      1.805V
846ps     1.687V     1.621V     1.314V
1.287ns   1.491V     1.621V     689.8mV
1.62ns    1.325V     1.596V     565.3mV
2.268ns   875.5mV    1.499V     536.3mV
3.186ns   751mV      1.352V     530.5mV
4.338ns   725.4mV    1.145V     529.8mV
5.769ns   718.9mV    1.065V     529.8mV
14.99ns   717.6mV    1.011V     529.8mV
[Falling Waveform]
R_fixture = 50
V_fixture = 0
V_fixture_min = 0
V_fixture_max = 0
0s        1.068V     657.2mV    1.349V
270ps     1.07V      657.5mV    1.274V
648ps     1.012V     657.8mV    718.8mV
945ps     782.9mV    661.1mV    249.3mV
1.287ns   408.6mV    652.9mV    17.04mV
1.602ns   179.1mV    597.6mV    1.869mV
2.079ns   17.06mV    422.2mV    235.9uV
2.628ns   1.574mV    209.8mV    26.86uV
3.285ns   343.3uV    60.51mV    3.578uV
4.716ns   51.36uV    1.639mV    523.1nV
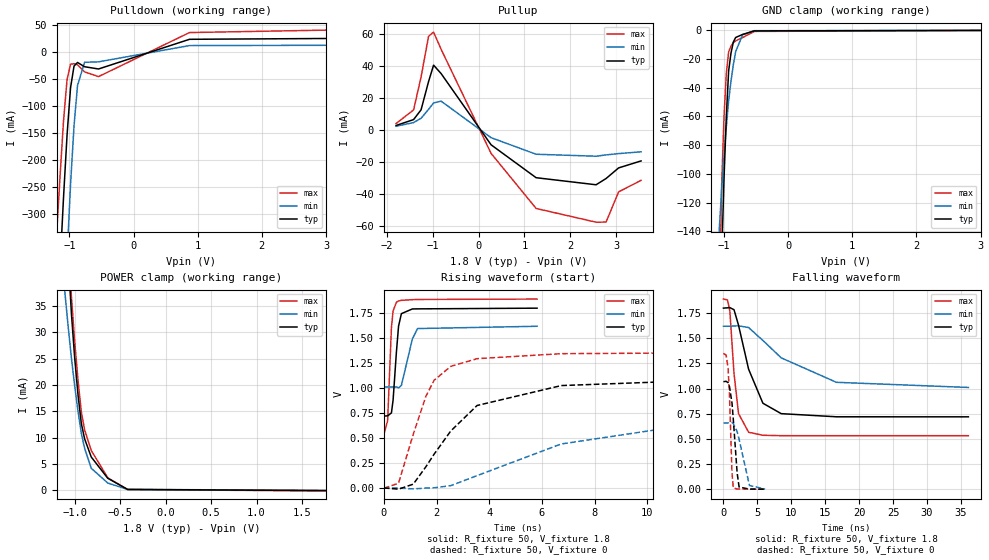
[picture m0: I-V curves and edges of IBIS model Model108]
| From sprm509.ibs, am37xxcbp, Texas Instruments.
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| Model based on original model for BQ18OMAPSMART1HYFBPBNOPM_SSBHV
|   Sub model NOPM_VS00L10_PU1_1P8
[model]   Model108
|[Input Load]   PU
|[Output Drive] SC00LB10
|Voltage   1.8V
|Mode   I/O
Model_type   I/O
Polarity   Non-Inverting
Enable   Active-Low
Vinl =  0.63
Vinh =  1.17
Cref =  15pF
Rref =  100.0000M
Vref =  0V
Vmeas =  0.9
C_comp   1.410688p   1.256095p   1.577871p
[Model Spec]
Vinl   0.63   0.567   0.6615
Vinh   1.17   1.053   1.2285
[Temperature Range]   25   125   -40
[Voltage Range]   1.8   1.62   1.89
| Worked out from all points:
|   slope of the pulldown table from 0 to 0.27 V, typ, clamps not added: 24.3 ohm
|   slope of the pullup table from 0 to 0.27 V, typ, clamps not added: 29.7 ohm
|   GND clamp passes 1 mA (typ) near -0.60 V on its own axis
|   POWER clamp passes 1 mA (typ) near -0.56 V on its own axis
|   rising waveform, R_fixture 50, V_fixture 1.8: 20-80 % time 176ps typ, 307ps min, 123ps max; typ from 0.72 V to 1.8 V
|   rising waveform, R_fixture 50, V_fixture 0: 20-80 % time 2.13ns typ, 4.77ns min, 1.09ns max; typ from 0.001 V to 1.07 V
|   falling waveform, R_fixture 50, V_fixture 1.8: 20-80 % time 2.71ns typ, 7.22ns min, 941ps max; typ from 1.8 V to 0.72 V
|   falling waveform, R_fixture 50, V_fixture 0: 20-80 % time 693ps typ, 1.19ns min, 394ps max; typ from 1.07 V to 0.002 V
[POWER_clamp]
-1.8V     362.5mA    191.4mA    412.8mA
-1.109V   56.76mA    37.74mA    60.51mA
-1.073V   44.67mA    31.25mA    47.93mA
-1.036V   33.52mA    25.07mA    36.72mA
-1V       25.06mA    19.75mA    28.2mA
-963.6mV  18.11mA    14.99mA    20.91mA
-927.3mV  12.67mA    10.8mA     14.87mA
-890.9mV  9.734mA    7.935mA    11.44mA
-818.2mV  6.293mA    4.153mA    7.536mA
-636.4mV  2.249mA    1.342mA    2.34mA
-418.2mV  128.7uA    129.3uA    104.4uA
1.764V    -96.73uA   -46.48uA   -163.5uA
[Pulldown]
-1.8V     -1.718A    -2.61A     -1.406A
-1.2V     -527.4mA   -844.5mA   -339.9mA
-1.145V   -396mA     -683.1mA   -229.1mA
-1.091V   -269mA     -526.7mA   -127.5mA
-1.036V   -153.6mA   -378.9mA   -51.17mA
-981.8mV  -66.33mA   -245.6mA   -22.67mA
-927.3mV  -26mA      -136.2mA   -21.54mA
-872.7mV  -19.34mA   -61.98mA   -23.69mA
-763.6mV  -27.2mA    -19.05mA   -36.72mA
-545.5mV  -31.39mA   -18.17mA   -45.46mA
872.7mV   23.46mA    11.88mA    35.92mA
3.545V    25.34mA    12.51mA    41.58mA
[Pullup]
-1.8V     2.903mA    2.423mA    4.112mA
-1.418V   6.595mA    4.711mA    12.64mA
-1.255V   12.69mA    7.42mA     33.24mA
-1.091V   30.4mA     13mA       58.69mA
-981.8mV  40.63mA    17.02mA    61.3mA
-818.2mV  35.38mA    18.12mA    50.59mA
272.7mV   -9.179mA   -4.728mA   -14.55mA
1.255V    -29.75mA   -15.09mA   -48.97mA
2.564V    -34.17mA   -16.31mA   -57.57mA
2.782V    -30.25mA   -15.5mA    -57.49mA
3.055V    -23.63mA   -14.68mA   -38.61mA
3.545V    -19.25mA   -13.56mA   -31.41mA
[GND_clamp]
-1.8V     -2.82A     -1.192A    -3.165A
-1.073V   -235.8mA   -138.4mA   -192.1mA
-1.036V   -159.6mA   -110.8mA   -107.6mA
-1V       -103.8mA   -87.86mA   -60.73mA
-963.6mV  -60.04mA   -67.29mA   -29.86mA
-927.3mV  -28.26mA   -49.09mA   -14.98mA
-890.9mV  -15.95mA   -35.49mA   -11.09mA
-854.5mV  -8.198mA   -24.09mA   -8.559mA
-818.2mV  -4.99mA    -14.87mA   -7.387mA
-709.1mV  -2.858mA   -3.093mA   -5.012mA
-527.3mV  -395.6uA   -260.4uA   -751.2uA
3.6V      0A         0A         0A
[Ramp]
dV/dt_f   0.650981/2.713798n   0.368125/7.284438n   0.8172125/0.9375642n
dV/dt_r   0.650312/2.138998n   0.400369/4.810984n   0.82149/1.096247n
R_load = 50
[Rising Waveform]
R_fixture = 50
V_fixture = 1.8
V_fixture_min = 1.62
V_fixture_max = 1.89
0s        720mV      1.011V     534.7mV
144ps     722.3mV    1.011V     674.1mV
288ps     751.5mV    1.01V      1.605V
351ps     879.2mV    1.012V     1.771V
477ps     1.36V      1.011V     1.858V
558ps     1.618V     1.002V     1.871V
666ps     1.744V     1.026V     1.877V
1.08ns    1.791V     1.488V     1.884V
1.278ns   1.792V     1.595V     1.886V
5.814ns   1.799V     1.618V     1.89V
[Rising Waveform]
R_fixture = 50
V_fixture = 0
V_fixture_min = 0
V_fixture_max = 0
0s        1.058mV    1.078mV    -1.875mV
558ps     -10.96mV   -139.4uV   48.58mV
1.116ns   39.07mV    -8.507mV   537.6mV
1.593ns   212mV      -258.6uV   916.3mV
1.908ns   339.1mV    2.817mV    1.078V
2.538ns   570.5mV    24.05mV    1.217V
3.537ns   825.6mV    124.6mV    1.294V
6.732ns   1.025V     441mV      1.344V
10.26ns   1.059V     579.9mV    1.349V
31.11ns   1.069V     657.1mV    1.35V
[Falling Waveform]
R_fixture = 50
V_fixture = 1.8
V_fixture_min = 1.62
V_fixture_max = 1.89
0s        1.8V       1.62V      1.89V
603ps     1.803V     1.62V      1.882V
954ps     1.805V     1.62V      1.769V
1.566ns   1.784V     1.623V     1.149V
2.232ns   1.63V      1.624V     752.1mV
3.717ns   1.193V     1.607V     567mV
5.823ns   855.3mV    1.479V     537mV
8.523ns   751.7mV    1.306V     532.9mV
16.66ns   720.6mV    1.063V     532.6mV
36.11ns   720mV      1.012V     532.6mV
[Falling Waveform]
R_fixture = 50
V_fixture = 0
V_fixture_min = 0
V_fixture_max = 0
0s        1.069V     658.6mV    1.35V
396ps     1.073V     658.6mV    1.334V
693ps     1.06V      659.3mV    1.205V
900ps     1.02V      662.7mV    929.3mV
1.269ns   856.3mV    664.3mV    160.3mV
1.458ns   696.7mV    655mV      14.92mV
2.025ns   163.9mV    572.8mV    3.052mV
2.313ns   22.56mV    497.1mV    2.445mV
3.843ns   2.172mV    37.83mV    1.883mV
6.147ns   1.613mV    2.593mV    1.79mV
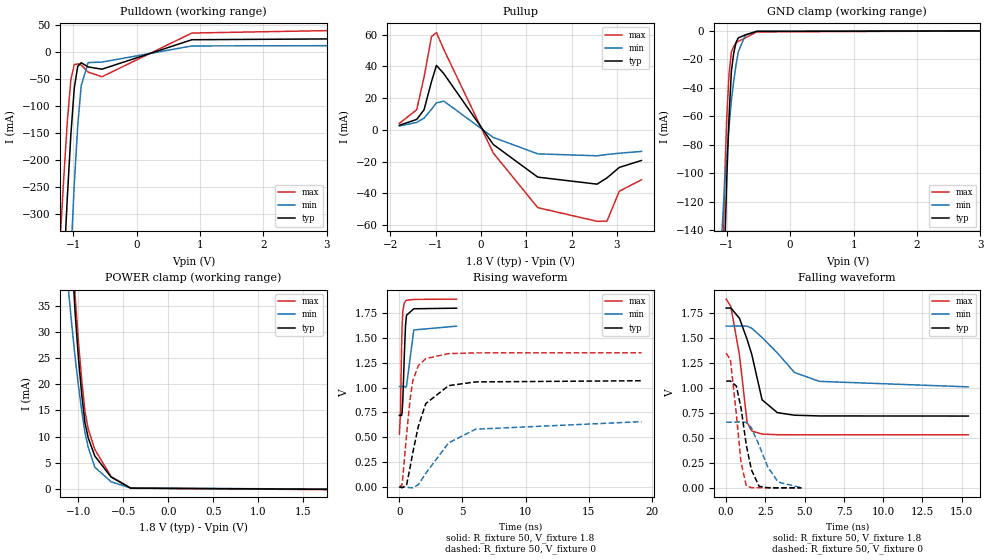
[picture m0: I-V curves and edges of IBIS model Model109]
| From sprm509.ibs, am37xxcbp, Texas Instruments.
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| Model based on original model for BQ18OMAPSMART1HYFBPBNOPM_SSBHV
|   Sub model NOPM_VS01L00_PU1_1P8
[model]   Model109
|[Input Load]   PU
|[Output Drive] SC01LB00
|Voltage   1.8V
|Mode   I/O
Model_type   I/O
Polarity   Non-Inverting
Enable   Active-Low
Vinl =  0.63
Vinh =  1.17
Cref =  15pF
Rref =  100.0000M
Vref =  0V
Vmeas =  0.9
C_comp   1.410688p   1.256095p   1.577871p
[Model Spec]
Vinl   0.63   0.567   0.6615
Vinh   1.17   1.053   1.2285
[Temperature Range]   25   125   -40
[Voltage Range]   1.8   1.62   1.89
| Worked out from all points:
|   slope of the pulldown table from 0 to 0.27 V, typ, clamps not added: 24.3 ohm
|   slope of the pullup table from 0 to 0.27 V, typ, clamps not added: 29.7 ohm
|   GND clamp passes 1 mA (typ) near -0.60 V on its own axis
|   POWER clamp passes 1 mA (typ) near -0.56 V on its own axis
|   rising waveform, R_fixture 50, V_fixture 1.8: 20-80 % time 175ps typ, 302ps min, 123ps max; typ from 0.72 V to 1.8 V
|   rising waveform, R_fixture 50, V_fixture 0: 20-80 % time 1.29ns typ, 2.78ns min, 687ps max; typ from 0.002 V to 1.07 V
|   falling waveform, R_fixture 50, V_fixture 1.8: 20-80 % time 1.07ns typ, 2.26ns min, 672ps max; typ from 1.8 V to 0.72 V
|   falling waveform, R_fixture 50, V_fixture 0: 20-80 % time 666ps typ, 1.08ns min, 493ps max; typ from 1.07 V to 0.001 V
[POWER_clamp]
-1.8V     362.5mA    191.4mA    412.8mA
-1.109V   56.76mA    37.74mA    60.51mA
-1.073V   44.67mA    31.25mA    47.93mA
-1.036V   33.52mA    25.07mA    36.72mA
-1V       25.06mA    19.75mA    28.2mA
-963.6mV  18.11mA    14.99mA    20.91mA
-927.3mV  12.67mA    10.8mA     14.87mA
-890.9mV  9.734mA    7.935mA    11.44mA
-818.2mV  6.293mA    4.153mA    7.536mA
-636.4mV  2.249mA    1.342mA    2.34mA
-418.2mV  128.7uA    129.3uA    104.4uA
1.764V    -96.73uA   -46.48uA   -163.5uA
[Pulldown]
-1.8V     -1.718A    -2.61A     -1.406A
-1.2V     -527.4mA   -844.5mA   -339.9mA
-1.145V   -396mA     -683.1mA   -229.1mA
-1.091V   -269mA     -526.7mA   -127.5mA
-1.036V   -153.6mA   -378.9mA   -51.17mA
-981.8mV  -66.33mA   -245.6mA   -22.67mA
-927.3mV  -26mA      -136.2mA   -21.54mA
-872.7mV  -19.34mA   -61.98mA   -23.69mA
-763.6mV  -27.2mA    -19.05mA   -36.72mA
-545.5mV  -31.39mA   -18.17mA   -45.46mA
872.7mV   23.46mA    11.88mA    35.92mA
3.545V    25.34mA    12.51mA    41.58mA
[Pullup]
-1.8V     2.903mA    2.423mA    4.112mA
-1.418V   6.595mA    4.711mA    12.64mA
-1.255V   12.69mA    7.42mA     33.24mA
-1.091V   30.4mA     13mA       58.69mA
-981.8mV  40.63mA    17.02mA    61.3mA
-818.2mV  35.38mA    18.12mA    50.59mA
272.7mV   -9.179mA   -4.728mA   -14.55mA
1.255V    -29.75mA   -15.09mA   -48.97mA
2.564V    -34.17mA   -16.31mA   -57.57mA
2.782V    -30.25mA   -15.5mA    -57.49mA
3.055V    -23.63mA   -14.68mA   -38.61mA
3.545V    -19.25mA   -13.56mA   -31.41mA
[GND_clamp]
-1.8V     -2.82A     -1.192A    -3.165A
-1.073V   -235.8mA   -138.4mA   -192.1mA
-1.036V   -159.6mA   -110.8mA   -107.6mA
-1V       -103.8mA   -87.86mA   -60.73mA
-963.6mV  -60.04mA   -67.29mA   -29.86mA
-927.3mV  -28.26mA   -49.09mA   -14.98mA
-890.9mV  -15.95mA   -35.49mA   -11.09mA
-854.5mV  -8.198mA   -24.09mA   -8.559mA
-818.2mV  -4.99mA    -14.87mA   -7.387mA
-709.1mV  -2.858mA   -3.093mA   -5.012mA
-527.3mV  -395.6uA   -260.4uA   -751.2uA
3.6V      0A         0A         0A
[Ramp]
dV/dt_f   0.649874/1.075864n   0.3669693/2.275981n   0.8165824/0.673543n
dV/dt_r  0.6495945/1.287607n   0.4003075/2.804648n   0.8201561/0.6875854n
R_load = 50
[Rising Waveform]
R_fixture = 50
V_fixture = 1.8
V_fixture_min = 1.62
V_fixture_max = 1.89
0s        719.7mV    1.011V     530.6mV
81ps      721.9mV    1.011V     725.9mV
171ps     717.7mV    1.01V      1.372V
216ps     751.3mV    1.011V     1.615V
279ps     887.8mV    1.011V     1.771V
387ps     1.308V     1.011V     1.849V
486ps     1.626V     1.003V     1.87V
567ps     1.728V     1.015V     1.879V
1.143ns   1.793V     1.58V      1.887V
4.536ns   1.799V     1.618V     1.89V
[Rising Waveform]
R_fixture = 50
V_fixture = 0
V_fixture_min = 0
V_fixture_max = 0
0s        1.548mV    1.067mV    -8.925mV
225ps     -8.441mV   761.6uV    26.79mV
576ps     22.46mV    -2.99mV    531.2mV
846ps     193.8mV    -7.038mV   878.6mV
1.071ns   350.2mV    -7.956mV   1.072V
1.503ns   610.1mV    22.83mV    1.22V
2.088ns   838.2mV    136mV      1.291V
3.906ns   1.02V      444.3mV    1.342V
6.048ns   1.057V     581.4mV    1.349V
19.19ns   1.069V     657.1mV    1.35V
[Falling Waveform]
R_fixture = 50
V_fixture = 1.8
V_fixture_min = 1.62
V_fixture_max = 1.89
0s        1.8V       1.62V      1.89V
297ps     1.802V     1.62V      1.815V
846ps     1.698V     1.621V     1.331V
1.332ns   1.487V     1.62V      657.8mV
1.629ns   1.337V     1.599V     570.4mV
2.286ns   882.5mV    1.506V     539.7mV
3.258ns   754mV      1.352V     533.3mV
4.347ns   728.5mV    1.156V     532.7mV
5.94ns    721.2mV    1.067V     532.6mV
15.42ns   720mV      1.012V     532.6mV
[Falling Waveform]
R_fixture = 50
V_fixture = 0
V_fixture_min = 0
V_fixture_max = 0
0s        1.069V     658.5mV    1.35V
270ps     1.071V     658.8mV    1.283V
648ps     1.02V      659.1mV    739.5mV
945ps     801.2mV    662.5mV    256mV
1.287ns   423.6mV    654.9mV    19.45mV
1.611ns   180mV      601.7mV    3.648mV
2.097ns   16.58mV    427mV      2.011mV
2.646ns   2.982mV    211mV      1.803mV
3.312ns   1.738mV    58.93mV    1.777mV
4.797ns   1.441mV    2.601mV    1.773mV
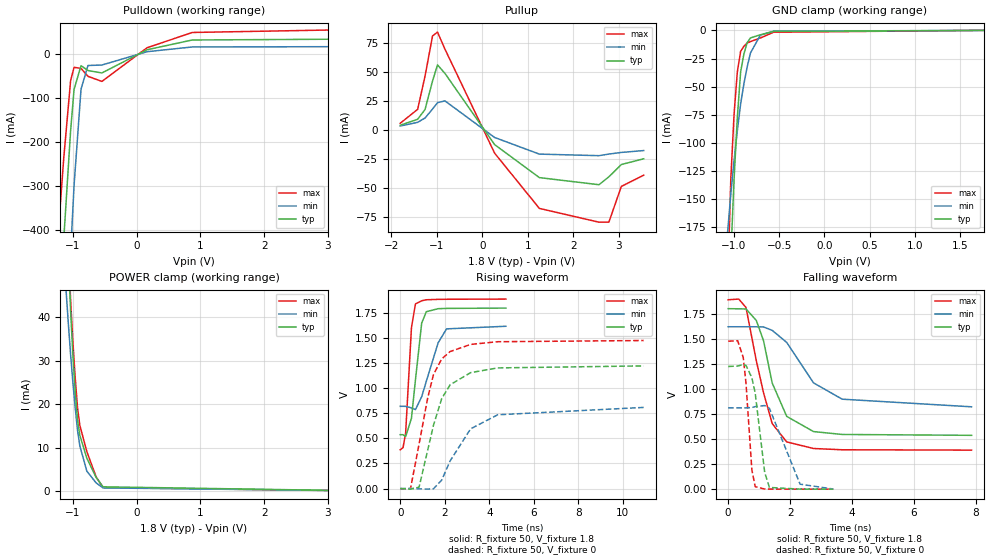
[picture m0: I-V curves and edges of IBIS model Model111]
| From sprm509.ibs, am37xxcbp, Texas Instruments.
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| Model based on original model for BQ18OMAPSMART2HYFBPB_SSBHH
|   Sub model T2HYFBPB_H_0_PD1_1P8
[model]   Model111
|[Input Load]   PD
|[Output Drive] LB0
|Voltage   1.8V
|Mode   I/O
Model_type   I/O
Polarity   Non-Inverting
Enable   Active-Low
Vinl =  0.63
Vinh =  1.17
Cref =  15pF
Rref =  100.0000M
Vref =  0V
Vmeas =  0.9
C_comp   1.528652p   1.368776p   1.69933p
[Model Spec]
Vinl   0.63   0.567   0.6615
Vinh   1.17   1.053   1.2285
[Temperature Range]   25   125   -40
[Voltage Range]   1.8   1.62   1.89
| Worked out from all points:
|   slope of the pulldown table from 0 to 0.27 V, typ, clamps not added: 17.8 ohm
|   slope of the pullup table from 0 to 0.27 V, typ, clamps not added: 21.5 ohm
|   GND clamp passes 1 mA (typ) near -0.58 V on its own axis
|   POWER clamp passes 1 mA (typ) near -0.53 V on its own axis
|   rising waveform, R_fixture 50, V_fixture 1.8: 20-80 % time 342ps typ, 659ps min, 212ps max; typ from 0.537 V to 1.8 V
|   rising waveform, R_fixture 50, V_fixture 0: 20-80 % time 945ps typ, 1.43ns min, 832ps max; typ from 0 V to 1.22 V
|   falling waveform, R_fixture 50, V_fixture 1.8: 20-80 % time 678ps typ, 1.19ns min, 662ps max; typ from 1.8 V to 0.537 V
|   falling waveform, R_fixture 50, V_fixture 0: 20-80 % time 281ps typ, 490ps min, 196ps max; typ from 1.22 V to 0 V
[POWER_clamp]
-1.8V     449.2mA    229.3mA    499.9mA
-1.109V   70.08mA    46.67mA    71.87mA
-1.073V   55.21mA    38.88mA    57.08mA
-1.036V   41.54mA    31.43mA    44.06mA
-1V       31.27mA    24.96mA    34.34mA
-963.6mV  22.88mA    19.13mA    26.04mA
-927.3mV  16.35mA    13.96mA    19.14mA
-890.9mV  12.8mA     10.36mA    15.1mA
-781.8mV  7.558mA    4.572mA    9.086mA
-636.4mV  3.123mA    1.858mA    3.262mA
-527.3mV  948.5uA    698.4uA    767.3uA
3.6V      0A         0A         0A
[Pulldown]
-1.8V     -1.866A    -2.926A    -1.473A
-1.255V   -690.3mA   -1.165A    -458.8mA
-1.2V     -556.9mA   -981.3mA   -347.5mA
-1.145V   -424mA     -799.3mA   -238.7mA
-1.036V   -174.1mA   -452.5mA   -60.3mA
-981.8mV  -80.13mA   -298.3mA   -30.04mA
-872.7mV  -26.27mA   -79.78mA   -32.44mA
-763.6mV  -37.27mA   -25.87mA   -50.47mA
-545.5mV  -42.85mA   -24.82mA   -62.02mA
163.6mV   9.905mA    5.464mA    14.49mA
872.7mV   32.06mA    16.22mA    49.12mA
3.545V    34.18mA    16.99mA    56.07mA
[Pullup]
-1.8V     4.02mA     3.353mA    5.71mA
-1.418V   9.153mA    6.524mA    17.71mA
-1.255V   17.65mA    10.28mA    46.46mA
-1.091V   42.13mA    17.99mA    80.98mA
-981.8mV  56.04mA    23.5mA     84.34mA
-818.2mV  48.72mA    25.01mA    69.63mA
272.7mV   -12.68mA   -6.535mA   -20.08mA
1.255V    -41.13mA   -20.87mA   -67.69mA
2.564V    -47.26mA   -22.22mA   -79.57mA
2.782V    -40.42mA   -20.82mA   -79.47mA
3.055V    -29.85mA   -19.43mA   -48.72mA
3.545V    -24.9mA    -17.8mA    -39.06mA
[GND_clamp]
-1.8V     -3.26A     -1.496A    -3.636A
-1.073V   -295.4mA   -181.3mA   -234.2mA
-1.036V   -202.2mA   -145.8mA   -132.5mA
-1V       -132.7mA   -116.1mA   -74.87mA
-963.6mV  -77.6mA    -89.37mA   -36.88mA
-927.3mV  -36.98mA   -65.53mA   -18.59mA
-890.9mV  -20.91mA   -47.52mA   -14.09mA
-854.5mV  -10.79mA   -32.36mA   -11.18mA
-818.2mV  -6.606mA   -20.04mA   -9.859mA
-709.1mV  -3.829mA   -4.176mA   -6.715mA
-563.6mV  -831uA     -577.4uA   -1.567mA
1.764V    97.78uA    55.24uA    156.3uA
[Ramp]
dV/dt_f  0.7586772/0.6783788n  0.4801244/1.195387n   0.9050187/0.6636617n
dV/dt_r  0.7379647/0.9460144n  0.4891694/1.441527n   0.8930717/0.8349676n
R_load = 50
[Rising Waveform]
R_fixture = 50
V_fixture = 1.8
V_fixture_min = 1.62
V_fixture_max = 1.89
0s        536.5mV    819.2mV    386.4mV
126ps     536.6mV    819.5mV    407.1mV
243ps     516.8mV    819.2mV    554.7mV
504ps     700.6mV    803.5mV    1.605V
684ps     1.085V     786.6mV    1.84V
963ps     1.649V     915.1mV    1.871V
1.17ns    1.762V     1.068V     1.881V
1.701ns   1.792V     1.452V     1.885V
2.079ns   1.795V     1.591V     1.886V
4.743ns   1.798V     1.617V     1.888V
[Rising Waveform]
R_fixture = 50
V_fixture = 0
V_fixture_min = 0
V_fixture_max = 0
0s        -338.7uV   73.69uV    -1.181mV
459ps     -6.067mV   1.381mV    -2.942mV
846ps     14.13mV    -3.315mV   443mV
1.233ns   382.1mV    -4.989mV   903.1mV
1.494ns   632.1mV    -1.873mV   1.137V
1.863ns   897mV      84.7mV     1.292V
2.241ns   1.034V     275.9mV    1.365V
3.159ns   1.155V     594.9mV    1.436V
4.374ns   1.202V     734.9mV    1.463V
10.93ns   1.222V     808.5mV    1.475V
[Falling Waveform]
R_fixture = 50
V_fixture = 1.8
V_fixture_min = 1.62
V_fixture_max = 1.89
0s        1.799V     1.619V     1.888V
342ps     1.798V     1.619V     1.895V
576ps     1.796V     1.619V     1.811V
909ps     1.682V     1.619V     1.28V
1.143ns   1.478V     1.617V     959.8mV
1.422ns   1.058V     1.583V     653.5mV
1.89ns    725.7mV    1.463V     471.1mV
2.754ns   574.2mV    1.06V      405.5mV
3.681ns   545.4mV    897mV      392.7mV
7.857ns   536.7mV    821mV      389.3mV
[Falling Waveform]
R_fixture = 50
V_fixture = 0
V_fixture_min = 0
V_fixture_max = 0
0s        1.223V     810.3mV    1.475V
306ps     1.227V     810.6mV    1.48V
486ps     1.243V     810.4mV    1.315V
576ps     1.233V     810.1mV    1.057V
765ps     1.111V     813.7mV    192.4mV
873ps     957.7mV    822.9mV    24.98mV
1.179ns   167.6mV    833.7mV    1.396mV
1.332ns   17.25mV    805.6mV    894.4uV
2.322ns   447.3uV    49.62mV    211.1uV
3.393ns   124.3uV    1.651mV    52.7uV
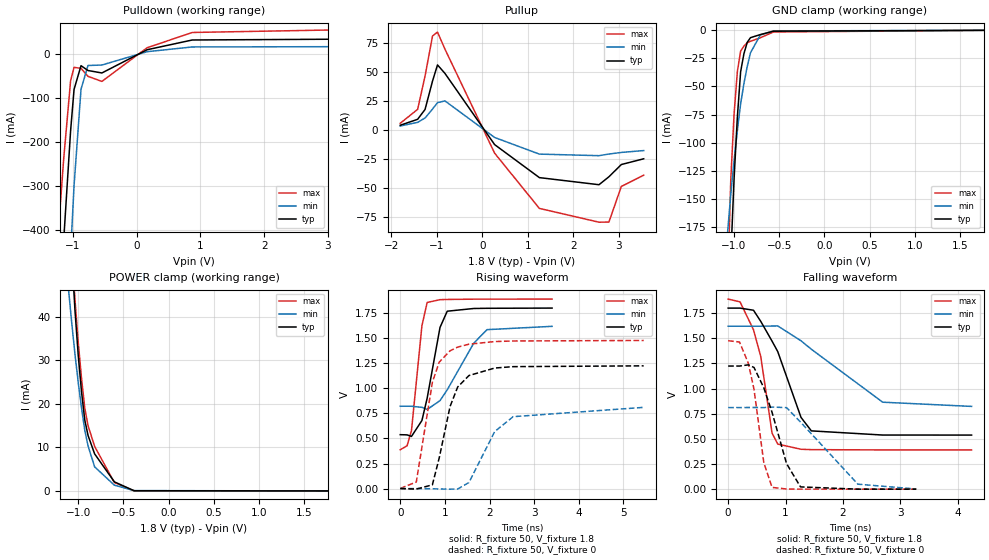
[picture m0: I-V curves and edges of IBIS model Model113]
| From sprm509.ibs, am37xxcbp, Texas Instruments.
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| Model based on original model for BQ18OMAPSMART2HYFBPB_SSBHH
|   Sub model HYFBPB_H_1_PUPD0_1P8
[model]   Model113
|[Input Load]   PI
|[Output Drive] LB1
|Voltage   1.8V
|Mode   I/O
Model_type   I/O
Polarity   Non-Inverting
Enable   Active-Low
Vinl =  0.63
Vinh =  1.17
Cref =  15pF
Rref =  100.0000M
Vref =  0V
Vmeas =  0.9
C_comp   1.528652p   1.368776p   1.69933p
[Model Spec]
Vinl   0.63   0.567   0.6615
Vinh   1.17   1.053   1.2285
[Temperature Range]   25   125   -40
[Voltage Range]   1.8   1.62   1.89
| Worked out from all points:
|   slope of the pulldown table from 0 to 0.27 V, typ, clamps not added: 17.8 ohm
|   slope of the pullup table from 0 to 0.27 V, typ, clamps not added: 21.5 ohm
|   GND clamp passes 1 mA (typ) near -0.58 V on its own axis
|   POWER clamp passes 1 mA (typ) near -0.54 V on its own axis
|   rising waveform, R_fixture 50, V_fixture 1.8: 20-80 % time 311ps typ, 615ps min, 192ps max; typ from 0.538 V to 1.8 V
|   rising waveform, R_fixture 50, V_fixture 0: 20-80 % time 399ps typ, 602ps min, 351ps max; typ from 0 V to 1.22 V
|   falling waveform, R_fixture 50, V_fixture 1.8: 20-80 % time 535ps typ, 1.09ns min, 284ps max; typ from 1.8 V to 0.538 V
|   falling waveform, R_fixture 50, V_fixture 0: 20-80 % time 384ps typ, 724ps min, 227ps max; typ from 1.22 V to 0 V
[POWER_clamp]
-1.8V     449.2mA    229.3mA    499.9mA
-1.109V   70.03mA    46.65mA    71.76mA
-1.073V   55.15mA    38.86mA    56.96mA
-1.036V   41.47mA    31.41mA    43.93mA
-1V       31.2mA     24.93mA    34.21mA
-963.6mV  22.8mA     19.1mA     25.91mA
-927.3mV  16.27mA    13.92mA    19.01mA
-890.9mV  12.72mA    10.32mA    14.97mA
-818.2mV  8.506mA    5.529mA    10.22mA
-600mV    2.086mA    1.321mA    1.925mA
-381.8mV  46uA       75.05uA    15.45uA
1.764V    -1.701nA   -102nA     -1.875nA
[Pulldown]
-1.8V     -1.866A    -2.926A    -1.473A
-1.255V   -690.3mA   -1.165A    -458.8mA
-1.2V     -556.9mA   -981.3mA   -347.5mA
-1.145V   -424mA     -799.3mA   -238.7mA
-1.036V   -174.1mA   -452.5mA   -60.31mA
-981.8mV  -80.13mA   -298.3mA   -30.04mA
-872.7mV  -26.27mA   -79.78mA   -32.44mA
-763.6mV  -37.26mA   -25.87mA   -50.47mA
-545.5mV  -42.85mA   -24.82mA   -62.02mA
163.6mV   9.905mA    5.464mA    14.49mA
872.7mV   32.06mA    16.22mA    49.12mA
3.545V    34.18mA    16.99mA    56.07mA
[Pullup]
-1.8V     4.02mA     3.353mA    5.71mA
-1.418V   9.153mA    6.524mA    17.71mA
-1.255V   17.65mA    10.28mA    46.45mA
-1.091V   42.12mA    17.99mA    80.97mA
-981.8mV  56.04mA    23.5mA     84.34mA
-818.2mV  48.72mA    25.01mA    69.63mA
272.7mV   -12.68mA   -6.535mA   -20.08mA
1.255V    -41.13mA   -20.87mA   -67.69mA
2.564V    -47.26mA   -22.22mA   -79.57mA
2.782V    -40.42mA   -20.82mA   -79.47mA
3.055V    -29.85mA   -19.43mA   -48.72mA
3.545V    -24.9mA    -17.8mA    -39.06mA
[GND_clamp]
-1.8V     -3.26A     -1.496A    -3.636A
-1.073V   -295.4mA   -181.3mA   -234.2mA
-1.036V   -202.1mA   -145.8mA   -132.5mA
-1V       -132.6mA   -116.1mA   -74.83mA
-963.6mV  -77.56mA   -89.36mA   -36.83mA
-927.3mV  -36.94mA   -65.52mA   -18.53mA
-890.9mV  -20.86mA   -47.5mA    -14.02mA
-854.5mV  -10.73mA   -32.34mA   -11.09mA
-818.2mV  -6.545mA   -20.02mA   -9.764mA
-709.1mV  -3.764mA   -4.146mA   -6.62mA
-563.6mV  -769uA     -544.8uA   -1.476mA
1.764V    -87.87pA   812.3nA    3.194nA
[Ramp]
dV/dt_f  0.7588723/0.5355939n   0.481361/1.100691n   0.9005042/0.283976n
dV/dt_r  0.7393406/0.398473n   0.4904968/0.6047555n  0.8915881/0.3519443n
R_load = 50
[Rising Waveform]
R_fixture = 50
V_fixture = 1.8
V_fixture_min = 1.62
V_fixture_max = 1.89
0s        537.7mV    821mV      387.3mV
153ps     535.5mV    821.3mV    426.6mV
252ps     520.2mV    820.9mV    578.5mV
486ps     679.1mV    810.2mV    1.625V
603ps     901.3mV    788.8mV    1.856V
891ps     1.607V     876.9mV    1.884V
1.053ns   1.769V     985.3mV    1.886V
1.647ns   1.796V     1.45V      1.889V
1.944ns   1.798V     1.585V     1.889V
3.402ns   1.8V       1.618V     1.89V
[Rising Waveform]
R_fixture = 50
V_fixture = 0
V_fixture_min = 0
V_fixture_max = 0
0s        -158uV     -189.8nV   1.259mV
360ps     -4.982mV   -317.4uV   65.75mV
720ps     37.12mV    -1.689mV   1.06V
873ps     304.8mV    -4.025mV   1.261V
1.116ns   818.5mV    -5.917mV   1.374V
1.287ns   1.013V     -4.05mV    1.411V
1.539ns   1.127V     60.24mV    1.44V
2.115ns   1.202V     567.9mV    1.466V
2.529ns   1.216V     717mV      1.472V
5.454ns   1.224V     809.9mV    1.477V
[Falling Waveform]
R_fixture = 50
V_fixture = 1.8
V_fixture_min = 1.62
V_fixture_max = 1.89
0s        1.8V       1.62V      1.89V
207ps     1.8V       1.62V      1.862V
441ps     1.779V     1.62V      1.585V
567ps     1.669V     1.62V      1.321V
765ps     1.471V     1.622V     556.4mV
864ps     1.367V     1.623V     448.2mV
1.269ns   713.1mV    1.475V     396.7mV
1.449ns   579.5mV    1.391V     392.9mV
2.691ns   538.1mV    864.7mV    390.2mV
4.239ns   537.8mV    822.8mV    390.2mV
[Falling Waveform]
R_fixture = 50
V_fixture = 0
V_fixture_min = 0
V_fixture_max = 0
0s        1.224V     811.6mV    1.476V
198ps     1.224V     811.4mV    1.463V
351ps     1.236V     811.9mV    1.252V
450ps     1.21V      811.8mV    993.6mV
621ps     1.008V     811.2mV    263.3mV
765ps     762.8mV    816.6mV    17.63mV
1.017ns   253.9mV    810.3mV    1.559mV
1.26ns    22.55mV    667.3mV    207.4uV
2.259ns   122.3uV    49.59mV    1.311uV
3.276ns   35.45uV    1.671mV    321nV
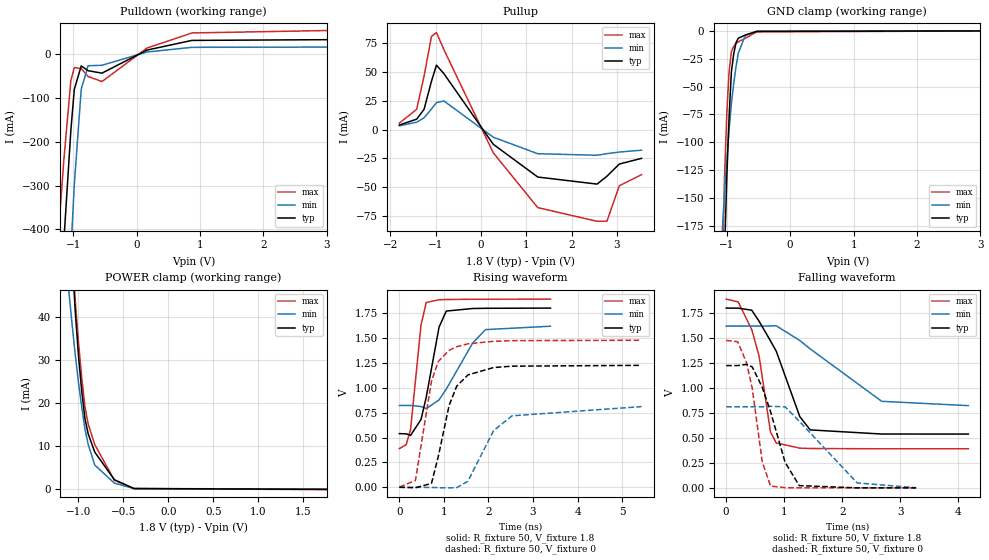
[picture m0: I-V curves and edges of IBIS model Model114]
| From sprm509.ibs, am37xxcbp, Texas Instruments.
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| Model based on original model for BQ18OMAPSMART2HYFBPB_SSBHH
|   Sub model T2HYFBPB_H_1_PU1_1P8
[model]   Model114
|[Input Load]   PU
|[Output Drive] LB1
|Voltage   1.8V
|Mode   I/O
Model_type   I/O
Polarity   Non-Inverting
Enable   Active-Low
Vinl =  0.63
Vinh =  1.17
Cref =  15pF
Rref =  100.0000M
Vref =  0V
Vmeas =  0.9
C_comp   1.528652p   1.368776p   1.69933p
[Model Spec]
Vinl   0.63   0.567   0.6615
Vinh   1.17   1.053   1.2285
[Temperature Range]   25   125   -40
[Voltage Range]   1.8   1.62   1.89
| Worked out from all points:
|   slope of the pulldown table from 0 to 0.27 V, typ, clamps not added: 17.8 ohm
|   slope of the pullup table from 0 to 0.27 V, typ, clamps not added: 21.5 ohm
|   GND clamp passes 1 mA (typ) near -0.57 V on its own axis
|   POWER clamp passes 1 mA (typ) near -0.53 V on its own axis
|   rising waveform, R_fixture 50, V_fixture 1.8: 20-80 % time 311ps typ, 615ps min, 192ps max; typ from 0.54 V to 1.8 V
|   rising waveform, R_fixture 50, V_fixture 0: 20-80 % time 398ps typ, 601ps min, 351ps max; typ from 0.001 V to 1.23 V
|   falling waveform, R_fixture 50, V_fixture 1.8: 20-80 % time 535ps typ, 1.1ns min, 284ps max; typ from 1.8 V to 0.54 V
|   falling waveform, R_fixture 50, V_fixture 0: 20-80 % time 384ps typ, 724ps min, 227ps max; typ from 1.23 V to 0.001 V
[POWER_clamp]
-1.8V     449.2mA    229.3mA    499.9mA
-1.109V   70.1mA     46.68mA    71.89mA
-1.073V   55.22mA    38.88mA    57.09mA
-1.036V   41.55mA    31.43mA    44.07mA
-1V       31.28mA    24.96mA    34.35mA
-963.6mV  22.88mA    19.13mA    26.04mA
-927.3mV  16.35mA    13.96mA    19.14mA
-890.9mV  12.8mA     10.36mA    15.1mA
-818.2mV  8.584mA    5.567mA    10.34mA
-600mV    2.149mA    1.354mA    2.023mA
-381.8mV  86.82uA    96.98uA    78.48uA
1.764V    -96.73uA   -46.5uA    -163.5uA
[Pulldown]
-1.8V     -1.866A    -2.926A    -1.473A
-1.255V   -690.3mA   -1.165A    -458.8mA
-1.2V     -556.9mA   -981.3mA   -347.5mA
-1.145V   -424mA     -799.3mA   -238.7mA
-1.036V   -174.1mA   -452.5mA   -60.3mA
-981.8mV  -80.13mA   -298.3mA   -30.04mA
-872.7mV  -26.27mA   -79.78mA   -32.44mA
-763.6mV  -37.27mA   -25.87mA   -50.47mA
-545.5mV  -42.85mA   -24.82mA   -62.02mA
163.6mV   9.905mA    5.464mA    14.49mA
872.7mV   32.06mA    16.22mA    49.12mA
3.545V    34.18mA    16.99mA    56.07mA
[Pullup]
-1.8V     4.02mA     3.353mA    5.71mA
-1.418V   9.153mA    6.524mA    17.71mA
-1.255V   17.65mA    10.28mA    46.46mA
-1.091V   42.13mA    17.99mA    80.98mA
-981.8mV  56.04mA    23.5mA     84.34mA
-818.2mV  48.72mA    25.01mA    69.63mA
272.7mV   -12.68mA   -6.535mA   -20.08mA
1.255V    -41.13mA   -20.87mA   -67.69mA
2.564V    -47.26mA   -22.22mA   -79.57mA
2.782V    -40.42mA   -20.82mA   -79.47mA
3.055V    -29.85mA   -19.43mA   -48.72mA
3.545V    -24.9mA    -17.8mA    -39.06mA
[GND_clamp]
-1.8V     -3.26A     -1.496A    -3.636A
-1.073V   -295.4mA   -181.3mA   -234.2mA
-1.036V   -202.2mA   -145.8mA   -132.6mA
-1V       -132.7mA   -116.1mA   -74.88mA
-963.6mV  -77.6mA    -89.37mA   -36.9mA
-927.3mV  -36.98mA   -65.53mA   -18.61mA
-890.9mV  -20.91mA   -47.52mA   -14.11mA
-854.5mV  -10.79mA   -32.36mA   -11.2mA
-818.2mV  -6.611mA   -20.04mA   -9.885mA
-709.1mV  -3.838mA   -4.175mA   -6.748mA
-527.3mV  -502uA     -336.2uA   -960.8uA
3.6V      0A         0A         0A
[Ramp]
dV/dt_f  0.7577941/0.5356592n  0.4805612/1.100802n   0.899286/0.284087n
dV/dt_r  0.7391284/0.3978043n   0.490566/0.6039913n   0.891058/0.3511714n
R_load = 50
[Rising Waveform]
R_fixture = 50
V_fixture = 1.8
V_fixture_min = 1.62
V_fixture_max = 1.89
0s        539.5mV    822.3mV    389.3mV
153ps     537.2mV    822.6mV    428.9mV
252ps     521.9mV    822.3mV    582.1mV
486ps     681.6mV    811.5mV    1.629V
603ps     904.6mV    790.1mV    1.856V
891ps     1.609V     878.4mV    1.884V
1.053ns   1.77V      986.9mV    1.886V
1.647ns   1.796V     1.45V      1.889V
1.935ns   1.798V     1.584V     1.889V
3.393ns   1.8V       1.618V     1.89V
[Rising Waveform]
R_fixture = 50
V_fixture = 0
V_fixture_min = 0
V_fixture_max = 0
0s        939.5uV    793.7uV    2.609mV
360ps     -3.834mV   476.5uV    68.78mV
720ps     39.08mV    -898uV     1.064V
873ps     308.2mV    -3.201mV   1.263V
1.116ns   821.7mV    -5.013mV   1.376V
1.287ns   1.016V     -3.058mV   1.412V
1.539ns   1.129V     61.47mV    1.441V
2.115ns   1.203V     569.7mV    1.467V
2.529ns   1.217V     718.3mV    1.473V
5.436ns   1.225V     810.8mV    1.477V
[Falling Waveform]
R_fixture = 50
V_fixture = 1.8
V_fixture_min = 1.62
V_fixture_max = 1.89
0s        1.8V       1.62V      1.89V
207ps     1.8V       1.62V      1.862V
441ps     1.779V     1.62V      1.585V
567ps     1.669V     1.62V      1.322V
765ps     1.471V     1.622V     558.6mV
864ps     1.368V     1.623V     450.4mV
1.269ns   714.7mV    1.476V     398.8mV
1.449ns   581.2mV    1.392V     395mV
2.682ns   539.9mV    867.3mV    392.2mV
4.176ns   539.6mV    824.1mV    392.2mV
[Falling Waveform]
R_fixture = 50
V_fixture = 0
V_fixture_min = 0
V_fixture_max = 0
0s        1.225V     812.6mV    1.477V
198ps     1.225V     812.4mV    1.464V
351ps     1.237V     812.9mV    1.254V
450ps     1.211V     812.8mV    994.9mV
621ps     1.009V     812.2mV    265.4mV
765ps     764.2mV    817.6mV    18.8mV
1.017ns   255.4mV    811.3mV    2.958mV
1.26ns    23.73mV    668.4mV    1.59mV
2.259ns   1.219mV    50.48mV    1.374mV
3.276ns   1.132mV    2.47mV     1.373mV
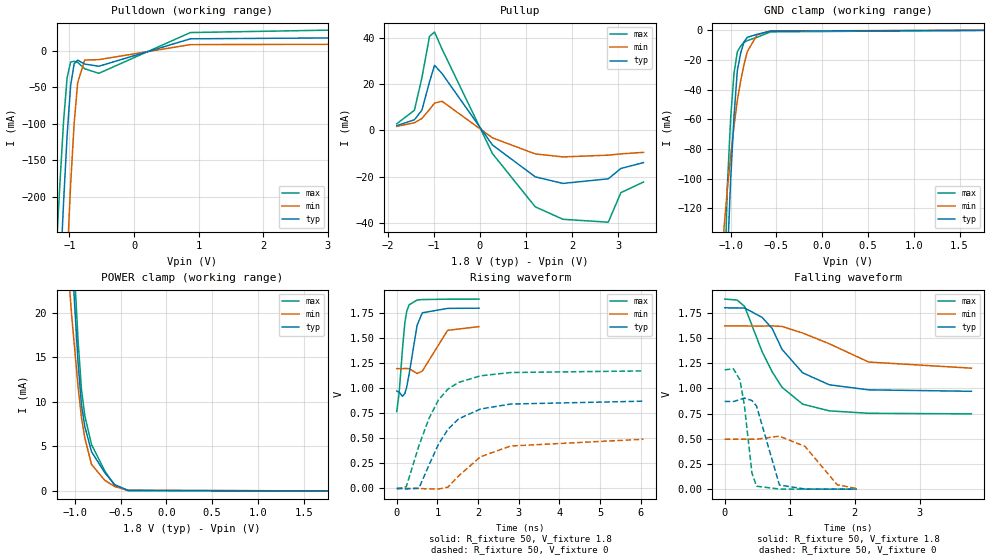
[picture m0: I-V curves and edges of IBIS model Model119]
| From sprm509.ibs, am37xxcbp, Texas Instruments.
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| Model based on original model for BQ1850OMAPSMART2HYFBPB_SSBHV
|   Sub model HYFBPB_H50_0_PUPD0_1P8
[model]   Model119
|[Input Load]   PI
|[Output Drive] LB0
|Voltage   1.8V
|Mode   I/O
Model_type   I/O
Polarity   Non-Inverting
Enable   Active-Low
Vinl =  0.63
Vinh =  1.17
Cref =  15pF
Rref =  100.0000M
Vref =  0V
Vmeas =  0.9
C_comp   1.381241p   1.221452p   1.55612p
[Model Spec]
Vinl   0.63   0.567   0.6615
Vinh   1.17   1.053   1.2285
[Temperature Range]   25   125   -40
[Voltage Range]   1.8   1.62   1.89
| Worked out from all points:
|   slope of the pulldown table from 0 to 0.27 V, typ, clamps not added: 35.5 ohm
|   slope of the pullup table from 0 to 0.27 V, typ, clamps not added: 42.9 ohm
|   GND clamp passes 1 mA (typ) near -0.61 V on its own axis
|   POWER clamp passes 1 mA (typ) near -0.60 V on its own axis
|   rising waveform, R_fixture 50, V_fixture 1.8: 20-80 % time 201ps typ, 346ps min, 136ps max; typ from 0.972 V to 1.8 V
|   rising waveform, R_fixture 50, V_fixture 0: 20-80 % time 792ps typ, 1.03ns min, 730ps max; typ from 0.002 V to 0.87 V
|   falling waveform, R_fixture 50, V_fixture 1.8: 20-80 % time 555ps typ, 805ps min, 521ps max; typ from 1.8 V to 0.971 V
|   falling waveform, R_fixture 50, V_fixture 0: 20-80 % time 185ps typ, 352ps min, 124ps max; typ from 0.871 V to 0 V
[POWER_clamp]
-1.8V     290.9mA    160.5mA    340.8mA
-1.109V   45.77mA    30.42mA    51.16mA
-1.073V   35.98mA    25mA       40.42mA
-1.036V   26.91mA    19.86mA    30.73mA
-963.6mV  14.2mA     11.6mA     16.73mA
-927.3mV  9.664mA    8.209mA    11.37mA
-890.9mV  7.224mA    5.944mA    8.437mA
-818.2mV  4.412mA    2.986mA    5.219mA
-672.7mV  2.045mA    1.194mA    2.238mA
-563.6mV  702.5uA    479.8uA    586.6uA
-418.2mV  58.7uA     73.5uA     24.66uA
1.764V    -856.1pA   -69.76nA   -985.3pA
[Pulldown]
-1.8V     -1.423A    -2.058A    -1.157A
-1.2V     -415.4mA   -653.2mA   -267mA
-1.145V   -309.6mA   -525.9mA   -177.9mA
-1.091V   -207.6mA   -402.8mA   -96.73mA
-1.036V   -115.8mA   -286.9mA   -37.04mA
-981.8mV  -48.02mA   -183.2mA   -15.64mA
-927.3mV  -18.04mA   -99.43mA   -14.72mA
-872.7mV  -13.22mA   -44mA      -16.16mA
-763.6mV  -18.5mA    -13.02mA   -24.96mA
-545.5mV  -21.5mA    -12.44mA   -31.16mA
872.7mV   16.04mA    8.112mA    24.59mA
3.545V    17.47mA    8.568mA    28.69mA
[Pullup]
-1.8V     2.003mA    1.674mA    2.831mA
-1.418V   4.544mA    3.255mA    8.658mA
-1.255V   8.731mA    5.125mA    22.8mA
-1.091V   20.98mA    8.984mA    40.62mA
-981.8mV  28.13mA    11.78mA    42.49mA
-818.2mV  24.52mA    12.54mA    35.08mA
272.7mV   -6.354mA   -3.271mA   -10.08mA
1.2V      -20.15mA   -10.23mA   -33.12mA
1.8V      -22.99mA   -11.52mA   -38.52mA
2.782V    -21mA      -10.76mA   -39.77mA
3.055V    -16.52mA   -10.21mA   -26.99mA
3.545V    -13.98mA   -9.552mA   -22.39mA
[GND_clamp]
-1.8V     -2.709A    -1.157A    -3.075A
-1.073V   -228.7mA   -133.6mA   -187.2mA
-1.036V   -154.6mA   -106.9mA   -104.7mA
-1V       -100.4mA   -84.69mA   -59.09mA
-963.6mV  -57.98mA   -64.82mA   -29.02mA
-927.3mV  -27.21mA   -47.25mA   -14.49mA
-890.9mV  -15.32mA   -34.13mA   -10.63mA
-854.5mV  -7.819mA   -23.14mA   -8.114mA
-818.2mV  -4.712mA   -14.27mA   -6.938mA
-709.1mV  -2.652mA   -2.932mA   -4.656mA
-563.6mV  -543.1uA   -385.8uA   -1.041mA
1.764V    64.75pA    408.4nA    3.013nA
[Ramp]
dV/dt_f  0.4977308/0.5560603n  0.2554834/0.8282055n  0.6867806/0.521555n
dV/dt_r  0.5298077/0.7943013n  0.3006053/1.05538n   0.7138144/0.7318412n
R_load = 50
[Rising Waveform]
R_fixture = 50
V_fixture = 1.8
V_fixture_min = 1.62
V_fixture_max = 1.89
0s        972mV      1.195V     766.5mV
58.4ps    960.3mV    1.195V     953.4mV
140.8ps   918.5mV    1.195V     1.393V
199.2ps   947.3mV    1.196V     1.656V
244.8ps   1.012V     1.196V     1.768V
304.8ps   1.143V     1.195V     1.832V
500.8ps   1.629V     1.146V     1.879V
628.8ps   1.752V     1.171V     1.884V
1.25ns    1.796V     1.577V     1.888V
2.022ns   1.798V     1.614V     1.889V
[Rising Waveform]
R_fixture = 50
V_fixture = 0
V_fixture_min = 0
V_fixture_max = 0
0s        1.785mV    77.3uV     -7.926mV
232.8ps   -5.772mV   -187.8uV   15.77mV
545.6ps   2.503mV    -1.256mV   427.3mV
792ps     232.5mV    -5.2mV     697.9mV
1.025ns   439.9mV    -6.408mV   882.3mV
1.258ns   588.8mV    12.14mV    990.5mV
1.517ns   692.8mV    122.7mV    1.057V
2.059ns   792.1mV    315.4mV    1.123V
2.8ns     841.6mV    422.8mV    1.156V
6.067ns   870.1mV    490.3mV    1.172V
[Falling Waveform]
R_fixture = 50
V_fixture = 1.8
V_fixture_min = 1.62
V_fixture_max = 1.89
0s        1.8V       1.62V      1.887V
192ps     1.799V     1.62V      1.877V
307.2ps   1.798V     1.62V      1.813V
575.2ps   1.705V     1.619V     1.365V
728.8ps   1.596V     1.621V     1.166V
882.4ps   1.387V     1.615V     1.011V
1.199ns   1.155V     1.55V      843.8mV
1.609ns   1.036V     1.443V     777.3mV
2.214ns   985.9mV    1.262V     753.2mV
3.794ns   971.5mV    1.201V     747.4mV
[Falling Waveform]
R_fixture = 50
V_fixture = 0
V_fixture_min = 0
V_fixture_max = 0
0s        871.1mV    496mV      1.184V
133.6ps   869.8mV    496mV      1.196V
234.4ps   889.8mV    496.1mV    1.084V
300.8ps   904.4mV    496.1mV    842.7mV
419.2ps   879.6mV    495.9mV    159.6mV
489.6ps   825.3mV    495.7mV    29.4mV
841.6ps   41.25mV    526mV      1.081mV
1.236ns   1.465mV    423.8mV    340.1uV
1.73ns    404uV      43.86mV    88.4uV
2.031ns   249.8uV    5.68mV     46.7uV
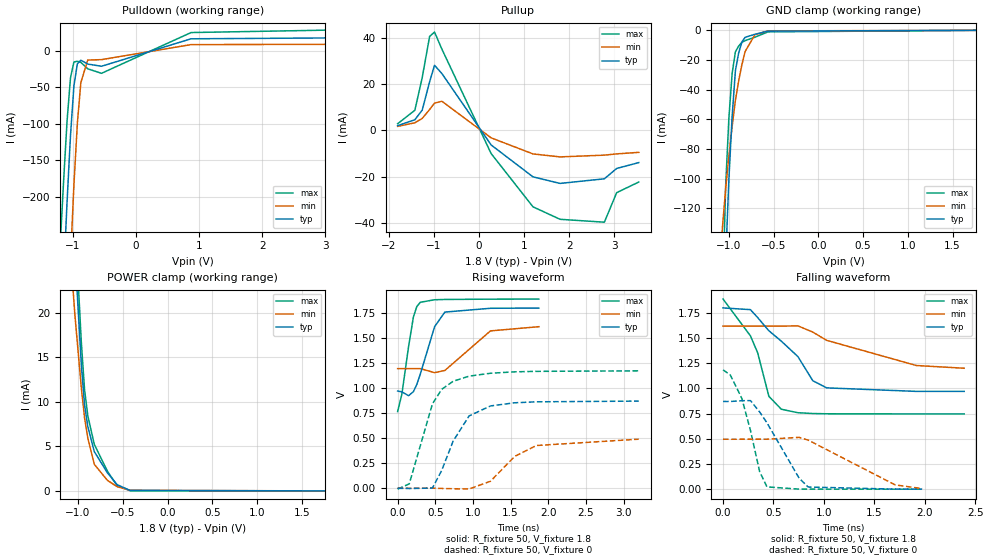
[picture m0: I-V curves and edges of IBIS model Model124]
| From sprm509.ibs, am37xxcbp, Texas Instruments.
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| Model based on original model for BQ1850OMAPSMART2HYFBPB_SSBHV
|   Sub model HYFBPB_H50_1_PUPD0_1P8
[model]   Model124
|[Input Load]   PI
|[Output Drive] LB1
|Voltage   1.8V
|Mode   I/O
Model_type   I/O
Polarity   Non-Inverting
Enable   Active-Low
Vinl =  0.63
Vinh =  1.17
Cref =  15pF
Rref =  100.0000M
Vref =  0V
Vmeas =  0.9
C_comp   1.381241p   1.221452p   1.55612p
[Model Spec]
Vinl   0.63   0.567   0.6615
Vinh   1.17   1.053   1.2285
[Temperature Range]   25   125   -40
[Voltage Range]   1.8   1.62   1.89
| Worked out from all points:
|   slope of the pulldown table from 0 to 0.27 V, typ, clamps not added: 35.5 ohm
|   slope of the pullup table from 0 to 0.27 V, typ, clamps not added: 42.9 ohm
|   GND clamp passes 1 mA (typ) near -0.61 V on its own axis
|   POWER clamp passes 1 mA (typ) near -0.60 V on its own axis
|   rising waveform, R_fixture 50, V_fixture 1.8: 20-80 % time 202ps typ, 354ps min, 130ps max; typ from 0.972 V to 1.8 V
|   rising waveform, R_fixture 50, V_fixture 0: 20-80 % time 331ps typ, 447ps min, 308ps max; typ from 0 V to 0.871 V
|   falling waveform, R_fixture 50, V_fixture 1.8: 20-80 % time 449ps typ, 830ps min, 249ps max; typ from 1.8 V to 0.971 V
|   falling waveform, R_fixture 50, V_fixture 0: 20-80 % time 305ps typ, 582ps min, 178ps max; typ from 0.871 V to 0 V
[POWER_clamp]
-1.8V     290.9mA    160.5mA    340.8mA
-1.109V   45.77mA    30.42mA    51.16mA
-1.073V   35.98mA    25mA       40.42mA
-1.036V   26.91mA    19.86mA    30.73mA
-963.6mV  14.2mA     11.6mA     16.73mA
-927.3mV  9.664mA    8.209mA    11.37mA
-890.9mV  7.224mA    5.944mA    8.437mA
-818.2mV  4.412mA    2.986mA    5.219mA
-672.7mV  2.045mA    1.194mA    2.238mA
-563.6mV  702.5uA    479.8uA    586.6uA
-418.2mV  58.7uA     73.5uA     24.66uA
1.764V    -856.1pA   -69.76nA   -985.3pA
[Pulldown]
-1.8V     -1.423A    -2.058A    -1.157A
-1.2V     -415.4mA   -653.2mA   -267mA
-1.145V   -309.6mA   -525.9mA   -177.9mA
-1.091V   -207.6mA   -402.8mA   -96.73mA
-1.036V   -115.8mA   -286.9mA   -37.04mA
-981.8mV  -48.02mA   -183.2mA   -15.64mA
-927.3mV  -18.04mA   -99.43mA   -14.72mA
-872.7mV  -13.22mA   -44mA      -16.16mA
-763.6mV  -18.5mA    -13.02mA   -24.96mA
-545.5mV  -21.5mA    -12.44mA   -31.16mA
872.7mV   16.04mA    8.112mA    24.59mA
3.545V    17.47mA    8.568mA    28.69mA
[Pullup]
-1.8V     2.003mA    1.674mA    2.831mA
-1.418V   4.544mA    3.255mA    8.658mA
-1.255V   8.731mA    5.125mA    22.8mA
-1.091V   20.98mA    8.984mA    40.62mA
-981.8mV  28.13mA    11.78mA    42.49mA
-818.2mV  24.52mA    12.54mA    35.08mA
272.7mV   -6.354mA   -3.271mA   -10.08mA
1.2V      -20.15mA   -10.23mA   -33.12mA
1.8V      -22.99mA   -11.52mA   -38.52mA
2.782V    -21mA      -10.76mA   -39.77mA
3.055V    -16.52mA   -10.21mA   -26.99mA
3.545V    -13.98mA   -9.552mA   -22.39mA
[GND_clamp]
-1.8V     -2.709A    -1.157A    -3.075A
-1.073V   -228.7mA   -133.6mA   -187.2mA
-1.036V   -154.6mA   -106.9mA   -104.7mA
-1V       -100.4mA   -84.69mA   -59.09mA
-963.6mV  -57.98mA   -64.82mA   -29.02mA
-927.3mV  -27.21mA   -47.25mA   -14.49mA
-890.9mV  -15.32mA   -34.13mA   -10.63mA
-854.5mV  -7.819mA   -23.14mA   -8.114mA
-818.2mV  -4.712mA   -14.27mA   -6.938mA
-709.1mV  -2.652mA   -2.932mA   -4.656mA
-563.6mV  -543.1uA   -385.8uA   -1.041mA
1.764V    64.75pA    408.4nA    3.013nA
[Ramp]
dV/dt_f  0.4991879/0.4494974n  0.2569384/0.8428337n  0.6862467/0.2498021n
dV/dt_r  0.5290583/0.332565n   0.3017044/0.4609661n  0.7112223/0.3079929n
R_load = 50
[Rising Waveform]
R_fixture = 50
V_fixture = 1.8
V_fixture_min = 1.62
V_fixture_max = 1.89
0s        971.7mV    1.195V     766.1mV
56.8ps    962.7mV    1.195V     942.4mV
145.6ps   924.8mV    1.195V     1.417V
209.6ps   965.1mV    1.196V     1.712V
255.2ps   1.038V     1.196V     1.816V
300.8ps   1.14V      1.195V     1.858V
491.2ps   1.615V     1.155V     1.883V
627.2ps   1.76V      1.177V     1.886V
1.232ns   1.798V     1.572V     1.889V
1.874ns   1.8V       1.614V     1.89V
[Rising Waveform]
R_fixture = 50
V_fixture = 0
V_fixture_min = 0
V_fixture_max = 0
0s        385.2uV    72.02uV    -8.822mV
154.4ps   -2.153mV   -125.5uV   44.34mV
461.6ps   1.922mV    920.7uV    842.1mV
584.8ps   177.7mV    -1.587mV   988.4mV
736.8ps   471mV      -4.702mV   1.069V
948.8ps   722.7mV    -6.983mV   1.12V
1.232ns   822.3mV    70.1mV     1.149V
1.554ns   853.9mV    318.7mV    1.163V
1.84ns    863.6mV    427.2mV    1.168V
3.201ns   870.8mV    490.3mV    1.173V
[Falling Waveform]
R_fixture = 50
V_fixture = 1.8
V_fixture_min = 1.62
V_fixture_max = 1.89
0s        1.8V       1.62V      1.888V
271.2ps   1.783V     1.62V      1.523V
343.2ps   1.704V     1.62V      1.354V
454.4ps   1.573V     1.62V      921.6mV
577.6ps   1.47V      1.619V     793.9mV
741.6ps   1.317V     1.622V     759.2mV
889.6ps   1.077V     1.56V      751.3mV
1.027ns   1.006V     1.478V     748.7mV
1.916ns   971.1mV    1.228V     747.2mV
2.39ns    970.9mV    1.201V     747.1mV
[Falling Waveform]
R_fixture = 50
V_fixture = 0
V_fixture_min = 0
V_fixture_max = 0
0s        871.1mV    496mV      1.185V
72ps      870.8mV    495.8mV    1.134V
186.4ps   878.7mV    496.1mV    901.1mV
272ps     879.2mV    496.1mV    582.8mV
362.4ps   767.5mV    496.1mV    175.4mV
435.2ps   659.2mV    495.9mV    22.62mV
754.4ps   108.6mV    514.5mV    417.4uV
843.2ps   21.33mV    487.6mV    225.9uV
1.706ns   199.8uV    42.41mV    1.715uV
1.973ns   141.1uV    5.708mV    830.2nV
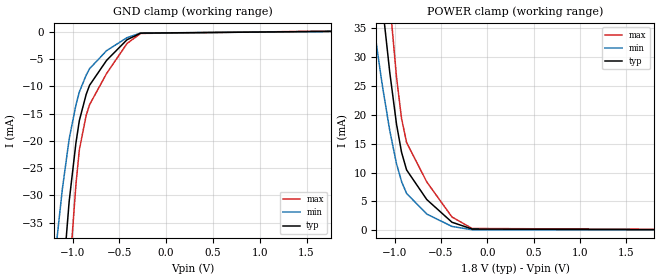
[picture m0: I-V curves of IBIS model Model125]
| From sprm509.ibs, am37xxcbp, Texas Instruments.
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| Model based on original model for CAMERARX_CORE
|   Sub model CAMERARX_CORE_PD_ON
[model]   Model125
|[Input Load]   PD
|[Output Drive]
|Voltage   1.8V
|Mode   INPUT
Model_type   Input
Polarity   Non-Inverting
Vinl =  0.63
Vinh =  1.17
C_comp   4.13955p   3.54198p   4.784869p
[Model Spec]
Vinl   0.63   0.567   0.6615
Vinh   1.17   1.053   1.2285
[Temperature Range]   25   125   -40
[Voltage Range]   1.8   1.62   1.92
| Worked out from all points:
|   GND clamp passes 1 mA (typ) near -0.38 V on its own axis
|   POWER clamp passes 1 mA (typ) near -0.34 V on its own axis
[POWER_clamp]
-1.8V     156.8mA    109.4mA    217.7mA
-1.255V   58.61mA    38.51mA    83.64mA
-1.145V   40.74mA    26.16mA    58.74mA
-1.127V   37.98mA    24.3mA     54.83mA
-1.055V   27.39mA    17.28mA    39.71mA
-981.8mV  18.38mA    11.52mA    26.53mA
-927.3mV  13.51mA    8.445mA    19.36mA
-872.7mV  10.45mA    6.379mA    15.19mA
-654.5mV  5.319mA    2.808mA    8.366mA
-381.8mV  1.388mA    664uA      2.294mA
-163.6mV  213.4uA    86.79uA    305.9uA
1.8V      110.1uA    53.6uA     169.3uA
[GND_clamp]
-1.8V     -252.1mA   -161mA     -379.9mA
-1.218V   -75mA      -46.17mA   -113.7mA
-1.109V   -46.69mA   -28.88mA   -69.6mA
-1.036V   -31.09mA   -19.65mA   -44.93mA
-963.6mV  -20.36mA   -13.4mA    -27.98mA
-927.3mV  -16.27mA   -11.01mA   -21.64mA
-854.5mV  -11.47mA   -7.933mA   -15.33mA
-818.2mV  -9.793mA   -6.756mA   -13.36mA
-636.4mV  -5.221mA   -3.433mA   -7.63mA
-418.2mV  -1.433mA   -1.049mA   -2.128mA
-272.7mV  -219.5uA   -198.1uA   -266.5uA
1.764V    108.8uA    78.64uA    165.8uA
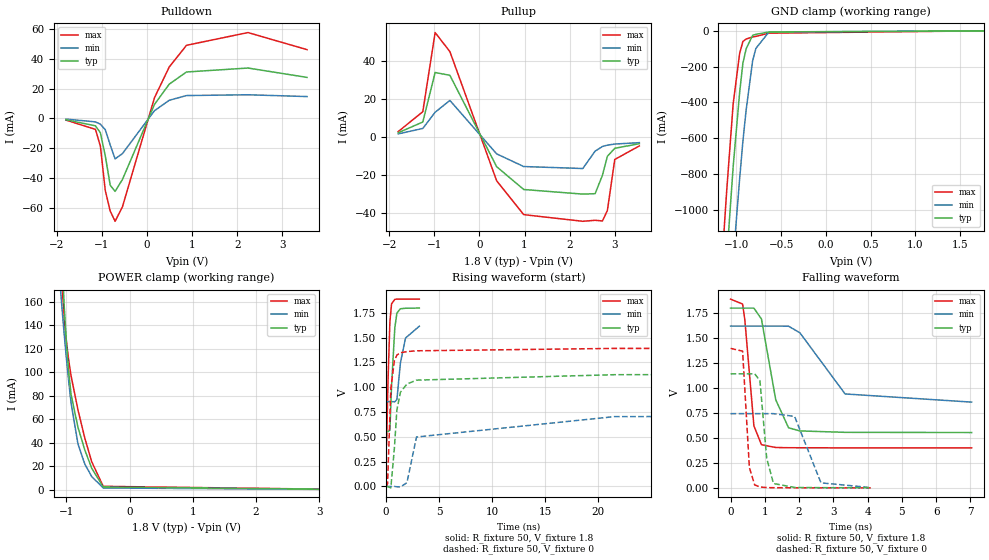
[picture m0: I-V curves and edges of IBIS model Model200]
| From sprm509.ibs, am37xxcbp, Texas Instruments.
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| Model based on original model for BQMMC1833DVHYPBFZLP18_SSCHH
|   Sub model H_SPEEDCTRL0_PD1_1P8
[model]   Model200
|[Input Load]   PD
|[Output Drive] SC0
|Voltage   1.8V
|Mode   I/O
Model_type   I/O
Polarity   Non-Inverting
Enable   Active-Low
Vinl =  0.54
Vinh =  1.26
Cref =  15pF
Rref =  100.0000M
Vref =  0V
Vmeas =  0.9
C_comp   6.565579p   6.22498p   6.65822p
[Model Spec]
Vinl   0.54   0.486   0.567
Vinh   1.26   1.134   1.323
[Temperature Range]   25   125   -40
[Voltage Range]   1.8   1.62   1.89
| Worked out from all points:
|   slope of the pulldown table from 0 to 0.27 V, typ, clamps not added: 18.6 ohm
|   slope of the pullup table from 0 to 0.27 V, typ, clamps not added: 23.2 ohm
|   GND clamp passes 1 mA (typ) near -0.52 V on its own axis
|   POWER clamp passes 1 mA (typ) near -0.38 V on its own axis
|   rising waveform, R_fixture 50, V_fixture 1.8: 20-80 % time 354ps typ, 628ps min, 233ps max; typ from 0.553 V to 1.8 V
|   rising waveform, R_fixture 50, V_fixture 0: 20-80 % time 541ps typ, 1.67ns min, 340ps max; typ from 0 V to 1.14 V
|   falling waveform, R_fixture 50, V_fixture 1.8: 20-80 % time 395ps typ, 842ps min, 218ps max; typ from 1.8 V to 0.554 V
|   falling waveform, R_fixture 50, V_fixture 0: 20-80 % time 169ps typ, 404ps min, 115ps max; typ from 1.14 V to 0.001 V
[POWER_clamp]
-1.8V     1.506A     743.4mA    1.547A
-1.109V   249.7mA    180.9mA    217.2mA
-1.073V   201.1mA    156.2mA    177.1mA
-1.036V   156.8mA    132.4mA    144.9mA
-1V       125.1mA    111.2mA    126mA
-963.6mV  99.89mA    91.72mA    110mA
-927.3mV  81.17mA    73.97mA    96.98mA
-818.2mV  53.15mA    39.05mA    68.03mA
-709.1mV  33.72mA    21.71mA    43.8mA
-600mV    18.2mA     11.1mA     23.73mA
-418.2mV  2.266mA    1.393mA    2.799mA
3.6V      0A         0A         0A
[Pulldown]
-1.8V     -930.6uA   -453.8uA   -1.127mA
-1.145V   -4.983mA   -2.358mA   -7.387mA
-1.036V   -9.64mA    -3.874mA   -18.47mA
-927.3mV  -25.02mA   -7.595mA   -48.3mA
-818.2mV  -44.84mA   -17.79mA   -62.17mA
-709.1mV  -49.04mA   -27.19mA   -69.1mA
-545.5mV  -40.99mA   -23.62mA   -59.29mA
163.6mV   9.392mA    5.153mA    13.85mA
490.9mV   22.98mA    12.15mA    34.51mA
872.7mV   31.15mA    15.33mA    49.06mA
2.236V    33.81mA    15.86mA    57.62mA
3.545V    27.52mA    14.65mA    46.15mA
[Pullup]
-1.8V     2.285mA    1.654mA    2.864mA
-1.255V   7.884mA    4.537mA    13.31mA
-981.8mV  33.89mA    13.01mA    54.84mA
-654.5mV  32.4mA     19.23mA    44.84mA
381.8mV   -15.55mA   -8.814mA   -22.93mA
981.8mV   -27.52mA   -15.47mA   -40.71mA
2.291V    -29.94mA   -16.51mA   -44.21mA
2.564V    -29.72mA   -7.406mA   -43.68mA
2.727V    -20.03mA   -4.942mA   -44.02mA
2.836V    -10.1mA    -4.243mA   -38.57mA
3V        -5.903mA   -3.661mA   -11.75mA
3.545V    -3.469mA   -2.933mA   -4.654mA
[GND_clamp]
-1.8V     -7.151A    -7.205A    -6.863A
-1.182V   -1.844A    -2.309A    -1.461A
-1.145V   -1.557A    -2.041A    -1.171A
-1.109V   -1.281A    -1.782A    -899.6mA
-1.036V   -759.7mA   -1.281A    -408.5mA
-963.6mV  -344.6mA   -827mA     -125.9mA
-927.3mV  -181.3mA   -617.3mA   -59.93mA
-890.9mV  -99.98mA   -442.2mA   -45.98mA
-818.2mV  -25.09mA   -166.6mA   -34.17mA
-781.8mV  -19.68mA   -98.02mA   -31.09mA
-636.4mV  -6.261mA   -6.836mA   -13.18mA
1.764V    22.34uA    15.06uA    31.23uA
[Ramp]
dV/dt_f  0.7480805/0.3936647n  0.4587036/0.8458612n  0.8938595/0.2143514n
dV/dt_r  0.6940902/0.5342137n  0.4509022/1.605563n   0.8485513/0.339005n
R_load = 50
[Rising Waveform]
R_fixture = 50
V_fixture = 1.8
V_fixture_min = 1.62
V_fixture_max = 1.89
0s        553.3mV    855.6mV    399.1mV
44ps      553.3mV    855.6mV    432.3mV
176ps     553.3mV    855.6mV    1.065V
352ps     567.3mV    855.6mV    1.66V
506ps     1.007V     855.6mV    1.841V
814ps     1.598V     853.6mV    1.887V
1.012ns   1.749V     876.7mV    1.889V
1.342ns   1.792V     1.244V     1.889V
1.826ns   1.797V     1.497V     1.889V
3.124ns   1.799V     1.616V     1.889V
[Rising Waveform]
R_fixture = 50
V_fixture = 0
V_fixture_min = 0
V_fixture_max = 0
0s        869.4nV    2.446uV    -3.016mV
132ps     -14.16uV   2.718uV    25.87mV
440ps     -14.14mV   3.377uV    985mV
770ps     377.5mV    212.3uV    1.265V
1.012ns   773.6mV    -3.309mV   1.325V
1.342ns   949.2mV    -5.144mV   1.348V
1.958ns   1.033V     38.22mV    1.36V
2.86ns    1.072V     499mV      1.368V
21.52ns   1.127V     704.3mV    1.392V
217ns     1.142V     740.2mV    1.397V
[Falling Waveform]
R_fixture = 50
V_fixture = 1.8
V_fixture_min = 1.62
V_fixture_max = 1.89
0s        1.8V       1.62V      1.89V
352ps     1.8V       1.62V      1.841V
418ps     1.8V       1.62V      1.68V
682ps     1.8V       1.62V      620.9mV
902ps     1.691V     1.62V      432.5mV
1.32ns    881.4mV    1.62V      404.3mV
1.694ns   601.5mV    1.619V     402.2mV
2.024ns   570.3mV    1.553V     401.7mV
3.344ns   556.2mV    940.6mV    400.9mV
7.04ns    554.2mV    858.8mV    400.5mV
[Falling Waveform]
R_fixture = 50
V_fixture = 0
V_fixture_min = 0
V_fixture_max = 0
0s        1.142V     743.4mV    1.397V
352ps     1.142V     743.4mV    1.369V
550ps     1.142V     743.4mV    203mV
704ps     1.143V     743.4mV    29.45mV
858ps     1.073V     743.4mV    8.928mV
1.056ns   294.7mV    743.4mV    3.205mV
1.254ns   43.48mV    743.3mV    1.861mV
1.87ns    4.666mV    715.6mV    886.1uV
2.64ns    2.122mV    50.25mV    499.9uV
4.092ns   1.1mV      3.335mV    264.8uV
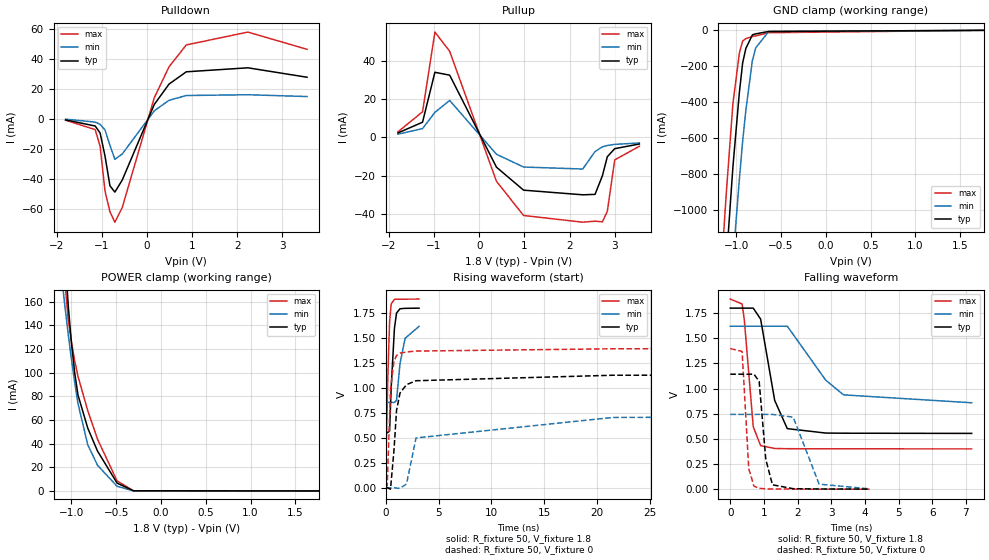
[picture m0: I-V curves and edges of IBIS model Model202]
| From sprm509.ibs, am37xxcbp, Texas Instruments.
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| Model based on original model for BQMMC1833DVHYPBFZLP18_SSCHH
|   Sub model SPEEDCTRL0_PUPD0_1P8
[model]   Model202
|[Input Load]   PI
|[Output Drive] SC0
|Voltage   1.8V
|Mode   I/O
Model_type   I/O
Polarity   Non-Inverting
Enable   Active-Low
Vinl =  0.54
Vinh =  1.26
Cref =  15pF
Rref =  100.0000M
Vref =  0V
Vmeas =  0.9
C_comp   6.565579p   6.22498p   6.65822p
[Model Spec]
Vinl   0.54   0.486   0.567
Vinh   1.26   1.134   1.323
[Temperature Range]   25   125   -40
[Voltage Range]   1.8   1.62   1.89
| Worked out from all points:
|   slope of the pulldown table from 0 to 0.27 V, typ, clamps not added: 18.6 ohm
|   slope of the pullup table from 0 to 0.27 V, typ, clamps not added: 23.2 ohm
|   GND clamp passes 1 mA (typ) near -0.52 V on its own axis
|   POWER clamp passes 1 mA (typ) near -0.38 V on its own axis
|   rising waveform, R_fixture 50, V_fixture 1.8: 20-80 % time 354ps typ, 627ps min, 233ps max; typ from 0.553 V to 1.8 V
|   rising waveform, R_fixture 50, V_fixture 0: 20-80 % time 541ps typ, 1.69ns min, 340ps max; typ from 0 V to 1.14 V
|   falling waveform, R_fixture 50, V_fixture 1.8: 20-80 % time 395ps typ, 843ps min, 218ps max; typ from 1.8 V to 0.555 V
|   falling waveform, R_fixture 50, V_fixture 0: 20-80 % time 170ps typ, 404ps min, 115ps max; typ from 1.14 V to 0.001 V
[POWER_clamp]
-1.8V     1.506A     743.4mA    1.547A
-1.109V   249.7mA    180.9mA    217.2mA
-1.073V   201.1mA    156.2mA    177.1mA
-1.036V   156.8mA    132.4mA    144.8mA
-1V       125.1mA    111.2mA    125.9mA
-963.6mV  99.87mA    91.7mA     110mA
-927.3mV  81.15mA    73.95mA    96.95mA
-818.2mV  53.12mA    39.04mA    68mA
-709.1mV  33.7mA     21.7mA     43.76mA
-490.9mV  6.624mA    3.934mA    8.515mA
-309.1mV  135.7uA    124.1uA    133.8uA
1.764V    -66.87nA   -313.7nA   -600.6nA
[Pulldown]
-1.8V     -930.6uA   -453.8uA   -1.127mA
-1.145V   -4.983mA   -2.358mA   -7.387mA
-1.036V   -9.64mA    -3.874mA   -18.47mA
-927.3mV  -25.02mA   -7.595mA   -48.3mA
-818.2mV  -44.84mA   -17.79mA   -62.17mA
-709.1mV  -49.04mA   -27.19mA   -69.1mA
-545.5mV  -40.99mA   -23.62mA   -59.29mA
163.6mV   9.392mA    5.153mA    13.85mA
490.9mV   22.98mA    12.15mA    34.51mA
872.7mV   31.15mA    15.33mA    49.06mA
2.236V    33.81mA    15.86mA    57.62mA
3.545V    27.52mA    14.65mA    46.15mA
[Pullup]
-1.8V     2.285mA    1.654mA    2.864mA
-1.255V   7.884mA    4.537mA    13.31mA
-981.8mV  33.89mA    13.01mA    54.84mA
-654.5mV  32.4mA     19.23mA    44.84mA
381.8mV   -15.55mA   -8.814mA   -22.93mA
981.8mV   -27.52mA   -15.47mA   -40.71mA
2.291V    -29.94mA   -16.51mA   -44.21mA
2.564V    -29.72mA   -7.406mA   -43.68mA
2.727V    -20.03mA   -4.942mA   -44.02mA
2.836V    -10.1mA    -4.243mA   -38.57mA
3V        -5.903mA   -3.661mA   -11.75mA
3.545V    -3.469mA   -2.933mA   -4.654mA
[GND_clamp]
-1.8V     -7.151A    -7.205A    -6.863A
-1.182V   -1.844A    -2.309A    -1.461A
-1.145V   -1.557A    -2.041A    -1.171A
-1.109V   -1.281A    -1.782A    -899.6mA
-1.036V   -759.7mA   -1.281A    -408.5mA
-963.6mV  -344.6mA   -827mA     -125.9mA
-927.3mV  -181.3mA   -617.3mA   -59.93mA
-890.9mV  -99.98mA   -442.2mA   -45.98mA
-818.2mV  -25.09mA   -166.6mA   -34.17mA
-781.8mV  -19.68mA   -98.02mA   -31.08mA
-636.4mV  -6.256mA   -6.834mA   -13.17mA
1.764V    494.4nA    2.074uA    1.041uA
[Ramp]
dV/dt_f  0.7481848/0.3941059n  0.4586873/0.8466932n  0.8940134/0.2145486n
dV/dt_r  0.6943021/0.5348517n  0.4510278/1.608683n   0.8487888/0.3393422n
R_load = 50
[Rising Waveform]
R_fixture = 50
V_fixture = 1.8
V_fixture_min = 1.62
V_fixture_max = 1.89
0s        553.4mV    855.8mV    399.2mV
44ps      553.4mV    855.8mV    432.4mV
176ps     553.5mV    855.8mV    1.065V
352ps     567.4mV    855.8mV    1.66V
506ps     1.007V     855.8mV    1.841V
814ps     1.598V     853.9mV    1.887V
1.012ns   1.75V      877mV      1.889V
1.342ns   1.793V     1.245V     1.889V
1.826ns   1.797V     1.497V     1.889V
3.146ns   1.799V     1.617V     1.89V
[Rising Waveform]
R_fixture = 50
V_fixture = 0
V_fixture_min = 0
V_fixture_max = 0
0s        876nV      2.467uV    -3.016mV
132ps     -14.15uV   2.738uV    25.87mV
440ps     -14.14mV   3.398uV    985mV
770ps     377.5mV    212.3uV    1.265V
1.012ns   773.6mV    -3.309mV   1.325V
1.342ns   949.2mV    -5.144mV   1.348V
1.958ns   1.033V     38.22mV    1.36V
2.86ns    1.072V     499mV      1.369V
21.52ns   1.127V     704.3mV    1.392V
217.1ns   1.142V     740.4mV    1.398V
[Falling Waveform]
R_fixture = 50
V_fixture = 1.8
V_fixture_min = 1.62
V_fixture_max = 1.89
0s        1.8V       1.62V      1.89V
352ps     1.8V       1.62V      1.841V
418ps     1.8V       1.62V      1.68V
682ps     1.8V       1.62V      621.8mV
902ps     1.691V     1.62V      433mV
1.32ns    882.2mV    1.62V      404.7mV
1.694ns   602mV      1.62V      402.6mV
2.838ns   558mV      1.083V     401.4mV
3.366ns   556.6mV    937.7mV    401.2mV
7.172ns   554.6mV    859.1mV    400.7mV
[Falling Waveform]
R_fixture = 50
V_fixture = 0
V_fixture_min = 0
V_fixture_max = 0
0s        1.143V     743.6mV    1.398V
352ps     1.143V     743.6mV    1.369V
550ps     1.143V     743.6mV    203.5mV
704ps     1.143V     743.6mV    29.68mV
858ps     1.073V     743.6mV    9.136mV
1.056ns   295.2mV    743.6mV    3.405mV
1.254ns   43.69mV    743.5mV    2.058mV
1.87ns    4.833mV    715.8mV    1.071mV
2.64ns    2.285mV    50.37mV    655.3uV
4.136ns   1.237mV    3.298mV    361.6uV
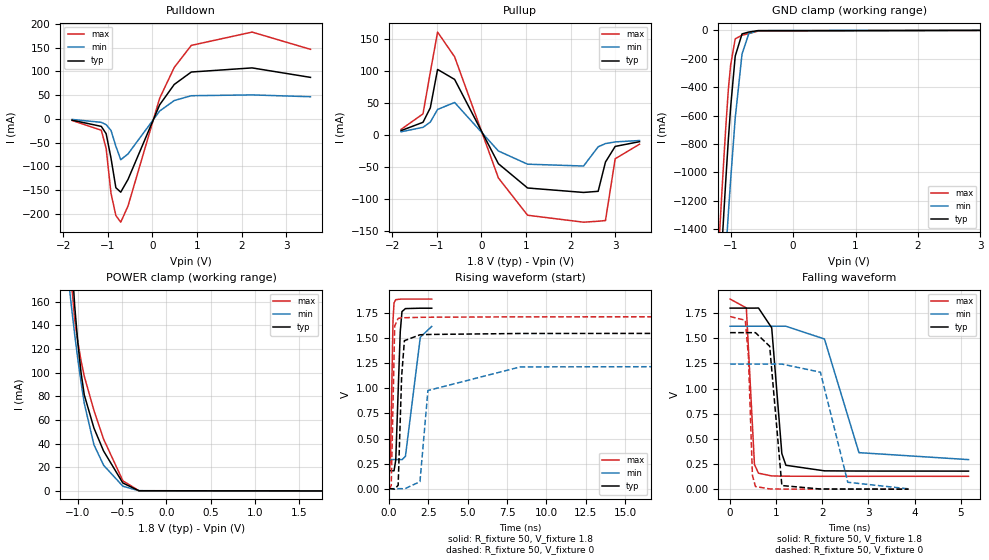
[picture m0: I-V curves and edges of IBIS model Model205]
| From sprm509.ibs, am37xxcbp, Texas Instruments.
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| Model based on original model for BQMMC1833DVHYPBFZLP18_SSCHH
|   Sub model H_SPEEDCTRL1_PU1_1P8
[model]   Model205
|[Input Load]   PU
|[Output Drive] SC1
|Voltage   1.8V
|Mode   I/O
Model_type   I/O
Polarity   Non-Inverting
Enable   Active-Low
Vinl =  0.54
Vinh =  1.26
Cref =  15pF
Rref =  100.0000M
Vref =  0V
Vmeas =  0.9
C_comp   6.565579p   6.22498p   6.65822p
[Model Spec]
Vinl   0.54   0.486   0.567
Vinh   1.26   1.134   1.323
[Temperature Range]   25   125   -40
[Voltage Range]   1.8   1.62   1.89
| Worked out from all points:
|   slope of the pulldown table from 0 to 0.27 V, typ, clamps not added: 5.93 ohm
|   slope of the pullup table from 0 to 0.27 V, typ, clamps not added: 8.03 ohm
|   GND clamp passes 1 mA (typ) near -0.52 V on its own axis
|   POWER clamp passes 1 mA (typ) near -0.38 V on its own axis
|   rising waveform, R_fixture 50, V_fixture 1.8: 20-80 % time 216ps typ, 611ps min, 115ps max; typ from 0.179 V to 1.8 V
|   rising waveform, R_fixture 50, V_fixture 0: 20-80 % time 186ps typ, 752ps min, 112ps max; typ from 0 V to 1.56 V
|   falling waveform, R_fixture 50, V_fixture 1.8: 20-80 % time 156ps typ, 407ps min, 93.8ps max; typ from 1.8 V to 0.18 V
|   falling waveform, R_fixture 50, V_fixture 0: 20-80 % time 123ps typ, 302ps min, 72.7ps max; typ from 1.56 V to 0.001 V
[POWER_clamp]
-1.8V     1.506A     743.4mA    1.547A
-1.109V   249.7mA    180.9mA    217.2mA
-1.073V   201.1mA    156.2mA    177.1mA
-1.036V   156.8mA    132.4mA    144.8mA
-1V       125.1mA    111.2mA    125.9mA
-963.6mV  99.87mA    91.71mA    110mA
-927.3mV  81.15mA    73.96mA    96.95mA
-818.2mV  53.13mA    39.04mA    68mA
-709.1mV  33.7mA     21.7mA     43.77mA
-490.9mV  6.629mA    3.937mA    8.521mA
-309.1mV  139.6uA    126.3uA    139.1uA
1.764V    -25.18uA   -15.38uA   -34.57uA
[Pulldown]
-1.8V     -2.955mA   -1.439mA   -3.582mA
-1.145V   -16.06mA   -7.517mA   -24.16mA
-1.036V   -31.52mA   -12.4mA    -62.37mA
-927.3mV  -82.88mA   -24.53mA   -156.9mA
-818.2mV  -145.2mA   -57.9mA    -203.7mA
-709.1mV  -154.6mA   -86.29mA   -217.8mA
-545.5mV  -127.7mA   -74.07mA   -183.7mA
163.6mV   29.41mA    16.22mA    43.14mA
490.9mV   72.28mA    38.36mA    108.1mA
872.7mV   98.4mA     48.52mA    154.5mA
2.236V    107.1mA    50.23mA    182.5mA
3.545V    87.14mA    46.38mA    146.2mA
[Pullup]
-1.8V     6.901mA    5.057mA    8.816mA
-1.309V   19.93mA    12.08mA    33.18mA
-1.145V   42.64mA    20.25mA    98.48mA
-981.8mV  102.9mA    40.1mA     161.5mA
-600mV    87.24mA    51.07mA    122.7mA
381.8mV   -45.05mA   -25.09mA   -67.44mA
1.036V    -83.14mA   -45.78mA   -125.9mA
2.291V    -90.12mA   -48.67mA   -136.8mA
2.618V    -88.34mA   -18.52mA   -135.3mA
2.782V    -42.42mA   -13.42mA   -134.2mA
3V        -17.89mA   -10.8mA    -37.28mA
3.545V    -10.46mA   -8.646mA   -14.45mA
[GND_clamp]
-1.8V     -7.151A    -7.205A    -6.863A
-1.182V   -1.844A    -2.309A    -1.461A
-1.145V   -1.557A    -2.041A    -1.171A
-1.109V   -1.281A    -1.782A    -899.6mA
-1.073V   -1.016A    -1.529A    -645.4mA
-1.036V   -759.7mA   -1.281A    -408.5mA
-1V       -537.5mA   -1.048A    -242.1mA
-927.3mV  -181.3mA   -617.3mA   -59.94mA
-818.2mV  -25.1mA    -166.6mA   -34.2mA
-709.1mV  -12.05mA   -22.52mA   -22.82mA
-563.6mV  -2.326mA   -2.107mA   -5.538mA
3.6V      0A         0A         0A
[Ramp]
dV/dt_f  0.9728414/0.1466164n  0.7978847/0.3982133n   1.057727/86.46825p
dV/dt_r   0.947162/0.1777954n  0.7578648/0.4078928n   1.043524/0.1125419n
R_load = 50
[Rising Waveform]
R_fixture = 50
V_fixture = 1.8
V_fixture_min = 1.62
V_fixture_max = 1.89
0s        179.3mV    290.7mV    126.8mV
88ps      179.3mV    290.7mV    331.4mV
242ps     178.6mV    290.7mV    1.67V
308ps     178.7mV    290.7mV    1.852V
418ps     284.1mV    290.7mV    1.884V
704ps     1.563V     290.7mV    1.889V
814ps     1.765V     289mV      1.89V
1.034ns   1.795V     322.8mV    1.89V
1.98ns    1.799V     1.51V      1.89V
2.706ns   1.799V     1.617V     1.89V
[Rising Waveform]
R_fixture = 50
V_fixture = 0
V_fixture_min = 0
V_fixture_max = 0
0s        115.5uV    106.2uV    -3.439mV
132ps     93.42uV    106.5uV    32.2mV
352ps     -4.645mV   105.7uV    1.622V
572ps     35.04mV    86.54uV    1.697V
792ps     1.119V     288.1uV    1.703V
968ps     1.475V     -2.461mV   1.704V
1.958ns   1.534V     69.98mV    1.708V
2.464ns   1.537V     978.5mV    1.709V
8.338ns   1.547V     1.214V     1.713V
143.4ns   1.556V     1.241V     1.716V
[Falling Waveform]
R_fixture = 50
V_fixture = 1.8
V_fixture_min = 1.62
V_fixture_max = 1.89
0s        1.8V       1.62V      1.89V
352ps     1.8V       1.62V      1.802V
528ps     1.8V       1.62V      244.5mV
616ps     1.801V     1.62V      158.8mV
902ps     1.604V     1.62V      132.2mV
1.122ns   353.4mV    1.62V      129.5mV
1.21ns    237.7mV    1.62V      129.1mV
2.046ns   182.4mV    1.493V     128.2mV
2.794ns   180.4mV    363.3mV    128.1mV
5.17ns    179.7mV    294mV      128mV
[Falling Waveform]
R_fixture = 50
V_fixture = 0
V_fixture_min = 0
V_fixture_max = 0
0s        1.556V     1.244V     1.716V
330ps     1.556V     1.244V     1.679V
396ps     1.556V     1.244V     1.323V
484ps     1.556V     1.244V     136.2mV
550ps     1.556V     1.244V     26.45mV
858ps     1.421V     1.244V     2.565mV
1.122ns   36.12mV    1.244V     1.05mV
1.958ns   1.936mV    1.163V     427.4uV
2.552ns   1.117mV    68.73mV    311.2uV
3.872ns   641.7uV    3.404mV    221.3uV
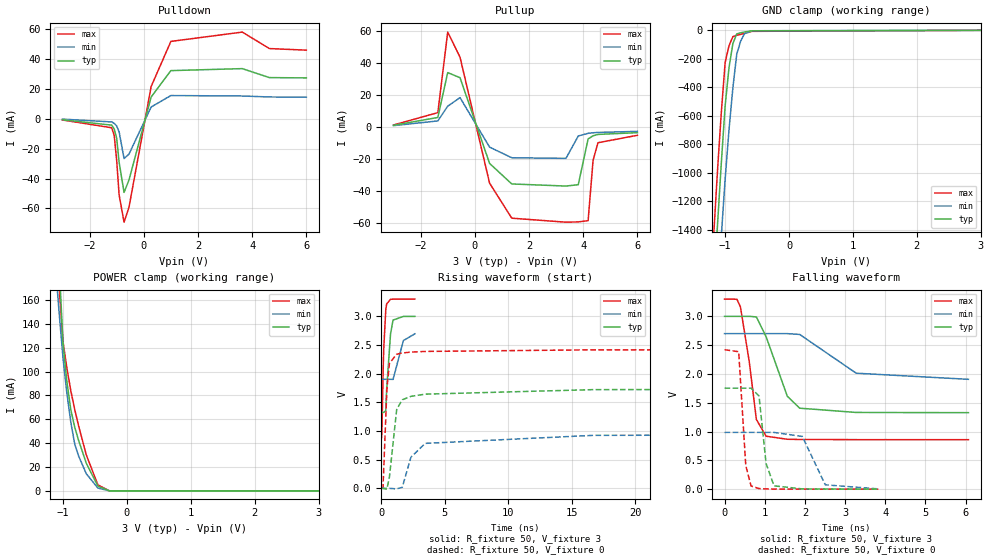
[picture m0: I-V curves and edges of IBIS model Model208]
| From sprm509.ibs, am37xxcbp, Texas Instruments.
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| Model based on original model for BQMMC1833DVHYPBFZLP18_SSCHH
|   Sub model H_SPEEDCTRL0_PUPD0_3
[model]   Model208
|[Input Load]   PI
|[Output Drive] SC0
|Voltage   3V
|Mode   I/O
Model_type   I/O
Polarity   Non-Inverting
Enable   Active-Low
Vinl =  0.9
Vinh =  2.1
Cref =  15pF
Rref =  100.0000M
Vref =  0V
Vmeas =  1.5
C_comp   5.193555p   4.924275p   5.205586p
[Model Spec]
Vinl   0.9   0.81   0.99
Vinh   2.1   1.89   2.31
[Temperature Range]   25   125   -40
[Voltage Range]   3   2.7   3.3
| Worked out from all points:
|   slope of the pulldown table from 0 to 0.45 V, typ, clamps not added: 20.8 ohm
|   slope of the pullup table from 0 to 0.45 V, typ, clamps not added: 22.8 ohm
|   GND clamp passes 1 mA (typ) near -0.51 V on its own axis
|   POWER clamp passes 1 mA (typ) near -0.36 V on its own axis
|   rising waveform, R_fixture 50, V_fixture 3: 20-80 % time 304ps typ, 548ps min, 180ps max; typ from 1.32 V to 3 V
|   rising waveform, R_fixture 50, V_fixture 0: 20-80 % time 549ps typ, 1.53ns min, 266ps max; typ from 0 V to 1.75 V
|   falling waveform, R_fixture 50, V_fixture 3: 20-80 % time 504ps typ, 862ps min, 271ps max; typ from 3 V to 1.33 V
|   falling waveform, R_fixture 50, V_fixture 0: 20-80 % time 166ps typ, 320ps min, 102ps max; typ from 1.75 V to 0.001 V
[POWER_clamp]
-3V       3.885A     1.82A      4.094A
-1.121V   269.1mA    190mA      236.4mA
-1.061V   190mA      149.1mA    170.5mA
-1V       123.1mA    110.9mA    124.8mA
-939.4mV  91.26mA    81.51mA    102.8mA
-878.8mV  68.08mA    57.68mA    84.02mA
-818.2mV  53.58mA    39.46mA    68.44mA
-757.6mV  42.55mA    29.33mA    54.75mA
-636.4mV  23.22mA    14.41mA    30.19mA
-454.5mV  3.998mA    2.395mA    5.042mA
-272.7mV  32.75uA    41.91uA    26.15uA
3V        -85.83nA   -8.891uA   -798.5nA
[Pulldown]
-3V       -605.8uA   -178.5uA   -753.3uA
-1.182V   -4.21mA    -2.052mA   -5.965mA
-1.091V   -6.698mA   -2.971mA   -10.98mA
-1V       -12.89mA   -4.735mA   -27.71mA
-909.1mV  -29.13mA   -8.689mA   -50.98mA
-727.3mV  -49.28mA   -26.6mA    -69.24mA
-545.5mV  -40.99mA   -23.62mA   -59.29mA
272.7mV   14.65mA    7.964mA    21.68mA
1V        32.33mA    15.62mA    51.9mA
3.636V    33.67mA    15.32mA    58.15mA
4.636V    27.65mA    14.67mA    47.11mA
6V        27.45mA    14.53mA    46.04mA
[Pullup]
-3V       909.2uA    688uA      1.095mA
-1.364V   5.79mA     3.639mA    8.81mA
-1V       33.75mA    12.82mA    59.02mA
-545.5mV  30.59mA    18.14mA    43.38mA
545.5mV   -22.87mA   -12.71mA   -35.18mA
1.364V    -35.67mA   -19.33mA   -57.01mA
3.364V    -36.98mA   -19.72mA   -59.51mA
3.818V    -36.13mA   -5.779mA   -59.33mA
4.182V    -7.586mA   -4.088mA   -58.55mA
4.364V    -5.632mA   -3.758mA   -21mA
4.545V    -4.785mA   -3.538mA   -9.97mA
6V        -3.687mA   -2.885mA   -5.329mA
[GND_clamp]
-3V       -17.89A    -17.26A    -17.77A
-1.182V   -1.843A    -2.308A    -1.459A
-1.121V   -1.377A    -1.871A    -995.4mA
-1.061V   -939mA     -1.45A     -584.5mA
-1V       -529.9mA   -1.045A    -225.8mA
-939.4mV  -261.2mA   -697mA     -108mA
-878.8mV  -92.98mA   -404.2mA   -44.13mA
-818.2mV  -25.12mA   -166.6mA   -34.22mA
-757.6mV  -17.48mA   -76.74mA   -28.22mA
-697mV    -11.16mA   -23.3mA    -21.17mA
-575.8mV  -3.096mA   -3.057mA   -6.959mA
3V        955.9nA    83.7uA     1.79uA
[Ramp]
dV/dt_f   1.005582/0.5033976n  0.4794376/0.8727696n   1.464985/0.270019n
dV/dt_r   1.061052/0.5446643n  0.5966165/1.536654n   1.462901/0.2658045n
R_load = 50
[Rising Waveform]
R_fixture = 50
V_fixture = 3
V_fixture_min = 2.7
V_fixture_max = 3.3
0s        1.324V     1.901V     856.9mV
44ps      1.324V     1.901V     945.2mV
154ps     1.324V     1.901V     2.157V
198ps     1.325V     1.901V     2.468V
352ps     1.355V     1.901V     3.117V
418ps     1.719V     1.901V     3.214V
726ps     2.692V     1.901V     3.296V
924ps     2.934V     1.899V     3.298V
1.738ns   2.997V     2.577V     3.299V
2.64ns    2.998V     2.694V     3.3V
[Rising Waveform]
R_fixture = 50
V_fixture = 0
V_fixture_min = 0
V_fixture_max = 0
0s        1.09uV     2.747uV    -1.075mV
132ps     1.915uV    2.726uV    8.129mV
440ps     -14.39mV   3.141uV    1.733V
638ps     197.5mV    -22.64uV   2.179V
1.21ns    1.375V     -9.545mV   2.339V
1.65ns    1.544V     17.45mV    2.36V
2.332ns   1.604V     542.5mV    2.375V
3.454ns   1.642V     784.1mV    2.387V
16.7ns    1.721V     923.9mV    2.415V
162.4ns   1.753V     980.3mV    2.421V
[Falling Waveform]
R_fixture = 50
V_fixture = 3
V_fixture_min = 2.7
V_fixture_max = 3.3
0s        3V         2.7V       3.3V
308ps     3V         2.7V       3.297V
396ps     3V         2.7V       3.163V
616ps     3V         2.7V       2.209V
792ps     2.99V      2.7V       1.211V
1.034ns   2.648V     2.7V       919.7mV
1.562ns   1.614V     2.7V       866.7mV
1.87ns    1.406V     2.686V     862.8mV
3.278ns   1.332V     2.013V     860.2mV
6.072ns   1.328V     1.907V     859.3mV
[Falling Waveform]
R_fixture = 50
V_fixture = 0
V_fixture_min = 0
V_fixture_max = 0
0s        1.754V     985.7mV    2.421V
352ps     1.754V     985.7mV    2.386V
528ps     1.754V     985.7mV    410.7mV
660ps     1.754V     985.7mV    55.53mV
858ps     1.618V     985.7mV    10.59mV
1.034ns   445.8mV    985.8mV    4.454mV
1.232ns   58.35mV    985.7mV    2.441mV
1.936ns   5.087mV    915.6mV    975.8uV
2.508ns   2.606mV    75.57mV    671.4uV
3.828ns   1.405mV    5.52mV     387.5uV
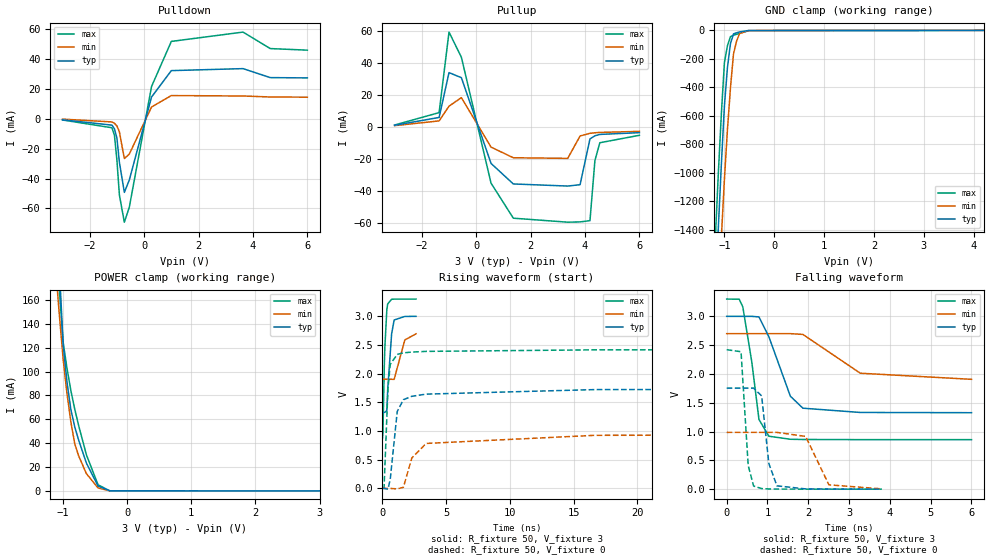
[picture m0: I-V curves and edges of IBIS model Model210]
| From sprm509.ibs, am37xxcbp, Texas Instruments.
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| Model based on original model for BQMMC1833DVHYPBFZLP18_SSCHH
|   Sub model CHH_SPEEDCTRL0_PU1_3
[model]   Model210
|[Input Load]   PU
|[Output Drive] SC0
|Voltage   3V
|Mode   I/O
Model_type   I/O
Polarity   Non-Inverting
Enable   Active-Low
Vinl =  0.9
Vinh =  2.1
Cref =  15pF
Rref =  100.0000M
Vref =  0V
Vmeas =  1.5
C_comp   5.193555p   4.924275p   5.205586p
[Model Spec]
Vinl   0.9   0.81   0.99
Vinh   2.1   1.89   2.31
[Temperature Range]   25   125   -40
[Voltage Range]   3   2.7   3.3
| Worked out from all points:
|   slope of the pulldown table from 0 to 0.45 V, typ, clamps not added: 20.8 ohm
|   slope of the pullup table from 0 to 0.45 V, typ, clamps not added: 22.8 ohm
|   GND clamp passes 1 mA (typ) near -0.50 V on its own axis
|   POWER clamp passes 1 mA (typ) near -0.36 V on its own axis
|   rising waveform, R_fixture 50, V_fixture 3: 20-80 % time 304ps typ, 547ps min, 180ps max; typ from 1.32 V to 3 V
|   rising waveform, R_fixture 50, V_fixture 0: 20-80 % time 548ps typ, 1.58ns min, 266ps max; typ from 0.001 V to 1.75 V
|   falling waveform, R_fixture 50, V_fixture 3: 20-80 % time 504ps typ, 861ps min, 271ps max; typ from 3 V to 1.33 V
|   falling waveform, R_fixture 50, V_fixture 0: 20-80 % time 166ps typ, 320ps min, 102ps max; typ from 1.75 V to 0.002 V
[POWER_clamp]
-3V       3.885A     1.82A      4.094A
-1.121V   269.1mA    190mA      236.4mA
-1.061V   190mA      149.1mA    170.5mA
-1V       123.1mA    110.9mA    124.8mA
-939.4mV  91.26mA    81.51mA    102.8mA
-878.8mV  68.09mA    57.69mA    84.02mA
-818.2mV  53.59mA    39.47mA    68.44mA
-757.6mV  42.55mA    29.33mA    54.75mA
-636.4mV  23.23mA    14.42mA    30.2mA
-454.5mV  4.003mA    2.397mA    5.048mA
-272.7mV  36.26uA    43.92uA    31uA
3V        -42.44uA   -34.26uA   -57.89uA
[Pulldown]
-3V       -605.8uA   -178.5uA   -753.3uA
-1.182V   -4.21mA    -2.052mA   -5.965mA
-1.091V   -6.698mA   -2.971mA   -10.98mA
-1V       -12.89mA   -4.735mA   -27.71mA
-909.1mV  -29.13mA   -8.689mA   -50.98mA
-727.3mV  -49.28mA   -26.6mA    -69.24mA
-545.5mV  -40.99mA   -23.62mA   -59.29mA
272.7mV   14.65mA    7.964mA    21.68mA
1V        32.33mA    15.62mA    51.9mA
3.636V    33.67mA    15.32mA    58.15mA
4.636V    27.65mA    14.67mA    47.11mA
6V        27.45mA    14.53mA    46.04mA
[Pullup]
-3V       909.2uA    688uA      1.095mA
-1.364V   5.79mA     3.639mA    8.81mA
-1V       33.75mA    12.82mA    59.02mA
-545.5mV  30.59mA    18.14mA    43.38mA
545.5mV   -22.87mA   -12.71mA   -35.18mA
1.364V    -35.67mA   -19.33mA   -57.01mA
3.364V    -36.98mA   -19.72mA   -59.51mA
3.818V    -36.13mA   -5.779mA   -59.33mA
4.182V    -7.586mA   -4.088mA   -58.55mA
4.364V    -5.632mA   -3.758mA   -21mA
4.545V    -4.785mA   -3.538mA   -9.97mA
6V        -3.687mA   -2.885mA   -5.329mA
[GND_clamp]
-3V       -17.89A    -17.26A    -17.77A
-1.182V   -1.843A    -2.308A    -1.459A
-1.121V   -1.377A    -1.871A    -995.4mA
-1.061V   -939mA     -1.45A     -584.5mA
-1V       -529.9mA   -1.045A    -225.8mA
-939.4mV  -261.3mA   -697mA     -108mA
-878.8mV  -93mA      -404.2mA   -44.16mA
-818.2mV  -25.15mA   -166.6mA   -34.27mA
-757.6mV  -17.52mA   -76.75mA   -28.28mA
-697mV    -11.21mA   -23.31mA   -21.24mA
-515.2mV  -1.164mA   -1.07mA    -2.845mA
6V        0A         0A         0A
[Ramp]
dV/dt_f   1.004934/0.5029209n  0.4792428/0.8719898n   1.464391/0.2699111n
dV/dt_r   1.060914/0.5426693n   0.596633/1.529918n   1.462497/0.2651444n
R_load = 50
[Rising Waveform]
R_fixture = 50
V_fixture = 3
V_fixture_min = 2.7
V_fixture_max = 3.3
0s        1.325V     1.902V     857.9mV
44ps      1.326V     1.902V     946.3mV
154ps     1.325V     1.902V     2.159V
198ps     1.326V     1.902V     2.469V
352ps     1.357V     1.902V     3.118V
418ps     1.72V      1.902V     3.215V
726ps     2.693V     1.902V     3.296V
924ps     2.935V     1.9V       3.299V
1.76ns    2.997V     2.587V     3.3V
2.64ns    2.999V     2.694V     3.3V
[Rising Waveform]
R_fixture = 50
V_fixture = 0
V_fixture_min = 0
V_fixture_max = 0
0s        506.8uV    416.4uV    -522.2uV
132ps     507.6uV    416.4uV    9.491mV
440ps     -13.55mV   416.8uV    1.736V
616ps     154.4mV    396.1uV    2.16V
1.166ns   1.34V      -9.575mV   2.336V
1.65ns    1.546V     18.5mV     2.362V
2.31ns    1.605V     530.7mV    2.376V
3.432ns   1.643V     783.6mV    2.388V
16.68ns   1.722V     925mV      2.415V
162.3ns   1.754V     981mV      2.421V
[Falling Waveform]
R_fixture = 50
V_fixture = 3
V_fixture_min = 2.7
V_fixture_max = 3.3
0s        3V         2.7V       3.3V
308ps     3V         2.7V       3.297V
396ps     3V         2.7V       3.163V
616ps     3V         2.7V       2.209V
792ps     2.99V      2.7V       1.211V
1.034ns   2.648V     2.7V       919.7mV
1.562ns   1.614V     2.7V       866.8mV
1.87ns    1.406V     2.686V     862.8mV
3.278ns   1.332V     2.013V     860.6mV
6.006ns   1.328V     1.907V     860.1mV
[Falling Waveform]
R_fixture = 50
V_fixture = 0
V_fixture_min = 0
V_fixture_max = 0
0s        1.755V     986.4mV    2.421V
352ps     1.755V     986.4mV    2.386V
528ps     1.755V     986.4mV    411.1mV
660ps     1.755V     986.4mV    55.71mV
858ps     1.619V     986.4mV    10.73mV
1.034ns   446.3mV    986.4mV    4.592mV
1.232ns   58.61mV    986.4mV    2.584mV
1.936ns   5.288mV    916.4mV    1.173mV
2.508ns   2.806mV    75.91mV    936.2uV
3.806ns   1.623mV    5.912mV    758uV
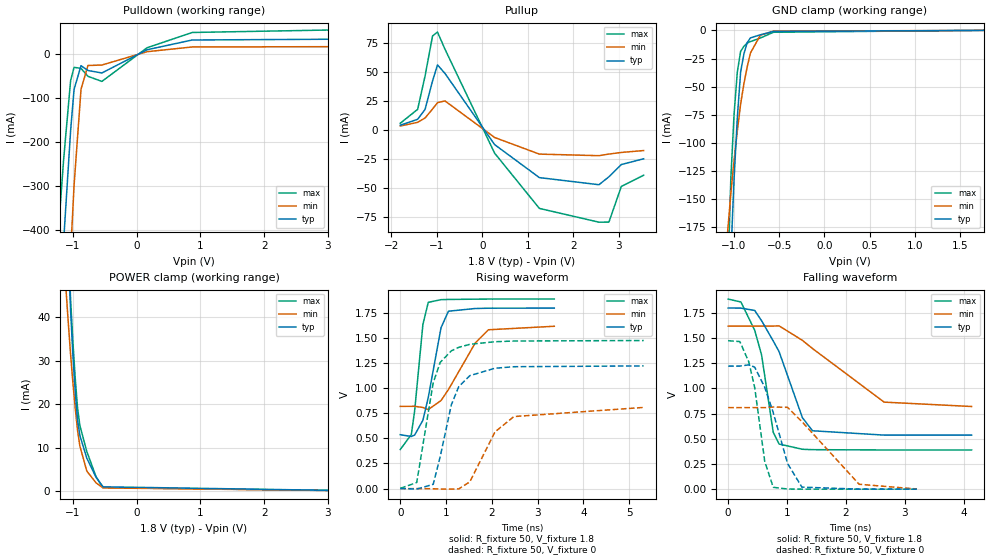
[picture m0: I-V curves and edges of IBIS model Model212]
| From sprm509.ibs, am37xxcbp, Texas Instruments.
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| Model based on original model for BQ18OMAPSMART2HYFBPB_SSBHV
|   Sub model T2HYFBPB_V_1_PD1_1P8
[model]   Model212
|[Input Load]   PD
|[Output Drive] LB1
|Voltage   1.8V
|Mode   I/O
Model_type   I/O
Polarity   Non-Inverting
Enable   Active-Low
Vinl =  0.63
Vinh =  1.17
Cref =  15pF
Rref =  100.0000M
Vref =  0V
Vmeas =  0.9
C_comp   1.528652p   1.368776p   1.69933p
[Model Spec]
Vinl   0.63   0.567   0.6615
Vinh   1.17   1.053   1.2285
[Temperature Range]   25   125   -40
[Voltage Range]   1.8   1.62   1.89
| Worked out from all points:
|   slope of the pulldown table from 0 to 0.27 V, typ, clamps not added: 17.8 ohm
|   slope of the pullup table from 0 to 0.27 V, typ, clamps not added: 21.5 ohm
|   GND clamp passes 1 mA (typ) near -0.58 V on its own axis
|   POWER clamp passes 1 mA (typ) near -0.53 V on its own axis
|   rising waveform, R_fixture 50, V_fixture 1.8: 20-80 % time 307ps typ, 606ps min, 190ps max; typ from 0.537 V to 1.8 V
|   rising waveform, R_fixture 50, V_fixture 0: 20-80 % time 391ps typ, 585ps min, 350ps max; typ from 0 V to 1.22 V
|   falling waveform, R_fixture 50, V_fixture 1.8: 20-80 % time 521ps typ, 1.06ns min, 282ps max; typ from 1.8 V to 0.537 V
|   falling waveform, R_fixture 50, V_fixture 0: 20-80 % time 373ps typ, 697ps min, 225ps max; typ from 1.22 V to 0 V
[POWER_clamp]
-1.8V     449.2mA    229.3mA    499.9mA
-1.109V   70.08mA    46.67mA    71.87mA
-1.073V   55.21mA    38.88mA    57.08mA
-1.036V   41.54mA    31.43mA    44.06mA
-1V       31.27mA    24.96mA    34.34mA
-963.6mV  22.88mA    19.13mA    26.04mA
-927.3mV  16.35mA    13.96mA    19.14mA
-890.9mV  12.8mA     10.36mA    15.1mA
-781.8mV  7.558mA    4.572mA    9.086mA
-636.4mV  3.123mA    1.858mA    3.262mA
-527.3mV  948.5uA    698.4uA    767.3uA
3.6V      0A         0A         0A
[Pulldown]
-1.8V     -1.866A    -2.926A    -1.473A
-1.255V   -690.3mA   -1.165A    -458.8mA
-1.2V     -556.9mA   -981.3mA   -347.5mA
-1.145V   -424mA     -799.3mA   -238.7mA
-1.036V   -174.1mA   -452.5mA   -60.3mA
-981.8mV  -80.13mA   -298.3mA   -30.04mA
-872.7mV  -26.27mA   -79.78mA   -32.44mA
-763.6mV  -37.27mA   -25.87mA   -50.47mA
-545.5mV  -42.85mA   -24.82mA   -62.02mA
163.6mV   9.905mA    5.464mA    14.49mA
872.7mV   32.06mA    16.22mA    49.12mA
3.545V    34.18mA    16.99mA    56.07mA
[Pullup]
-1.8V     4.02mA     3.353mA    5.71mA
-1.418V   9.153mA    6.524mA    17.71mA
-1.255V   17.65mA    10.28mA    46.46mA
-1.091V   42.13mA    17.99mA    80.98mA
-981.8mV  56.04mA    23.5mA     84.34mA
-818.2mV  48.72mA    25.01mA    69.63mA
272.7mV   -12.68mA   -6.535mA   -20.08mA
1.255V    -41.13mA   -20.87mA   -67.69mA
2.564V    -47.26mA   -22.22mA   -79.57mA
2.782V    -40.42mA   -20.82mA   -79.47mA
3.055V    -29.85mA   -19.43mA   -48.72mA
3.545V    -24.9mA    -17.8mA    -39.06mA
[GND_clamp]
-1.8V     -3.26A     -1.496A    -3.636A
-1.073V   -295.4mA   -181.3mA   -234.2mA
-1.036V   -202.2mA   -145.8mA   -132.5mA
-1V       -132.7mA   -116.1mA   -74.87mA
-963.6mV  -77.6mA    -89.37mA   -36.88mA
-927.3mV  -36.98mA   -65.53mA   -18.59mA
-890.9mV  -20.91mA   -47.52mA   -14.09mA
-854.5mV  -10.79mA   -32.36mA   -11.18mA
-818.2mV  -6.606mA   -20.04mA   -9.859mA
-709.1mV  -3.829mA   -4.176mA   -6.715mA
-563.6mV  -831uA     -577.4uA   -1.567mA
1.764V    97.78uA    55.24uA    156.3uA
[Ramp]
dV/dt_f  0.7586966/0.5222623n  0.4816935/1.067627n   0.899907/0.2817252n
dV/dt_r  0.7382846/0.3912875n   0.489745/0.5877854n  0.8904603/0.3508976n
R_load = 50
[Rising Waveform]
R_fixture = 50
V_fixture = 1.8
V_fixture_min = 1.62
V_fixture_max = 1.89
0s        536.6mV    819.2mV    388.6mV
243ps     519mV      819.4mV    539.1mV
315ps     533.2mV    819.9mV    775.9mV
495ps     681mV      807.8mV    1.634V
612ps     906.5mV    787.2mV    1.855V
891ps     1.602V     877mV      1.882V
1.053ns   1.767V     986mV      1.884V
1.638ns   1.794V     1.45V      1.887V
1.926ns   1.797V     1.582V     1.888V
3.366ns   1.798V     1.617V     1.888V
[Rising Waveform]
R_fixture = 50
V_fixture = 0
V_fixture_min = 0
V_fixture_max = 0
0s        17.4uV     -10.1uV    1.88mV
360ps     -4.988mV   -121.7uV   60.32mV
720ps     42.18mV    -1.814mV   1.054V
873ps     317.5mV    -4.323mV   1.257V
1.116ns   834.4mV    -5.887mV   1.372V
1.278ns   1.015V     -3.245mV   1.407V
1.521ns   1.125V     67.22mV    1.437V
2.07ns    1.199V     564.3mV    1.463V
2.484ns   1.214V     717.4mV    1.47V
5.319ns   1.222V     808.5mV    1.475V
[Falling Waveform]
R_fixture = 50
V_fixture = 1.8
V_fixture_min = 1.62
V_fixture_max = 1.89
0s        1.799V     1.619V     1.888V
216ps     1.798V     1.619V     1.859V
450ps     1.775V     1.619V     1.579V
567ps     1.673V     1.619V     1.334V
765ps     1.472V     1.62V      565.1mV
864ps     1.366V     1.622V     448.3mV
1.26ns    710.1mV    1.478V     396.2mV
1.431ns   580mV      1.397V     392.3mV
2.646ns   536.9mV    864.5mV    389.3mV
4.131ns   536.6mV    821mV      389.3mV
[Falling Waveform]
R_fixture = 50
V_fixture = 0
V_fixture_min = 0
V_fixture_max = 0
0s        1.222V     810.3mV    1.474V
198ps     1.222V     810.1mV    1.466V
351ps     1.235V     810.3mV    1.263V
450ps     1.212V     810.3mV    1.011V
621ps     1.011V     809.8mV    275.1mV
765ps     760.4mV    815.8mV    18.49mV
1.008ns   255.2mV    812.6mV    1.544mV
1.251ns   20.4mV     671mV      174.5uV
2.223ns   102.9uV    48.58mV    1.444uV
3.204ns   34.35uV    1.646mV    334.4nV
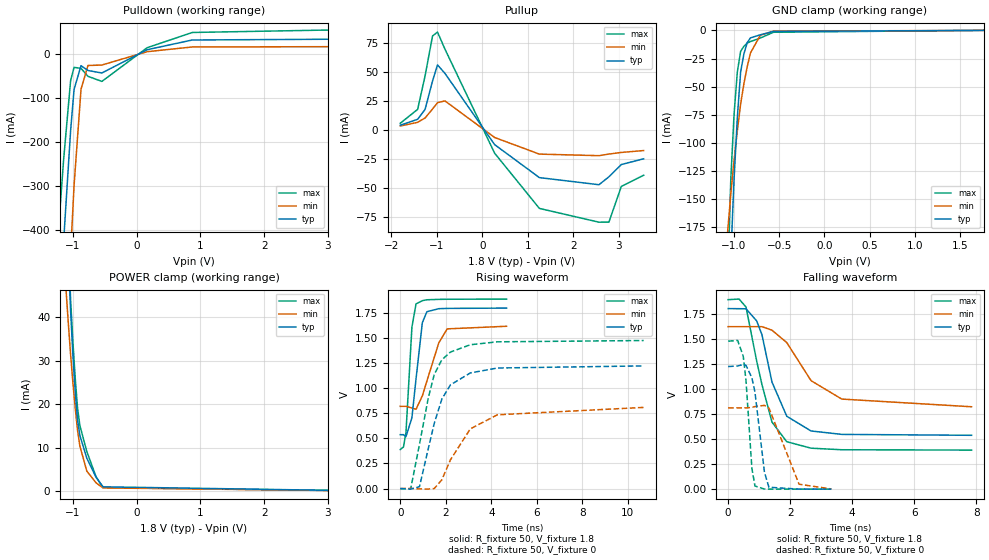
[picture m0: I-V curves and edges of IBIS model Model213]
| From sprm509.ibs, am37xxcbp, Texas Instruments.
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| Model based on original model for BQ18OMAPSMART2HYFBPB_SSBHV
|   Sub model T2HYFBPB_V_0_PD1_1P8
[model]   Model213
|[Input Load]   PD
|[Output Drive] LB0
|Voltage   1.8V
|Mode   I/O
Model_type   I/O
Polarity   Non-Inverting
Enable   Active-Low
Vinl =  0.63
Vinh =  1.17
Cref =  15pF
Rref =  100.0000M
Vref =  0V
Vmeas =  0.9
C_comp   1.528652p   1.368776p   1.69933p
[Model Spec]
Vinl   0.63   0.567   0.6615
Vinh   1.17   1.053   1.2285
[Temperature Range]   25   125   -40
[Voltage Range]   1.8   1.62   1.89
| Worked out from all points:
|   slope of the pulldown table from 0 to 0.27 V, typ, clamps not added: 17.8 ohm
|   slope of the pullup table from 0 to 0.27 V, typ, clamps not added: 21.5 ohm
|   GND clamp passes 1 mA (typ) near -0.58 V on its own axis
|   POWER clamp passes 1 mA (typ) near -0.53 V on its own axis
|   rising waveform, R_fixture 50, V_fixture 1.8: 20-80 % time 341ps typ, 657ps min, 212ps max; typ from 0.537 V to 1.8 V
|   rising waveform, R_fixture 50, V_fixture 0: 20-80 % time 932ps typ, 1.39ns min, 830ps max; typ from 0 V to 1.22 V
|   falling waveform, R_fixture 50, V_fixture 1.8: 20-80 % time 683ps typ, 1.19ns min, 664ps max; typ from 1.8 V to 0.537 V
|   falling waveform, R_fixture 50, V_fixture 0: 20-80 % time 277ps typ, 475ps min, 194ps max; typ from 1.22 V to 0 V
[POWER_clamp]
-1.8V     449.2mA    229.3mA    499.9mA
-1.109V   70.08mA    46.67mA    71.87mA
-1.073V   55.21mA    38.88mA    57.08mA
-1.036V   41.54mA    31.43mA    44.06mA
-1V       31.27mA    24.96mA    34.34mA
-963.6mV  22.88mA    19.13mA    26.04mA
-927.3mV  16.35mA    13.96mA    19.14mA
-890.9mV  12.8mA     10.36mA    15.1mA
-781.8mV  7.558mA    4.572mA    9.086mA
-636.4mV  3.123mA    1.858mA    3.262mA
-527.3mV  948.5uA    698.4uA    767.3uA
3.6V      0A         0A         0A
[Pulldown]
-1.8V     -1.866A    -2.926A    -1.473A
-1.255V   -690.3mA   -1.165A    -458.8mA
-1.2V     -556.9mA   -981.3mA   -347.5mA
-1.145V   -424mA     -799.3mA   -238.7mA
-1.036V   -174.1mA   -452.5mA   -60.3mA
-981.8mV  -80.13mA   -298.3mA   -30.04mA
-872.7mV  -26.27mA   -79.78mA   -32.44mA
-763.6mV  -37.27mA   -25.87mA   -50.47mA
-545.5mV  -42.85mA   -24.82mA   -62.02mA
163.6mV   9.905mA    5.464mA    14.49mA
872.7mV   32.06mA    16.22mA    49.12mA
3.545V    34.18mA    16.99mA    56.07mA
[Pullup]
-1.8V     4.02mA     3.353mA    5.71mA
-1.418V   9.153mA    6.524mA    17.71mA
-1.255V   17.65mA    10.28mA    46.46mA
-1.091V   42.13mA    17.99mA    80.98mA
-981.8mV  56.04mA    23.5mA     84.34mA
-818.2mV  48.72mA    25.01mA    69.63mA
272.7mV   -12.68mA   -6.535mA   -20.08mA
1.255V    -41.13mA   -20.87mA   -67.69mA
2.564V    -47.26mA   -22.22mA   -79.57mA
2.782V    -40.42mA   -20.82mA   -79.47mA
3.055V    -29.85mA   -19.43mA   -48.72mA
3.545V    -24.9mA    -17.8mA    -39.06mA
[GND_clamp]
-1.8V     -3.26A     -1.496A    -3.636A
-1.073V   -295.4mA   -181.3mA   -234.2mA
-1.036V   -202.2mA   -145.8mA   -132.5mA
-1V       -132.7mA   -116.1mA   -74.87mA
-963.6mV  -77.6mA    -89.37mA   -36.88mA
-927.3mV  -36.98mA   -65.53mA   -18.59mA
-890.9mV  -20.91mA   -47.52mA   -14.09mA
-854.5mV  -10.79mA   -32.36mA   -11.18mA
-818.2mV  -6.606mA   -20.04mA   -9.859mA
-709.1mV  -3.829mA   -4.176mA   -6.715mA
-563.6mV  -831uA     -577.4uA   -1.567mA
1.764V    97.78uA    55.24uA    156.3uA
[Ramp]
dV/dt_f  0.7588313/0.682473n   0.4801501/1.194253n   0.9050824/0.6668557n
dV/dt_r   0.737817/0.9326596n  0.4892113/1.401153n   0.8927853/0.8324333n
R_load = 50
[Rising Waveform]
R_fixture = 50
V_fixture = 1.8
V_fixture_min = 1.62
V_fixture_max = 1.89
0s        536.6mV    819.2mV    388.5mV
144ps     536.9mV    819.3mV    414.8mV
252ps     517.2mV    819.4mV    559.6mV
513ps     705.5mV    802.7mV    1.609V
693ps     1.093V     789.4mV    1.84V
972ps     1.654V     924.1mV    1.872V
1.17ns    1.762V     1.071V     1.881V
1.692ns   1.792V     1.451V     1.885V
2.061ns   1.795V     1.591V     1.886V
4.671ns   1.798V     1.617V     1.888V
[Rising Waveform]
R_fixture = 50
V_fixture = 0
V_fixture_min = 0
V_fixture_max = 0
0s        -44.32uV   20.23uV    -467.5uV
459ps     -6.124mV   1.512mV    -3.563mV
846ps     18.84mV    -3.518mV   442.5mV
1.233ns   399.3mV    -4.949mV   903.7mV
1.494ns   649.9mV    152uV      1.137V
1.827ns   891.2mV    87.64mV    1.283V
2.205ns   1.033V     286.4mV    1.36V
3.078ns   1.152V     595.1mV    1.433V
4.266ns   1.201V     734.9mV    1.462V
10.69ns   1.222V     808.5mV    1.475V
[Falling Waveform]
R_fixture = 50
V_fixture = 1.8
V_fixture_min = 1.62
V_fixture_max = 1.89
0s        1.799V     1.619V     1.888V
351ps     1.798V     1.619V     1.894V
576ps     1.797V     1.619V     1.815V
918ps     1.677V     1.619V     1.279V
1.089ns   1.54V      1.619V     1.043V
1.413ns   1.067V     1.584V     668.3mV
1.89ns    726.3mV    1.46V      472.7mV
2.673ns   579.7mV    1.081V     408.4mV
3.663ns   545.7mV    897.6mV    392.8mV
7.848ns   536.7mV    821mV      389.3mV
[Falling Waveform]
R_fixture = 50
V_fixture = 0
V_fixture_min = 0
V_fixture_max = 0
0s        1.222V     810.3mV    1.474V
306ps     1.227V     810.3mV    1.482V
486ps     1.243V     810.2mV    1.325V
576ps     1.233V     810mV      1.078V
765ps     1.109V     814.4mV    208.9mV
864ps     967.8mV    823.3mV    31.57mV
1.17ns    169.1mV    834.6mV    1.482mV
1.314ns   19.19mV    808.8mV    939.1uV
2.286ns   469.7uV    49.4mV     226.8uV
3.33ns    136.6uV    1.684mV    59.46uV
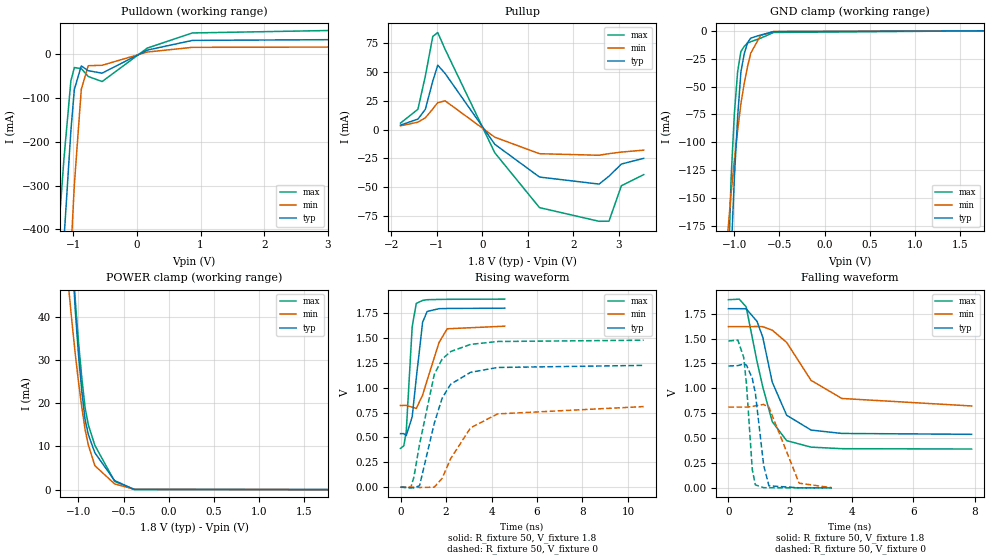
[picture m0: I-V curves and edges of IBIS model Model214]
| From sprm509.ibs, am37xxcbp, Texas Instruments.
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| Model based on original model for BQ18OMAPSMART2HYFBPB_SSBHV
|   Sub model HYFBPB_V_0_PUPD0_1P8
[model]   Model214
|[Input Load]   PI
|[Output Drive] LB0
|Voltage   1.8V
|Mode   I/O
Model_type   I/O
Polarity   Non-Inverting
Enable   Active-Low
Vinl =  0.63
Vinh =  1.17
Cref =  15pF
Rref =  100.0000M
Vref =  0V
Vmeas =  0.9
C_comp   1.528652p   1.368776p   1.69933p
[Model Spec]
Vinl   0.63   0.567   0.6615
Vinh   1.17   1.053   1.2285
[Temperature Range]   25   125   -40
[Voltage Range]   1.8   1.62   1.89
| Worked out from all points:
|   slope of the pulldown table from 0 to 0.27 V, typ, clamps not added: 17.8 ohm
|   slope of the pullup table from 0 to 0.27 V, typ, clamps not added: 21.5 ohm
|   GND clamp passes 1 mA (typ) near -0.58 V on its own axis
|   POWER clamp passes 1 mA (typ) near -0.54 V on its own axis
|   rising waveform, R_fixture 50, V_fixture 1.8: 20-80 % time 340ps typ, 655ps min, 211ps max; typ from 0.538 V to 1.8 V
|   rising waveform, R_fixture 50, V_fixture 0: 20-80 % time 930ps typ, 1.39ns min, 827ps max; typ from 0 V to 1.22 V
|   falling waveform, R_fixture 50, V_fixture 1.8: 20-80 % time 686ps typ, 1.19ns min, 666ps max; typ from 1.8 V to 0.538 V
|   falling waveform, R_fixture 50, V_fixture 0: 20-80 % time 277ps typ, 476ps min, 196ps max; typ from 1.22 V to 0 V
[POWER_clamp]
-1.8V     449.2mA    229.3mA    499.9mA
-1.109V   70.03mA    46.65mA    71.76mA
-1.073V   55.15mA    38.86mA    56.96mA
-1.036V   41.47mA    31.41mA    43.93mA
-1V       31.2mA     24.93mA    34.21mA
-963.6mV  22.8mA     19.1mA     25.91mA
-927.3mV  16.27mA    13.92mA    19.01mA
-890.9mV  12.72mA    10.32mA    14.97mA
-818.2mV  8.506mA    5.529mA    10.22mA
-600mV    2.086mA    1.321mA    1.925mA
-381.8mV  46uA       75.05uA    15.45uA
1.764V    -1.701nA   -102nA     -1.875nA
[Pulldown]
-1.8V     -1.866A    -2.926A    -1.473A
-1.255V   -690.3mA   -1.165A    -458.8mA
-1.2V     -556.9mA   -981.3mA   -347.5mA
-1.145V   -424mA     -799.3mA   -238.7mA
-1.036V   -174.1mA   -452.5mA   -60.31mA
-981.8mV  -80.13mA   -298.3mA   -30.04mA
-872.7mV  -26.27mA   -79.78mA   -32.44mA
-763.6mV  -37.26mA   -25.87mA   -50.47mA
-545.5mV  -42.85mA   -24.82mA   -62.02mA
163.6mV   9.905mA    5.464mA    14.49mA
872.7mV   32.06mA    16.22mA    49.12mA
3.545V    34.18mA    16.99mA    56.07mA
[Pullup]
-1.8V     4.02mA     3.353mA    5.71mA
-1.418V   9.153mA    6.524mA    17.71mA
-1.255V   17.65mA    10.28mA    46.45mA
-1.091V   42.12mA    17.99mA    80.97mA
-981.8mV  56.04mA    23.5mA     84.34mA
-818.2mV  48.72mA    25.01mA    69.63mA
272.7mV   -12.68mA   -6.535mA   -20.08mA
1.255V    -41.13mA   -20.87mA   -67.69mA
2.564V    -47.26mA   -22.22mA   -79.57mA
2.782V    -40.42mA   -20.82mA   -79.47mA
3.055V    -29.85mA   -19.43mA   -48.72mA
3.545V    -24.9mA    -17.8mA    -39.06mA
[GND_clamp]
-1.8V     -3.26A     -1.496A    -3.636A
-1.073V   -295.4mA   -181.3mA   -234.2mA
-1.036V   -202.1mA   -145.8mA   -132.5mA
-1V       -132.6mA   -116.1mA   -74.83mA
-963.6mV  -77.56mA   -89.36mA   -36.83mA
-927.3mV  -36.94mA   -65.52mA   -18.53mA
-890.9mV  -20.86mA   -47.5mA    -14.02mA
-854.5mV  -10.73mA   -32.34mA   -11.09mA
-818.2mV  -6.545mA   -20.02mA   -9.764mA
-709.1mV  -3.764mA   -4.146mA   -6.62mA
-563.6mV  -769uA     -544.8uA   -1.476mA
1.764V    -87.87pA   812.3nA    3.194nA
[Ramp]
dV/dt_f  0.7589354/0.6852628n  0.4797727/1.196549n   0.905523/0.668645n
dV/dt_r  0.7388721/0.9306993n  0.4900101/1.400848n   0.8939264/0.8296474n
R_load = 50
[Rising Waveform]
R_fixture = 50
V_fixture = 1.8
V_fixture_min = 1.62
V_fixture_max = 1.89
0s        537.8mV    821mV      389.4mV
144ps     538mV      821.1mV    415.8mV
252ps     518.3mV    821.2mV    561.2mV
513ps     707.4mV    804.4mV    1.614V
693ps     1.096V     791.1mV    1.847V
972ps     1.658V     926.1mV    1.877V
1.17ns    1.766V     1.074V     1.884V
1.692ns   1.794V     1.453V     1.887V
2.052ns   1.796V     1.592V     1.888V
4.581ns   1.799V     1.618V     1.89V
[Rising Waveform]
R_fixture = 50
V_fixture = 0
V_fixture_min = 0
V_fixture_max = 0
0s        -44.37uV   20.2uV     -466.7uV
450ps     -5.989mV   1.503mV    -6.457mV
585ps     -7.13mV    -36.81uV   98.21mV
837ps     14.58mV    -3.418mV   431.9mV
1.485ns   643.4mV    -496.1uV   1.134V
1.827ns   893.2mV    87.66mV    1.286V
2.205ns   1.035V     286.6mV    1.363V
3.078ns   1.154V     596mV      1.435V
4.266ns   1.203V     736.1mV    1.464V
10.69ns   1.224V     809.9mV    1.477V
[Falling Waveform]
R_fixture = 50
V_fixture = 1.8
V_fixture_min = 1.62
V_fixture_max = 1.89
0s        1.8V       1.62V      1.89V
351ps     1.8V       1.62V      1.896V
576ps     1.799V     1.62V      1.818V
927ps     1.673V     1.621V     1.271V
1.116ns   1.512V     1.619V     1.012V
1.422ns   1.062V     1.584V     664.8mV
1.89ns    729.4mV    1.461V     474.4mV
2.682ns   580.7mV    1.08V      409.1mV
3.681ns   546.7mV    898mV      393.6mV
7.893ns   537.9mV    822.7mV    390.2mV
[Falling Waveform]
R_fixture = 50
V_fixture = 0
V_fixture_min = 0
V_fixture_max = 0
0s        1.224V     811.6mV    1.476V
306ps     1.228V     811.6mV    1.484V
495ps     1.245V     811.5mV    1.311V
585ps     1.233V     811.3mV    1.045V
774ps     1.101V     816.6mV    184.3mV
873ps     953.5mV    825.3mV    30.21mV
1.143ns   227.2mV    837.7mV    2.026mV
1.314ns   20.4mV     810.1mV    1.045mV
2.295ns   496.4uV    46.69mV    224.8uV
3.357ns   135.6uV    1.675mV    57.44uV
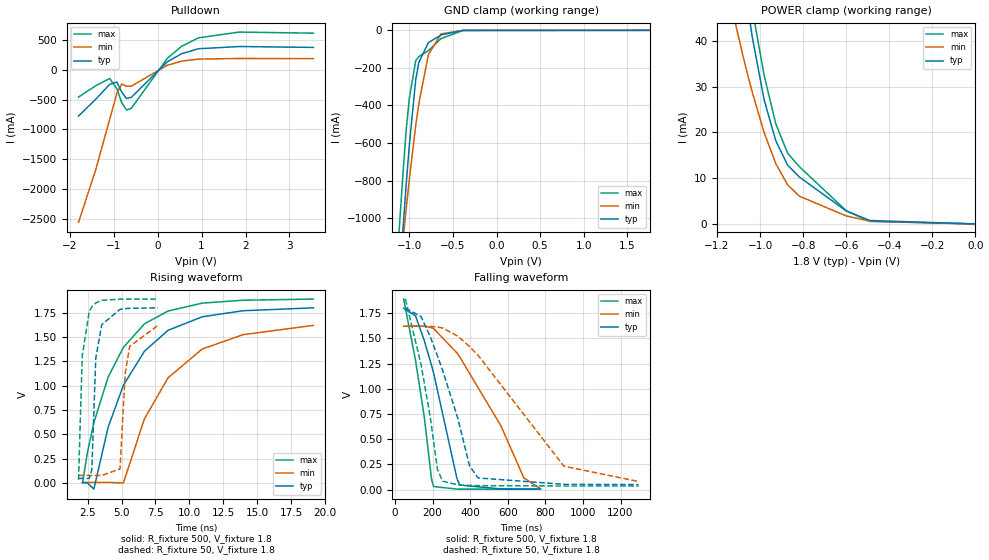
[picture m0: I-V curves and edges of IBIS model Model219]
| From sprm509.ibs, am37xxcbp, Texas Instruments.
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| Model based on original model for BQOMAPI2CHYFBPBRES_SSBHH
|   Sub model BQOMAPI2CHYRES_STD_POFF_00_1P8
[model]   Model219
|[Input Load]   PI
|[Output Drive] LB00
|Voltage   1.8V
|Mode   I/O_OPEN_DRAIN
Model_type   I/O_open_drain
Polarity   Non-Inverting
Enable   Active-Low
Vinl =  0.567
Vinh =  1.323
Cref =  400.0000PF
Rref =  500.0000
Vref =  1.8V
Vmeas =  0.9
C_comp   3.85558p   3.723112p   3.857218p
[Model Spec]
Vinl   0.567   0.567   0.567
Vinh   1.323   1.323   1.323
[Temperature Range]   25   125   -40
[Voltage Range]   1.8   1.62   1.89
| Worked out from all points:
|   slope of the pulldown table from 0 to 0.27 V, typ, clamps not added: 1.71 ohm
|   GND clamp passes 1 mA (typ) near -0.44 V on its own axis
|   POWER clamp passes 1 mA (typ) near -0.51 V on its own axis
|   rising waveform, R_fixture 500, V_fixture 1.8: 20-80 % time 3.64ns typ, 4.19ns min, 3.19ns max; typ from 0.005 V to 1.8 V
|   rising waveform, R_fixture 50, V_fixture 1.8: 20-80 % time 373ps typ, 410ps min, 341ps max; typ from 0.049 V to 1.8 V
|   falling waveform, R_fixture 500, V_fixture 1.8: 20-80 % time 143ns typ, 287ns min, 90.7ns max; typ from 1.8 V to 0.005 V
|   falling waveform, R_fixture 50, V_fixture 1.8: 20-80 % time 172ns typ, 379ns min, 102ns max; typ from 1.8 V to 0.049 V
[POWER_clamp]
-1.8V     401.1mA    209.4mA    454.2mA
-1.145V   79.39mA    49.82mA    86.39mA
-1.073V   52.49mA    35.39mA    58.76mA
-1.055V   46.58mA    32.04mA    52.82mA
-1.036V   40.67mA    28.68mA    46.87mA
-981.8mV  27.2mA     20.01mA    32.52mA
-927.3mV  18.17mA    13.19mA    21.87mA
-872.7mV  12.87mA    8.554mA    15.48mA
-818.2mV  10.26mA    6.071mA    12.52mA
-600mV    2.834mA    1.747mA    2.888mA
-490.9mV  760.8uA    616.2uA    563.4uA
0V        4.894nA    26.6nA     13.41nA
[Pulldown]
-1.8V     -777mA     -2.558A    -458.4mA
-1.418V   -503.6mA   -1.704A    -274.1mA
-1.091V   -246mA     -833.2mA   -147.3mA
-927.3mV  -205.8mA   -396mA     -321mA
-818.2mV  -374mA     -240.1mA   -549mA
-709.1mV  -482.3mA   -277.9mA   -676.6mA
-600mV    -464.9mA   -277.2mA   -648.9mA
218.2mV   131.5mA    73.81mA    188.3mA
545.5mV   267.7mA    144.1mA    391.8mA
927.3mV   351.1mA    177.8mA    534.4mA
1.855V    388.5mA    188.1mA    630.8mA
3.545V    373.8mA    185.1mA    612.9mA
[GND_clamp]
-1.8V     -6.905A    -5.48A     -6.849A
-1.145V   -1.563A    -1.472A    -1.273A
-1.109V   -1.305A    -1.292A    -1.009A
-1.073V   -1.058A    -1.118A    -761.8mA
-1.036V   -819.4mA   -948.6mA   -530.3mA
-1V       -610.5mA   -793.2mA   -361.6mA
-927.3mV  -263.9mA   -507.2mA   -161.9mA
-890.9mV  -170.2mA   -389mA     -139.4mA
-781.8mV  -65.52mA   -129.8mA   -108.5mA
-636.4mV  -24.47mA   -18.9mA    -43.94mA
-381.8mV  -239.7uA   -254uA     -441.8uA
1.764V    2.8nA      2.224uA    11.77nA
[Ramp]
dV/dt_f  1.0820366/0.14388937u 0.96978728/0.28635597u  1.1398935/91.426955n
dV/dt_r 0.13495711/0.10740419n 0.11658188/0.21318425n 0.14017335/65.051171p
R_load = 528.00
[Rising Waveform]
R_fixture = 500
V_fixture = 1.8
V_fixture_min = 1.62
V_fixture_max = 1.89
2.125ns   4.858mV    7.865mV    3.483mV
2.478ns   4.369mV    7.865mV    307.5mV
2.959ns   -61.51mV   7.864mV    621mV
4.015ns   575.4mV    7.907mV    1.09V
5.136ns   1.005V     2.55mV     1.394V
6.691ns   1.355V     661.8mV    1.636V
8.427ns   1.569V     1.081V     1.767V
10.94ns   1.708V     1.377V     1.848V
13.94ns   1.77V      1.524V     1.878V
19.14ns   1.8V       1.62V      1.89V
[Rising Waveform]
R_fixture = 50
V_fixture = 1.8
V_fixture_min = 1.62
V_fixture_max = 1.89
1.83ns    48.93mV    79.48mV    35.04mV
2.107ns   48.93mV    79.48mV    1.31V
2.619ns   48.22mV    79.48mV    1.762V
2.808ns   138.1mV    79.48mV    1.809V
3.103ns   1.286V     79.48mV    1.85V
3.546ns   1.628V     79.48mV    1.877V
4.887ns   1.784V     145.6mV    1.889V
5.27ns    1.792V     1.126V     1.89V
5.599ns   1.795V     1.404V     1.89V
7.681ns   1.8V       1.62V      1.89V
[Falling Waveform]
R_fixture = 500
V_fixture = 1.8
V_fixture_min = 1.62
V_fixture_max = 1.89
46.31ns   1.8V       1.62V      1.89V
109.6ns   1.723V     1.623V     1.28V
155.5ns   1.481V     1.62V      726.2mV
194.7ns   1.231V     1.606V     102.5mV
205.3ns   1.159V     1.598V     29.48mV
329.7ns   110.5mV    1.356V     4.388mV
344.8ns   44mV       1.315V     4.245mV
564.2ns   6.166mV    630.2mV    3.598mV
685.7ns   5.473mV    115.1mV    3.53mV
774.3ns   4.858mV    7.865mV    3.483mV
[Falling Waveform]
R_fixture = 50
V_fixture = 1.8
V_fixture_min = 1.62
V_fixture_max = 1.89
55.56ns   1.8V       1.62V      1.89V
138.6ns   1.717V     1.62V      1.242V
187.4ns   1.518V     1.619V     723mV
226ns     1.328V     1.613V     200.5mV
253.2ns   1.184V     1.603V     83.18mV
333.3ns   713.9mV    1.523V     46mV
397.1ns   233.8mV    1.418V     40.48mV
442.1ns   115mV      1.332V     38.64mV
898.8ns   51.51mV    231.5mV    35.17mV
1.296us   48.93mV    79.48mV    35.04mV
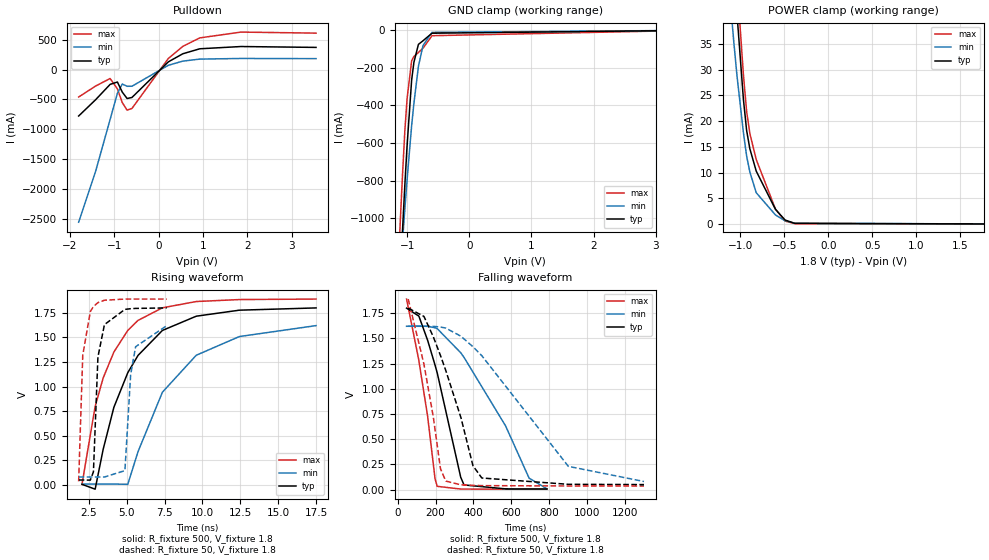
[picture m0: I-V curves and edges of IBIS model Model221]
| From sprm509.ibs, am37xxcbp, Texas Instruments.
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| Model based on original model for BQOMAPI2CHYFBPBRES_SSBHH
|   Sub model BQOMAPI2CHYRES_STD_PON_01_1P8
[model]   Model221
|[Input Load]   PU
|[Output Drive] LB01
|Voltage   1.8V
|Mode   I/O_OPEN_DRAIN
Model_type   I/O_open_drain
Polarity   Non-Inverting
Enable   Active-Low
Vinl =  0.567
Vinh =  1.323
Cref =  400.0000PF
Rref =  500.0000
Vref =  1.8V
Vmeas =  0.9
C_comp   3.85558p   3.723112p   3.857218p
[Model Spec]
Vinl   0.567   0.567   0.567
Vinh   1.323   1.323   1.323
[Temperature Range]   25   125   -40
[Voltage Range]   1.8   1.62   1.89
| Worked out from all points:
|   slope of the pulldown table from 0 to 0.27 V, typ, clamps not added: 1.71 ohm
|   GND clamp passes 1 mA (typ) near -0.44 V on its own axis
|   POWER clamp passes 1 mA (typ) near -0.51 V on its own axis
|   rising waveform, R_fixture 500, V_fixture 1.8: 20-80 % time 2.94ns typ, 3.67ns min, 2.39ns max; typ from 0.006 V to 1.8 V
|   rising waveform, R_fixture 50, V_fixture 1.8: 20-80 % time 360ps typ, 401ps min, 327ps max; typ from 0.05 V to 1.8 V
|   falling waveform, R_fixture 500, V_fixture 1.8: 20-80 % time 145ns typ, 289ns min, 91.6ns max; typ from 1.8 V to 0.006 V
|   falling waveform, R_fixture 50, V_fixture 1.8: 20-80 % time 173ns typ, 380ns min, 102ns max; typ from 1.8 V to 0.05 V
[POWER_clamp]
-1.8V     401.1mA    209.4mA    454.2mA
-1.145V   79.39mA    49.82mA    86.39mA
-1.073V   52.49mA    35.39mA    58.76mA
-1.036V   40.67mA    28.68mA    46.87mA
-963.6mV  24.19mA    17.73mA    28.97mA
-927.3mV  18.17mA    13.19mA    21.87mA
-890.9mV  14.63mA    10.1mA     17.61mA
-818.2mV  10.26mA    6.071mA    12.52mA
-600mV    2.834mA    1.747mA    2.888mA
-490.9mV  760.8uA    616.2uA    563.4uA
-381.8mV  112.8uA    147.2uA    57.34uA
1.764V    -11.66nA   -1.927uA   -18.08nA
[Pulldown]
-1.8V     -777mA     -2.558A    -458.4mA
-1.418V   -503.7mA   -1.705A    -274.3mA
-1.091V   -246.3mA   -833.3mA   -147.8mA
-927.3mV  -206.6mA   -396.2mA   -322.7mA
-818.2mV  -375.3mA   -240.6mA   -551.2mA
-709.1mV  -483.5mA   -278.4mA   -678.3mA
-600mV    -466mA     -277.7mA   -650.3mA
218.2mV   130.8mA    73.43mA    187.2mA
545.5mV   267.1mA    143.8mA    391mA
927.3mV   350.6mA    177.6mA    533.7mA
1.855V    388.5mA    188.2mA    630.7mA
3.545V    373.9mA    185.2mA    613.2mA
[GND_clamp]
-1.8V     -6.905A    -5.48A     -6.849A
-1.145V   -1.563A    -1.472A    -1.273A
-1.109V   -1.305A    -1.292A    -1.009A
-1.073V   -1.058A    -1.118A    -761.8mA
-1.036V   -819.4mA   -948.6mA   -530.3mA
-1V       -610.5mA   -793.2mA   -361.6mA
-927.3mV  -263.9mA   -507.2mA   -161.9mA
-890.9mV  -170.2mA   -389mA     -139.4mA
-818.2mV  -74.8mA    -191.7mA   -117.8mA
-745.5mV  -55.76mA   -81.74mA   -95.49mA
-600mV    -15.41mA   -10.81mA   -28.59mA
3.6V      0A         0A         0A
[Ramp]
dV/dt_f  1.0803755/0.14524486u 0.96885025/0.28892378u  1.1371513/92.114029n
dV/dt_r 0.31998739/3.7443076n 0.21258015/4.9034153n 0.40336981/2.968868n
R_load = 528.00
[Rising Waveform]
R_fixture = 500
V_fixture = 1.8
V_fixture_min = 1.62
V_fixture_max = 1.89
2.047ns   6.005mV    8.936mV    4.644mV
2.918ns   -42.96mV   8.935mV    798.9mV
3.45ns    364.3mV    8.935mV    1.089V
4.155ns   789.8mV    9.04mV     1.352V
5.071ns   1.141V     6.253mV    1.571V
5.748ns   1.317V     338.3mV    1.673V
7.357ns   1.571V     942.8mV    1.801V
9.594ns   1.716V     1.319V     1.865V
12.44ns   1.777V     1.509V     1.885V
17.5ns    1.8V       1.62V      1.89V
[Rising Waveform]
R_fixture = 50
V_fixture = 1.8
V_fixture_min = 1.62
V_fixture_max = 1.89
1.828ns   50.09mV    80.58mV    36.22mV
2.099ns   50.09mV    80.58mV    1.318V
2.598ns   48.76mV    80.58mV    1.763V
2.804ns   133.3mV    80.58mV    1.814V
3.101ns   1.301V     80.58mV    1.854V
3.53ns    1.63V      80.58mV    1.878V
4.883ns   1.785V     145.6mV    1.89V
5.261ns   1.792V     1.121V     1.89V
5.587ns   1.795V     1.405V     1.89V
7.645ns   1.8V       1.62V      1.89V
[Falling Waveform]
R_fixture = 500
V_fixture = 1.8
V_fixture_min = 1.62
V_fixture_max = 1.89
46.99ns   1.8V       1.62V      1.89V
112ns     1.721V     1.623V     1.28V
158.4ns   1.481V     1.62V      726.6mV
197.7ns   1.234V     1.605V     106.3mV
209ns     1.158V     1.597V     32.8mV
333.1ns   124.1mV    1.358V     5.822mV
350.6ns   46.59mV    1.312V     5.615mV
570.7ns   7.575mV    631.4mV    4.791mV
694.9ns   6.737mV    113.3mV    4.703mV
788.8ns   6.005mV    8.936mV    4.644mV
[Falling Waveform]
R_fixture = 50
V_fixture = 1.8
V_fixture_min = 1.62
V_fixture_max = 1.89
55.75ns   1.8V       1.62V      1.89V
138.8ns   1.718V     1.62V      1.245V
188.3ns   1.516V     1.619V     721.1mV
226.3ns   1.33V      1.613V     206.9mV
254.4ns   1.181V     1.602V     84.61mV
334.8ns   711.4mV    1.521V     47.37mV
398.1ns   236.3mV    1.417V     41.81mV
444.9ns   115.3mV    1.328V     39.85mV
902.3ns   52.7mV     230.9mV    36.34mV
1.302us   50.09mV    80.58mV    36.22mV
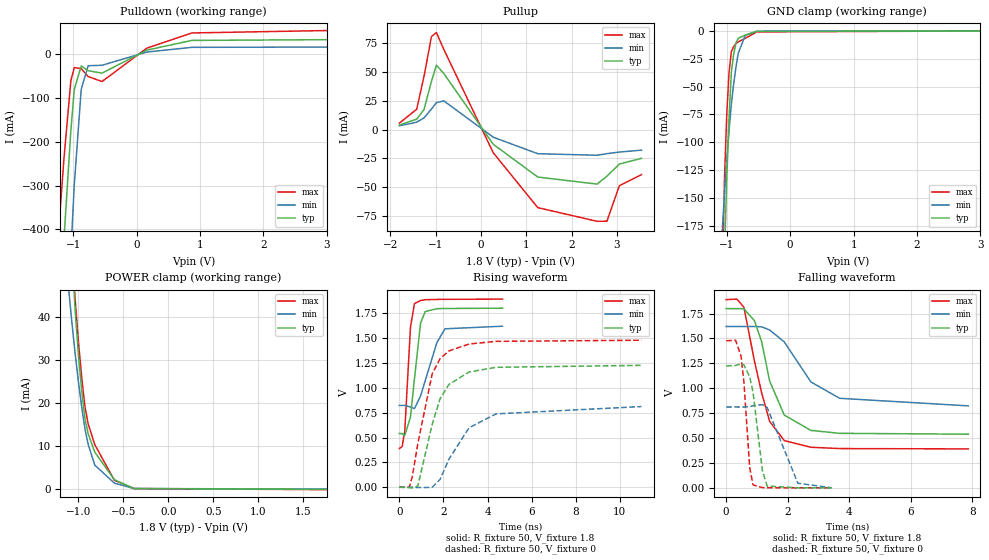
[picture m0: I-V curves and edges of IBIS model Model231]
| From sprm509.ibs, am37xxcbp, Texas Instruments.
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| Model based on original model for BQ18OMAPSMART2FBPB_SSBHH
|   Sub model ART2FBPB_H_0_PU1_1P8
[model]   Model231
|[Input Load]   PU
|[Output Drive] LB0
|Voltage   1.8V
|Mode   I/O
Model_type   I/O
Polarity   Non-Inverting
Enable   Active-Low
Vinl =  0.63
Vinh =  1.17
Cref =  15pF
Rref =  100.0000M
Vref =  0V
Vmeas =  0.9
C_comp   1.612314p   1.445601p   1.775954p
[Model Spec]
Vinl   0.63   0.567   0.6615
Vinh   1.17   1.053   1.2285
[Temperature Range]   25   125   -40
[Voltage Range]   1.8   1.62   1.89
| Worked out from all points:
|   slope of the pulldown table from 0 to 0.27 V, typ, clamps not added: 17.8 ohm
|   slope of the pullup table from 0 to 0.27 V, typ, clamps not added: 21.5 ohm
|   GND clamp passes 1 mA (typ) near -0.57 V on its own axis
|   POWER clamp passes 1 mA (typ) near -0.53 V on its own axis
|   rising waveform, R_fixture 50, V_fixture 1.8: 20-80 % time 342ps typ, 660ps min, 212ps max; typ from 0.54 V to 1.8 V
|   rising waveform, R_fixture 50, V_fixture 0: 20-80 % time 957ps typ, 1.43ns min, 829ps max; typ from 0.001 V to 1.23 V
|   falling waveform, R_fixture 50, V_fixture 1.8: 20-80 % time 683ps typ, 1.19ns min, 664ps max; typ from 1.8 V to 0.54 V
|   falling waveform, R_fixture 50, V_fixture 0: 20-80 % time 282ps typ, 490ps min, 197ps max; typ from 1.23 V to 0.001 V
[POWER_clamp]
-1.8V     449.2mA    229.3mA    499.9mA
-1.109V   70.1mA     46.68mA    71.89mA
-1.073V   55.22mA    38.88mA    57.09mA
-1.036V   41.55mA    31.43mA    44.07mA
-1V       31.28mA    24.96mA    34.35mA
-963.6mV  22.88mA    19.13mA    26.04mA
-927.3mV  16.35mA    13.96mA    19.14mA
-890.9mV  12.8mA     10.36mA    15.1mA
-818.2mV  8.584mA    5.567mA    10.34mA
-600mV    2.149mA    1.354mA    2.023mA
-381.8mV  86.82uA    96.98uA    78.48uA
1.764V    -96.73uA   -46.5uA    -163.5uA
[Pulldown]
-1.8V     -1.866A    -2.926A    -1.473A
-1.255V   -690.3mA   -1.165A    -458.8mA
-1.2V     -556.9mA   -981.3mA   -347.5mA
-1.145V   -424mA     -799.3mA   -238.7mA
-1.036V   -174.1mA   -452.5mA   -60.3mA
-981.8mV  -80.13mA   -298.3mA   -30.04mA
-872.7mV  -26.27mA   -79.78mA   -32.44mA
-763.6mV  -37.27mA   -25.87mA   -50.47mA
-545.5mV  -42.85mA   -24.82mA   -62.02mA
163.6mV   9.905mA    5.464mA    14.49mA
872.7mV   32.06mA    16.22mA    49.12mA
3.545V    34.18mA    16.99mA    56.07mA
[Pullup]
-1.8V     4.02mA     3.353mA    5.71mA
-1.418V   9.153mA    6.524mA    17.71mA
-1.255V   17.65mA    10.28mA    46.46mA
-1.091V   42.13mA    17.99mA    80.98mA
-981.8mV  56.04mA    23.5mA     84.34mA
-818.2mV  48.72mA    25.01mA    69.63mA
272.7mV   -12.68mA   -6.535mA   -20.08mA
1.255V    -41.13mA   -20.87mA   -67.69mA
2.564V    -47.26mA   -22.22mA   -79.57mA
2.782V    -40.42mA   -20.82mA   -79.47mA
3.055V    -29.85mA   -19.43mA   -48.72mA
3.545V    -24.9mA    -17.8mA    -39.06mA
[GND_clamp]
-1.8V     -3.26A     -1.496A    -3.636A
-1.073V   -295.4mA   -181.3mA   -234.2mA
-1.036V   -202.2mA   -145.8mA   -132.6mA
-1V       -132.7mA   -116.1mA   -74.88mA
-963.6mV  -77.6mA    -89.37mA   -36.9mA
-927.3mV  -36.98mA   -65.53mA   -18.61mA
-890.9mV  -20.91mA   -47.52mA   -14.11mA
-854.5mV  -10.79mA   -32.36mA   -11.2mA
-818.2mV  -6.611mA   -20.04mA   -9.885mA
-709.1mV  -3.838mA   -4.175mA   -6.748mA
-527.3mV  -502uA     -336.2uA   -960.8uA
3.6V      0A         0A         0A
[Ramp]
dV/dt_f  0.7576445/0.6829047n  0.4789519/1.200246n   0.9042098/0.6666382n
dV/dt_r  0.7385246/0.9568619n   0.490018/1.440358n   0.8916794/0.830814n
R_load = 50
[Rising Waveform]
R_fixture = 50
V_fixture = 1.8
V_fixture_min = 1.62
V_fixture_max = 1.89
0s        539.5mV    822.3mV    389.2mV
126ps     539.6mV    822.6mV    410.1mV
243ps     519.8mV    822.3mV    559.4mV
504ps     705.7mV    806.6mV    1.608V
684ps     1.09V      789.8mV    1.845V
963ps     1.652V     918.1mV    1.876V
1.17ns    1.765V     1.07V      1.884V
1.701ns   1.794V     1.453V     1.887V
2.07ns    1.796V     1.592V     1.888V
4.68ns    1.799V     1.618V     1.89V
[Rising Waveform]
R_fixture = 50
V_fixture = 0
V_fixture_min = 0
V_fixture_max = 0
0s        752.1uV    867.1uV    174.2uV
450ps     -4.635mV   2.148mV    679.6uV
585ps     -5.701mV   735.5uV    106.2mV
837ps     13.54mV    -2.412mV   439mV
1.485ns   628.5mV    -889.8uV   1.137V
1.845ns   888.9mV    78.91mV    1.292V
2.25ns    1.034V     283.2mV    1.37V
3.159ns   1.158V     597.9mV    1.439V
4.383ns   1.205V     737.4mV    1.466V
10.98ns   1.225V     810.9mV    1.477V
[Falling Waveform]
R_fixture = 50
V_fixture = 1.8
V_fixture_min = 1.62
V_fixture_max = 1.89
0s        1.8V       1.62V      1.89V
351ps     1.8V       1.62V      1.895V
576ps     1.798V     1.62V      1.813V
918ps     1.679V     1.621V     1.276V
1.152ns   1.47V      1.617V     956.9mV
1.413ns   1.074V     1.586V     668.4mV
1.89ns    731.3mV    1.465V     475.1mV
2.754ns   577.7mV    1.064V     408.6mV
3.69ns    548.4mV    899.9mV    395.5mV
7.875ns   539.7mV    824.1mV    392.2mV
[Falling Waveform]
R_fixture = 50
V_fixture = 0
V_fixture_min = 0
V_fixture_max = 0
0s        1.225V     812.6mV    1.477V
306ps     1.229V     812.9mV    1.483V
486ps     1.245V     812.7mV    1.319V
576ps     1.236V     812.4mV    1.065V
765ps     1.115V     816.1mV    203mV
873ps     962.4mV    825.2mV    31.39mV
1.179ns   171.8mV    836mV      3.712mV
1.332ns   19.78mV    807.9mV    2.829mV
2.331ns   1.634mV    47.47mV    1.643mV
3.429ns   1.234mV    2.456mV    1.435mV
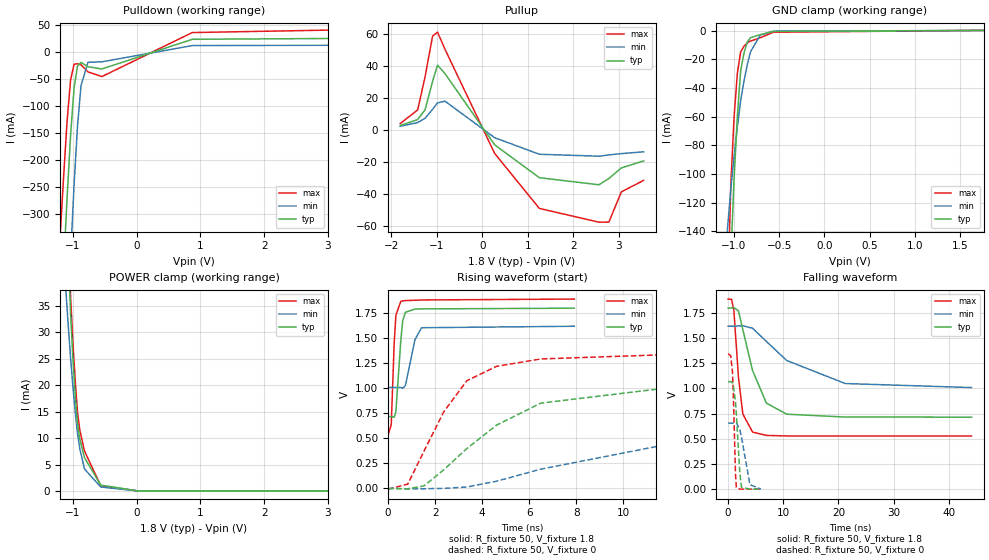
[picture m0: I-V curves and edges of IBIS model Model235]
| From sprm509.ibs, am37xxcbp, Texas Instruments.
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| Model based on original model for BQ18OMAPSMART1HYFBPB_SSBHV
|   Sub model FBPB_VS00L01_PD1_1P8
[model]   Model235
|[Input Load]   PD
|[Output Drive] SC00LB01
|Voltage   1.8V
|Mode   I/O
Model_type   I/O
Polarity   Non-Inverting
Enable   Active-Low
Vinl =  0.63
Vinh =  1.17
Cref =  15pF
Rref =  100.0000M
Vref =  0V
Vmeas =  0.9
C_comp   1.429432p   1.270657p   1.602015p
[Model Spec]
Vinl   0.63   0.567   0.6615
Vinh   1.17   1.053   1.2285
[Temperature Range]   25   125   -40
[Voltage Range]   1.8   1.62   1.89
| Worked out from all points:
|   slope of the pulldown table from 0 to 0.27 V, typ, clamps not added: 24.3 ohm
|   slope of the pullup table from 0 to 0.27 V, typ, clamps not added: 29.7 ohm
|   GND clamp passes 1 mA (typ) near -0.60 V on its own axis
|   POWER clamp passes 1 mA (typ) near -0.55 V on its own axis
|   rising waveform, R_fixture 50, V_fixture 1.8: 20-80 % time 178ps typ, 316ps min, 125ps max; typ from 0.716 V to 1.8 V
|   rising waveform, R_fixture 50, V_fixture 0: 20-80 % time 4.03ns typ, 9.14ns min, 2.04ns max; typ from 0 V to 1.06 V
|   falling waveform, R_fixture 50, V_fixture 1.8: 20-80 % time 3.37ns typ, 8.79ns min, 1.24ns max; typ from 1.8 V to 0.716 V
|   falling waveform, R_fixture 50, V_fixture 0: 20-80 % time 700ps typ, 1.17ns min, 407ps max; typ from 1.06 V to 0 V
[POWER_clamp]
-1.8V     362.5mA    191.4mA    412.8mA
-1.109V   56.74mA    37.73mA    60.49mA
-1.073V   44.66mA    31.25mA    47.92mA
-1.036V   33.51mA    25.07mA    36.71mA
-1V       25.05mA    19.75mA    28.19mA
-963.6mV  18.1mA     14.99mA    20.91mA
-927.3mV  12.67mA    10.8mA     14.87mA
-890.9mV  9.735mA    7.937mA    11.45mA
-818.2mV  6.3mA      4.158mA    7.553mA
-563.6mV  1.102mA    739.7uA    992.8uA
18.18mV   0A         0A         0A
3.6V      0A         0A         0A
[Pulldown]
-1.8V     -1.718A    -2.61A     -1.406A
-1.2V     -527.4mA   -844.5mA   -339.9mA
-1.145V   -396mA     -683.1mA   -229.1mA
-1.091V   -269mA     -526.7mA   -127.5mA
-1.036V   -153.6mA   -378.9mA   -51.17mA
-981.8mV  -66.33mA   -245.6mA   -22.67mA
-927.3mV  -26mA      -136.2mA   -21.54mA
-872.7mV  -19.34mA   -61.98mA   -23.69mA
-763.6mV  -27.2mA    -19.05mA   -36.72mA
-545.5mV  -31.39mA   -18.17mA   -45.46mA
872.7mV   23.46mA    11.88mA    35.92mA
3.545V    25.34mA    12.51mA    41.58mA
[Pullup]
-1.8V     2.903mA    2.423mA    4.112mA
-1.418V   6.595mA    4.711mA    12.64mA
-1.255V   12.69mA    7.42mA     33.24mA
-1.091V   30.4mA     13mA       58.69mA
-981.8mV  40.63mA    17.02mA    61.3mA
-818.2mV  35.38mA    18.12mA    50.59mA
272.7mV   -9.18mA    -4.728mA   -14.55mA
1.255V    -29.75mA   -15.09mA   -48.97mA
2.564V    -34.17mA   -16.31mA   -57.57mA
2.782V    -30.25mA   -15.5mA    -57.48mA
3.055V    -23.63mA   -14.68mA   -38.61mA
3.545V    -19.25mA   -13.56mA   -31.41mA
[GND_clamp]
-1.8V     -2.82A     -1.192A    -3.165A
-1.073V   -235.8mA   -138.4mA   -192.1mA
-1.036V   -159.6mA   -110.8mA   -107.6mA
-1V       -103.8mA   -87.86mA   -60.71mA
-963.6mV  -60.04mA   -67.29mA   -29.85mA
-927.3mV  -28.26mA   -49.1mA    -14.96mA
-890.9mV  -15.95mA   -35.5mA    -11.07mA
-854.5mV  -8.194mA   -24.09mA   -8.535mA
-818.2mV  -4.986mA   -14.87mA   -7.361mA
-709.1mV  -2.849mA   -3.094mA   -4.979mA
-563.6mV  -632.2uA   -437.1uA   -1.183mA
1.764V    97.78uA    55.01uA    156.3uA
[Ramp]
dV/dt_f  0.6527136/3.372412n   0.3694213/8.863562n   0.8186198/1.238749n
dV/dt_r  0.6491451/4.041984n   0.3993277/9.218052n   0.8211421/2.048672n
R_load = 50
[Rising Waveform]
R_fixture = 50
V_fixture = 1.8
V_fixture_min = 1.62
V_fixture_max = 1.89
0s        715.6mV    1.007V     530.1mV
135ps     716.3mV    1.007V     635mV
261ps     711.2mV    1.007V     1.454V
333ps     767.2mV    1.007V     1.727V
540ps     1.471V     1.007V     1.865V
621ps     1.669V     998mV      1.87V
738ps     1.757V     1.027V     1.873V
1.143ns   1.788V     1.484V     1.876V
1.422ns   1.79V      1.602V     1.879V
7.911ns   1.797V     1.617V     1.888V
[Rising Waveform]
R_fixture = 50
V_fixture = 0
V_fixture_min = 0
V_fixture_max = 0
0s        -52.05uV   112.2uV    -7.586mV
837ps     -3.738mV   -5.334mV   42.81mV
1.53ns    25.38mV    -3.403mV   373.5mV
2.367ns   185.7mV    227.6uV    764.3mV
3.348ns   397.8mV    14.09mV    1.074V
4.608ns   630.7mV    71.77mV    1.217V
6.489ns   850.2mV    192mV      1.291V
12.64ns   1.024V     474.5mV    1.34V
20.2ns    1.057V     594.2mV    1.346V
58.76ns   1.065V     654.4mV    1.346V
[Falling Waveform]
R_fixture = 50
V_fixture = 1.8
V_fixture_min = 1.62
V_fixture_max = 1.89
0s        1.798V     1.619V     1.888V
621ps     1.801V     1.618V     1.885V
1.035ns   1.803V     1.618V     1.776V
1.863ns   1.772V     1.622V     1.116V
2.664ns   1.584V     1.623V     746.2mV
4.428ns   1.178V     1.598V     567.1mV
6.939ns   854.4mV    1.467V     534mV
10.62ns   744.7mV    1.278V     528.6mV
21.24ns   716.1mV    1.049V     528.2mV
44.15ns   715.5mV    1.009V     528.2mV
[Falling Waveform]
R_fixture = 50
V_fixture = 0
V_fixture_min = 0
V_fixture_max = 0
0s        1.065V     655.9mV    1.346V
468ps     1.07V      656.1mV    1.324V
783ps     1.057V     656.4mV    1.162V
936ps     1.03V      658.5mV    948.4mV
1.332ns   865.7mV    665.5mV    148.6mV
1.485ns   743.3mV    662.4mV    16.75mV
2.115ns   163.2mV    591.2mV    813.1uV
2.421ns   18.65mV    516.6mV    409.9uV
3.951ns   499.7uV    44.95mV    97.03uV
5.94ns    181.6uV    1.631mV    29.03uV
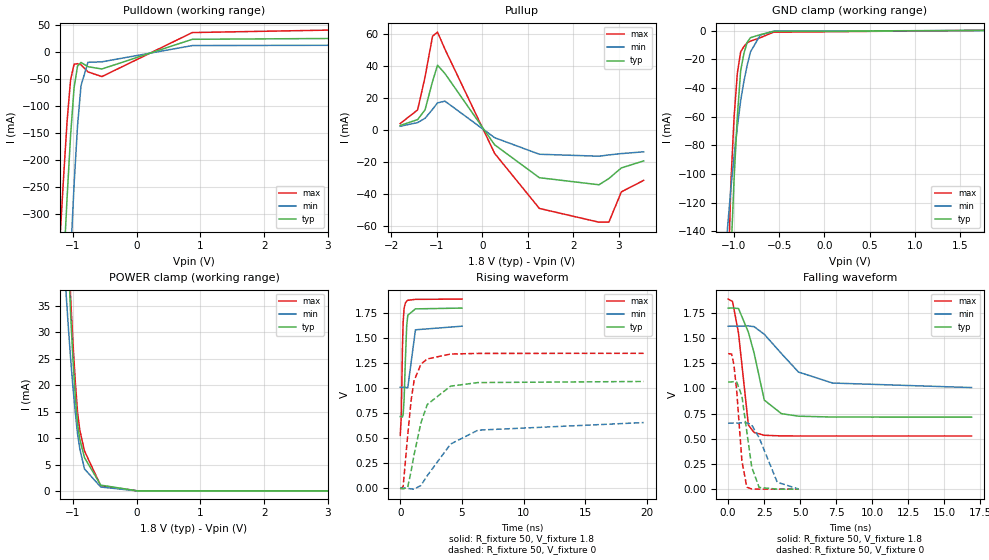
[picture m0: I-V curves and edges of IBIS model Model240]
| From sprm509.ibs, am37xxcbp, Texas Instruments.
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| Model based on original model for BQ18OMAPSMART1HYFBPB_SSBHV
|   Sub model FBPB_VS10L11_PD1_1P8
[model]   Model240
|[Input Load]   PD
|[Output Drive] SC10LB11
|Voltage   1.8V
|Mode   I/O
Model_type   I/O
Polarity   Non-Inverting
Enable   Active-Low
Vinl =  0.63
Vinh =  1.17
Cref =  15pF
Rref =  100.0000M
Vref =  0V
Vmeas =  0.9
C_comp   1.429432p   1.270657p   1.602015p
[Model Spec]
Vinl   0.63   0.567   0.6615
Vinh   1.17   1.053   1.2285
[Temperature Range]   25   125   -40
[Voltage Range]   1.8   1.62   1.89
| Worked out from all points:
|   slope of the pulldown table from 0 to 0.27 V, typ, clamps not added: 24.3 ohm
|   slope of the pullup table from 0 to 0.27 V, typ, clamps not added: 29.7 ohm
|   GND clamp passes 1 mA (typ) near -0.60 V on its own axis
|   POWER clamp passes 1 mA (typ) near -0.55 V on its own axis
|   rising waveform, R_fixture 50, V_fixture 1.8: 20-80 % time 178ps typ, 308ps min, 126ps max; typ from 0.715 V to 1.8 V
|   rising waveform, R_fixture 50, V_fixture 0: 20-80 % time 1.32ns typ, 2.85ns min, 704ps max; typ from 0 V to 1.06 V
|   falling waveform, R_fixture 50, V_fixture 1.8: 20-80 % time 1.03ns typ, 2.53ns min, 606ps max; typ from 1.8 V to 0.716 V
|   falling waveform, R_fixture 50, V_fixture 0: 20-80 % time 601ps typ, 1.01ns min, 437ps max; typ from 1.06 V to 0 V
[POWER_clamp]
-1.8V     362.5mA    191.4mA    412.8mA
-1.109V   56.74mA    37.73mA    60.49mA
-1.073V   44.66mA    31.25mA    47.92mA
-1.036V   33.51mA    25.07mA    36.71mA
-1V       25.05mA    19.75mA    28.19mA
-963.6mV  18.1mA     14.99mA    20.91mA
-927.3mV  12.67mA    10.8mA     14.87mA
-890.9mV  9.735mA    7.937mA    11.45mA
-818.2mV  6.3mA      4.158mA    7.553mA
-563.6mV  1.102mA    739.7uA    992.8uA
18.18mV   0A         0A         0A
3.6V      0A         0A         0A
[Pulldown]
-1.8V     -1.718A    -2.61A     -1.406A
-1.2V     -527.4mA   -844.5mA   -339.9mA
-1.145V   -396mA     -683.1mA   -229.1mA
-1.091V   -269mA     -526.7mA   -127.5mA
-1.036V   -153.6mA   -378.9mA   -51.17mA
-981.8mV  -66.33mA   -245.6mA   -22.67mA
-927.3mV  -26mA      -136.2mA   -21.54mA
-872.7mV  -19.34mA   -61.98mA   -23.69mA
-763.6mV  -27.2mA    -19.05mA   -36.72mA
-545.5mV  -31.39mA   -18.17mA   -45.46mA
872.7mV   23.46mA    11.88mA    35.92mA
3.545V    25.34mA    12.51mA    41.58mA
[Pullup]
-1.8V     2.903mA    2.423mA    4.112mA
-1.418V   6.595mA    4.711mA    12.64mA
-1.255V   12.69mA    7.42mA     33.24mA
-1.091V   30.4mA     13mA       58.69mA
-981.8mV  40.63mA    17.02mA    61.3mA
-818.2mV  35.38mA    18.12mA    50.59mA
272.7mV   -9.18mA    -4.728mA   -14.55mA
1.255V    -29.75mA   -15.09mA   -48.97mA
2.564V    -34.17mA   -16.31mA   -57.57mA
2.782V    -30.25mA   -15.5mA    -57.49mA
3.055V    -23.63mA   -14.68mA   -38.61mA
3.545V    -19.25mA   -13.56mA   -31.41mA
[GND_clamp]
-1.8V     -2.82A     -1.192A    -3.165A
-1.073V   -235.8mA   -138.4mA   -192.1mA
-1.036V   -159.6mA   -110.8mA   -107.6mA
-1V       -103.8mA   -87.86mA   -60.71mA
-963.6mV  -60.04mA   -67.29mA   -29.85mA
-927.3mV  -28.26mA   -49.1mA    -14.96mA
-890.9mV  -15.95mA   -35.5mA    -11.07mA
-854.5mV  -8.194mA   -24.09mA   -8.535mA
-818.2mV  -4.986mA   -14.87mA   -7.361mA
-709.1mV  -2.849mA   -3.094mA   -4.979mA
-563.6mV  -632.2uA   -437.1uA   -1.183mA
1.764V    97.78uA    55.01uA    156.3uA
[Ramp]
dV/dt_f  0.6515746/1.030887n   0.3683728/2.555258n   0.817999/0.6079428n
dV/dt_r  0.6497708/1.32104n   0.4000005/2.877744n   0.8216529/0.7057811n
R_load = 50
[Rising Waveform]
R_fixture = 50
V_fixture = 1.8
V_fixture_min = 1.62
V_fixture_max = 1.89
0s        715mV      1.007V     526.7mV
81ps      716.9mV    1.007V     706.7mV
180ps     710mV      1.007V     1.403V
234ps     731.5mV    1.007V     1.654V
315ps     888.5mV    1.007V     1.799V
414ps     1.27V      1.009V     1.847V
522ps     1.619V     1.001V     1.867V
612ps     1.727V     1.004V     1.876V
1.233ns   1.79V      1.581V     1.885V
5.004ns   1.798V     1.617V     1.888V
[Rising Waveform]
R_fixture = 50
V_fixture = 0
V_fixture_min = 0
V_fixture_max = 0
0s        -245.4uV   110uV      -10.32mV
234ps     -8.527mV   -416.9uV   14.1mV
603ps     7.915mV    -2.317mV   526.5mV
882ps     170.6mV    -8.151mV   876.4mV
1.116ns   330.3mV    -10.64mV   1.07V
1.674ns   650.8mV    26.23mV    1.237V
2.187ns   835.2mV    123.8mV    1.29V
4.077ns   1.018V     439.4mV    1.339V
6.291ns   1.054V     578.7mV    1.345V
19.72ns   1.065V     654.4mV    1.346V
[Falling Waveform]
R_fixture = 50
V_fixture = 1.8
V_fixture_min = 1.62
V_fixture_max = 1.89
0s        1.798V     1.618V     1.888V
306ps     1.799V     1.619V     1.864V
720ps     1.794V     1.618V     1.549V
1.404ns   1.559V     1.621V     638.3mV
1.8ns     1.353V     1.614V     563.6mV
2.511ns   884.1mV    1.538V     535.3mV
3.699ns   750.2mV    1.347V     528.8mV
4.887ns   724.8mV    1.163V     528.2mV
7.254ns   716.2mV    1.054V     528.2mV
16.91ns   715.5mV    1.009V     528.2mV
[Falling Waveform]
R_fixture = 50
V_fixture = 0
V_fixture_min = 0
V_fixture_max = 0
0s        1.065V     655.9mV    1.346V
243ps     1.065V     656.3mV    1.342V
396ps     1.068V     656.2mV    1.239V
594ps     1.064V     656.1mV    975.4mV
954ps     925.5mV    658.2mV    281.9mV
1.296ns   571.4mV    659.1mV    20.06mV
1.638ns   218.7mV    637.9mV    1.765mV
2.151ns   16.72mV    511mV      211.3uV
3.411ns   341.8uV    68.54mV    5.199uV
4.896ns   56.41uV    1.631mV    578nV
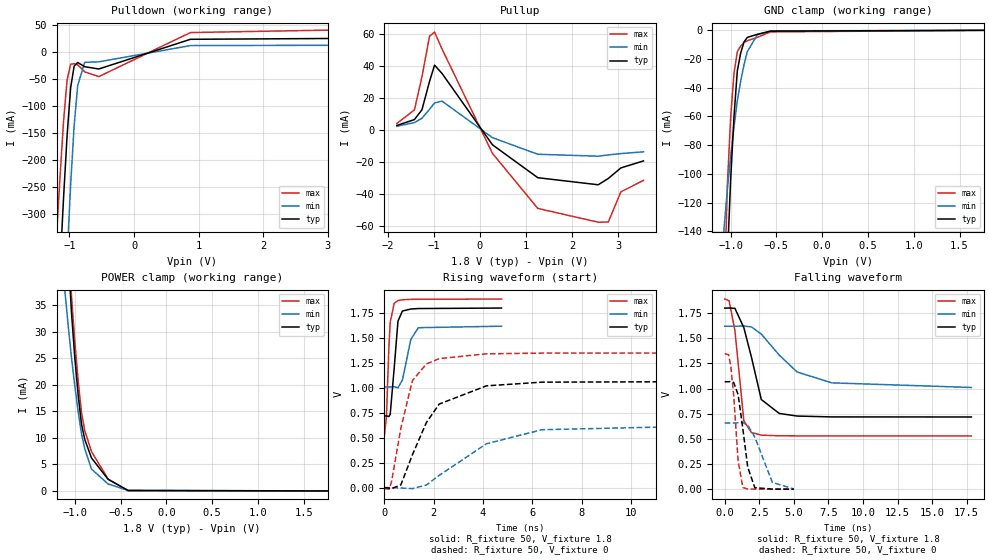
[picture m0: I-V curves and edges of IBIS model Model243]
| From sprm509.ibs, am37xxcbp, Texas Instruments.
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| Model based on original model for BQ18OMAPSMART1HYFBPB_SSBHV
|   Sub model PB_VS10L01_PUPD0_1P8
[model]   Model243
|[Input Load]   PI
|[Output Drive] SC10LB01
|Voltage   1.8V
|Mode   I/O
Model_type   I/O
Polarity   Non-Inverting
Enable   Active-Low
Vinl =  0.63
Vinh =  1.17
Cref =  15pF
Rref =  100.0000M
Vref =  0V
Vmeas =  0.9
C_comp   1.429432p   1.270657p   1.602015p
[Model Spec]
Vinl   0.63   0.567   0.6615
Vinh   1.17   1.053   1.2285
[Temperature Range]   25   125   -40
[Voltage Range]   1.8   1.62   1.89
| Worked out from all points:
|   slope of the pulldown table from 0 to 0.27 V, typ, clamps not added: 24.3 ohm
|   slope of the pullup table from 0 to 0.27 V, typ, clamps not added: 29.7 ohm
|   GND clamp passes 1 mA (typ) near -0.60 V on its own axis
|   POWER clamp passes 1 mA (typ) near -0.56 V on its own axis
|   rising waveform, R_fixture 50, V_fixture 1.8: 20-80 % time 178ps typ, 307ps min, 126ps max; typ from 0.717 V to 1.8 V
|   rising waveform, R_fixture 50, V_fixture 0: 20-80 % time 1.33ns typ, 2.89ns min, 711ps max; typ from 0 V to 1.07 V
|   falling waveform, R_fixture 50, V_fixture 1.8: 20-80 % time 1.06ns typ, 2.76ns min, 586ps max; typ from 1.8 V to 0.718 V
|   falling waveform, R_fixture 50, V_fixture 0: 20-80 % time 590ps typ, 1ns min, 420ps max; typ from 1.07 V to 0 V
[POWER_clamp]
-1.8V     362.5mA    191.4mA    412.8mA
-1.109V   56.69mA    37.71mA    60.38mA
-1.073V   44.6mA     31.22mA    47.8mA
-1.036V   33.44mA    25.04mA    36.59mA
-1V       24.98mA    19.72mA    28.06mA
-963.6mV  18.03mA    14.96mA    20.78mA
-927.3mV  12.59mA    10.77mA    14.74mA
-890.9mV  9.653mA    7.899mA    11.31mA
-818.2mV  6.214mA    4.114mA    7.414mA
-636.4mV  2.183mA    1.307mA    2.238mA
-418.2mV  83.85uA    105.2uA    35.14uA
1.764V    -1.228nA   -79.12nA   -1.453nA
[Pulldown]
-1.8V     -1.718A    -2.61A     -1.406A
-1.2V     -527.4mA   -844.5mA   -339.9mA
-1.145V   -396mA     -683.1mA   -229.1mA
-1.091V   -269mA     -526.7mA   -127.5mA
-1.036V   -153.6mA   -378.9mA   -51.17mA
-981.8mV  -66.34mA   -245.6mA   -22.67mA
-927.3mV  -26mA      -136.2mA   -21.54mA
-872.7mV  -19.34mA   -61.98mA   -23.69mA
-763.6mV  -27.2mA    -19.05mA   -36.72mA
-545.5mV  -31.39mA   -18.17mA   -45.46mA
872.7mV   23.46mA    11.88mA    35.92mA
3.545V    25.34mA    12.51mA    41.58mA
[Pullup]
-1.8V     2.903mA    2.423mA    4.112mA
-1.418V   6.595mA    4.711mA    12.64mA
-1.255V   12.69mA    7.42mA     33.23mA
-1.091V   30.4mA     13mA       58.69mA
-981.8mV  40.63mA    17.02mA    61.3mA
-818.2mV  35.38mA    18.12mA    50.59mA
272.7mV   -9.18mA    -4.728mA   -14.55mA
1.255V    -29.75mA   -15.09mA   -48.97mA
2.564V    -34.17mA   -16.31mA   -57.57mA
2.782V    -30.25mA   -15.5mA    -57.48mA
3.055V    -23.63mA   -14.68mA   -38.61mA
3.545V    -19.25mA   -13.56mA   -31.41mA
[GND_clamp]
-1.8V     -2.82A     -1.192A    -3.165A
-1.073V   -235.7mA   -138.4mA   -192.1mA
-1.036V   -159.5mA   -110.8mA   -107.5mA
-1V       -103.8mA   -87.85mA   -60.67mA
-963.6mV  -60mA      -67.28mA   -29.8mA
-927.3mV  -28.21mA   -49.08mA   -14.9mA
-890.9mV  -15.9mA    -35.48mA   -10.99mA
-854.5mV  -8.138mA   -24.07mA   -8.449mA
-818.2mV  -4.924mA   -14.85mA   -7.266mA
-709.1mV  -2.784mA   -3.064mA   -4.883mA
-563.6mV  -570.2uA   -404.5uA   -1.092mA
1.764V    -11.02pA   583.5nA    3.035nA
[Ramp]
dV/dt_f  0.6513713/1.063223n   0.3678851/2.782216n   0.8182384/0.5875677n
dV/dt_r  0.6512543/1.336428n   0.4008919/2.917656n   0.8234319/0.71298n
R_load = 50
[Rising Waveform]
R_fixture = 50
V_fixture = 1.8
V_fixture_min = 1.62
V_fixture_max = 1.89
0s        717.1mV    1.009V     528.8mV
81ps      719mV      1.009V     709mV
180ps     712.1mV    1.009V     1.404V
234ps     734.4mV    1.009V     1.657V
396ps     1.199V     1.011V     1.848V
549ps     1.669V     1V         1.875V
729ps     1.77V      1.078V     1.883V
1.071ns   1.79V      1.486V     1.887V
1.377ns   1.795V     1.603V     1.888V
4.752ns   1.8V       1.618V     1.89V
[Rising Waveform]
R_fixture = 50
V_fixture = 0
V_fixture_min = 0
V_fixture_max = 0
0s        -249.4uV   110.2uV    -10.1mV
189ps     -5.207mV   -345uV     -15.91mV
288ps     -10.5mV    -337.3uV   59.06mV
666ps     27.1mV     -4.008mV   594.2mV
1.134ns   328.1mV    -10.64mV   1.072V
1.701ns   651.2mV    25.48mV    1.239V
2.223ns   837.3mV    122.7mV    1.293V
4.14ns    1.02V      439.5mV    1.341V
6.39ns    1.057V     579.9mV    1.348V
20.02ns   1.067V     655.8mV    1.349V
[Falling Waveform]
R_fixture = 50
V_fixture = 1.8
V_fixture_min = 1.62
V_fixture_max = 1.89
0s        1.8V       1.62V      1.89V
315ps     1.801V     1.62V      1.874V
738ps     1.798V     1.62V      1.579V
1.386ns   1.605V     1.622V     679mV
1.935ns   1.312V     1.613V     563mV
2.646ns   891.3mV    1.542V     537.3mV
3.942ns   753mV      1.333V     530.4mV
5.238ns   726.8mV    1.165V     529.8mV
7.74ns    718.4mV    1.057V     529.8mV
17.84ns   717.6mV    1.011V     529.8mV
[Falling Waveform]
R_fixture = 50
V_fixture = 0
V_fixture_min = 0
V_fixture_max = 0
0s        1.068V     657.3mV    1.349V
288ps     1.068V     657.7mV    1.335V
450ps     1.071V     657.5mV    1.213V
648ps     1.061V     657.5mV    935.3mV
972ps     938.7mV    659.8mV    278.3mV
1.314ns   598.4mV    660.3mV    16.71mV
1.665ns   218.6mV    637.6mV    1.703mV
2.178ns   14.66mV    517.1mV    215.2uV
3.447ns   356.2uV    66.86mV    6.985uV
5.004ns   61.38uV    1.637mV    738.4nV
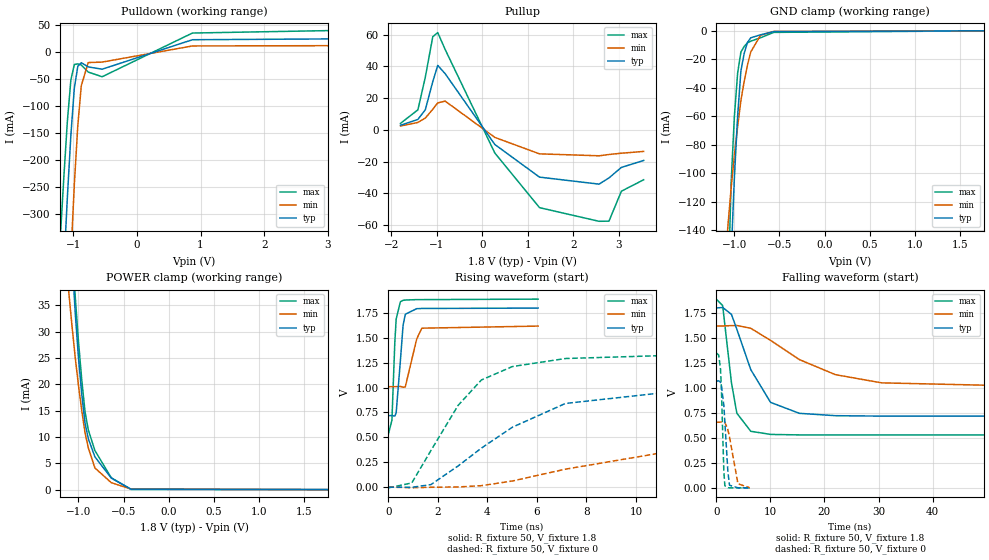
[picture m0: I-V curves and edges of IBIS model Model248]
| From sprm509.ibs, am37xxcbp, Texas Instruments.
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| Model based on original model for BQ18OMAPSMART1HYFBPB_SSBHV
|   Sub model PB_VS00L00_PUPD0_1P8
[model]   Model248
|[Input Load]   PI
|[Output Drive] SC00LB00
|Voltage   1.8V
|Mode   I/O
Model_type   I/O
Polarity   Non-Inverting
Enable   Active-Low
Vinl =  0.63
Vinh =  1.17
Cref =  15pF
Rref =  100.0000M
Vref =  0V
Vmeas =  0.9
C_comp   1.429432p   1.270657p   1.602015p
[Model Spec]
Vinl   0.63   0.567   0.6615
Vinh   1.17   1.053   1.2285
[Temperature Range]   25   125   -40
[Voltage Range]   1.8   1.62   1.89
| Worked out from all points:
|   slope of the pulldown table from 0 to 0.27 V, typ, clamps not added: 24.3 ohm
|   slope of the pullup table from 0 to 0.27 V, typ, clamps not added: 29.7 ohm
|   GND clamp passes 1 mA (typ) near -0.60 V on its own axis
|   POWER clamp passes 1 mA (typ) near -0.56 V on its own axis
|   rising waveform, R_fixture 50, V_fixture 1.8: 20-80 % time 178ps typ, 310ps min, 125ps max; typ from 0.718 V to 1.8 V
|   rising waveform, R_fixture 50, V_fixture 0: 20-80 % time 4.53ns typ, 10.3ns min, 2.27ns max; typ from 0 V to 1.07 V
|   falling waveform, R_fixture 50, V_fixture 1.8: 20-80 % time 4.9ns typ, 12.6ns min, 1.98ns max; typ from 1.8 V to 0.718 V
|   falling waveform, R_fixture 50, V_fixture 0: 20-80 % time 720ps typ, 1.2ns min, 441ps max; typ from 1.07 V to 0 V
[POWER_clamp]
-1.8V     362.5mA    191.4mA    412.8mA
-1.109V   56.69mA    37.71mA    60.38mA
-1.073V   44.6mA     31.22mA    47.8mA
-1.036V   33.44mA    25.04mA    36.59mA
-1V       24.98mA    19.72mA    28.06mA
-963.6mV  18.03mA    14.96mA    20.78mA
-927.3mV  12.59mA    10.77mA    14.74mA
-890.9mV  9.653mA    7.899mA    11.31mA
-818.2mV  6.214mA    4.114mA    7.414mA
-636.4mV  2.183mA    1.307mA    2.238mA
-418.2mV  83.85uA    105.2uA    35.14uA
1.764V    -1.228nA   -79.12nA   -1.453nA
[Pulldown]
-1.8V     -1.718A    -2.61A     -1.406A
-1.2V     -527.4mA   -844.5mA   -339.9mA
-1.145V   -396mA     -683.1mA   -229.1mA
-1.091V   -269mA     -526.7mA   -127.5mA
-1.036V   -153.6mA   -378.9mA   -51.17mA
-981.8mV  -66.34mA   -245.6mA   -22.67mA
-927.3mV  -26mA      -136.2mA   -21.54mA
-872.7mV  -19.34mA   -61.98mA   -23.69mA
-763.6mV  -27.2mA    -19.05mA   -36.72mA
-545.5mV  -31.39mA   -18.17mA   -45.46mA
872.7mV   23.46mA    11.88mA    35.92mA
3.545V    25.34mA    12.51mA    41.58mA
[Pullup]
-1.8V     2.903mA    2.423mA    4.112mA
-1.418V   6.595mA    4.711mA    12.64mA
-1.255V   12.69mA    7.42mA     33.23mA
-1.091V   30.4mA     13mA       58.69mA
-981.8mV  40.63mA    17.02mA    61.3mA
-818.2mV  35.38mA    18.12mA    50.59mA
272.7mV   -9.18mA    -4.728mA   -14.55mA
1.255V    -29.75mA   -15.09mA   -48.97mA
2.564V    -34.17mA   -16.31mA   -57.57mA
2.782V    -30.25mA   -15.5mA    -57.48mA
3.055V    -23.63mA   -14.68mA   -38.61mA
3.545V    -19.25mA   -13.56mA   -31.41mA
[GND_clamp]
-1.8V     -2.82A     -1.192A    -3.165A
-1.073V   -235.7mA   -138.4mA   -192.1mA
-1.036V   -159.5mA   -110.8mA   -107.5mA
-1V       -103.8mA   -87.85mA   -60.67mA
-963.6mV  -60mA      -67.28mA   -29.8mA
-927.3mV  -28.21mA   -49.08mA   -14.9mA
-890.9mV  -15.9mA    -35.48mA   -10.99mA
-854.5mV  -8.138mA   -24.07mA   -8.449mA
-818.2mV  -4.924mA   -14.85mA   -7.266mA
-709.1mV  -2.784mA   -3.064mA   -4.883mA
-563.6mV  -570.2uA   -404.5uA   -1.092mA
1.764V    -11.02pA   583.5nA    3.035nA
[Ramp]
dV/dt_f  0.6529896/4.909761n   0.3692621/12.66706n   0.8193344/1.977589n
dV/dt_r  0.6501228/4.543185n   0.3999605/10.404n   0.8221216/2.278462n
R_load = 50
[Rising Waveform]
R_fixture = 50
V_fixture = 1.8
V_fixture_min = 1.62
V_fixture_max = 1.89
0s        717.7mV    1.009V     531.8mV
144ps     718.8mV    1.009V     671.8mV
261ps     713.5mV    1.009V     1.457V
315ps     746.9mV    1.009V     1.689V
486ps     1.271V     1.012V     1.863V
594ps     1.626V     1.003V     1.877V
684ps     1.737V     1.007V     1.88V
1.143ns   1.793V     1.487V     1.884V
1.35ns    1.795V     1.597V     1.884V
6.048ns   1.799V     1.618V     1.889V
[Rising Waveform]
R_fixture = 50
V_fixture = 0
V_fixture_min = 0
V_fixture_max = 0
0s        114.8uV    110.5uV    -7.869mV
945ps     -2.721mV   -6.788mV   41.33mV
1.719ns   25.06mV    -2.062mV   367.5mV
2.817ns   212.5mV    1.319mV    821.3mV
3.753ns   391mV      13.91mV    1.076V
5.004ns   601.1mV    60.97mV    1.211V
7.146ns   840.2mV    179.8mV    1.292V
13.82ns   1.023V     462.5mV    1.342V
22.76ns   1.06V      595.4mV    1.348V
65.79ns   1.067V     655.8mV    1.349V
[Falling Waveform]
R_fixture = 50
V_fixture = 1.8
V_fixture_min = 1.62
V_fixture_max = 1.89
0s        1.8V       1.62V      1.889V
1.179ns   1.806V     1.62V      1.825V
2.799ns   1.737V     1.624V     1.055V
3.798ns   1.588V     1.625V     747.7mV
6.381ns   1.183V     1.597V     566.4mV
10.04ns   855.6mV    1.476V     534.9mV
15.36ns   746.1mV    1.284V     530.1mV
22.03ns   722.4mV    1.133V     529.8mV
30.58ns   718.1mV    1.051V     529.8mV
63.09ns   717.6mV    1.011V     529.8mV
[Falling Waveform]
R_fixture = 50
V_fixture = 0
V_fixture_min = 0
V_fixture_max = 0
0s        1.068V     657.3mV    1.349V
441ps     1.071V     657.5mV    1.33V
774ps     1.058V     657.7mV    1.193V
936ps     1.029V     660mV      1.011V
1.395ns   826.9mV    665.5mV    167.3mV
1.584ns   661.2mV    657.3mV    20.93mV
2.142ns   165mV      583.5mV    1.197mV
2.448ns   26.52mV    508.3mV    566.6uV
4.005ns   718.9uV    40.93mV    165.6uV
6.183ns   248.7uV    1.637mV    63.73uV
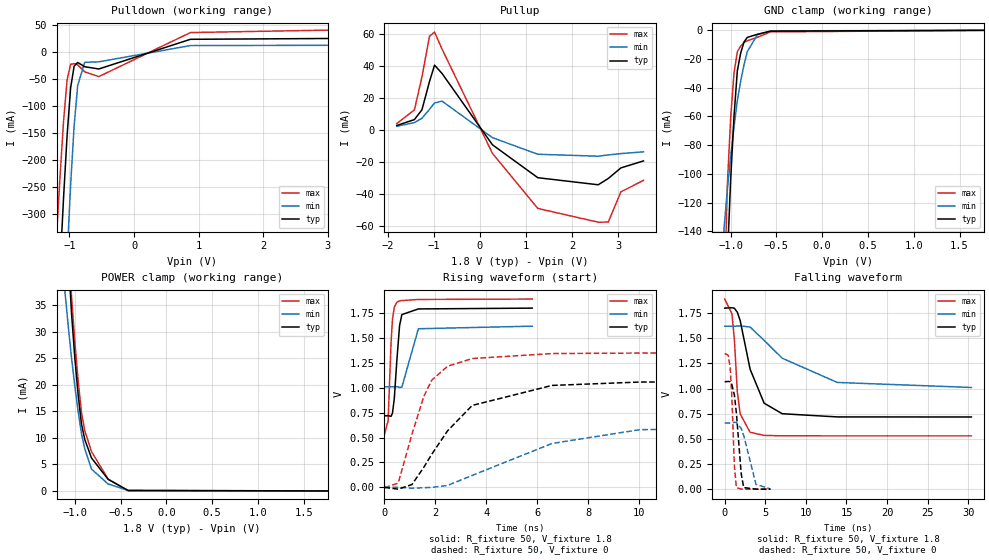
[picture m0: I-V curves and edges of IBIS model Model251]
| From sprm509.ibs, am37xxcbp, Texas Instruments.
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| Model based on original model for BQ18OMAPSMART1HYFBPB_SSBHV
|   Sub model PB_VS00L11_PUPD0_1P8
[model]   Model251
|[Input Load]   PI
|[Output Drive] SC00LB11
|Voltage   1.8V
|Mode   I/O
Model_type   I/O
Polarity   Non-Inverting
Enable   Active-Low
Vinl =  0.63
Vinh =  1.17
Cref =  15pF
Rref =  100.0000M
Vref =  0V
Vmeas =  0.9
C_comp   1.429432p   1.270657p   1.602015p
[Model Spec]
Vinl   0.63   0.567   0.6615
Vinh   1.17   1.053   1.2285
[Temperature Range]   25   125   -40
[Voltage Range]   1.8   1.62   1.89
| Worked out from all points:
|   slope of the pulldown table from 0 to 0.27 V, typ, clamps not added: 24.3 ohm
|   slope of the pullup table from 0 to 0.27 V, typ, clamps not added: 29.7 ohm
|   GND clamp passes 1 mA (typ) near -0.60 V on its own axis
|   POWER clamp passes 1 mA (typ) near -0.56 V on its own axis
|   rising waveform, R_fixture 50, V_fixture 1.8: 20-80 % time 177ps typ, 308ps min, 125ps max; typ from 0.718 V to 1.8 V
|   rising waveform, R_fixture 50, V_fixture 0: 20-80 % time 2.07ns typ, 4.62ns min, 1.07ns max; typ from 0 V to 1.07 V
|   falling waveform, R_fixture 50, V_fixture 1.8: 20-80 % time 2.1ns typ, 5.91ns min, 728ps max; typ from 1.8 V to 0.718 V
|   falling waveform, R_fixture 50, V_fixture 0: 20-80 % time 636ps typ, 1.14ns min, 381ps max; typ from 1.07 V to 0 V
[POWER_clamp]
-1.8V     362.5mA    191.4mA    412.8mA
-1.109V   56.69mA    37.71mA    60.38mA
-1.073V   44.6mA     31.22mA    47.8mA
-1.036V   33.44mA    25.04mA    36.59mA
-1V       24.98mA    19.72mA    28.06mA
-963.6mV  18.03mA    14.96mA    20.78mA
-927.3mV  12.59mA    10.77mA    14.74mA
-890.9mV  9.653mA    7.899mA    11.31mA
-818.2mV  6.214mA    4.114mA    7.414mA
-636.4mV  2.183mA    1.307mA    2.238mA
-418.2mV  83.85uA    105.2uA    35.14uA
1.764V    -1.228nA   -79.12nA   -1.453nA
[Pulldown]
-1.8V     -1.718A    -2.61A     -1.406A
-1.2V     -527.4mA   -844.5mA   -339.9mA
-1.145V   -396mA     -683.1mA   -229.1mA
-1.091V   -269mA     -526.7mA   -127.5mA
-1.036V   -153.6mA   -378.9mA   -51.17mA
-981.8mV  -66.34mA   -245.6mA   -22.67mA
-927.3mV  -26mA      -136.2mA   -21.54mA
-872.7mV  -19.34mA   -61.98mA   -23.69mA
-763.6mV  -27.2mA    -19.05mA   -36.72mA
-545.5mV  -31.39mA   -18.17mA   -45.46mA
872.7mV   23.46mA    11.88mA    35.92mA
3.545V    25.34mA    12.51mA    41.58mA
[Pullup]
-1.8V     2.903mA    2.423mA    4.112mA
-1.418V   6.595mA    4.711mA    12.64mA
-1.255V   12.69mA    7.42mA     33.23mA
-1.091V   30.4mA     13mA       58.69mA
-981.8mV  40.63mA    17.02mA    61.3mA
-818.2mV  35.38mA    18.12mA    50.59mA
272.7mV   -9.18mA    -4.728mA   -14.55mA
1.255V    -29.75mA   -15.09mA   -48.97mA
2.564V    -34.17mA   -16.31mA   -57.57mA
2.782V    -30.25mA   -15.5mA    -57.48mA
3.055V    -23.63mA   -14.68mA   -38.61mA
3.545V    -19.25mA   -13.56mA   -31.41mA
[GND_clamp]
-1.8V     -2.82A     -1.192A    -3.165A
-1.073V   -235.7mA   -138.4mA   -192.1mA
-1.036V   -159.5mA   -110.8mA   -107.5mA
-1V       -103.8mA   -87.85mA   -60.67mA
-963.6mV  -60mA      -67.28mA   -29.8mA
-927.3mV  -28.21mA   -49.08mA   -14.9mA
-890.9mV  -15.9mA    -35.48mA   -10.99mA
-854.5mV  -8.138mA   -24.07mA   -8.449mA
-818.2mV  -4.924mA   -14.85mA   -7.266mA
-709.1mV  -2.784mA   -3.064mA   -4.883mA
-563.6mV  -570.2uA   -404.5uA   -1.092mA
1.764V    -11.02pA   583.5nA    3.035nA
[Ramp]
dV/dt_f  0.6521685/2.099634n   0.3687078/5.951843n   0.8185671/0.7264657n
dV/dt_r  0.6518191/2.08067n   0.400854/4.66815n   0.8244316/1.071271n
R_load = 50
[Rising Waveform]
R_fixture = 50
V_fixture = 1.8
V_fixture_min = 1.62
V_fixture_max = 1.89
0s        717.7mV    1.009V     531.6mV
144ps     718.8mV    1.009V     668mV
261ps     713.1mV    1.009V     1.459V
315ps     744.4mV    1.009V     1.687V
387ps     891.4mV    1.01V      1.808V
486ps     1.27V      1.011V     1.858V
594ps     1.624V     1.003V     1.872V
684ps     1.734V     1.006V     1.875V
1.332ns   1.791V     1.592V     1.886V
5.805ns   1.799V     1.618V     1.89V
[Rising Waveform]
R_fixture = 50
V_fixture = 0
V_fixture_min = 0
V_fixture_max = 0
0s        -338.3uV   80.58uV    -3.447mV
540ps     -18.29mV   764.1uV    41.89mV
1.08ns    28.21mV    -9.148mV   533mV
1.548ns   202.1mV    -3.854mV   914mV
1.854ns   330.6mV    -494.1uV   1.075V
2.475ns   566.5mV    19.08mV    1.215V
3.447ns   822.4mV    119.9mV    1.293V
6.579ns   1.023V     440.5mV    1.343V
10.02ns   1.057V     578.7mV    1.348V
30.43ns   1.067V     655.8mV    1.349V
[Falling Waveform]
R_fixture = 50
V_fixture = 1.8
V_fixture_min = 1.62
V_fixture_max = 1.89
0s        1.8V       1.62V      1.89V
891ps     1.804V     1.62V      1.744V
1.188ns   1.799V     1.62V      1.493V
1.557ns   1.759V     1.622V     965.2mV
1.908ns   1.676V     1.623V     747.8mV
3.132ns   1.192V     1.612V     565.3mV
4.86ns    854.6mV    1.479V     534.6mV
7.083ns   750mV      1.302V     530.2mV
13.87ns   718.3mV    1.061V     529.8mV
30.39ns   717.6mV    1.011V     529.8mV
[Falling Waveform]
R_fixture = 50
V_fixture = 0
V_fixture_min = 0
V_fixture_max = 0
0s        1.068V     657.3mV    1.349V
441ps     1.071V     657.5mV    1.331V
675ps     1.068V     657.3mV    1.207V
873ps     1.043V     658.5mV    937.9mV
1.197ns   934.9mV    664.2mV    223.6mV
1.44ns    757mV      663.2mV    15.15mV
2.034ns   152.2mV    603.4mV    806.2uV
2.34ns    16.02mV    533.5mV    342uV
3.852ns   416.4uV    47.86mV    41.34uV
5.634ns   127.4uV    1.638mV    7.985uV
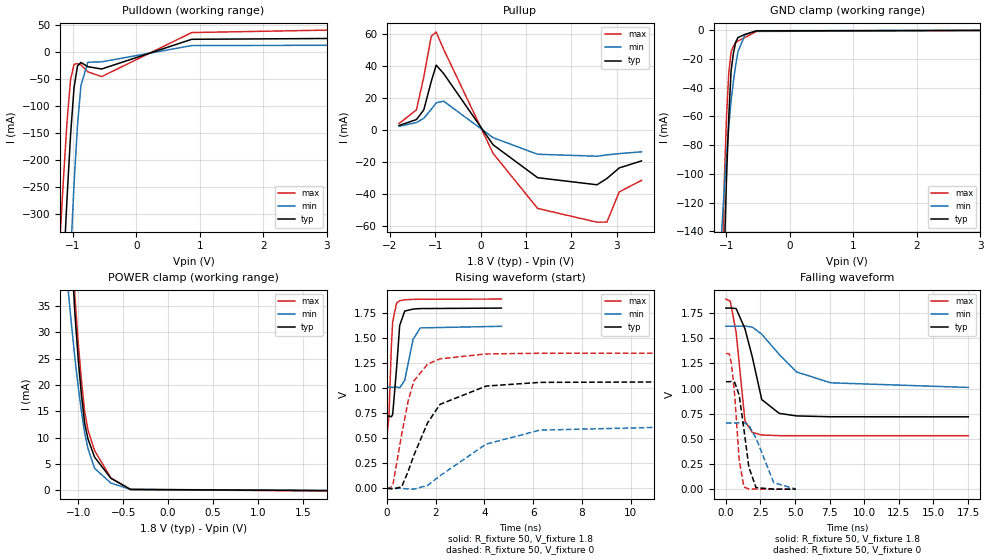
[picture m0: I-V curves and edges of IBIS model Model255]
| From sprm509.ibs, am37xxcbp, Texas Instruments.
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| Model based on original model for BQ18OMAPSMART1HYFBPB_SSBHV
|   Sub model FBPB_VS10L10_PU1_1P8
[model]   Model255
|[Input Load]   PU
|[Output Drive] SC10LB10
|Voltage   1.8V
|Mode   I/O
Model_type   I/O
Polarity   Non-Inverting
Enable   Active-Low
Vinl =  0.63
Vinh =  1.17
Cref =  15pF
Rref =  100.0000M
Vref =  0V
Vmeas =  0.9
C_comp   1.429432p   1.270657p   1.602015p
[Model Spec]
Vinl   0.63   0.567   0.6615
Vinh   1.17   1.053   1.2285
[Temperature Range]   25   125   -40
[Voltage Range]   1.8   1.62   1.89
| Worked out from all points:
|   slope of the pulldown table from 0 to 0.27 V, typ, clamps not added: 24.3 ohm
|   slope of the pullup table from 0 to 0.27 V, typ, clamps not added: 29.7 ohm
|   GND clamp passes 1 mA (typ) near -0.60 V on its own axis
|   POWER clamp passes 1 mA (typ) near -0.56 V on its own axis
|   rising waveform, R_fixture 50, V_fixture 1.8: 20-80 % time 177ps typ, 306ps min, 125ps max; typ from 0.72 V to 1.8 V
|   rising waveform, R_fixture 50, V_fixture 0: 20-80 % time 1.32ns typ, 2.85ns min, 702ps max; typ from 0.001 V to 1.07 V
|   falling waveform, R_fixture 50, V_fixture 1.8: 20-80 % time 1.05ns typ, 2.67ns min, 599ps max; typ from 1.8 V to 0.72 V
|   falling waveform, R_fixture 50, V_fixture 0: 20-80 % time 602ps typ, 1.02ns min, 433ps max; typ from 1.07 V to 0.001 V
[POWER_clamp]
-1.8V     362.5mA    191.4mA    412.8mA
-1.109V   56.76mA    37.74mA    60.51mA
-1.073V   44.67mA    31.25mA    47.93mA
-1.036V   33.52mA    25.07mA    36.72mA
-1V       25.06mA    19.75mA    28.2mA
-963.6mV  18.11mA    14.99mA    20.91mA
-927.3mV  12.67mA    10.8mA     14.87mA
-890.9mV  9.734mA    7.935mA    11.44mA
-818.2mV  6.293mA    4.153mA    7.536mA
-636.4mV  2.249mA    1.342mA    2.34mA
-418.2mV  128.7uA    129.3uA    104.4uA
1.764V    -96.73uA   -46.48uA   -163.5uA
[Pulldown]
-1.8V     -1.718A    -2.61A     -1.406A
-1.2V     -527.4mA   -844.5mA   -339.9mA
-1.145V   -396mA     -683.1mA   -229.1mA
-1.091V   -269mA     -526.7mA   -127.5mA
-1.036V   -153.6mA   -378.9mA   -51.17mA
-981.8mV  -66.33mA   -245.6mA   -22.67mA
-927.3mV  -26mA      -136.2mA   -21.54mA
-872.7mV  -19.34mA   -61.98mA   -23.69mA
-763.6mV  -27.2mA    -19.05mA   -36.72mA
-545.5mV  -31.39mA   -18.17mA   -45.46mA
872.7mV   23.46mA    11.88mA    35.92mA
3.545V    25.34mA    12.51mA    41.58mA
[Pullup]
-1.8V     2.903mA    2.423mA    4.112mA
-1.418V   6.595mA    4.711mA    12.64mA
-1.255V   12.69mA    7.42mA     33.24mA
-1.091V   30.4mA     13mA       58.69mA
-981.8mV  40.63mA    17.02mA    61.3mA
-818.2mV  35.38mA    18.12mA    50.59mA
272.7mV   -9.179mA   -4.728mA   -14.55mA
1.255V    -29.75mA   -15.09mA   -48.97mA
2.564V    -34.17mA   -16.31mA   -57.57mA
2.782V    -30.25mA   -15.5mA    -57.49mA
3.055V    -23.63mA   -14.68mA   -38.61mA
3.545V    -19.25mA   -13.56mA   -31.41mA
[GND_clamp]
-1.8V     -2.82A     -1.192A    -3.165A
-1.073V   -235.8mA   -138.4mA   -192.1mA
-1.036V   -159.6mA   -110.8mA   -107.6mA
-1V       -103.8mA   -87.86mA   -60.73mA
-963.6mV  -60.04mA   -67.29mA   -29.86mA
-927.3mV  -28.26mA   -49.09mA   -14.98mA
-890.9mV  -15.95mA   -35.49mA   -11.09mA
-854.5mV  -8.198mA   -24.09mA   -8.559mA
-818.2mV  -4.99mA    -14.87mA   -7.387mA
-709.1mV  -2.858mA   -3.093mA   -5.012mA
-527.3mV  -395.6uA   -260.4uA   -751.2uA
3.6V      0A         0A         0A
[Ramp]
dV/dt_f  0.6500166/1.04936n   0.3671708/2.697772n   0.8166306/0.6006026n
dV/dt_r  0.6497146/1.318412n   0.4003914/2.878168n   0.8205076/0.7029198n
R_load = 50
[Rising Waveform]
R_fixture = 50
V_fixture = 1.8
V_fixture_min = 1.62
V_fixture_max = 1.89
0s        719.5mV    1.011V     531.2mV
81ps      721.4mV    1.011V     714.7mV
180ps     714.3mV    1.01V      1.411V
234ps     736.8mV    1.01V      1.663V
396ps     1.204V     1.012V     1.85V
522ps     1.626V     1.004V     1.873V
729ps     1.77V      1.079V     1.883V
1.071ns   1.79V      1.487V     1.887V
1.368ns   1.795V     1.602V     1.888V
4.698ns   1.8V       1.618V     1.89V
[Rising Waveform]
R_fixture = 50
V_fixture = 0
V_fixture_min = 0
V_fixture_max = 0
0s        1.14mV     1.075mV    -8.41mV
234ps     -7.17mV    546.4uV    22.79mV
603ps     13.78mV    -1.513mV   536.1mV
873ps     171.2mV    -6.795mV   876mV
1.107ns   331.1mV    -8.562mV   1.073V
1.665ns   652.9mV    28.55mV    1.24V
2.178ns   838.4mV    125.7mV    1.293V
4.068ns   1.021V     441.5mV    1.342V
6.282ns   1.058V     581.2mV    1.349V
19.74ns   1.069V     657.1mV    1.35V
[Falling Waveform]
R_fixture = 50
V_fixture = 1.8
V_fixture_min = 1.62
V_fixture_max = 1.89
0s        1.8V       1.62V      1.89V
315ps     1.801V     1.62V      1.869V
738ps     1.796V     1.62V      1.561V
1.377ns   1.595V     1.622V     679mV
1.908ns   1.315V     1.612V     564.3mV
2.592ns   891.2mV    1.541V     539.7mV
3.852ns   754.7mV    1.34V      533.1mV
5.103ns   729.1mV    1.166V     532.6mV
7.569ns   720.7mV    1.058V     532.6mV
17.52ns   720mV      1.012V     532.6mV
[Falling Waveform]
R_fixture = 50
V_fixture = 0
V_fixture_min = 0
V_fixture_max = 0
0s        1.069V     658.6mV    1.35V
243ps     1.069V     659mV      1.346V
405ps     1.072V     658.9mV    1.247V
639ps     1.062V     658.8mV    931mV
963ps     934mV      661.1mV    289.6mV
1.305ns   593.9mV    661.1mV    22.51mV
1.656ns   222.4mV    636.5mV    3.626mV
2.178ns   16.68mV    509.1mV    2.004mV
3.456ns   1.763mV    65.87mV    1.779mV
5.058ns   1.449mV    2.597mV    1.773mV
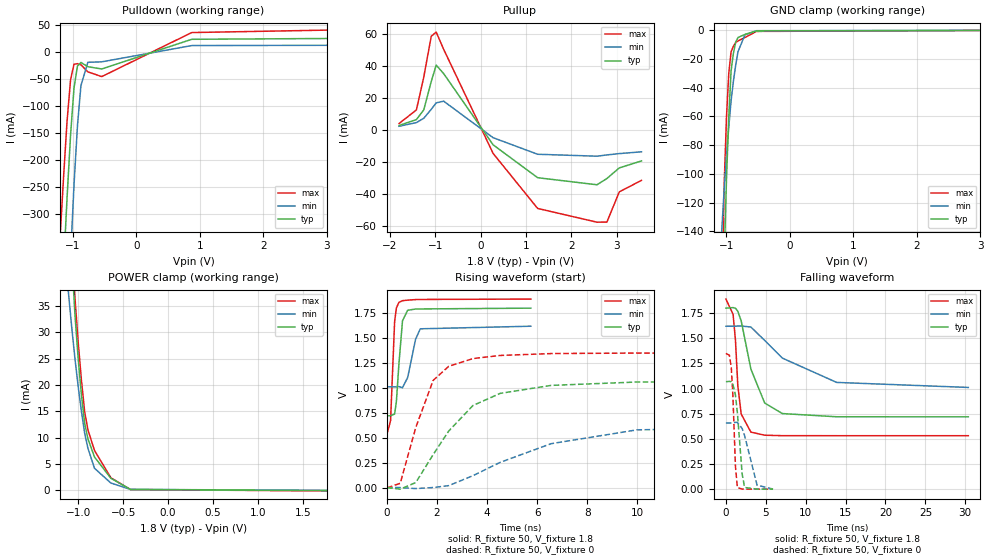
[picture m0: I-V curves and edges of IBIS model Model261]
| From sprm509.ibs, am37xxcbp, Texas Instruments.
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| Model based on original model for BQ18OMAPSMART1HYFBPB_SSBHV
|   Sub model FBPB_VS00L11_PU1_1P8
[model]   Model261
|[Input Load]   PU
|[Output Drive] SC00LB11
|Voltage   1.8V
|Mode   I/O
Model_type   I/O
Polarity   Non-Inverting
Enable   Active-Low
Vinl =  0.63
Vinh =  1.17
Cref =  15pF
Rref =  100.0000M
Vref =  0V
Vmeas =  0.9
C_comp   1.429432p   1.270657p   1.602015p
[Model Spec]
Vinl   0.63   0.567   0.6615
Vinh   1.17   1.053   1.2285
[Temperature Range]   25   125   -40
[Voltage Range]   1.8   1.62   1.89
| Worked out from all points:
|   slope of the pulldown table from 0 to 0.27 V, typ, clamps not added: 24.3 ohm
|   slope of the pullup table from 0 to 0.27 V, typ, clamps not added: 29.7 ohm
|   GND clamp passes 1 mA (typ) near -0.60 V on its own axis
|   POWER clamp passes 1 mA (typ) near -0.56 V on its own axis
|   rising waveform, R_fixture 50, V_fixture 1.8: 20-80 % time 176ps typ, 308ps min, 124ps max; typ from 0.72 V to 1.8 V
|   rising waveform, R_fixture 50, V_fixture 0: 20-80 % time 2.07ns typ, 4.62ns min, 1.06ns max; typ from 0.001 V to 1.07 V
|   falling waveform, R_fixture 50, V_fixture 1.8: 20-80 % time 2.1ns typ, 5.91ns min, 729ps max; typ from 1.8 V to 0.72 V
|   falling waveform, R_fixture 50, V_fixture 0: 20-80 % time 637ps typ, 1.14ns min, 382ps max; typ from 1.07 V to 0.002 V
[POWER_clamp]
-1.8V     362.5mA    191.4mA    412.8mA
-1.109V   56.76mA    37.74mA    60.51mA
-1.073V   44.67mA    31.25mA    47.93mA
-1.036V   33.52mA    25.07mA    36.72mA
-1V       25.06mA    19.75mA    28.2mA
-963.6mV  18.11mA    14.99mA    20.91mA
-927.3mV  12.67mA    10.8mA     14.87mA
-890.9mV  9.734mA    7.935mA    11.44mA
-818.2mV  6.293mA    4.153mA    7.536mA
-636.4mV  2.249mA    1.342mA    2.34mA
-418.2mV  128.7uA    129.3uA    104.4uA
1.764V    -96.73uA   -46.48uA   -163.5uA
[Pulldown]
-1.8V     -1.718A    -2.61A     -1.406A
-1.2V     -527.4mA   -844.5mA   -339.9mA
-1.145V   -396mA     -683.1mA   -229.1mA
-1.091V   -269mA     -526.7mA   -127.5mA
-1.036V   -153.6mA   -378.9mA   -51.17mA
-981.8mV  -66.33mA   -245.6mA   -22.67mA
-927.3mV  -26mA      -136.2mA   -21.54mA
-872.7mV  -19.34mA   -61.98mA   -23.69mA
-763.6mV  -27.2mA    -19.05mA   -36.72mA
-545.5mV  -31.39mA   -18.17mA   -45.46mA
872.7mV   23.46mA    11.88mA    35.92mA
3.545V    25.34mA    12.51mA    41.58mA
[Pullup]
-1.8V     2.903mA    2.423mA    4.112mA
-1.418V   6.595mA    4.711mA    12.64mA
-1.255V   12.69mA    7.42mA     33.24mA
-1.091V   30.4mA     13mA       58.69mA
-981.8mV  40.63mA    17.02mA    61.3mA
-818.2mV  35.38mA    18.12mA    50.59mA
272.7mV   -9.179mA   -4.728mA   -14.55mA
1.255V    -29.75mA   -15.09mA   -48.97mA
2.564V    -34.17mA   -16.31mA   -57.57mA
2.782V    -30.25mA   -15.5mA    -57.49mA
3.055V    -23.63mA   -14.68mA   -38.61mA
3.545V    -19.25mA   -13.56mA   -31.41mA
[GND_clamp]
-1.8V     -2.82A     -1.192A    -3.165A
-1.073V   -235.8mA   -138.4mA   -192.1mA
-1.036V   -159.6mA   -110.8mA   -107.6mA
-1V       -103.8mA   -87.86mA   -60.73mA
-963.6mV  -60.04mA   -67.29mA   -29.86mA
-927.3mV  -28.26mA   -49.09mA   -14.98mA
-890.9mV  -15.95mA   -35.49mA   -11.09mA
-854.5mV  -8.198mA   -24.09mA   -8.559mA
-818.2mV  -4.99mA    -14.87mA   -7.387mA
-709.1mV  -2.858mA   -3.093mA   -5.012mA
-527.3mV  -395.6uA   -260.4uA   -751.2uA
3.6V      0A         0A         0A
[Ramp]
dV/dt_f  0.6507484/2.103904n   0.3679488/5.952962n   0.8168807/0.7293045n
dV/dt_r  0.6504611/2.077132n   0.4004677/4.663644n   0.8216493/1.068807n
R_load = 50
[Rising Waveform]
R_fixture = 50
V_fixture = 1.8
V_fixture_min = 1.62
V_fixture_max = 1.89
0s        720mV      1.011V     534.5mV
144ps     721.1mV    1.011V     672mV
306ps     737.8mV    1.01V      1.665V
378ps     868mV      1.011V     1.802V
477ps     1.237V     1.013V     1.856V
621ps     1.673V     1.002V     1.874V
828ps     1.778V     1.104V     1.879V
1.143ns   1.79V      1.487V     1.885V
1.332ns   1.791V     1.592V     1.886V
5.751ns   1.799V     1.618V     1.89V
[Rising Waveform]
R_fixture = 50
V_fixture = 0
V_fixture_min = 0
V_fixture_max = 0
0s        1.049mV    1.046mV    -1.659mV
531ps     -14.58mV   1.847mV    44.17mV
1.152ns   51.85mV    -8.656mV   604.3mV
1.845ns   331.2mV    1.697mV    1.075V
2.466ns   567.4mV    20.76mV    1.216V
3.438ns   823.9mV    121mV      1.294V
4.527ns   945.3mV    254.4mV    1.325V
6.561ns   1.025V     441.3mV    1.344V
9.999ns   1.059V     579.9mV    1.349V
30.41ns   1.069V     657.1mV    1.35V
[Falling Waveform]
R_fixture = 50
V_fixture = 1.8
V_fixture_min = 1.62
V_fixture_max = 1.89
0s        1.8V       1.62V      1.89V
900ps     1.805V     1.62V      1.739V
1.197ns   1.799V     1.62V      1.483V
1.494ns   1.769V     1.622V     1.03V
1.917ns   1.673V     1.623V     748mV
3.132ns   1.194V     1.612V     568.3mV
4.86ns    857.2mV    1.479V     537.5mV
7.083ns   752.5mV    1.303V     533mV
13.88ns   720.7mV    1.062V     532.6mV
30.38ns   720mV      1.012V     532.6mV
[Falling Waveform]
R_fixture = 50
V_fixture = 0
V_fixture_min = 0
V_fixture_max = 0
0s        1.069V     658.7mV    1.35V
441ps     1.072V     658.9mV    1.332V
675ps     1.07V      658.6mV    1.209V
873ps     1.045V     659.8mV    940.8mV
1.197ns   936.9mV    665.5mV    227.4mV
1.44ns    759.8mV    664.5mV    17.56mV
2.034ns   155.6mV    604.9mV    2.797mV
2.34ns    18.5mV     535.2mV    2.253mV
3.906ns   1.951mV    41.33mV    1.83mV
5.904ns   1.549mV    2.598mV    1.781mV
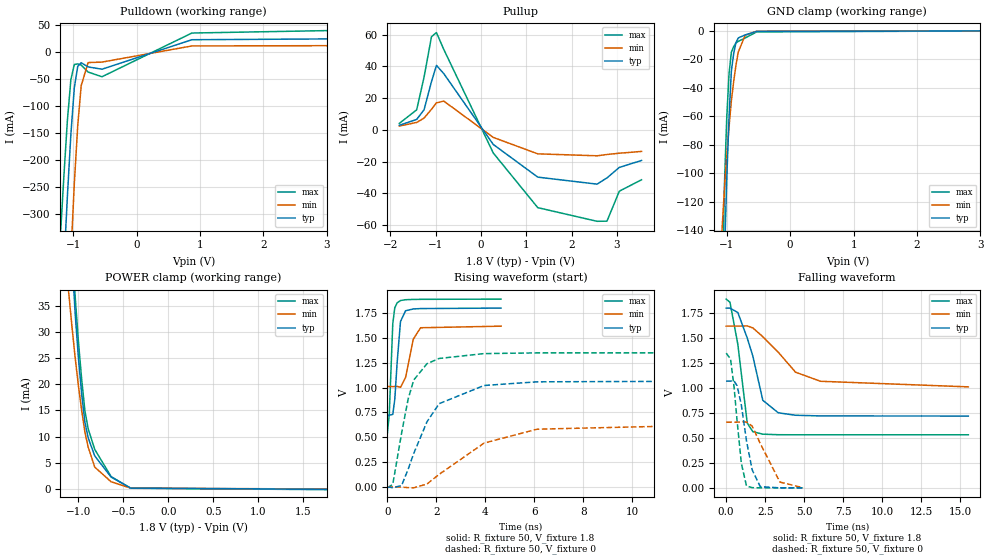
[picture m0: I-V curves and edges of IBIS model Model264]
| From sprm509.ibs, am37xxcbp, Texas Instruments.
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| Model based on original model for BQ18OMAPSMART1HYFBPB_SSBHV
|   Sub model FBPB_VS01L00_PU1_1P8
[model]   Model264
|[Input Load]   PU
|[Output Drive] SC01LB00
|Voltage   1.8V
|Mode   I/O
Model_type   I/O
Polarity   Non-Inverting
Enable   Active-Low
Vinl =  0.63
Vinh =  1.17
Cref =  15pF
Rref =  100.0000M
Vref =  0V
Vmeas =  0.9
C_comp   1.429432p   1.270657p   1.602015p
[Model Spec]
Vinl   0.63   0.567   0.6615
Vinh   1.17   1.053   1.2285
[Temperature Range]   25   125   -40
[Voltage Range]   1.8   1.62   1.89
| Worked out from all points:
|   slope of the pulldown table from 0 to 0.27 V, typ, clamps not added: 24.3 ohm
|   slope of the pullup table from 0 to 0.27 V, typ, clamps not added: 29.7 ohm
|   GND clamp passes 1 mA (typ) near -0.60 V on its own axis
|   POWER clamp passes 1 mA (typ) near -0.56 V on its own axis
|   rising waveform, R_fixture 50, V_fixture 1.8: 20-80 % time 177ps typ, 304ps min, 125ps max; typ from 0.72 V to 1.8 V
|   rising waveform, R_fixture 50, V_fixture 0: 20-80 % time 1.28ns typ, 2.78ns min, 686ps max; typ from 0.001 V to 1.07 V
|   falling waveform, R_fixture 50, V_fixture 1.8: 20-80 % time 1.08ns typ, 2.26ns min, 672ps max; typ from 1.8 V to 0.72 V
|   falling waveform, R_fixture 50, V_fixture 0: 20-80 % time 667ps typ, 1.09ns min, 494ps max; typ from 1.07 V to 0.001 V
[POWER_clamp]
-1.8V     362.5mA    191.4mA    412.8mA
-1.109V   56.76mA    37.74mA    60.51mA
-1.073V   44.67mA    31.25mA    47.93mA
-1.036V   33.52mA    25.07mA    36.72mA
-1V       25.06mA    19.75mA    28.2mA
-963.6mV  18.11mA    14.99mA    20.91mA
-927.3mV  12.67mA    10.8mA     14.87mA
-890.9mV  9.734mA    7.935mA    11.44mA
-818.2mV  6.293mA    4.153mA    7.536mA
-636.4mV  2.249mA    1.342mA    2.34mA
-418.2mV  128.7uA    129.3uA    104.4uA
1.764V    -96.73uA   -46.48uA   -163.5uA
[Pulldown]
-1.8V     -1.718A    -2.61A     -1.406A
-1.2V     -527.4mA   -844.5mA   -339.9mA
-1.145V   -396mA     -683.1mA   -229.1mA
-1.091V   -269mA     -526.7mA   -127.5mA
-1.036V   -153.6mA   -378.9mA   -51.17mA
-981.8mV  -66.33mA   -245.6mA   -22.67mA
-927.3mV  -26mA      -136.2mA   -21.54mA
-872.7mV  -19.34mA   -61.98mA   -23.69mA
-763.6mV  -27.2mA    -19.05mA   -36.72mA
-545.5mV  -31.39mA   -18.17mA   -45.46mA
872.7mV   23.46mA    11.88mA    35.92mA
3.545V    25.34mA    12.51mA    41.58mA
[Pullup]
-1.8V     2.903mA    2.423mA    4.112mA
-1.418V   6.595mA    4.711mA    12.64mA
-1.255V   12.69mA    7.42mA     33.24mA
-1.091V   30.4mA     13mA       58.69mA
-981.8mV  40.63mA    17.02mA    61.3mA
-818.2mV  35.38mA    18.12mA    50.59mA
272.7mV   -9.179mA   -4.728mA   -14.55mA
1.255V    -29.75mA   -15.09mA   -48.97mA
2.564V    -34.17mA   -16.31mA   -57.57mA
2.782V    -30.25mA   -15.5mA    -57.49mA
3.055V    -23.63mA   -14.68mA   -38.61mA
3.545V    -19.25mA   -13.56mA   -31.41mA
[GND_clamp]
-1.8V     -2.82A     -1.192A    -3.165A
-1.073V   -235.8mA   -138.4mA   -192.1mA
-1.036V   -159.6mA   -110.8mA   -107.6mA
-1V       -103.8mA   -87.86mA   -60.73mA
-963.6mV  -60.04mA   -67.29mA   -29.86mA
-927.3mV  -28.26mA   -49.09mA   -14.98mA
-890.9mV  -15.95mA   -35.49mA   -11.09mA
-854.5mV  -8.198mA   -24.09mA   -8.559mA
-818.2mV  -4.99mA    -14.87mA   -7.387mA
-709.1mV  -2.858mA   -3.093mA   -5.012mA
-527.3mV  -395.6uA   -260.4uA   -751.2uA
3.6V      0A         0A         0A
[Ramp]
dV/dt_f  0.6498524/1.078394n   0.3669165/2.279072n   0.8165813/0.6744719n
dV/dt_r  0.6495045/1.286958n   0.4003322/2.803659n   0.8201479/0.6874595n
R_load = 50
[Rising Waveform]
R_fixture = 50
V_fixture = 1.8
V_fixture_min = 1.62
V_fixture_max = 1.89
0s        719.5mV    1.011V     531mV
81ps      721.3mV    1.011V     724.8mV
225ps     730.5mV    1.01V      1.642V
306ps     878.3mV    1.011V     1.802V
405ps     1.257V     1.012V     1.853V
540ps     1.665V     1.003V     1.876V
747ps     1.773V     1.101V     1.884V
1.062ns   1.791V     1.486V     1.887V
1.359ns   1.795V     1.602V     1.888V
4.644ns   1.8V       1.618V     1.89V
[Rising Waveform]
R_fixture = 50
V_fixture = 0
V_fixture_min = 0
V_fixture_max = 0
0s        1.149mV    1.075mV    -8.869mV
225ps     -7.253mV   558.8uV    26.19mV
585ps     14.7mV     -1.152mV   542.2mV
855ps     179.9mV    -6.833mV   887.2mV
1.08ns    337.2mV    -8.463mV   1.076V
1.62ns    655.2mV    29.48mV    1.24V
2.115ns   838mV      126.8mV    1.293V
3.951ns   1.021V     441.5mV    1.342V
6.111ns   1.058V     581.3mV    1.349V
19.23ns   1.069V     657.1mV    1.35V
[Falling Waveform]
R_fixture = 50
V_fixture = 1.8
V_fixture_min = 1.62
V_fixture_max = 1.89
0s        1.8V       1.62V      1.89V
243ps     1.8V       1.62V      1.859V
747ps     1.756V     1.62V      1.438V
1.35ns    1.501V     1.622V     650.1mV
1.71ns    1.32V      1.602V     563.7mV
2.349ns   877.8mV    1.514V     538.8mV
3.339ns   752.6mV    1.359V     533.2mV
4.446ns   728.1mV    1.159V     532.6mV
6.048ns   721.2mV    1.068V     532.6mV
15.53ns   720mV      1.012V     532.6mV
[Falling Waveform]
R_fixture = 50
V_fixture = 0
V_fixture_min = 0
V_fixture_max = 0
0s        1.069V     658.6mV    1.35V
279ps     1.07V      659mV      1.291V
504ps     1.072V     658.8mV    1.013V
702ps     1.023V     658.9mV    669.3mV
972ps     831.1mV    661.6mV    246.5mV
1.305ns   468.9mV    660.7mV    19.53mV
1.674ns   178.8mV    617.5mV    3.317mV
2.187ns   13.24mV    445.1mV    1.949mV
3.447ns   1.69mV     59.44mV    1.775mV
4.932ns   1.436mV    2.603mV    1.773mV
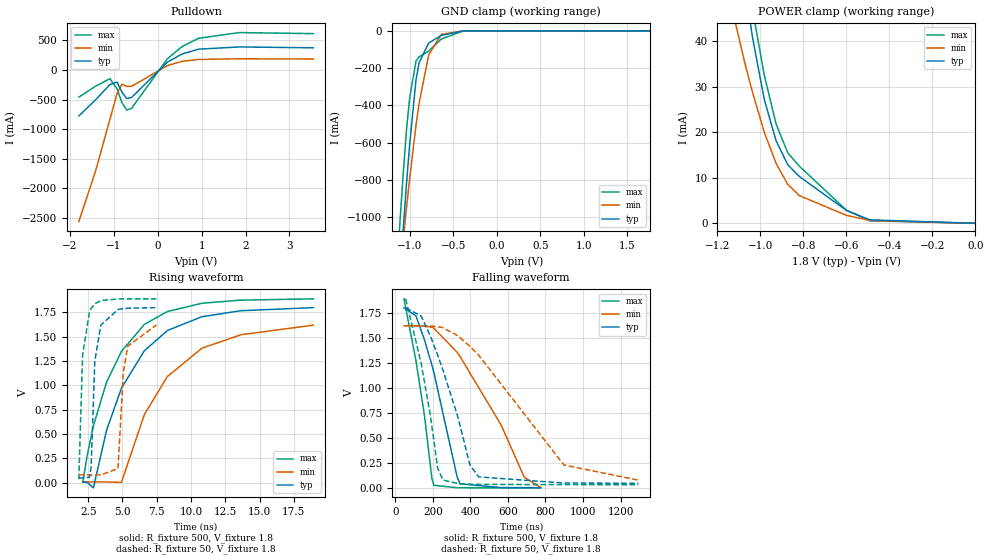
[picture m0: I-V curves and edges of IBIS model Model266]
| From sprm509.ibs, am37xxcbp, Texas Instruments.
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| Model based on original model for BQOMAPI2CHYFBPBRESNOPM_SSBHV
|   Sub model BQOMAPI2CHYRES_STD_POFF_00_1P8
[model]   Model266
|[Input Load]   PI
|[Output Drive] LB00
|Voltage   1.8V
|Mode   I/O_OPEN_DRAIN
Model_type   I/O_open_drain
Polarity   Non-Inverting
Enable   Active-Low
Vinl =  0.567
Vinh =  1.323
Cref =  400.0000PF
Rref =  500.0000
Vref =  1.8V
Vmeas =  0.9
C_comp   3.856143p   3.721565p   3.857354p
[Model Spec]
Vinl   0.567   0.567   0.567
Vinh   1.323   1.323   1.323
[Temperature Range]   25   125   -40
[Voltage Range]   1.8   1.62   1.89
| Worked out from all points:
|   slope of the pulldown table from 0 to 0.27 V, typ, clamps not added: 1.71 ohm
|   GND clamp passes 1 mA (typ) near -0.44 V on its own axis
|   POWER clamp passes 1 mA (typ) near -0.51 V on its own axis
|   rising waveform, R_fixture 500, V_fixture 1.8: 20-80 % time 3.64ns typ, 4.19ns min, 3.19ns max; typ from 0.005 V to 1.8 V
|   rising waveform, R_fixture 50, V_fixture 1.8: 20-80 % time 374ps typ, 410ps min, 341ps max; typ from 0.049 V to 1.8 V
|   falling waveform, R_fixture 500, V_fixture 1.8: 20-80 % time 143ns typ, 286ns min, 90.7ns max; typ from 1.8 V to 0.005 V
|   falling waveform, R_fixture 50, V_fixture 1.8: 20-80 % time 172ns typ, 379ns min, 102ns max; typ from 1.8 V to 0.049 V
[POWER_clamp]
-1.8V     401.1mA    209.4mA    454.2mA
-1.145V   79.39mA    49.82mA    86.39mA
-1.073V   52.49mA    35.39mA    58.76mA
-1.055V   46.58mA    32.04mA    52.82mA
-1.036V   40.67mA    28.68mA    46.87mA
-981.8mV  27.2mA     20.01mA    32.52mA
-927.3mV  18.17mA    13.19mA    21.87mA
-872.7mV  12.87mA    8.554mA    15.48mA
-818.2mV  10.26mA    6.071mA    12.52mA
-600mV    2.834mA    1.747mA    2.888mA
-490.9mV  760.8uA    616.2uA    563.4uA
0V        4.894nA    26.6nA     13.41nA
[Pulldown]
-1.8V     -777mA     -2.558A    -458.4mA
-1.418V   -503.6mA   -1.704A    -274.1mA
-1.091V   -246mA     -833.2mA   -147.3mA
-927.3mV  -205.8mA   -396mA     -321mA
-818.2mV  -374mA     -240.1mA   -549mA
-709.1mV  -482.3mA   -277.9mA   -676.6mA
-600mV    -464.9mA   -277.2mA   -648.9mA
218.2mV   131.5mA    73.81mA    188.3mA
545.5mV   267.7mA    144.1mA    391.8mA
927.3mV   351.1mA    177.8mA    534.4mA
1.855V    388.5mA    188.1mA    630.8mA
3.545V    373.8mA    185.1mA    612.9mA
[GND_clamp]
-1.8V     -6.905A    -5.48A     -6.849A
-1.145V   -1.563A    -1.472A    -1.273A
-1.109V   -1.305A    -1.292A    -1.009A
-1.073V   -1.058A    -1.118A    -761.8mA
-1.036V   -819.4mA   -948.6mA   -530.3mA
-1V       -610.5mA   -793.2mA   -361.6mA
-927.3mV  -263.9mA   -507.2mA   -161.9mA
-890.9mV  -170.2mA   -389mA     -139.4mA
-781.8mV  -65.52mA   -129.8mA   -108.5mA
-636.4mV  -24.47mA   -18.9mA    -43.94mA
-381.8mV  -239.7uA   -254uA     -441.8uA
1.764V    2.8nA      2.224uA    11.77nA
[Ramp]
dV/dt_f  1.0820356/0.14390073u 0.96978706/0.28629533u  1.1398929/91.417989n
dV/dt_r 0.13494786/0.10742857n 0.11653513/0.21330631n 0.14022449/65.032816p
R_load = 528.00
[Rising Waveform]
R_fixture = 500
V_fixture = 1.8
V_fixture_min = 1.62
V_fixture_max = 1.89
2.107ns   4.858mV    7.865mV    3.483mV
2.428ns   2.566mV    7.865mV    283.7mV
2.877ns   -53.33mV   7.864mV    583.7mV
3.84ns    540.4mV    7.927mV    1.035V
4.923ns   972mV      2.873mV    1.35V
6.599ns   1.357V     701.7mV    1.628V
8.279ns   1.565V     1.092V     1.76V
10.8ns    1.707V     1.383V     1.845V
13.64ns   1.768V     1.521V     1.877V
18.93ns   1.8V       1.62V      1.89V
[Rising Waveform]
R_fixture = 50
V_fixture = 1.8
V_fixture_min = 1.62
V_fixture_max = 1.89
1.812ns   48.93mV    79.48mV    35.04mV
2.089ns   48.93mV    79.48mV    1.31V
2.591ns   55.29mV    79.48mV    1.759V
2.709ns   155.1mV    79.48mV    1.791V
2.981ns   1.254V     79.48mV    1.839V
3.423ns   1.621V     79.48mV    1.873V
4.672ns   1.78V      145.6mV    1.889V
5.055ns   1.79V      1.126V     1.89V
5.384ns   1.794V     1.404V     1.89V
7.467ns   1.8V       1.62V      1.89V
[Falling Waveform]
R_fixture = 500
V_fixture = 1.8
V_fixture_min = 1.62
V_fixture_max = 1.89
46.23ns   1.8V       1.62V      1.89V
110ns     1.721V     1.623V     1.275V
155.5ns   1.481V     1.62V      725mV
194.8ns   1.23V      1.606V     99.72mV
205.2ns   1.159V     1.598V     29.28mV
329.3ns   113.5mV    1.357V     4.391mV
345.2ns   42.97mV    1.314V     4.24mV
563.9ns   6.168mV    630.4mV    3.598mV
687.2ns   5.468mV    110.2mV    3.53mV
774ns     4.858mV    7.865mV    3.483mV
[Falling Waveform]
R_fixture = 50
V_fixture = 1.8
V_fixture_min = 1.62
V_fixture_max = 1.89
55.48ns   1.8V       1.62V      1.89V
137.8ns   1.719V     1.62V      1.249V
187.2ns   1.518V     1.619V     724mV
225.9ns   1.328V     1.613V     200.2mV
253.7ns   1.181V     1.602V     82.19mV
333.8ns   710.4mV    1.522V     45.88mV
396.9ns   234.7mV    1.418V     40.49mV
444.2ns   112.7mV    1.328V     38.56mV
898.3ns   51.52mV    232mV      35.17mV
1.296us   48.93mV    79.48mV    35.04mV
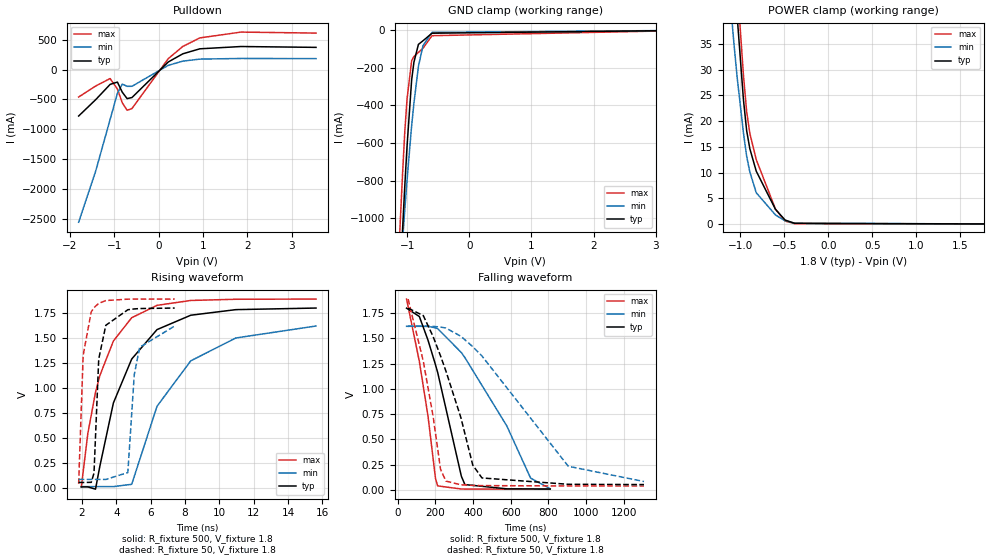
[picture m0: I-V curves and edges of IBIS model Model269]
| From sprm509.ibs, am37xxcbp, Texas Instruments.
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| Model based on original model for BQOMAPI2CHYFBPBRESNOPM_SSBHV
|   Sub model BQOMAPI2CHYRES_STD_PON_10_1P8
[model]   Model269
|[Input Load]   PU
|[Output Drive] LB10
|Voltage   1.8V
|Mode   I/O_OPEN_DRAIN
Model_type   I/O_open_drain
Polarity   Non-Inverting
Enable   Active-Low
Vinl =  0.567
Vinh =  1.323
Cref =  400.0000PF
Rref =  500.0000
Vref =  1.8V
Vmeas =  0.9
C_comp   3.856143p   3.721565p   3.857354p
[Model Spec]
Vinl   0.567   0.567   0.567
Vinh   1.323   1.323   1.323
[Temperature Range]   25   125   -40
[Voltage Range]   1.8   1.62   1.89
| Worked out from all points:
|   slope of the pulldown table from 0 to 0.27 V, typ, clamps not added: 1.71 ohm
|   GND clamp passes 1 mA (typ) near -0.44 V on its own axis
|   POWER clamp passes 1 mA (typ) near -0.51 V on its own axis
|   rising waveform, R_fixture 500, V_fixture 1.8: 20-80 % time 2.31ns typ, 3.14ns min, 1.76ns max; typ from 0.008 V to 1.8 V
|   rising waveform, R_fixture 50, V_fixture 1.8: 20-80 % time 345ps typ, 393ps min, 310ps max; typ from 0.052 V to 1.8 V
|   falling waveform, R_fixture 500, V_fixture 1.8: 20-80 % time 147ns typ, 293ns min, 92.6ns max; typ from 1.8 V to 0.008 V
|   falling waveform, R_fixture 50, V_fixture 1.8: 20-80 % time 174ns typ, 381ns min, 103ns max; typ from 1.8 V to 0.052 V
[POWER_clamp]
-1.8V     401.1mA    209.4mA    454.2mA
-1.145V   79.39mA    49.82mA    86.39mA
-1.073V   52.49mA    35.39mA    58.76mA
-1.036V   40.67mA    28.68mA    46.87mA
-963.6mV  24.19mA    17.73mA    28.97mA
-927.3mV  18.17mA    13.19mA    21.87mA
-890.9mV  14.63mA    10.1mA     17.61mA
-818.2mV  10.26mA    6.071mA    12.52mA
-600mV    2.834mA    1.747mA    2.888mA
-490.9mV  760.8uA    616.2uA    563.4uA
-381.8mV  112.8uA    147.2uA    57.34uA
1.764V    -11.66nA   -1.927uA   -18.08nA
[Pulldown]
-1.8V     -777.2mA   -2.558A    -458.6mA
-1.418V   -503.9mA   -1.705A    -274.5mA
-1.091V   -246.7mA   -833.5mA   -148.5mA
-927.3mV  -207.9mA   -396.6mA   -325.3mA
-818.2mV  -377.3mA   -241.3mA   -554.3mA
-709.1mV  -485.1mA   -279.3mA   -680.7mA
-600mV    -467.4mA   -278.5mA   -652.4mA
218.2mV   129.7mA    72.88mA    185.7mA
545.5mV   266.3mA    143.3mA    389.7mA
927.3mV   350mA      177.3mA    532.8mA
1.855V    388.5mA    188.2mA    630.6mA
3.545V    374.3mA    185.4mA    613.7mA
[GND_clamp]
-1.8V     -6.905A    -5.48A     -6.849A
-1.145V   -1.563A    -1.472A    -1.273A
-1.109V   -1.305A    -1.292A    -1.009A
-1.073V   -1.058A    -1.118A    -761.8mA
-1.036V   -819.4mA   -948.6mA   -530.3mA
-1V       -610.5mA   -793.2mA   -361.6mA
-927.3mV  -263.9mA   -507.2mA   -161.9mA
-890.9mV  -170.2mA   -389mA     -139.4mA
-818.2mV  -74.8mA    -191.7mA   -117.8mA
-745.5mV  -55.76mA   -81.74mA   -95.49mA
-600mV    -15.41mA   -10.81mA   -28.59mA
3.6V      0A         0A         0A
[Ramp]
dV/dt_f   1.078487/0.1470453u 0.96758751/0.29236613u   1.13451/92.988539n
dV/dt_r 0.48435886/2.3671977n   0.315813/3.2885739n 0.60383218/1.7769222n
R_load = 528.00
[Rising Waveform]
R_fixture = 500
V_fixture = 1.8
V_fixture_min = 1.62
V_fixture_max = 1.89
1.964ns   7.688mV    10.51mV    6.348mV
2.341ns   7.73mV     10.51mV    541.2mV
2.79ns    -15.18mV   10.51mV    956.1mV
3.041ns   213.3mV    10.51mV    1.123V
3.831ns   848.7mV    10.57mV    1.47V
4.897ns   1.289V     33.44mV    1.703V
6.371ns   1.584V     815.7mV    1.827V
8.335ns   1.728V     1.271V     1.876V
10.96ns   1.784V     1.5V       1.888V
15.63ns   1.8V       1.62V      1.89V
[Rising Waveform]
R_fixture = 50
V_fixture = 1.8
V_fixture_min = 1.62
V_fixture_max = 1.89
1.808ns   51.8mV     82.19mV    37.94mV
2.071ns   51.8mV     82.19mV    1.328V
2.542ns   53.17mV    82.19mV    1.762V
2.702ns   145.9mV    82.19mV    1.804V
2.977ns   1.289V     82.19mV    1.847V
3.39ns    1.627V     82.19mV    1.875V
4.672ns   1.783V     151.5mV    1.889V
5.047ns   1.791V     1.133V     1.89V
5.361ns   1.795V     1.407V     1.89V
7.399ns   1.8V       1.62V      1.89V
[Falling Waveform]
R_fixture = 500
V_fixture = 1.8
V_fixture_min = 1.62
V_fixture_max = 1.89
47.83ns   1.8V       1.62V      1.89V
115.6ns   1.717V     1.622V     1.272V
161.6ns   1.482V     1.619V     728.7mV
201.1ns   1.239V     1.605V     113.4mV
212.8ns   1.162V     1.597V     38.62mV
338.2ns   134.3mV    1.36V      7.898mV
357ns     51.87mV    1.31V      7.612mV
579.1ns   9.619mV    633.1mV    6.539mV
705.1ns   8.589mV    116.2mV    6.425mV
809.1ns   7.688mV    10.51mV    6.348mV
[Falling Waveform]
R_fixture = 50
V_fixture = 1.8
V_fixture_min = 1.62
V_fixture_max = 1.89
55.94ns   1.8V       1.62V      1.89V
136.5ns   1.726V     1.62V      1.274V
188.4ns   1.519V     1.619V     729.5mV
228ns     1.326V     1.613V     202.2mV
256.5ns   1.176V     1.602V     86.18mV
335.4ns   717mV      1.522V     49.64mV
398.8ns   244.3mV    1.418V     43.8mV
447.4ns   117.4mV    1.326V     41.69mV
905ns     54.48mV    233.2mV    38.07mV
1.306us   51.8mV     82.19mV    37.94mV
